VERSION 5.8 ;
BUSBITCHARS "[]" ;
DIVIDERCHAR "/" ;
UNITS
    DATABASE MICRONS 1000 ;
END UNITS

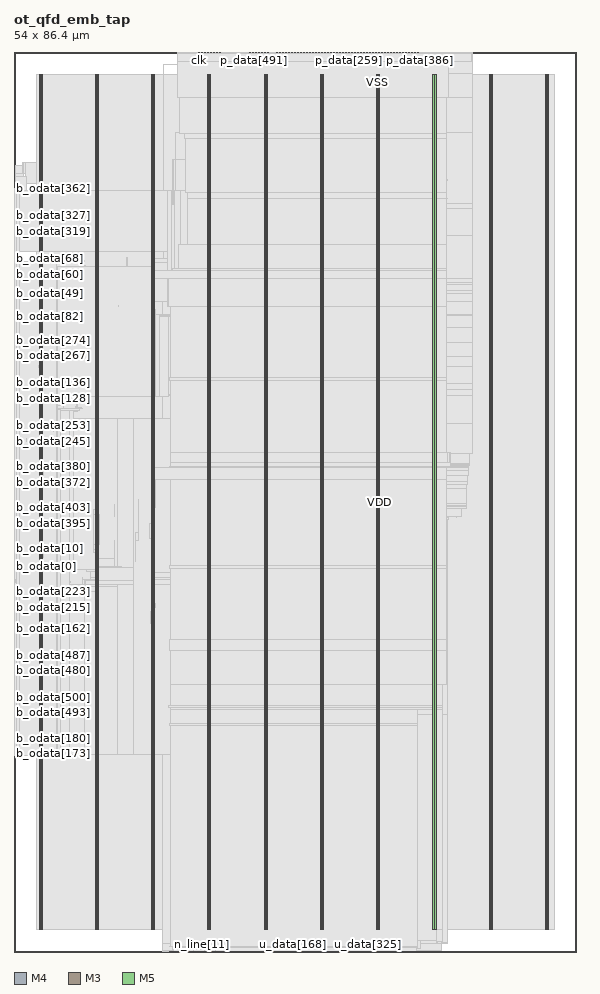
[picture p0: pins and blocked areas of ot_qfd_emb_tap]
MACRO ot_qfd_emb_tap
  FOREIGN ot_qfd_emb_tap 0 0 ;
  CLASS BLOCK ;
  SIZE 54 BY 86.4 ;
  PIN b_iaddr[0]
    DIRECTION OUTPUT ;
    USE SIGNAL ;
    PORT
      LAYER M4 ;
        RECT  0 34.992 0.084 35.016 ;
    END
  END b_iaddr[0]
  PIN b_iaddr[10]
    DIRECTION OUTPUT ;
    USE SIGNAL ;
    PORT
      LAYER M4 ;
        RECT  0 35.952 0.084 35.976 ;
    END
  END b_iaddr[10]
  PIN b_iaddr[11]
    DIRECTION OUTPUT ;
    USE SIGNAL ;
    PORT
      LAYER M4 ;
        RECT  0 36.048 0.084 36.072 ;
    END
  END b_iaddr[11]
  PIN b_iaddr[12]
    DIRECTION OUTPUT ;
    USE SIGNAL ;
    PORT
      LAYER M4 ;
        RECT  0 36.144 0.084 36.168 ;
    END
  END b_iaddr[12]
  PIN b_iaddr[13]
    DIRECTION OUTPUT ;
    USE SIGNAL ;
    PORT
      LAYER M4 ;
        RECT  0 36.24 0.084 36.264 ;
    END
  END b_iaddr[13]
  PIN b_iaddr[14]
    DIRECTION OUTPUT ;
    USE SIGNAL ;
    PORT
      LAYER M4 ;
        RECT  0 36.336 0.084 36.36 ;
    END
  END b_iaddr[14]
  PIN b_iaddr[15]
    DIRECTION OUTPUT ;
    USE SIGNAL ;
    PORT
      LAYER M4 ;
        RECT  0 36.432 0.084 36.456 ;
    END
  END b_iaddr[15]
  PIN b_iaddr[16]
    DIRECTION OUTPUT ;
    USE SIGNAL ;
    PORT
      LAYER M4 ;
        RECT  0 36.528 0.084 36.552 ;
    END
  END b_iaddr[16]
  PIN b_iaddr[17]
    DIRECTION OUTPUT ;
    USE SIGNAL ;
    PORT
      LAYER M4 ;
        RECT  0 36.624 0.084 36.648 ;
    END
  END b_iaddr[17]
  PIN b_iaddr[1]
    DIRECTION OUTPUT ;
    USE SIGNAL ;
    PORT
      LAYER M4 ;
        RECT  0 35.088 0.084 35.112 ;
    END
  END b_iaddr[1]
  PIN b_iaddr[2]
    DIRECTION OUTPUT ;
    USE SIGNAL ;
    PORT
      LAYER M4 ;
        RECT  0 35.184 0.084 35.208 ;
    END
  END b_iaddr[2]
  PIN b_iaddr[3]
    DIRECTION OUTPUT ;
    USE SIGNAL ;
    PORT
      LAYER M4 ;
        RECT  0 35.28 0.084 35.304 ;
    END
  END b_iaddr[3]
  PIN b_iaddr[4]
    DIRECTION OUTPUT ;
    USE SIGNAL ;
    PORT
      LAYER M4 ;
        RECT  0 35.376 0.084 35.4 ;
    END
  END b_iaddr[4]
  PIN b_iaddr[5]
    DIRECTION OUTPUT ;
    USE SIGNAL ;
    PORT
      LAYER M4 ;
        RECT  0 35.472 0.084 35.496 ;
    END
  END b_iaddr[5]
  PIN b_iaddr[6]
    DIRECTION OUTPUT ;
    USE SIGNAL ;
    PORT
      LAYER M4 ;
        RECT  0 35.568 0.084 35.592 ;
    END
  END b_iaddr[6]
  PIN b_iaddr[7]
    DIRECTION OUTPUT ;
    USE SIGNAL ;
    PORT
      LAYER M4 ;
        RECT  0 35.664 0.084 35.688 ;
    END
  END b_iaddr[7]
  PIN b_iaddr[8]
    DIRECTION OUTPUT ;
    USE SIGNAL ;
    PORT
      LAYER M4 ;
        RECT  0 35.76 0.084 35.784 ;
    END
  END b_iaddr[8]
  PIN b_iaddr[9]
    DIRECTION OUTPUT ;
    USE SIGNAL ;
    PORT
      LAYER M4 ;
        RECT  0 35.856 0.084 35.88 ;
    END
  END b_iaddr[9]
  PIN b_icr
    DIRECTION INPUT ;
    USE SIGNAL ;
    PORT
      LAYER M4 ;
        RECT  0 36.72 0.084 36.744 ;
    END
  END b_icr
  PIN b_iv
    DIRECTION OUTPUT ;
    USE SIGNAL ;
    PORT
      LAYER M4 ;
        RECT  0 36.816 0.084 36.84 ;
    END
  END b_iv
  PIN b_ocr
    DIRECTION OUTPUT ;
    USE SIGNAL ;
    PORT
      LAYER M4 ;
        RECT  0 36.912 0.084 36.936 ;
    END
  END b_ocr
  PIN b_odata[0]
    DIRECTION INPUT ;
    USE SIGNAL ;
    PORT
      LAYER M4 ;
        RECT  0 37.008 0.084 37.032 ;
    END
  END b_odata[0]
  PIN b_odata[100]
    DIRECTION INPUT ;
    USE SIGNAL ;
    PORT
      LAYER M4 ;
        RECT  0 62.736 0.084 62.76 ;
    END
  END b_odata[100]
  PIN b_odata[101]
    DIRECTION INPUT ;
    USE SIGNAL ;
    PORT
      LAYER M4 ;
        RECT  0 62.832 0.084 62.856 ;
    END
  END b_odata[101]
  PIN b_odata[102]
    DIRECTION INPUT ;
    USE SIGNAL ;
    PORT
      LAYER M4 ;
        RECT  0 62.928 0.084 62.952 ;
    END
  END b_odata[102]
  PIN b_odata[103]
    DIRECTION INPUT ;
    USE SIGNAL ;
    PORT
      LAYER M4 ;
        RECT  0 63.024 0.084 63.048 ;
    END
  END b_odata[103]
  PIN b_odata[104]
    DIRECTION INPUT ;
    USE SIGNAL ;
    PORT
      LAYER M4 ;
        RECT  0 63.12 0.084 63.144 ;
    END
  END b_odata[104]
  PIN b_odata[105]
    DIRECTION INPUT ;
    USE SIGNAL ;
    PORT
      LAYER M4 ;
        RECT  0 63.216 0.084 63.24 ;
    END
  END b_odata[105]
  PIN b_odata[106]
    DIRECTION INPUT ;
    USE SIGNAL ;
    PORT
      LAYER M4 ;
        RECT  0 63.312 0.084 63.336 ;
    END
  END b_odata[106]
  PIN b_odata[107]
    DIRECTION INPUT ;
    USE SIGNAL ;
    PORT
      LAYER M4 ;
        RECT  0 51.12 0.084 51.144 ;
    END
  END b_odata[107]
  PIN b_odata[108]
    DIRECTION INPUT ;
    USE SIGNAL ;
    PORT
      LAYER M4 ;
        RECT  0 51.216 0.084 51.24 ;
    END
  END b_odata[108]
  PIN b_odata[109]
    DIRECTION INPUT ;
    USE SIGNAL ;
    PORT
      LAYER M4 ;
        RECT  0 51.312 0.084 51.336 ;
    END
  END b_odata[109]
  PIN b_odata[10]
    DIRECTION INPUT ;
    USE SIGNAL ;
    PORT
      LAYER M4 ;
        RECT  0 37.968 0.084 37.992 ;
    END
  END b_odata[10]
  PIN b_odata[110]
    DIRECTION INPUT ;
    USE SIGNAL ;
    PORT
      LAYER M4 ;
        RECT  0 51.408 0.084 51.432 ;
    END
  END b_odata[110]
  PIN b_odata[111]
    DIRECTION INPUT ;
    USE SIGNAL ;
    PORT
      LAYER M4 ;
        RECT  0 51.504 0.084 51.528 ;
    END
  END b_odata[111]
  PIN b_odata[112]
    DIRECTION INPUT ;
    USE SIGNAL ;
    PORT
      LAYER M4 ;
        RECT  0 51.6 0.084 51.624 ;
    END
  END b_odata[112]
  PIN b_odata[113]
    DIRECTION INPUT ;
    USE SIGNAL ;
    PORT
      LAYER M4 ;
        RECT  0 51.696 0.084 51.72 ;
    END
  END b_odata[113]
  PIN b_odata[114]
    DIRECTION INPUT ;
    USE SIGNAL ;
    PORT
      LAYER M4 ;
        RECT  0 51.792 0.084 51.816 ;
    END
  END b_odata[114]
  PIN b_odata[115]
    DIRECTION INPUT ;
    USE SIGNAL ;
    PORT
      LAYER M4 ;
        RECT  0 51.888 0.084 51.912 ;
    END
  END b_odata[115]
  PIN b_odata[116]
    DIRECTION INPUT ;
    USE SIGNAL ;
    PORT
      LAYER M4 ;
        RECT  0 51.984 0.084 52.008 ;
    END
  END b_odata[116]
  PIN b_odata[117]
    DIRECTION INPUT ;
    USE SIGNAL ;
    PORT
      LAYER M4 ;
        RECT  0 52.08 0.084 52.104 ;
    END
  END b_odata[117]
  PIN b_odata[118]
    DIRECTION INPUT ;
    USE SIGNAL ;
    PORT
      LAYER M4 ;
        RECT  0 52.176 0.084 52.2 ;
    END
  END b_odata[118]
  PIN b_odata[119]
    DIRECTION INPUT ;
    USE SIGNAL ;
    PORT
      LAYER M4 ;
        RECT  0 52.272 0.084 52.296 ;
    END
  END b_odata[119]
  PIN b_odata[11]
    DIRECTION INPUT ;
    USE SIGNAL ;
    PORT
      LAYER M4 ;
        RECT  0 54.192 0.084 54.216 ;
    END
  END b_odata[11]
  PIN b_odata[120]
    DIRECTION INPUT ;
    USE SIGNAL ;
    PORT
      LAYER M4 ;
        RECT  0 52.368 0.084 52.392 ;
    END
  END b_odata[120]
  PIN b_odata[121]
    DIRECTION INPUT ;
    USE SIGNAL ;
    PORT
      LAYER M4 ;
        RECT  0 52.464 0.084 52.488 ;
    END
  END b_odata[121]
  PIN b_odata[122]
    DIRECTION INPUT ;
    USE SIGNAL ;
    PORT
      LAYER M4 ;
        RECT  0 52.56 0.084 52.584 ;
    END
  END b_odata[122]
  PIN b_odata[123]
    DIRECTION INPUT ;
    USE SIGNAL ;
    PORT
      LAYER M4 ;
        RECT  0 52.656 0.084 52.68 ;
    END
  END b_odata[123]
  PIN b_odata[124]
    DIRECTION INPUT ;
    USE SIGNAL ;
    PORT
      LAYER M4 ;
        RECT  0 52.752 0.084 52.776 ;
    END
  END b_odata[124]
  PIN b_odata[125]
    DIRECTION INPUT ;
    USE SIGNAL ;
    PORT
      LAYER M4 ;
        RECT  0 52.848 0.084 52.872 ;
    END
  END b_odata[125]
  PIN b_odata[126]
    DIRECTION INPUT ;
    USE SIGNAL ;
    PORT
      LAYER M4 ;
        RECT  0 52.944 0.084 52.968 ;
    END
  END b_odata[126]
  PIN b_odata[127]
    DIRECTION INPUT ;
    USE SIGNAL ;
    PORT
      LAYER M4 ;
        RECT  0 53.04 0.084 53.064 ;
    END
  END b_odata[127]
  PIN b_odata[128]
    DIRECTION INPUT ;
    USE SIGNAL ;
    PORT
      LAYER M4 ;
        RECT  0 53.136 0.084 53.16 ;
    END
  END b_odata[128]
  PIN b_odata[129]
    DIRECTION INPUT ;
    USE SIGNAL ;
    PORT
      LAYER M4 ;
        RECT  0 53.232 0.084 53.256 ;
    END
  END b_odata[129]
  PIN b_odata[12]
    DIRECTION INPUT ;
    USE SIGNAL ;
    PORT
      LAYER M4 ;
        RECT  0 54.288 0.084 54.312 ;
    END
  END b_odata[12]
  PIN b_odata[130]
    DIRECTION INPUT ;
    USE SIGNAL ;
    PORT
      LAYER M4 ;
        RECT  0 53.328 0.084 53.352 ;
    END
  END b_odata[130]
  PIN b_odata[131]
    DIRECTION INPUT ;
    USE SIGNAL ;
    PORT
      LAYER M4 ;
        RECT  0 53.424 0.084 53.448 ;
    END
  END b_odata[131]
  PIN b_odata[132]
    DIRECTION INPUT ;
    USE SIGNAL ;
    PORT
      LAYER M4 ;
        RECT  0 53.52 0.084 53.544 ;
    END
  END b_odata[132]
  PIN b_odata[133]
    DIRECTION INPUT ;
    USE SIGNAL ;
    PORT
      LAYER M4 ;
        RECT  0 53.616 0.084 53.64 ;
    END
  END b_odata[133]
  PIN b_odata[134]
    DIRECTION INPUT ;
    USE SIGNAL ;
    PORT
      LAYER M4 ;
        RECT  0 53.712 0.084 53.736 ;
    END
  END b_odata[134]
  PIN b_odata[135]
    DIRECTION INPUT ;
    USE SIGNAL ;
    PORT
      LAYER M4 ;
        RECT  0 53.808 0.084 53.832 ;
    END
  END b_odata[135]
  PIN b_odata[136]
    DIRECTION INPUT ;
    USE SIGNAL ;
    PORT
      LAYER M4 ;
        RECT  0 53.904 0.084 53.928 ;
    END
  END b_odata[136]
  PIN b_odata[137]
    DIRECTION INPUT ;
    USE SIGNAL ;
    PORT
      LAYER M4 ;
        RECT  0 54 0.084 54.024 ;
    END
  END b_odata[137]
  PIN b_odata[138]
    DIRECTION INPUT ;
    USE SIGNAL ;
    PORT
      LAYER M4 ;
        RECT  0 54.096 0.084 54.12 ;
    END
  END b_odata[138]
  PIN b_odata[139]
    DIRECTION INPUT ;
    USE SIGNAL ;
    PORT
      LAYER M4 ;
        RECT  0 28.848 0.084 28.872 ;
    END
  END b_odata[139]
  PIN b_odata[13]
    DIRECTION INPUT ;
    USE SIGNAL ;
    PORT
      LAYER M4 ;
        RECT  0 54.384 0.084 54.408 ;
    END
  END b_odata[13]
  PIN b_odata[140]
    DIRECTION INPUT ;
    USE SIGNAL ;
    PORT
      LAYER M4 ;
        RECT  0 28.944 0.084 28.968 ;
    END
  END b_odata[140]
  PIN b_odata[141]
    DIRECTION INPUT ;
    USE SIGNAL ;
    PORT
      LAYER M4 ;
        RECT  0 29.04 0.084 29.064 ;
    END
  END b_odata[141]
  PIN b_odata[142]
    DIRECTION INPUT ;
    USE SIGNAL ;
    PORT
      LAYER M4 ;
        RECT  0 29.136 0.084 29.16 ;
    END
  END b_odata[142]
  PIN b_odata[143]
    DIRECTION INPUT ;
    USE SIGNAL ;
    PORT
      LAYER M4 ;
        RECT  0 29.232 0.084 29.256 ;
    END
  END b_odata[143]
  PIN b_odata[144]
    DIRECTION INPUT ;
    USE SIGNAL ;
    PORT
      LAYER M4 ;
        RECT  0 29.328 0.084 29.352 ;
    END
  END b_odata[144]
  PIN b_odata[145]
    DIRECTION INPUT ;
    USE SIGNAL ;
    PORT
      LAYER M4 ;
        RECT  0 29.424 0.084 29.448 ;
    END
  END b_odata[145]
  PIN b_odata[146]
    DIRECTION INPUT ;
    USE SIGNAL ;
    PORT
      LAYER M4 ;
        RECT  0 29.52 0.084 29.544 ;
    END
  END b_odata[146]
  PIN b_odata[147]
    DIRECTION INPUT ;
    USE SIGNAL ;
    PORT
      LAYER M4 ;
        RECT  0 29.616 0.084 29.64 ;
    END
  END b_odata[147]
  PIN b_odata[148]
    DIRECTION INPUT ;
    USE SIGNAL ;
    PORT
      LAYER M4 ;
        RECT  0 29.712 0.084 29.736 ;
    END
  END b_odata[148]
  PIN b_odata[149]
    DIRECTION INPUT ;
    USE SIGNAL ;
    PORT
      LAYER M4 ;
        RECT  0 29.808 0.084 29.832 ;
    END
  END b_odata[149]
  PIN b_odata[14]
    DIRECTION INPUT ;
    USE SIGNAL ;
    PORT
      LAYER M4 ;
        RECT  0 54.48 0.084 54.504 ;
    END
  END b_odata[14]
  PIN b_odata[150]
    DIRECTION INPUT ;
    USE SIGNAL ;
    PORT
      LAYER M4 ;
        RECT  0 29.904 0.084 29.928 ;
    END
  END b_odata[150]
  PIN b_odata[151]
    DIRECTION INPUT ;
    USE SIGNAL ;
    PORT
      LAYER M4 ;
        RECT  0 30 0.084 30.024 ;
    END
  END b_odata[151]
  PIN b_odata[152]
    DIRECTION INPUT ;
    USE SIGNAL ;
    PORT
      LAYER M4 ;
        RECT  0 30.096 0.084 30.12 ;
    END
  END b_odata[152]
  PIN b_odata[153]
    DIRECTION INPUT ;
    USE SIGNAL ;
    PORT
      LAYER M4 ;
        RECT  0 30.192 0.084 30.216 ;
    END
  END b_odata[153]
  PIN b_odata[154]
    DIRECTION INPUT ;
    USE SIGNAL ;
    PORT
      LAYER M4 ;
        RECT  0 30.288 0.084 30.312 ;
    END
  END b_odata[154]
  PIN b_odata[155]
    DIRECTION INPUT ;
    USE SIGNAL ;
    PORT
      LAYER M4 ;
        RECT  0 30.384 0.084 30.408 ;
    END
  END b_odata[155]
  PIN b_odata[156]
    DIRECTION INPUT ;
    USE SIGNAL ;
    PORT
      LAYER M4 ;
        RECT  0 30.48 0.084 30.504 ;
    END
  END b_odata[156]
  PIN b_odata[157]
    DIRECTION INPUT ;
    USE SIGNAL ;
    PORT
      LAYER M4 ;
        RECT  0 30.576 0.084 30.6 ;
    END
  END b_odata[157]
  PIN b_odata[158]
    DIRECTION INPUT ;
    USE SIGNAL ;
    PORT
      LAYER M4 ;
        RECT  0 30.672 0.084 30.696 ;
    END
  END b_odata[158]
  PIN b_odata[159]
    DIRECTION INPUT ;
    USE SIGNAL ;
    PORT
      LAYER M4 ;
        RECT  0 30.768 0.084 30.792 ;
    END
  END b_odata[159]
  PIN b_odata[15]
    DIRECTION INPUT ;
    USE SIGNAL ;
    PORT
      LAYER M4 ;
        RECT  0 54.576 0.084 54.6 ;
    END
  END b_odata[15]
  PIN b_odata[160]
    DIRECTION INPUT ;
    USE SIGNAL ;
    PORT
      LAYER M4 ;
        RECT  0 30.864 0.084 30.888 ;
    END
  END b_odata[160]
  PIN b_odata[161]
    DIRECTION INPUT ;
    USE SIGNAL ;
    PORT
      LAYER M4 ;
        RECT  0 30.96 0.084 30.984 ;
    END
  END b_odata[161]
  PIN b_odata[162]
    DIRECTION INPUT ;
    USE SIGNAL ;
    PORT
      LAYER M4 ;
        RECT  0 31.056 0.084 31.08 ;
    END
  END b_odata[162]
  PIN b_odata[163]
    DIRECTION INPUT ;
    USE SIGNAL ;
    PORT
      LAYER M4 ;
        RECT  0 31.152 0.084 31.176 ;
    END
  END b_odata[163]
  PIN b_odata[164]
    DIRECTION INPUT ;
    USE SIGNAL ;
    PORT
      LAYER M4 ;
        RECT  0 31.248 0.084 31.272 ;
    END
  END b_odata[164]
  PIN b_odata[165]
    DIRECTION INPUT ;
    USE SIGNAL ;
    PORT
      LAYER M4 ;
        RECT  0 31.344 0.084 31.368 ;
    END
  END b_odata[165]
  PIN b_odata[166]
    DIRECTION INPUT ;
    USE SIGNAL ;
    PORT
      LAYER M4 ;
        RECT  0 31.44 0.084 31.464 ;
    END
  END b_odata[166]
  PIN b_odata[167]
    DIRECTION INPUT ;
    USE SIGNAL ;
    PORT
      LAYER M4 ;
        RECT  0 31.536 0.084 31.56 ;
    END
  END b_odata[167]
  PIN b_odata[168]
    DIRECTION INPUT ;
    USE SIGNAL ;
    PORT
      LAYER M4 ;
        RECT  0 31.632 0.084 31.656 ;
    END
  END b_odata[168]
  PIN b_odata[169]
    DIRECTION INPUT ;
    USE SIGNAL ;
    PORT
      LAYER M4 ;
        RECT  0 31.728 0.084 31.752 ;
    END
  END b_odata[169]
  PIN b_odata[16]
    DIRECTION INPUT ;
    USE SIGNAL ;
    PORT
      LAYER M4 ;
        RECT  0 54.672 0.084 54.696 ;
    END
  END b_odata[16]
  PIN b_odata[170]
    DIRECTION INPUT ;
    USE SIGNAL ;
    PORT
      LAYER M4 ;
        RECT  0 31.824 0.084 31.848 ;
    END
  END b_odata[170]
  PIN b_odata[171]
    DIRECTION INPUT ;
    USE SIGNAL ;
    PORT
      LAYER M4 ;
        RECT  0 18.864 0.084 18.888 ;
    END
  END b_odata[171]
  PIN b_odata[172]
    DIRECTION INPUT ;
    USE SIGNAL ;
    PORT
      LAYER M4 ;
        RECT  0 18.96 0.084 18.984 ;
    END
  END b_odata[172]
  PIN b_odata[173]
    DIRECTION INPUT ;
    USE SIGNAL ;
    PORT
      LAYER M4 ;
        RECT  0 19.056 0.084 19.08 ;
    END
  END b_odata[173]
  PIN b_odata[174]
    DIRECTION INPUT ;
    USE SIGNAL ;
    PORT
      LAYER M4 ;
        RECT  0 19.152 0.084 19.176 ;
    END
  END b_odata[174]
  PIN b_odata[175]
    DIRECTION INPUT ;
    USE SIGNAL ;
    PORT
      LAYER M4 ;
        RECT  0 19.248 0.084 19.272 ;
    END
  END b_odata[175]
  PIN b_odata[176]
    DIRECTION INPUT ;
    USE SIGNAL ;
    PORT
      LAYER M4 ;
        RECT  0 19.344 0.084 19.368 ;
    END
  END b_odata[176]
  PIN b_odata[177]
    DIRECTION INPUT ;
    USE SIGNAL ;
    PORT
      LAYER M4 ;
        RECT  0 19.44 0.084 19.464 ;
    END
  END b_odata[177]
  PIN b_odata[178]
    DIRECTION INPUT ;
    USE SIGNAL ;
    PORT
      LAYER M4 ;
        RECT  0 19.536 0.084 19.56 ;
    END
  END b_odata[178]
  PIN b_odata[179]
    DIRECTION INPUT ;
    USE SIGNAL ;
    PORT
      LAYER M4 ;
        RECT  0 19.632 0.084 19.656 ;
    END
  END b_odata[179]
  PIN b_odata[17]
    DIRECTION INPUT ;
    USE SIGNAL ;
    PORT
      LAYER M4 ;
        RECT  0 54.768 0.084 54.792 ;
    END
  END b_odata[17]
  PIN b_odata[180]
    DIRECTION INPUT ;
    USE SIGNAL ;
    PORT
      LAYER M4 ;
        RECT  0 19.728 0.084 19.752 ;
    END
  END b_odata[180]
  PIN b_odata[181]
    DIRECTION INPUT ;
    USE SIGNAL ;
    PORT
      LAYER M4 ;
        RECT  0 19.824 0.084 19.848 ;
    END
  END b_odata[181]
  PIN b_odata[182]
    DIRECTION INPUT ;
    USE SIGNAL ;
    PORT
      LAYER M4 ;
        RECT  0 19.92 0.084 19.944 ;
    END
  END b_odata[182]
  PIN b_odata[183]
    DIRECTION INPUT ;
    USE SIGNAL ;
    PORT
      LAYER M4 ;
        RECT  0 20.016 0.084 20.04 ;
    END
  END b_odata[183]
  PIN b_odata[184]
    DIRECTION INPUT ;
    USE SIGNAL ;
    PORT
      LAYER M4 ;
        RECT  0 20.112 0.084 20.136 ;
    END
  END b_odata[184]
  PIN b_odata[185]
    DIRECTION INPUT ;
    USE SIGNAL ;
    PORT
      LAYER M4 ;
        RECT  0 20.208 0.084 20.232 ;
    END
  END b_odata[185]
  PIN b_odata[186]
    DIRECTION INPUT ;
    USE SIGNAL ;
    PORT
      LAYER M4 ;
        RECT  0 20.304 0.084 20.328 ;
    END
  END b_odata[186]
  PIN b_odata[187]
    DIRECTION INPUT ;
    USE SIGNAL ;
    PORT
      LAYER M4 ;
        RECT  0 20.4 0.084 20.424 ;
    END
  END b_odata[187]
  PIN b_odata[188]
    DIRECTION INPUT ;
    USE SIGNAL ;
    PORT
      LAYER M4 ;
        RECT  0 20.496 0.084 20.52 ;
    END
  END b_odata[188]
  PIN b_odata[189]
    DIRECTION INPUT ;
    USE SIGNAL ;
    PORT
      LAYER M4 ;
        RECT  0 20.592 0.084 20.616 ;
    END
  END b_odata[189]
  PIN b_odata[18]
    DIRECTION INPUT ;
    USE SIGNAL ;
    PORT
      LAYER M4 ;
        RECT  0 54.864 0.084 54.888 ;
    END
  END b_odata[18]
  PIN b_odata[190]
    DIRECTION INPUT ;
    USE SIGNAL ;
    PORT
      LAYER M4 ;
        RECT  0 20.688 0.084 20.712 ;
    END
  END b_odata[190]
  PIN b_odata[191]
    DIRECTION INPUT ;
    USE SIGNAL ;
    PORT
      LAYER M4 ;
        RECT  0 20.784 0.084 20.808 ;
    END
  END b_odata[191]
  PIN b_odata[192]
    DIRECTION INPUT ;
    USE SIGNAL ;
    PORT
      LAYER M4 ;
        RECT  0 20.88 0.084 20.904 ;
    END
  END b_odata[192]
  PIN b_odata[193]
    DIRECTION INPUT ;
    USE SIGNAL ;
    PORT
      LAYER M4 ;
        RECT  0 20.976 0.084 21 ;
    END
  END b_odata[193]
  PIN b_odata[194]
    DIRECTION INPUT ;
    USE SIGNAL ;
    PORT
      LAYER M4 ;
        RECT  0 21.072 0.084 21.096 ;
    END
  END b_odata[194]
  PIN b_odata[195]
    DIRECTION INPUT ;
    USE SIGNAL ;
    PORT
      LAYER M4 ;
        RECT  0 21.168 0.084 21.192 ;
    END
  END b_odata[195]
  PIN b_odata[196]
    DIRECTION INPUT ;
    USE SIGNAL ;
    PORT
      LAYER M4 ;
        RECT  0 21.264 0.084 21.288 ;
    END
  END b_odata[196]
  PIN b_odata[197]
    DIRECTION INPUT ;
    USE SIGNAL ;
    PORT
      LAYER M4 ;
        RECT  0 21.36 0.084 21.384 ;
    END
  END b_odata[197]
  PIN b_odata[198]
    DIRECTION INPUT ;
    USE SIGNAL ;
    PORT
      LAYER M4 ;
        RECT  0 21.456 0.084 21.48 ;
    END
  END b_odata[198]
  PIN b_odata[199]
    DIRECTION INPUT ;
    USE SIGNAL ;
    PORT
      LAYER M4 ;
        RECT  0 21.552 0.084 21.576 ;
    END
  END b_odata[199]
  PIN b_odata[19]
    DIRECTION INPUT ;
    USE SIGNAL ;
    PORT
      LAYER M4 ;
        RECT  0 54.96 0.084 54.984 ;
    END
  END b_odata[19]
  PIN b_odata[1]
    DIRECTION INPUT ;
    USE SIGNAL ;
    PORT
      LAYER M4 ;
        RECT  0 37.104 0.084 37.128 ;
    END
  END b_odata[1]
  PIN b_odata[200]
    DIRECTION INPUT ;
    USE SIGNAL ;
    PORT
      LAYER M4 ;
        RECT  0 21.648 0.084 21.672 ;
    END
  END b_odata[200]
  PIN b_odata[201]
    DIRECTION INPUT ;
    USE SIGNAL ;
    PORT
      LAYER M4 ;
        RECT  0 21.744 0.084 21.768 ;
    END
  END b_odata[201]
  PIN b_odata[202]
    DIRECTION INPUT ;
    USE SIGNAL ;
    PORT
      LAYER M4 ;
        RECT  0 21.84 0.084 21.864 ;
    END
  END b_odata[202]
  PIN b_odata[203]
    DIRECTION INPUT ;
    USE SIGNAL ;
    PORT
      LAYER M4 ;
        RECT  0 31.92 0.084 31.944 ;
    END
  END b_odata[203]
  PIN b_odata[204]
    DIRECTION INPUT ;
    USE SIGNAL ;
    PORT
      LAYER M4 ;
        RECT  0 32.016 0.084 32.04 ;
    END
  END b_odata[204]
  PIN b_odata[205]
    DIRECTION INPUT ;
    USE SIGNAL ;
    PORT
      LAYER M4 ;
        RECT  0 32.112 0.084 32.136 ;
    END
  END b_odata[205]
  PIN b_odata[206]
    DIRECTION INPUT ;
    USE SIGNAL ;
    PORT
      LAYER M4 ;
        RECT  0 32.208 0.084 32.232 ;
    END
  END b_odata[206]
  PIN b_odata[207]
    DIRECTION INPUT ;
    USE SIGNAL ;
    PORT
      LAYER M4 ;
        RECT  0 32.304 0.084 32.328 ;
    END
  END b_odata[207]
  PIN b_odata[208]
    DIRECTION INPUT ;
    USE SIGNAL ;
    PORT
      LAYER M4 ;
        RECT  0 32.4 0.084 32.424 ;
    END
  END b_odata[208]
  PIN b_odata[209]
    DIRECTION INPUT ;
    USE SIGNAL ;
    PORT
      LAYER M4 ;
        RECT  0 32.496 0.084 32.52 ;
    END
  END b_odata[209]
  PIN b_odata[20]
    DIRECTION INPUT ;
    USE SIGNAL ;
    PORT
      LAYER M4 ;
        RECT  0 55.056 0.084 55.08 ;
    END
  END b_odata[20]
  PIN b_odata[210]
    DIRECTION INPUT ;
    USE SIGNAL ;
    PORT
      LAYER M4 ;
        RECT  0 32.592 0.084 32.616 ;
    END
  END b_odata[210]
  PIN b_odata[211]
    DIRECTION INPUT ;
    USE SIGNAL ;
    PORT
      LAYER M4 ;
        RECT  0 32.688 0.084 32.712 ;
    END
  END b_odata[211]
  PIN b_odata[212]
    DIRECTION INPUT ;
    USE SIGNAL ;
    PORT
      LAYER M4 ;
        RECT  0 32.784 0.084 32.808 ;
    END
  END b_odata[212]
  PIN b_odata[213]
    DIRECTION INPUT ;
    USE SIGNAL ;
    PORT
      LAYER M4 ;
        RECT  0 32.88 0.084 32.904 ;
    END
  END b_odata[213]
  PIN b_odata[214]
    DIRECTION INPUT ;
    USE SIGNAL ;
    PORT
      LAYER M4 ;
        RECT  0 32.976 0.084 33 ;
    END
  END b_odata[214]
  PIN b_odata[215]
    DIRECTION INPUT ;
    USE SIGNAL ;
    PORT
      LAYER M4 ;
        RECT  0 33.072 0.084 33.096 ;
    END
  END b_odata[215]
  PIN b_odata[216]
    DIRECTION INPUT ;
    USE SIGNAL ;
    PORT
      LAYER M4 ;
        RECT  0 33.168 0.084 33.192 ;
    END
  END b_odata[216]
  PIN b_odata[217]
    DIRECTION INPUT ;
    USE SIGNAL ;
    PORT
      LAYER M4 ;
        RECT  0 33.264 0.084 33.288 ;
    END
  END b_odata[217]
  PIN b_odata[218]
    DIRECTION INPUT ;
    USE SIGNAL ;
    PORT
      LAYER M4 ;
        RECT  0 33.36 0.084 33.384 ;
    END
  END b_odata[218]
  PIN b_odata[219]
    DIRECTION INPUT ;
    USE SIGNAL ;
    PORT
      LAYER M4 ;
        RECT  0 33.456 0.084 33.48 ;
    END
  END b_odata[219]
  PIN b_odata[21]
    DIRECTION INPUT ;
    USE SIGNAL ;
    PORT
      LAYER M4 ;
        RECT  0 55.152 0.084 55.176 ;
    END
  END b_odata[21]
  PIN b_odata[220]
    DIRECTION INPUT ;
    USE SIGNAL ;
    PORT
      LAYER M4 ;
        RECT  0 33.552 0.084 33.576 ;
    END
  END b_odata[220]
  PIN b_odata[221]
    DIRECTION INPUT ;
    USE SIGNAL ;
    PORT
      LAYER M4 ;
        RECT  0 33.648 0.084 33.672 ;
    END
  END b_odata[221]
  PIN b_odata[222]
    DIRECTION INPUT ;
    USE SIGNAL ;
    PORT
      LAYER M4 ;
        RECT  0 33.744 0.084 33.768 ;
    END
  END b_odata[222]
  PIN b_odata[223]
    DIRECTION INPUT ;
    USE SIGNAL ;
    PORT
      LAYER M4 ;
        RECT  0 33.84 0.084 33.864 ;
    END
  END b_odata[223]
  PIN b_odata[224]
    DIRECTION INPUT ;
    USE SIGNAL ;
    PORT
      LAYER M4 ;
        RECT  0 33.936 0.084 33.96 ;
    END
  END b_odata[224]
  PIN b_odata[225]
    DIRECTION INPUT ;
    USE SIGNAL ;
    PORT
      LAYER M4 ;
        RECT  0 34.032 0.084 34.056 ;
    END
  END b_odata[225]
  PIN b_odata[226]
    DIRECTION INPUT ;
    USE SIGNAL ;
    PORT
      LAYER M4 ;
        RECT  0 34.128 0.084 34.152 ;
    END
  END b_odata[226]
  PIN b_odata[227]
    DIRECTION INPUT ;
    USE SIGNAL ;
    PORT
      LAYER M4 ;
        RECT  0 34.224 0.084 34.248 ;
    END
  END b_odata[227]
  PIN b_odata[228]
    DIRECTION INPUT ;
    USE SIGNAL ;
    PORT
      LAYER M4 ;
        RECT  0 34.32 0.084 34.344 ;
    END
  END b_odata[228]
  PIN b_odata[229]
    DIRECTION INPUT ;
    USE SIGNAL ;
    PORT
      LAYER M4 ;
        RECT  0 34.416 0.084 34.44 ;
    END
  END b_odata[229]
  PIN b_odata[22]
    DIRECTION INPUT ;
    USE SIGNAL ;
    PORT
      LAYER M4 ;
        RECT  0 55.248 0.084 55.272 ;
    END
  END b_odata[22]
  PIN b_odata[230]
    DIRECTION INPUT ;
    USE SIGNAL ;
    PORT
      LAYER M4 ;
        RECT  0 34.512 0.084 34.536 ;
    END
  END b_odata[230]
  PIN b_odata[231]
    DIRECTION INPUT ;
    USE SIGNAL ;
    PORT
      LAYER M4 ;
        RECT  0 34.608 0.084 34.632 ;
    END
  END b_odata[231]
  PIN b_odata[232]
    DIRECTION INPUT ;
    USE SIGNAL ;
    PORT
      LAYER M4 ;
        RECT  0 34.704 0.084 34.728 ;
    END
  END b_odata[232]
  PIN b_odata[233]
    DIRECTION INPUT ;
    USE SIGNAL ;
    PORT
      LAYER M4 ;
        RECT  0 34.8 0.084 34.824 ;
    END
  END b_odata[233]
  PIN b_odata[234]
    DIRECTION INPUT ;
    USE SIGNAL ;
    PORT
      LAYER M4 ;
        RECT  0 34.896 0.084 34.92 ;
    END
  END b_odata[234]
  PIN b_odata[235]
    DIRECTION INPUT ;
    USE SIGNAL ;
    PORT
      LAYER M4 ;
        RECT  0 48.048 0.084 48.072 ;
    END
  END b_odata[235]
  PIN b_odata[236]
    DIRECTION INPUT ;
    USE SIGNAL ;
    PORT
      LAYER M4 ;
        RECT  0 48.144 0.084 48.168 ;
    END
  END b_odata[236]
  PIN b_odata[237]
    DIRECTION INPUT ;
    USE SIGNAL ;
    PORT
      LAYER M4 ;
        RECT  0 48.24 0.084 48.264 ;
    END
  END b_odata[237]
  PIN b_odata[238]
    DIRECTION INPUT ;
    USE SIGNAL ;
    PORT
      LAYER M4 ;
        RECT  0 48.336 0.084 48.36 ;
    END
  END b_odata[238]
  PIN b_odata[239]
    DIRECTION INPUT ;
    USE SIGNAL ;
    PORT
      LAYER M4 ;
        RECT  0 48.432 0.084 48.456 ;
    END
  END b_odata[239]
  PIN b_odata[23]
    DIRECTION INPUT ;
    USE SIGNAL ;
    PORT
      LAYER M4 ;
        RECT  0 55.344 0.084 55.368 ;
    END
  END b_odata[23]
  PIN b_odata[240]
    DIRECTION INPUT ;
    USE SIGNAL ;
    PORT
      LAYER M4 ;
        RECT  0 48.528 0.084 48.552 ;
    END
  END b_odata[240]
  PIN b_odata[241]
    DIRECTION INPUT ;
    USE SIGNAL ;
    PORT
      LAYER M4 ;
        RECT  0 48.624 0.084 48.648 ;
    END
  END b_odata[241]
  PIN b_odata[242]
    DIRECTION INPUT ;
    USE SIGNAL ;
    PORT
      LAYER M4 ;
        RECT  0 48.72 0.084 48.744 ;
    END
  END b_odata[242]
  PIN b_odata[243]
    DIRECTION INPUT ;
    USE SIGNAL ;
    PORT
      LAYER M4 ;
        RECT  0 48.816 0.084 48.84 ;
    END
  END b_odata[243]
  PIN b_odata[244]
    DIRECTION INPUT ;
    USE SIGNAL ;
    PORT
      LAYER M4 ;
        RECT  0 48.912 0.084 48.936 ;
    END
  END b_odata[244]
  PIN b_odata[245]
    DIRECTION INPUT ;
    USE SIGNAL ;
    PORT
      LAYER M4 ;
        RECT  0 49.008 0.084 49.032 ;
    END
  END b_odata[245]
  PIN b_odata[246]
    DIRECTION INPUT ;
    USE SIGNAL ;
    PORT
      LAYER M4 ;
        RECT  0 49.104 0.084 49.128 ;
    END
  END b_odata[246]
  PIN b_odata[247]
    DIRECTION INPUT ;
    USE SIGNAL ;
    PORT
      LAYER M4 ;
        RECT  0 49.2 0.084 49.224 ;
    END
  END b_odata[247]
  PIN b_odata[248]
    DIRECTION INPUT ;
    USE SIGNAL ;
    PORT
      LAYER M4 ;
        RECT  0 49.296 0.084 49.32 ;
    END
  END b_odata[248]
  PIN b_odata[249]
    DIRECTION INPUT ;
    USE SIGNAL ;
    PORT
      LAYER M4 ;
        RECT  0 49.392 0.084 49.416 ;
    END
  END b_odata[249]
  PIN b_odata[24]
    DIRECTION INPUT ;
    USE SIGNAL ;
    PORT
      LAYER M4 ;
        RECT  0 55.44 0.084 55.464 ;
    END
  END b_odata[24]
  PIN b_odata[250]
    DIRECTION INPUT ;
    USE SIGNAL ;
    PORT
      LAYER M4 ;
        RECT  0 49.488 0.084 49.512 ;
    END
  END b_odata[250]
  PIN b_odata[251]
    DIRECTION INPUT ;
    USE SIGNAL ;
    PORT
      LAYER M4 ;
        RECT  0 49.584 0.084 49.608 ;
    END
  END b_odata[251]
  PIN b_odata[252]
    DIRECTION INPUT ;
    USE SIGNAL ;
    PORT
      LAYER M4 ;
        RECT  0 49.68 0.084 49.704 ;
    END
  END b_odata[252]
  PIN b_odata[253]
    DIRECTION INPUT ;
    USE SIGNAL ;
    PORT
      LAYER M4 ;
        RECT  0 49.776 0.084 49.8 ;
    END
  END b_odata[253]
  PIN b_odata[254]
    DIRECTION INPUT ;
    USE SIGNAL ;
    PORT
      LAYER M4 ;
        RECT  0 49.872 0.084 49.896 ;
    END
  END b_odata[254]
  PIN b_odata[255]
    DIRECTION INPUT ;
    USE SIGNAL ;
    PORT
      LAYER M4 ;
        RECT  0 49.968 0.084 49.992 ;
    END
  END b_odata[255]
  PIN b_odata[256]
    DIRECTION INPUT ;
    USE SIGNAL ;
    PORT
      LAYER M4 ;
        RECT  0 50.064 0.084 50.088 ;
    END
  END b_odata[256]
  PIN b_odata[257]
    DIRECTION INPUT ;
    USE SIGNAL ;
    PORT
      LAYER M4 ;
        RECT  0 50.16 0.084 50.184 ;
    END
  END b_odata[257]
  PIN b_odata[258]
    DIRECTION INPUT ;
    USE SIGNAL ;
    PORT
      LAYER M4 ;
        RECT  0 50.256 0.084 50.28 ;
    END
  END b_odata[258]
  PIN b_odata[259]
    DIRECTION INPUT ;
    USE SIGNAL ;
    PORT
      LAYER M4 ;
        RECT  0 50.352 0.084 50.376 ;
    END
  END b_odata[259]
  PIN b_odata[25]
    DIRECTION INPUT ;
    USE SIGNAL ;
    PORT
      LAYER M4 ;
        RECT  0 55.536 0.084 55.56 ;
    END
  END b_odata[25]
  PIN b_odata[260]
    DIRECTION INPUT ;
    USE SIGNAL ;
    PORT
      LAYER M4 ;
        RECT  0 50.448 0.084 50.472 ;
    END
  END b_odata[260]
  PIN b_odata[261]
    DIRECTION INPUT ;
    USE SIGNAL ;
    PORT
      LAYER M4 ;
        RECT  0 50.544 0.084 50.568 ;
    END
  END b_odata[261]
  PIN b_odata[262]
    DIRECTION INPUT ;
    USE SIGNAL ;
    PORT
      LAYER M4 ;
        RECT  0 50.64 0.084 50.664 ;
    END
  END b_odata[262]
  PIN b_odata[263]
    DIRECTION INPUT ;
    USE SIGNAL ;
    PORT
      LAYER M4 ;
        RECT  0 50.736 0.084 50.76 ;
    END
  END b_odata[263]
  PIN b_odata[264]
    DIRECTION INPUT ;
    USE SIGNAL ;
    PORT
      LAYER M4 ;
        RECT  0 50.832 0.084 50.856 ;
    END
  END b_odata[264]
  PIN b_odata[265]
    DIRECTION INPUT ;
    USE SIGNAL ;
    PORT
      LAYER M4 ;
        RECT  0 50.928 0.084 50.952 ;
    END
  END b_odata[265]
  PIN b_odata[266]
    DIRECTION INPUT ;
    USE SIGNAL ;
    PORT
      LAYER M4 ;
        RECT  0 51.024 0.084 51.048 ;
    END
  END b_odata[266]
  PIN b_odata[267]
    DIRECTION INPUT ;
    USE SIGNAL ;
    PORT
      LAYER M4 ;
        RECT  0 57.264 0.084 57.288 ;
    END
  END b_odata[267]
  PIN b_odata[268]
    DIRECTION INPUT ;
    USE SIGNAL ;
    PORT
      LAYER M4 ;
        RECT  0 57.36 0.084 57.384 ;
    END
  END b_odata[268]
  PIN b_odata[269]
    DIRECTION INPUT ;
    USE SIGNAL ;
    PORT
      LAYER M4 ;
        RECT  0 57.456 0.084 57.48 ;
    END
  END b_odata[269]
  PIN b_odata[26]
    DIRECTION INPUT ;
    USE SIGNAL ;
    PORT
      LAYER M4 ;
        RECT  0 55.632 0.084 55.656 ;
    END
  END b_odata[26]
  PIN b_odata[270]
    DIRECTION INPUT ;
    USE SIGNAL ;
    PORT
      LAYER M4 ;
        RECT  0 57.552 0.084 57.576 ;
    END
  END b_odata[270]
  PIN b_odata[271]
    DIRECTION INPUT ;
    USE SIGNAL ;
    PORT
      LAYER M4 ;
        RECT  0 57.648 0.084 57.672 ;
    END
  END b_odata[271]
  PIN b_odata[272]
    DIRECTION INPUT ;
    USE SIGNAL ;
    PORT
      LAYER M4 ;
        RECT  0 57.744 0.084 57.768 ;
    END
  END b_odata[272]
  PIN b_odata[273]
    DIRECTION INPUT ;
    USE SIGNAL ;
    PORT
      LAYER M4 ;
        RECT  0 57.84 0.084 57.864 ;
    END
  END b_odata[273]
  PIN b_odata[274]
    DIRECTION INPUT ;
    USE SIGNAL ;
    PORT
      LAYER M4 ;
        RECT  0 57.936 0.084 57.96 ;
    END
  END b_odata[274]
  PIN b_odata[275]
    DIRECTION INPUT ;
    USE SIGNAL ;
    PORT
      LAYER M4 ;
        RECT  0 58.032 0.084 58.056 ;
    END
  END b_odata[275]
  PIN b_odata[276]
    DIRECTION INPUT ;
    USE SIGNAL ;
    PORT
      LAYER M4 ;
        RECT  0 58.128 0.084 58.152 ;
    END
  END b_odata[276]
  PIN b_odata[277]
    DIRECTION INPUT ;
    USE SIGNAL ;
    PORT
      LAYER M4 ;
        RECT  0 58.224 0.084 58.248 ;
    END
  END b_odata[277]
  PIN b_odata[278]
    DIRECTION INPUT ;
    USE SIGNAL ;
    PORT
      LAYER M4 ;
        RECT  0 58.32 0.084 58.344 ;
    END
  END b_odata[278]
  PIN b_odata[279]
    DIRECTION INPUT ;
    USE SIGNAL ;
    PORT
      LAYER M4 ;
        RECT  0 58.416 0.084 58.44 ;
    END
  END b_odata[279]
  PIN b_odata[27]
    DIRECTION INPUT ;
    USE SIGNAL ;
    PORT
      LAYER M4 ;
        RECT  0 55.728 0.084 55.752 ;
    END
  END b_odata[27]
  PIN b_odata[280]
    DIRECTION INPUT ;
    USE SIGNAL ;
    PORT
      LAYER M4 ;
        RECT  0 58.512 0.084 58.536 ;
    END
  END b_odata[280]
  PIN b_odata[281]
    DIRECTION INPUT ;
    USE SIGNAL ;
    PORT
      LAYER M4 ;
        RECT  0 58.608 0.084 58.632 ;
    END
  END b_odata[281]
  PIN b_odata[282]
    DIRECTION INPUT ;
    USE SIGNAL ;
    PORT
      LAYER M4 ;
        RECT  0 58.704 0.084 58.728 ;
    END
  END b_odata[282]
  PIN b_odata[283]
    DIRECTION INPUT ;
    USE SIGNAL ;
    PORT
      LAYER M4 ;
        RECT  0 58.8 0.084 58.824 ;
    END
  END b_odata[283]
  PIN b_odata[284]
    DIRECTION INPUT ;
    USE SIGNAL ;
    PORT
      LAYER M4 ;
        RECT  0 58.896 0.084 58.92 ;
    END
  END b_odata[284]
  PIN b_odata[285]
    DIRECTION INPUT ;
    USE SIGNAL ;
    PORT
      LAYER M4 ;
        RECT  0 58.992 0.084 59.016 ;
    END
  END b_odata[285]
  PIN b_odata[286]
    DIRECTION INPUT ;
    USE SIGNAL ;
    PORT
      LAYER M4 ;
        RECT  0 59.088 0.084 59.112 ;
    END
  END b_odata[286]
  PIN b_odata[287]
    DIRECTION INPUT ;
    USE SIGNAL ;
    PORT
      LAYER M4 ;
        RECT  0 59.184 0.084 59.208 ;
    END
  END b_odata[287]
  PIN b_odata[288]
    DIRECTION INPUT ;
    USE SIGNAL ;
    PORT
      LAYER M4 ;
        RECT  0 59.28 0.084 59.304 ;
    END
  END b_odata[288]
  PIN b_odata[289]
    DIRECTION INPUT ;
    USE SIGNAL ;
    PORT
      LAYER M4 ;
        RECT  0 59.376 0.084 59.4 ;
    END
  END b_odata[289]
  PIN b_odata[28]
    DIRECTION INPUT ;
    USE SIGNAL ;
    PORT
      LAYER M4 ;
        RECT  0 55.824 0.084 55.848 ;
    END
  END b_odata[28]
  PIN b_odata[290]
    DIRECTION INPUT ;
    USE SIGNAL ;
    PORT
      LAYER M4 ;
        RECT  0 59.472 0.084 59.496 ;
    END
  END b_odata[290]
  PIN b_odata[291]
    DIRECTION INPUT ;
    USE SIGNAL ;
    PORT
      LAYER M4 ;
        RECT  0 59.568 0.084 59.592 ;
    END
  END b_odata[291]
  PIN b_odata[292]
    DIRECTION INPUT ;
    USE SIGNAL ;
    PORT
      LAYER M4 ;
        RECT  0 59.664 0.084 59.688 ;
    END
  END b_odata[292]
  PIN b_odata[293]
    DIRECTION INPUT ;
    USE SIGNAL ;
    PORT
      LAYER M4 ;
        RECT  0 59.76 0.084 59.784 ;
    END
  END b_odata[293]
  PIN b_odata[294]
    DIRECTION INPUT ;
    USE SIGNAL ;
    PORT
      LAYER M4 ;
        RECT  0 59.856 0.084 59.88 ;
    END
  END b_odata[294]
  PIN b_odata[295]
    DIRECTION INPUT ;
    USE SIGNAL ;
    PORT
      LAYER M4 ;
        RECT  0 59.952 0.084 59.976 ;
    END
  END b_odata[295]
  PIN b_odata[296]
    DIRECTION INPUT ;
    USE SIGNAL ;
    PORT
      LAYER M4 ;
        RECT  0 60.048 0.084 60.072 ;
    END
  END b_odata[296]
  PIN b_odata[297]
    DIRECTION INPUT ;
    USE SIGNAL ;
    PORT
      LAYER M4 ;
        RECT  0 60.144 0.084 60.168 ;
    END
  END b_odata[297]
  PIN b_odata[298]
    DIRECTION INPUT ;
    USE SIGNAL ;
    PORT
      LAYER M4 ;
        RECT  0 60.24 0.084 60.264 ;
    END
  END b_odata[298]
  PIN b_odata[299]
    DIRECTION INPUT ;
    USE SIGNAL ;
    PORT
      LAYER M4 ;
        RECT  0 67.248 0.084 67.272 ;
    END
  END b_odata[299]
  PIN b_odata[29]
    DIRECTION INPUT ;
    USE SIGNAL ;
    PORT
      LAYER M4 ;
        RECT  0 55.92 0.084 55.944 ;
    END
  END b_odata[29]
  PIN b_odata[2]
    DIRECTION INPUT ;
    USE SIGNAL ;
    PORT
      LAYER M4 ;
        RECT  0 37.2 0.084 37.224 ;
    END
  END b_odata[2]
  PIN b_odata[300]
    DIRECTION INPUT ;
    USE SIGNAL ;
    PORT
      LAYER M4 ;
        RECT  0 67.344 0.084 67.368 ;
    END
  END b_odata[300]
  PIN b_odata[301]
    DIRECTION INPUT ;
    USE SIGNAL ;
    PORT
      LAYER M4 ;
        RECT  0 67.44 0.084 67.464 ;
    END
  END b_odata[301]
  PIN b_odata[302]
    DIRECTION INPUT ;
    USE SIGNAL ;
    PORT
      LAYER M4 ;
        RECT  0 67.536 0.084 67.56 ;
    END
  END b_odata[302]
  PIN b_odata[303]
    DIRECTION INPUT ;
    USE SIGNAL ;
    PORT
      LAYER M4 ;
        RECT  0 67.632 0.084 67.656 ;
    END
  END b_odata[303]
  PIN b_odata[304]
    DIRECTION INPUT ;
    USE SIGNAL ;
    PORT
      LAYER M4 ;
        RECT  0 67.728 0.084 67.752 ;
    END
  END b_odata[304]
  PIN b_odata[305]
    DIRECTION INPUT ;
    USE SIGNAL ;
    PORT
      LAYER M4 ;
        RECT  0 67.824 0.084 67.848 ;
    END
  END b_odata[305]
  PIN b_odata[306]
    DIRECTION INPUT ;
    USE SIGNAL ;
    PORT
      LAYER M4 ;
        RECT  0 67.92 0.084 67.944 ;
    END
  END b_odata[306]
  PIN b_odata[307]
    DIRECTION INPUT ;
    USE SIGNAL ;
    PORT
      LAYER M4 ;
        RECT  0 68.016 0.084 68.04 ;
    END
  END b_odata[307]
  PIN b_odata[308]
    DIRECTION INPUT ;
    USE SIGNAL ;
    PORT
      LAYER M4 ;
        RECT  0 68.112 0.084 68.136 ;
    END
  END b_odata[308]
  PIN b_odata[309]
    DIRECTION INPUT ;
    USE SIGNAL ;
    PORT
      LAYER M4 ;
        RECT  0 68.208 0.084 68.232 ;
    END
  END b_odata[309]
  PIN b_odata[30]
    DIRECTION INPUT ;
    USE SIGNAL ;
    PORT
      LAYER M4 ;
        RECT  0 56.016 0.084 56.04 ;
    END
  END b_odata[30]
  PIN b_odata[310]
    DIRECTION INPUT ;
    USE SIGNAL ;
    PORT
      LAYER M4 ;
        RECT  0 68.304 0.084 68.328 ;
    END
  END b_odata[310]
  PIN b_odata[311]
    DIRECTION INPUT ;
    USE SIGNAL ;
    PORT
      LAYER M4 ;
        RECT  0 68.4 0.084 68.424 ;
    END
  END b_odata[311]
  PIN b_odata[312]
    DIRECTION INPUT ;
    USE SIGNAL ;
    PORT
      LAYER M4 ;
        RECT  0 68.496 0.084 68.52 ;
    END
  END b_odata[312]
  PIN b_odata[313]
    DIRECTION INPUT ;
    USE SIGNAL ;
    PORT
      LAYER M4 ;
        RECT  0 68.592 0.084 68.616 ;
    END
  END b_odata[313]
  PIN b_odata[314]
    DIRECTION INPUT ;
    USE SIGNAL ;
    PORT
      LAYER M4 ;
        RECT  0 68.688 0.084 68.712 ;
    END
  END b_odata[314]
  PIN b_odata[315]
    DIRECTION INPUT ;
    USE SIGNAL ;
    PORT
      LAYER M4 ;
        RECT  0 68.784 0.084 68.808 ;
    END
  END b_odata[315]
  PIN b_odata[316]
    DIRECTION INPUT ;
    USE SIGNAL ;
    PORT
      LAYER M4 ;
        RECT  0 68.88 0.084 68.904 ;
    END
  END b_odata[316]
  PIN b_odata[317]
    DIRECTION INPUT ;
    USE SIGNAL ;
    PORT
      LAYER M4 ;
        RECT  0 68.976 0.084 69 ;
    END
  END b_odata[317]
  PIN b_odata[318]
    DIRECTION INPUT ;
    USE SIGNAL ;
    PORT
      LAYER M4 ;
        RECT  0 69.072 0.084 69.096 ;
    END
  END b_odata[318]
  PIN b_odata[319]
    DIRECTION INPUT ;
    USE SIGNAL ;
    PORT
      LAYER M4 ;
        RECT  0 69.168 0.084 69.192 ;
    END
  END b_odata[319]
  PIN b_odata[31]
    DIRECTION INPUT ;
    USE SIGNAL ;
    PORT
      LAYER M4 ;
        RECT  0 56.112 0.084 56.136 ;
    END
  END b_odata[31]
  PIN b_odata[320]
    DIRECTION INPUT ;
    USE SIGNAL ;
    PORT
      LAYER M4 ;
        RECT  0 69.264 0.084 69.288 ;
    END
  END b_odata[320]
  PIN b_odata[321]
    DIRECTION INPUT ;
    USE SIGNAL ;
    PORT
      LAYER M4 ;
        RECT  0 69.36 0.084 69.384 ;
    END
  END b_odata[321]
  PIN b_odata[322]
    DIRECTION INPUT ;
    USE SIGNAL ;
    PORT
      LAYER M4 ;
        RECT  0 69.456 0.084 69.48 ;
    END
  END b_odata[322]
  PIN b_odata[323]
    DIRECTION INPUT ;
    USE SIGNAL ;
    PORT
      LAYER M4 ;
        RECT  0 69.552 0.084 69.576 ;
    END
  END b_odata[323]
  PIN b_odata[324]
    DIRECTION INPUT ;
    USE SIGNAL ;
    PORT
      LAYER M4 ;
        RECT  0 69.648 0.084 69.672 ;
    END
  END b_odata[324]
  PIN b_odata[325]
    DIRECTION INPUT ;
    USE SIGNAL ;
    PORT
      LAYER M4 ;
        RECT  0 69.744 0.084 69.768 ;
    END
  END b_odata[325]
  PIN b_odata[326]
    DIRECTION INPUT ;
    USE SIGNAL ;
    PORT
      LAYER M4 ;
        RECT  0 69.84 0.084 69.864 ;
    END
  END b_odata[326]
  PIN b_odata[327]
    DIRECTION INPUT ;
    USE SIGNAL ;
    PORT
      LAYER M4 ;
        RECT  0 69.936 0.084 69.96 ;
    END
  END b_odata[327]
  PIN b_odata[328]
    DIRECTION INPUT ;
    USE SIGNAL ;
    PORT
      LAYER M4 ;
        RECT  0 70.032 0.084 70.056 ;
    END
  END b_odata[328]
  PIN b_odata[329]
    DIRECTION INPUT ;
    USE SIGNAL ;
    PORT
      LAYER M4 ;
        RECT  0 70.128 0.084 70.152 ;
    END
  END b_odata[329]
  PIN b_odata[32]
    DIRECTION INPUT ;
    USE SIGNAL ;
    PORT
      LAYER M4 ;
        RECT  0 56.208 0.084 56.232 ;
    END
  END b_odata[32]
  PIN b_odata[330]
    DIRECTION INPUT ;
    USE SIGNAL ;
    PORT
      LAYER M4 ;
        RECT  0 70.224 0.084 70.248 ;
    END
  END b_odata[330]
  PIN b_odata[331]
    DIRECTION INPUT ;
    USE SIGNAL ;
    PORT
      LAYER M4 ;
        RECT  0 70.32 0.084 70.344 ;
    END
  END b_odata[331]
  PIN b_odata[332]
    DIRECTION INPUT ;
    USE SIGNAL ;
    PORT
      LAYER M4 ;
        RECT  0 70.416 0.084 70.44 ;
    END
  END b_odata[332]
  PIN b_odata[333]
    DIRECTION INPUT ;
    USE SIGNAL ;
    PORT
      LAYER M4 ;
        RECT  0 70.512 0.084 70.536 ;
    END
  END b_odata[333]
  PIN b_odata[334]
    DIRECTION INPUT ;
    USE SIGNAL ;
    PORT
      LAYER M4 ;
        RECT  0 70.608 0.084 70.632 ;
    END
  END b_odata[334]
  PIN b_odata[335]
    DIRECTION INPUT ;
    USE SIGNAL ;
    PORT
      LAYER M4 ;
        RECT  0 70.704 0.084 70.728 ;
    END
  END b_odata[335]
  PIN b_odata[336]
    DIRECTION INPUT ;
    USE SIGNAL ;
    PORT
      LAYER M4 ;
        RECT  0 70.8 0.084 70.824 ;
    END
  END b_odata[336]
  PIN b_odata[337]
    DIRECTION INPUT ;
    USE SIGNAL ;
    PORT
      LAYER M4 ;
        RECT  0 70.896 0.084 70.92 ;
    END
  END b_odata[337]
  PIN b_odata[338]
    DIRECTION INPUT ;
    USE SIGNAL ;
    PORT
      LAYER M4 ;
        RECT  0 70.992 0.084 71.016 ;
    END
  END b_odata[338]
  PIN b_odata[339]
    DIRECTION INPUT ;
    USE SIGNAL ;
    PORT
      LAYER M4 ;
        RECT  0 71.088 0.084 71.112 ;
    END
  END b_odata[339]
  PIN b_odata[33]
    DIRECTION INPUT ;
    USE SIGNAL ;
    PORT
      LAYER M4 ;
        RECT  0 56.304 0.084 56.328 ;
    END
  END b_odata[33]
  PIN b_odata[340]
    DIRECTION INPUT ;
    USE SIGNAL ;
    PORT
      LAYER M4 ;
        RECT  0 71.184 0.084 71.208 ;
    END
  END b_odata[340]
  PIN b_odata[341]
    DIRECTION INPUT ;
    USE SIGNAL ;
    PORT
      LAYER M4 ;
        RECT  0 71.28 0.084 71.304 ;
    END
  END b_odata[341]
  PIN b_odata[342]
    DIRECTION INPUT ;
    USE SIGNAL ;
    PORT
      LAYER M4 ;
        RECT  0 71.376 0.084 71.4 ;
    END
  END b_odata[342]
  PIN b_odata[343]
    DIRECTION INPUT ;
    USE SIGNAL ;
    PORT
      LAYER M4 ;
        RECT  0 71.472 0.084 71.496 ;
    END
  END b_odata[343]
  PIN b_odata[344]
    DIRECTION INPUT ;
    USE SIGNAL ;
    PORT
      LAYER M4 ;
        RECT  0 71.568 0.084 71.592 ;
    END
  END b_odata[344]
  PIN b_odata[345]
    DIRECTION INPUT ;
    USE SIGNAL ;
    PORT
      LAYER M4 ;
        RECT  0 71.664 0.084 71.688 ;
    END
  END b_odata[345]
  PIN b_odata[346]
    DIRECTION INPUT ;
    USE SIGNAL ;
    PORT
      LAYER M4 ;
        RECT  0 71.76 0.084 71.784 ;
    END
  END b_odata[346]
  PIN b_odata[347]
    DIRECTION INPUT ;
    USE SIGNAL ;
    PORT
      LAYER M4 ;
        RECT  0 71.856 0.084 71.88 ;
    END
  END b_odata[347]
  PIN b_odata[348]
    DIRECTION INPUT ;
    USE SIGNAL ;
    PORT
      LAYER M4 ;
        RECT  0 71.952 0.084 71.976 ;
    END
  END b_odata[348]
  PIN b_odata[349]
    DIRECTION INPUT ;
    USE SIGNAL ;
    PORT
      LAYER M4 ;
        RECT  0 72.048 0.084 72.072 ;
    END
  END b_odata[349]
  PIN b_odata[34]
    DIRECTION INPUT ;
    USE SIGNAL ;
    PORT
      LAYER M4 ;
        RECT  0 56.4 0.084 56.424 ;
    END
  END b_odata[34]
  PIN b_odata[350]
    DIRECTION INPUT ;
    USE SIGNAL ;
    PORT
      LAYER M4 ;
        RECT  0 72.144 0.084 72.168 ;
    END
  END b_odata[350]
  PIN b_odata[351]
    DIRECTION INPUT ;
    USE SIGNAL ;
    PORT
      LAYER M4 ;
        RECT  0 72.24 0.084 72.264 ;
    END
  END b_odata[351]
  PIN b_odata[352]
    DIRECTION INPUT ;
    USE SIGNAL ;
    PORT
      LAYER M4 ;
        RECT  0 72.336 0.084 72.36 ;
    END
  END b_odata[352]
  PIN b_odata[353]
    DIRECTION INPUT ;
    USE SIGNAL ;
    PORT
      LAYER M4 ;
        RECT  0 72.432 0.084 72.456 ;
    END
  END b_odata[353]
  PIN b_odata[354]
    DIRECTION INPUT ;
    USE SIGNAL ;
    PORT
      LAYER M4 ;
        RECT  0 72.528 0.084 72.552 ;
    END
  END b_odata[354]
  PIN b_odata[355]
    DIRECTION INPUT ;
    USE SIGNAL ;
    PORT
      LAYER M4 ;
        RECT  0 72.624 0.084 72.648 ;
    END
  END b_odata[355]
  PIN b_odata[356]
    DIRECTION INPUT ;
    USE SIGNAL ;
    PORT
      LAYER M4 ;
        RECT  0 72.72 0.084 72.744 ;
    END
  END b_odata[356]
  PIN b_odata[357]
    DIRECTION INPUT ;
    USE SIGNAL ;
    PORT
      LAYER M4 ;
        RECT  0 72.816 0.084 72.84 ;
    END
  END b_odata[357]
  PIN b_odata[358]
    DIRECTION INPUT ;
    USE SIGNAL ;
    PORT
      LAYER M4 ;
        RECT  0 72.912 0.084 72.936 ;
    END
  END b_odata[358]
  PIN b_odata[359]
    DIRECTION INPUT ;
    USE SIGNAL ;
    PORT
      LAYER M4 ;
        RECT  0 73.008 0.084 73.032 ;
    END
  END b_odata[359]
  PIN b_odata[35]
    DIRECTION INPUT ;
    USE SIGNAL ;
    PORT
      LAYER M4 ;
        RECT  0 56.496 0.084 56.52 ;
    END
  END b_odata[35]
  PIN b_odata[360]
    DIRECTION INPUT ;
    USE SIGNAL ;
    PORT
      LAYER M4 ;
        RECT  0 73.104 0.084 73.128 ;
    END
  END b_odata[360]
  PIN b_odata[361]
    DIRECTION INPUT ;
    USE SIGNAL ;
    PORT
      LAYER M4 ;
        RECT  0 73.2 0.084 73.224 ;
    END
  END b_odata[361]
  PIN b_odata[362]
    DIRECTION INPUT ;
    USE SIGNAL ;
    PORT
      LAYER M4 ;
        RECT  0 73.296 0.084 73.32 ;
    END
  END b_odata[362]
  PIN b_odata[363]
    DIRECTION INPUT ;
    USE SIGNAL ;
    PORT
      LAYER M4 ;
        RECT  0 44.208 0.084 44.232 ;
    END
  END b_odata[363]
  PIN b_odata[364]
    DIRECTION INPUT ;
    USE SIGNAL ;
    PORT
      LAYER M4 ;
        RECT  0 44.304 0.084 44.328 ;
    END
  END b_odata[364]
  PIN b_odata[365]
    DIRECTION INPUT ;
    USE SIGNAL ;
    PORT
      LAYER M4 ;
        RECT  0 44.4 0.084 44.424 ;
    END
  END b_odata[365]
  PIN b_odata[366]
    DIRECTION INPUT ;
    USE SIGNAL ;
    PORT
      LAYER M4 ;
        RECT  0 44.496 0.084 44.52 ;
    END
  END b_odata[366]
  PIN b_odata[367]
    DIRECTION INPUT ;
    USE SIGNAL ;
    PORT
      LAYER M4 ;
        RECT  0 44.592 0.084 44.616 ;
    END
  END b_odata[367]
  PIN b_odata[368]
    DIRECTION INPUT ;
    USE SIGNAL ;
    PORT
      LAYER M4 ;
        RECT  0 44.688 0.084 44.712 ;
    END
  END b_odata[368]
  PIN b_odata[369]
    DIRECTION INPUT ;
    USE SIGNAL ;
    PORT
      LAYER M4 ;
        RECT  0 44.784 0.084 44.808 ;
    END
  END b_odata[369]
  PIN b_odata[36]
    DIRECTION INPUT ;
    USE SIGNAL ;
    PORT
      LAYER M4 ;
        RECT  0 56.592 0.084 56.616 ;
    END
  END b_odata[36]
  PIN b_odata[370]
    DIRECTION INPUT ;
    USE SIGNAL ;
    PORT
      LAYER M4 ;
        RECT  0 44.88 0.084 44.904 ;
    END
  END b_odata[370]
  PIN b_odata[371]
    DIRECTION INPUT ;
    USE SIGNAL ;
    PORT
      LAYER M4 ;
        RECT  0 44.976 0.084 45 ;
    END
  END b_odata[371]
  PIN b_odata[372]
    DIRECTION INPUT ;
    USE SIGNAL ;
    PORT
      LAYER M4 ;
        RECT  0 45.072 0.084 45.096 ;
    END
  END b_odata[372]
  PIN b_odata[373]
    DIRECTION INPUT ;
    USE SIGNAL ;
    PORT
      LAYER M4 ;
        RECT  0 45.168 0.084 45.192 ;
    END
  END b_odata[373]
  PIN b_odata[374]
    DIRECTION INPUT ;
    USE SIGNAL ;
    PORT
      LAYER M4 ;
        RECT  0 45.264 0.084 45.288 ;
    END
  END b_odata[374]
  PIN b_odata[375]
    DIRECTION INPUT ;
    USE SIGNAL ;
    PORT
      LAYER M4 ;
        RECT  0 45.36 0.084 45.384 ;
    END
  END b_odata[375]
  PIN b_odata[376]
    DIRECTION INPUT ;
    USE SIGNAL ;
    PORT
      LAYER M4 ;
        RECT  0 45.456 0.084 45.48 ;
    END
  END b_odata[376]
  PIN b_odata[377]
    DIRECTION INPUT ;
    USE SIGNAL ;
    PORT
      LAYER M4 ;
        RECT  0 45.552 0.084 45.576 ;
    END
  END b_odata[377]
  PIN b_odata[378]
    DIRECTION INPUT ;
    USE SIGNAL ;
    PORT
      LAYER M4 ;
        RECT  0 45.648 0.084 45.672 ;
    END
  END b_odata[378]
  PIN b_odata[379]
    DIRECTION INPUT ;
    USE SIGNAL ;
    PORT
      LAYER M4 ;
        RECT  0 45.744 0.084 45.768 ;
    END
  END b_odata[379]
  PIN b_odata[37]
    DIRECTION INPUT ;
    USE SIGNAL ;
    PORT
      LAYER M4 ;
        RECT  0 56.688 0.084 56.712 ;
    END
  END b_odata[37]
  PIN b_odata[380]
    DIRECTION INPUT ;
    USE SIGNAL ;
    PORT
      LAYER M4 ;
        RECT  0 45.84 0.084 45.864 ;
    END
  END b_odata[380]
  PIN b_odata[381]
    DIRECTION INPUT ;
    USE SIGNAL ;
    PORT
      LAYER M4 ;
        RECT  0 45.936 0.084 45.96 ;
    END
  END b_odata[381]
  PIN b_odata[382]
    DIRECTION INPUT ;
    USE SIGNAL ;
    PORT
      LAYER M4 ;
        RECT  0 46.032 0.084 46.056 ;
    END
  END b_odata[382]
  PIN b_odata[383]
    DIRECTION INPUT ;
    USE SIGNAL ;
    PORT
      LAYER M4 ;
        RECT  0 46.128 0.084 46.152 ;
    END
  END b_odata[383]
  PIN b_odata[384]
    DIRECTION INPUT ;
    USE SIGNAL ;
    PORT
      LAYER M4 ;
        RECT  0 46.224 0.084 46.248 ;
    END
  END b_odata[384]
  PIN b_odata[385]
    DIRECTION INPUT ;
    USE SIGNAL ;
    PORT
      LAYER M4 ;
        RECT  0 46.32 0.084 46.344 ;
    END
  END b_odata[385]
  PIN b_odata[386]
    DIRECTION INPUT ;
    USE SIGNAL ;
    PORT
      LAYER M4 ;
        RECT  0 46.416 0.084 46.44 ;
    END
  END b_odata[386]
  PIN b_odata[387]
    DIRECTION INPUT ;
    USE SIGNAL ;
    PORT
      LAYER M4 ;
        RECT  0 46.512 0.084 46.536 ;
    END
  END b_odata[387]
  PIN b_odata[388]
    DIRECTION INPUT ;
    USE SIGNAL ;
    PORT
      LAYER M4 ;
        RECT  0 46.608 0.084 46.632 ;
    END
  END b_odata[388]
  PIN b_odata[389]
    DIRECTION INPUT ;
    USE SIGNAL ;
    PORT
      LAYER M4 ;
        RECT  0 46.704 0.084 46.728 ;
    END
  END b_odata[389]
  PIN b_odata[38]
    DIRECTION INPUT ;
    USE SIGNAL ;
    PORT
      LAYER M4 ;
        RECT  0 56.784 0.084 56.808 ;
    END
  END b_odata[38]
  PIN b_odata[390]
    DIRECTION INPUT ;
    USE SIGNAL ;
    PORT
      LAYER M4 ;
        RECT  0 46.8 0.084 46.824 ;
    END
  END b_odata[390]
  PIN b_odata[391]
    DIRECTION INPUT ;
    USE SIGNAL ;
    PORT
      LAYER M4 ;
        RECT  0 46.896 0.084 46.92 ;
    END
  END b_odata[391]
  PIN b_odata[392]
    DIRECTION INPUT ;
    USE SIGNAL ;
    PORT
      LAYER M4 ;
        RECT  0 46.992 0.084 47.016 ;
    END
  END b_odata[392]
  PIN b_odata[393]
    DIRECTION INPUT ;
    USE SIGNAL ;
    PORT
      LAYER M4 ;
        RECT  0 47.088 0.084 47.112 ;
    END
  END b_odata[393]
  PIN b_odata[394]
    DIRECTION INPUT ;
    USE SIGNAL ;
    PORT
      LAYER M4 ;
        RECT  0 47.184 0.084 47.208 ;
    END
  END b_odata[394]
  PIN b_odata[395]
    DIRECTION INPUT ;
    USE SIGNAL ;
    PORT
      LAYER M4 ;
        RECT  0 41.136 0.084 41.16 ;
    END
  END b_odata[395]
  PIN b_odata[396]
    DIRECTION INPUT ;
    USE SIGNAL ;
    PORT
      LAYER M4 ;
        RECT  0 41.232 0.084 41.256 ;
    END
  END b_odata[396]
  PIN b_odata[397]
    DIRECTION INPUT ;
    USE SIGNAL ;
    PORT
      LAYER M4 ;
        RECT  0 41.328 0.084 41.352 ;
    END
  END b_odata[397]
  PIN b_odata[398]
    DIRECTION INPUT ;
    USE SIGNAL ;
    PORT
      LAYER M4 ;
        RECT  0 41.424 0.084 41.448 ;
    END
  END b_odata[398]
  PIN b_odata[399]
    DIRECTION INPUT ;
    USE SIGNAL ;
    PORT
      LAYER M4 ;
        RECT  0 41.52 0.084 41.544 ;
    END
  END b_odata[399]
  PIN b_odata[39]
    DIRECTION INPUT ;
    USE SIGNAL ;
    PORT
      LAYER M4 ;
        RECT  0 56.88 0.084 56.904 ;
    END
  END b_odata[39]
  PIN b_odata[3]
    DIRECTION INPUT ;
    USE SIGNAL ;
    PORT
      LAYER M4 ;
        RECT  0 37.296 0.084 37.32 ;
    END
  END b_odata[3]
  PIN b_odata[400]
    DIRECTION INPUT ;
    USE SIGNAL ;
    PORT
      LAYER M4 ;
        RECT  0 41.616 0.084 41.64 ;
    END
  END b_odata[400]
  PIN b_odata[401]
    DIRECTION INPUT ;
    USE SIGNAL ;
    PORT
      LAYER M4 ;
        RECT  0 41.712 0.084 41.736 ;
    END
  END b_odata[401]
  PIN b_odata[402]
    DIRECTION INPUT ;
    USE SIGNAL ;
    PORT
      LAYER M4 ;
        RECT  0 41.808 0.084 41.832 ;
    END
  END b_odata[402]
  PIN b_odata[403]
    DIRECTION INPUT ;
    USE SIGNAL ;
    PORT
      LAYER M4 ;
        RECT  0 41.904 0.084 41.928 ;
    END
  END b_odata[403]
  PIN b_odata[404]
    DIRECTION INPUT ;
    USE SIGNAL ;
    PORT
      LAYER M4 ;
        RECT  0 42 0.084 42.024 ;
    END
  END b_odata[404]
  PIN b_odata[405]
    DIRECTION INPUT ;
    USE SIGNAL ;
    PORT
      LAYER M4 ;
        RECT  0 42.096 0.084 42.12 ;
    END
  END b_odata[405]
  PIN b_odata[406]
    DIRECTION INPUT ;
    USE SIGNAL ;
    PORT
      LAYER M4 ;
        RECT  0 42.192 0.084 42.216 ;
    END
  END b_odata[406]
  PIN b_odata[407]
    DIRECTION INPUT ;
    USE SIGNAL ;
    PORT
      LAYER M4 ;
        RECT  0 42.288 0.084 42.312 ;
    END
  END b_odata[407]
  PIN b_odata[408]
    DIRECTION INPUT ;
    USE SIGNAL ;
    PORT
      LAYER M4 ;
        RECT  0 42.384 0.084 42.408 ;
    END
  END b_odata[408]
  PIN b_odata[409]
    DIRECTION INPUT ;
    USE SIGNAL ;
    PORT
      LAYER M4 ;
        RECT  0 42.48 0.084 42.504 ;
    END
  END b_odata[409]
  PIN b_odata[40]
    DIRECTION INPUT ;
    USE SIGNAL ;
    PORT
      LAYER M4 ;
        RECT  0 56.976 0.084 57 ;
    END
  END b_odata[40]
  PIN b_odata[410]
    DIRECTION INPUT ;
    USE SIGNAL ;
    PORT
      LAYER M4 ;
        RECT  0 42.576 0.084 42.6 ;
    END
  END b_odata[410]
  PIN b_odata[411]
    DIRECTION INPUT ;
    USE SIGNAL ;
    PORT
      LAYER M4 ;
        RECT  0 42.672 0.084 42.696 ;
    END
  END b_odata[411]
  PIN b_odata[412]
    DIRECTION INPUT ;
    USE SIGNAL ;
    PORT
      LAYER M4 ;
        RECT  0 42.768 0.084 42.792 ;
    END
  END b_odata[412]
  PIN b_odata[413]
    DIRECTION INPUT ;
    USE SIGNAL ;
    PORT
      LAYER M4 ;
        RECT  0 42.864 0.084 42.888 ;
    END
  END b_odata[413]
  PIN b_odata[414]
    DIRECTION INPUT ;
    USE SIGNAL ;
    PORT
      LAYER M4 ;
        RECT  0 42.96 0.084 42.984 ;
    END
  END b_odata[414]
  PIN b_odata[415]
    DIRECTION INPUT ;
    USE SIGNAL ;
    PORT
      LAYER M4 ;
        RECT  0 43.056 0.084 43.08 ;
    END
  END b_odata[415]
  PIN b_odata[416]
    DIRECTION INPUT ;
    USE SIGNAL ;
    PORT
      LAYER M4 ;
        RECT  0 43.152 0.084 43.176 ;
    END
  END b_odata[416]
  PIN b_odata[417]
    DIRECTION INPUT ;
    USE SIGNAL ;
    PORT
      LAYER M4 ;
        RECT  0 43.248 0.084 43.272 ;
    END
  END b_odata[417]
  PIN b_odata[418]
    DIRECTION INPUT ;
    USE SIGNAL ;
    PORT
      LAYER M4 ;
        RECT  0 43.344 0.084 43.368 ;
    END
  END b_odata[418]
  PIN b_odata[419]
    DIRECTION INPUT ;
    USE SIGNAL ;
    PORT
      LAYER M4 ;
        RECT  0 43.44 0.084 43.464 ;
    END
  END b_odata[419]
  PIN b_odata[41]
    DIRECTION INPUT ;
    USE SIGNAL ;
    PORT
      LAYER M4 ;
        RECT  0 57.072 0.084 57.096 ;
    END
  END b_odata[41]
  PIN b_odata[420]
    DIRECTION INPUT ;
    USE SIGNAL ;
    PORT
      LAYER M4 ;
        RECT  0 43.536 0.084 43.56 ;
    END
  END b_odata[420]
  PIN b_odata[421]
    DIRECTION INPUT ;
    USE SIGNAL ;
    PORT
      LAYER M4 ;
        RECT  0 43.632 0.084 43.656 ;
    END
  END b_odata[421]
  PIN b_odata[422]
    DIRECTION INPUT ;
    USE SIGNAL ;
    PORT
      LAYER M4 ;
        RECT  0 43.728 0.084 43.752 ;
    END
  END b_odata[422]
  PIN b_odata[423]
    DIRECTION INPUT ;
    USE SIGNAL ;
    PORT
      LAYER M4 ;
        RECT  0 43.824 0.084 43.848 ;
    END
  END b_odata[423]
  PIN b_odata[424]
    DIRECTION INPUT ;
    USE SIGNAL ;
    PORT
      LAYER M4 ;
        RECT  0 43.92 0.084 43.944 ;
    END
  END b_odata[424]
  PIN b_odata[425]
    DIRECTION INPUT ;
    USE SIGNAL ;
    PORT
      LAYER M4 ;
        RECT  0 44.016 0.084 44.04 ;
    END
  END b_odata[425]
  PIN b_odata[426]
    DIRECTION INPUT ;
    USE SIGNAL ;
    PORT
      LAYER M4 ;
        RECT  0 44.112 0.084 44.136 ;
    END
  END b_odata[426]
  PIN b_odata[427]
    DIRECTION INPUT ;
    USE SIGNAL ;
    PORT
      LAYER M4 ;
        RECT  0 38.064 0.084 38.088 ;
    END
  END b_odata[427]
  PIN b_odata[428]
    DIRECTION INPUT ;
    USE SIGNAL ;
    PORT
      LAYER M4 ;
        RECT  0 38.16 0.084 38.184 ;
    END
  END b_odata[428]
  PIN b_odata[429]
    DIRECTION INPUT ;
    USE SIGNAL ;
    PORT
      LAYER M4 ;
        RECT  0 38.256 0.084 38.28 ;
    END
  END b_odata[429]
  PIN b_odata[42]
    DIRECTION INPUT ;
    USE SIGNAL ;
    PORT
      LAYER M4 ;
        RECT  0 57.168 0.084 57.192 ;
    END
  END b_odata[42]
  PIN b_odata[430]
    DIRECTION INPUT ;
    USE SIGNAL ;
    PORT
      LAYER M4 ;
        RECT  0 38.352 0.084 38.376 ;
    END
  END b_odata[430]
  PIN b_odata[431]
    DIRECTION INPUT ;
    USE SIGNAL ;
    PORT
      LAYER M4 ;
        RECT  0 38.448 0.084 38.472 ;
    END
  END b_odata[431]
  PIN b_odata[432]
    DIRECTION INPUT ;
    USE SIGNAL ;
    PORT
      LAYER M4 ;
        RECT  0 38.544 0.084 38.568 ;
    END
  END b_odata[432]
  PIN b_odata[433]
    DIRECTION INPUT ;
    USE SIGNAL ;
    PORT
      LAYER M4 ;
        RECT  0 38.64 0.084 38.664 ;
    END
  END b_odata[433]
  PIN b_odata[434]
    DIRECTION INPUT ;
    USE SIGNAL ;
    PORT
      LAYER M4 ;
        RECT  0 38.736 0.084 38.76 ;
    END
  END b_odata[434]
  PIN b_odata[435]
    DIRECTION INPUT ;
    USE SIGNAL ;
    PORT
      LAYER M4 ;
        RECT  0 38.832 0.084 38.856 ;
    END
  END b_odata[435]
  PIN b_odata[436]
    DIRECTION INPUT ;
    USE SIGNAL ;
    PORT
      LAYER M4 ;
        RECT  0 38.928 0.084 38.952 ;
    END
  END b_odata[436]
  PIN b_odata[437]
    DIRECTION INPUT ;
    USE SIGNAL ;
    PORT
      LAYER M4 ;
        RECT  0 39.024 0.084 39.048 ;
    END
  END b_odata[437]
  PIN b_odata[438]
    DIRECTION INPUT ;
    USE SIGNAL ;
    PORT
      LAYER M4 ;
        RECT  0 39.12 0.084 39.144 ;
    END
  END b_odata[438]
  PIN b_odata[439]
    DIRECTION INPUT ;
    USE SIGNAL ;
    PORT
      LAYER M4 ;
        RECT  0 39.216 0.084 39.24 ;
    END
  END b_odata[439]
  PIN b_odata[43]
    DIRECTION INPUT ;
    USE SIGNAL ;
    PORT
      LAYER M4 ;
        RECT  0 63.408 0.084 63.432 ;
    END
  END b_odata[43]
  PIN b_odata[440]
    DIRECTION INPUT ;
    USE SIGNAL ;
    PORT
      LAYER M4 ;
        RECT  0 39.312 0.084 39.336 ;
    END
  END b_odata[440]
  PIN b_odata[441]
    DIRECTION INPUT ;
    USE SIGNAL ;
    PORT
      LAYER M4 ;
        RECT  0 39.408 0.084 39.432 ;
    END
  END b_odata[441]
  PIN b_odata[442]
    DIRECTION INPUT ;
    USE SIGNAL ;
    PORT
      LAYER M4 ;
        RECT  0 39.504 0.084 39.528 ;
    END
  END b_odata[442]
  PIN b_odata[443]
    DIRECTION INPUT ;
    USE SIGNAL ;
    PORT
      LAYER M4 ;
        RECT  0 39.6 0.084 39.624 ;
    END
  END b_odata[443]
  PIN b_odata[444]
    DIRECTION INPUT ;
    USE SIGNAL ;
    PORT
      LAYER M4 ;
        RECT  0 39.696 0.084 39.72 ;
    END
  END b_odata[444]
  PIN b_odata[445]
    DIRECTION INPUT ;
    USE SIGNAL ;
    PORT
      LAYER M4 ;
        RECT  0 39.792 0.084 39.816 ;
    END
  END b_odata[445]
  PIN b_odata[446]
    DIRECTION INPUT ;
    USE SIGNAL ;
    PORT
      LAYER M4 ;
        RECT  0 39.888 0.084 39.912 ;
    END
  END b_odata[446]
  PIN b_odata[447]
    DIRECTION INPUT ;
    USE SIGNAL ;
    PORT
      LAYER M4 ;
        RECT  0 39.984 0.084 40.008 ;
    END
  END b_odata[447]
  PIN b_odata[448]
    DIRECTION INPUT ;
    USE SIGNAL ;
    PORT
      LAYER M4 ;
        RECT  0 40.08 0.084 40.104 ;
    END
  END b_odata[448]
  PIN b_odata[449]
    DIRECTION INPUT ;
    USE SIGNAL ;
    PORT
      LAYER M4 ;
        RECT  0 40.176 0.084 40.2 ;
    END
  END b_odata[449]
  PIN b_odata[44]
    DIRECTION INPUT ;
    USE SIGNAL ;
    PORT
      LAYER M4 ;
        RECT  0 63.504 0.084 63.528 ;
    END
  END b_odata[44]
  PIN b_odata[450]
    DIRECTION INPUT ;
    USE SIGNAL ;
    PORT
      LAYER M4 ;
        RECT  0 40.272 0.084 40.296 ;
    END
  END b_odata[450]
  PIN b_odata[451]
    DIRECTION INPUT ;
    USE SIGNAL ;
    PORT
      LAYER M4 ;
        RECT  0 40.368 0.084 40.392 ;
    END
  END b_odata[451]
  PIN b_odata[452]
    DIRECTION INPUT ;
    USE SIGNAL ;
    PORT
      LAYER M4 ;
        RECT  0 40.464 0.084 40.488 ;
    END
  END b_odata[452]
  PIN b_odata[453]
    DIRECTION INPUT ;
    USE SIGNAL ;
    PORT
      LAYER M4 ;
        RECT  0 40.56 0.084 40.584 ;
    END
  END b_odata[453]
  PIN b_odata[454]
    DIRECTION INPUT ;
    USE SIGNAL ;
    PORT
      LAYER M4 ;
        RECT  0 40.656 0.084 40.68 ;
    END
  END b_odata[454]
  PIN b_odata[455]
    DIRECTION INPUT ;
    USE SIGNAL ;
    PORT
      LAYER M4 ;
        RECT  0 40.752 0.084 40.776 ;
    END
  END b_odata[455]
  PIN b_odata[456]
    DIRECTION INPUT ;
    USE SIGNAL ;
    PORT
      LAYER M4 ;
        RECT  0 40.848 0.084 40.872 ;
    END
  END b_odata[456]
  PIN b_odata[457]
    DIRECTION INPUT ;
    USE SIGNAL ;
    PORT
      LAYER M4 ;
        RECT  0 40.944 0.084 40.968 ;
    END
  END b_odata[457]
  PIN b_odata[458]
    DIRECTION INPUT ;
    USE SIGNAL ;
    PORT
      LAYER M4 ;
        RECT  0 41.04 0.084 41.064 ;
    END
  END b_odata[458]
  PIN b_odata[459]
    DIRECTION INPUT ;
    USE SIGNAL ;
    PORT
      LAYER M4 ;
        RECT  0 25.008 0.084 25.032 ;
    END
  END b_odata[459]
  PIN b_odata[45]
    DIRECTION INPUT ;
    USE SIGNAL ;
    PORT
      LAYER M4 ;
        RECT  0 63.6 0.084 63.624 ;
    END
  END b_odata[45]
  PIN b_odata[460]
    DIRECTION INPUT ;
    USE SIGNAL ;
    PORT
      LAYER M4 ;
        RECT  0 25.104 0.084 25.128 ;
    END
  END b_odata[460]
  PIN b_odata[461]
    DIRECTION INPUT ;
    USE SIGNAL ;
    PORT
      LAYER M4 ;
        RECT  0 25.2 0.084 25.224 ;
    END
  END b_odata[461]
  PIN b_odata[462]
    DIRECTION INPUT ;
    USE SIGNAL ;
    PORT
      LAYER M4 ;
        RECT  0 25.296 0.084 25.32 ;
    END
  END b_odata[462]
  PIN b_odata[463]
    DIRECTION INPUT ;
    USE SIGNAL ;
    PORT
      LAYER M4 ;
        RECT  0 25.392 0.084 25.416 ;
    END
  END b_odata[463]
  PIN b_odata[464]
    DIRECTION INPUT ;
    USE SIGNAL ;
    PORT
      LAYER M4 ;
        RECT  0 25.488 0.084 25.512 ;
    END
  END b_odata[464]
  PIN b_odata[465]
    DIRECTION INPUT ;
    USE SIGNAL ;
    PORT
      LAYER M4 ;
        RECT  0 25.584 0.084 25.608 ;
    END
  END b_odata[465]
  PIN b_odata[466]
    DIRECTION INPUT ;
    USE SIGNAL ;
    PORT
      LAYER M4 ;
        RECT  0 25.68 0.084 25.704 ;
    END
  END b_odata[466]
  PIN b_odata[467]
    DIRECTION INPUT ;
    USE SIGNAL ;
    PORT
      LAYER M4 ;
        RECT  0 25.776 0.084 25.8 ;
    END
  END b_odata[467]
  PIN b_odata[468]
    DIRECTION INPUT ;
    USE SIGNAL ;
    PORT
      LAYER M4 ;
        RECT  0 25.872 0.084 25.896 ;
    END
  END b_odata[468]
  PIN b_odata[469]
    DIRECTION INPUT ;
    USE SIGNAL ;
    PORT
      LAYER M4 ;
        RECT  0 25.968 0.084 25.992 ;
    END
  END b_odata[469]
  PIN b_odata[46]
    DIRECTION INPUT ;
    USE SIGNAL ;
    PORT
      LAYER M4 ;
        RECT  0 63.696 0.084 63.72 ;
    END
  END b_odata[46]
  PIN b_odata[470]
    DIRECTION INPUT ;
    USE SIGNAL ;
    PORT
      LAYER M4 ;
        RECT  0 26.064 0.084 26.088 ;
    END
  END b_odata[470]
  PIN b_odata[471]
    DIRECTION INPUT ;
    USE SIGNAL ;
    PORT
      LAYER M4 ;
        RECT  0 26.16 0.084 26.184 ;
    END
  END b_odata[471]
  PIN b_odata[472]
    DIRECTION INPUT ;
    USE SIGNAL ;
    PORT
      LAYER M4 ;
        RECT  0 26.256 0.084 26.28 ;
    END
  END b_odata[472]
  PIN b_odata[473]
    DIRECTION INPUT ;
    USE SIGNAL ;
    PORT
      LAYER M4 ;
        RECT  0 26.352 0.084 26.376 ;
    END
  END b_odata[473]
  PIN b_odata[474]
    DIRECTION INPUT ;
    USE SIGNAL ;
    PORT
      LAYER M4 ;
        RECT  0 26.448 0.084 26.472 ;
    END
  END b_odata[474]
  PIN b_odata[475]
    DIRECTION INPUT ;
    USE SIGNAL ;
    PORT
      LAYER M4 ;
        RECT  0 26.544 0.084 26.568 ;
    END
  END b_odata[475]
  PIN b_odata[476]
    DIRECTION INPUT ;
    USE SIGNAL ;
    PORT
      LAYER M4 ;
        RECT  0 26.64 0.084 26.664 ;
    END
  END b_odata[476]
  PIN b_odata[477]
    DIRECTION INPUT ;
    USE SIGNAL ;
    PORT
      LAYER M4 ;
        RECT  0 26.736 0.084 26.76 ;
    END
  END b_odata[477]
  PIN b_odata[478]
    DIRECTION INPUT ;
    USE SIGNAL ;
    PORT
      LAYER M4 ;
        RECT  0 26.832 0.084 26.856 ;
    END
  END b_odata[478]
  PIN b_odata[479]
    DIRECTION INPUT ;
    USE SIGNAL ;
    PORT
      LAYER M4 ;
        RECT  0 26.928 0.084 26.952 ;
    END
  END b_odata[479]
  PIN b_odata[47]
    DIRECTION INPUT ;
    USE SIGNAL ;
    PORT
      LAYER M4 ;
        RECT  0 63.792 0.084 63.816 ;
    END
  END b_odata[47]
  PIN b_odata[480]
    DIRECTION INPUT ;
    USE SIGNAL ;
    PORT
      LAYER M4 ;
        RECT  0 27.024 0.084 27.048 ;
    END
  END b_odata[480]
  PIN b_odata[481]
    DIRECTION INPUT ;
    USE SIGNAL ;
    PORT
      LAYER M4 ;
        RECT  0 27.12 0.084 27.144 ;
    END
  END b_odata[481]
  PIN b_odata[482]
    DIRECTION INPUT ;
    USE SIGNAL ;
    PORT
      LAYER M4 ;
        RECT  0 27.216 0.084 27.24 ;
    END
  END b_odata[482]
  PIN b_odata[483]
    DIRECTION INPUT ;
    USE SIGNAL ;
    PORT
      LAYER M4 ;
        RECT  0 27.312 0.084 27.336 ;
    END
  END b_odata[483]
  PIN b_odata[484]
    DIRECTION INPUT ;
    USE SIGNAL ;
    PORT
      LAYER M4 ;
        RECT  0 27.408 0.084 27.432 ;
    END
  END b_odata[484]
  PIN b_odata[485]
    DIRECTION INPUT ;
    USE SIGNAL ;
    PORT
      LAYER M4 ;
        RECT  0 27.504 0.084 27.528 ;
    END
  END b_odata[485]
  PIN b_odata[486]
    DIRECTION INPUT ;
    USE SIGNAL ;
    PORT
      LAYER M4 ;
        RECT  0 27.6 0.084 27.624 ;
    END
  END b_odata[486]
  PIN b_odata[487]
    DIRECTION INPUT ;
    USE SIGNAL ;
    PORT
      LAYER M4 ;
        RECT  0 27.696 0.084 27.72 ;
    END
  END b_odata[487]
  PIN b_odata[488]
    DIRECTION INPUT ;
    USE SIGNAL ;
    PORT
      LAYER M4 ;
        RECT  0 27.792 0.084 27.816 ;
    END
  END b_odata[488]
  PIN b_odata[489]
    DIRECTION INPUT ;
    USE SIGNAL ;
    PORT
      LAYER M4 ;
        RECT  0 27.888 0.084 27.912 ;
    END
  END b_odata[489]
  PIN b_odata[48]
    DIRECTION INPUT ;
    USE SIGNAL ;
    PORT
      LAYER M4 ;
        RECT  0 63.888 0.084 63.912 ;
    END
  END b_odata[48]
  PIN b_odata[490]
    DIRECTION INPUT ;
    USE SIGNAL ;
    PORT
      LAYER M4 ;
        RECT  0 27.984 0.084 28.008 ;
    END
  END b_odata[490]
  PIN b_odata[491]
    DIRECTION INPUT ;
    USE SIGNAL ;
    PORT
      LAYER M4 ;
        RECT  0 22.8 0.084 22.824 ;
    END
  END b_odata[491]
  PIN b_odata[492]
    DIRECTION INPUT ;
    USE SIGNAL ;
    PORT
      LAYER M4 ;
        RECT  0 22.896 0.084 22.92 ;
    END
  END b_odata[492]
  PIN b_odata[493]
    DIRECTION INPUT ;
    USE SIGNAL ;
    PORT
      LAYER M4 ;
        RECT  0 22.992 0.084 23.016 ;
    END
  END b_odata[493]
  PIN b_odata[494]
    DIRECTION INPUT ;
    USE SIGNAL ;
    PORT
      LAYER M4 ;
        RECT  0 23.088 0.084 23.112 ;
    END
  END b_odata[494]
  PIN b_odata[495]
    DIRECTION INPUT ;
    USE SIGNAL ;
    PORT
      LAYER M4 ;
        RECT  0 23.184 0.084 23.208 ;
    END
  END b_odata[495]
  PIN b_odata[496]
    DIRECTION INPUT ;
    USE SIGNAL ;
    PORT
      LAYER M4 ;
        RECT  0 23.28 0.084 23.304 ;
    END
  END b_odata[496]
  PIN b_odata[497]
    DIRECTION INPUT ;
    USE SIGNAL ;
    PORT
      LAYER M4 ;
        RECT  0 23.376 0.084 23.4 ;
    END
  END b_odata[497]
  PIN b_odata[498]
    DIRECTION INPUT ;
    USE SIGNAL ;
    PORT
      LAYER M4 ;
        RECT  0 23.472 0.084 23.496 ;
    END
  END b_odata[498]
  PIN b_odata[499]
    DIRECTION INPUT ;
    USE SIGNAL ;
    PORT
      LAYER M4 ;
        RECT  0 23.568 0.084 23.592 ;
    END
  END b_odata[499]
  PIN b_odata[49]
    DIRECTION INPUT ;
    USE SIGNAL ;
    PORT
      LAYER M4 ;
        RECT  0 63.984 0.084 64.008 ;
    END
  END b_odata[49]
  PIN b_odata[4]
    DIRECTION INPUT ;
    USE SIGNAL ;
    PORT
      LAYER M4 ;
        RECT  0 37.392 0.084 37.416 ;
    END
  END b_odata[4]
  PIN b_odata[500]
    DIRECTION INPUT ;
    USE SIGNAL ;
    PORT
      LAYER M4 ;
        RECT  0 23.664 0.084 23.688 ;
    END
  END b_odata[500]
  PIN b_odata[501]
    DIRECTION INPUT ;
    USE SIGNAL ;
    PORT
      LAYER M4 ;
        RECT  0 23.76 0.084 23.784 ;
    END
  END b_odata[501]
  PIN b_odata[502]
    DIRECTION INPUT ;
    USE SIGNAL ;
    PORT
      LAYER M4 ;
        RECT  0 23.856 0.084 23.88 ;
    END
  END b_odata[502]
  PIN b_odata[503]
    DIRECTION INPUT ;
    USE SIGNAL ;
    PORT
      LAYER M4 ;
        RECT  0 23.952 0.084 23.976 ;
    END
  END b_odata[503]
  PIN b_odata[504]
    DIRECTION INPUT ;
    USE SIGNAL ;
    PORT
      LAYER M4 ;
        RECT  0 24.048 0.084 24.072 ;
    END
  END b_odata[504]
  PIN b_odata[505]
    DIRECTION INPUT ;
    USE SIGNAL ;
    PORT
      LAYER M4 ;
        RECT  0 24.144 0.084 24.168 ;
    END
  END b_odata[505]
  PIN b_odata[506]
    DIRECTION INPUT ;
    USE SIGNAL ;
    PORT
      LAYER M4 ;
        RECT  0 24.24 0.084 24.264 ;
    END
  END b_odata[506]
  PIN b_odata[507]
    DIRECTION INPUT ;
    USE SIGNAL ;
    PORT
      LAYER M4 ;
        RECT  0 24.336 0.084 24.36 ;
    END
  END b_odata[507]
  PIN b_odata[508]
    DIRECTION INPUT ;
    USE SIGNAL ;
    PORT
      LAYER M4 ;
        RECT  0 24.432 0.084 24.456 ;
    END
  END b_odata[508]
  PIN b_odata[509]
    DIRECTION INPUT ;
    USE SIGNAL ;
    PORT
      LAYER M4 ;
        RECT  0 24.528 0.084 24.552 ;
    END
  END b_odata[509]
  PIN b_odata[50]
    DIRECTION INPUT ;
    USE SIGNAL ;
    PORT
      LAYER M4 ;
        RECT  0 64.08 0.084 64.104 ;
    END
  END b_odata[50]
  PIN b_odata[510]
    DIRECTION INPUT ;
    USE SIGNAL ;
    PORT
      LAYER M4 ;
        RECT  0 24.624 0.084 24.648 ;
    END
  END b_odata[510]
  PIN b_odata[511]
    DIRECTION INPUT ;
    USE SIGNAL ;
    PORT
      LAYER M4 ;
        RECT  0 24.72 0.084 24.744 ;
    END
  END b_odata[511]
  PIN b_odata[51]
    DIRECTION INPUT ;
    USE SIGNAL ;
    PORT
      LAYER M4 ;
        RECT  0 64.176 0.084 64.2 ;
    END
  END b_odata[51]
  PIN b_odata[52]
    DIRECTION INPUT ;
    USE SIGNAL ;
    PORT
      LAYER M4 ;
        RECT  0 64.272 0.084 64.296 ;
    END
  END b_odata[52]
  PIN b_odata[53]
    DIRECTION INPUT ;
    USE SIGNAL ;
    PORT
      LAYER M4 ;
        RECT  0 64.368 0.084 64.392 ;
    END
  END b_odata[53]
  PIN b_odata[54]
    DIRECTION INPUT ;
    USE SIGNAL ;
    PORT
      LAYER M4 ;
        RECT  0 64.464 0.084 64.488 ;
    END
  END b_odata[54]
  PIN b_odata[55]
    DIRECTION INPUT ;
    USE SIGNAL ;
    PORT
      LAYER M4 ;
        RECT  0 64.56 0.084 64.584 ;
    END
  END b_odata[55]
  PIN b_odata[56]
    DIRECTION INPUT ;
    USE SIGNAL ;
    PORT
      LAYER M4 ;
        RECT  0 64.656 0.084 64.68 ;
    END
  END b_odata[56]
  PIN b_odata[57]
    DIRECTION INPUT ;
    USE SIGNAL ;
    PORT
      LAYER M4 ;
        RECT  0 64.752 0.084 64.776 ;
    END
  END b_odata[57]
  PIN b_odata[58]
    DIRECTION INPUT ;
    USE SIGNAL ;
    PORT
      LAYER M4 ;
        RECT  0 64.848 0.084 64.872 ;
    END
  END b_odata[58]
  PIN b_odata[59]
    DIRECTION INPUT ;
    USE SIGNAL ;
    PORT
      LAYER M4 ;
        RECT  0 64.944 0.084 64.968 ;
    END
  END b_odata[59]
  PIN b_odata[5]
    DIRECTION INPUT ;
    USE SIGNAL ;
    PORT
      LAYER M4 ;
        RECT  0 37.488 0.084 37.512 ;
    END
  END b_odata[5]
  PIN b_odata[60]
    DIRECTION INPUT ;
    USE SIGNAL ;
    PORT
      LAYER M4 ;
        RECT  0 65.04 0.084 65.064 ;
    END
  END b_odata[60]
  PIN b_odata[61]
    DIRECTION INPUT ;
    USE SIGNAL ;
    PORT
      LAYER M4 ;
        RECT  0 65.136 0.084 65.16 ;
    END
  END b_odata[61]
  PIN b_odata[62]
    DIRECTION INPUT ;
    USE SIGNAL ;
    PORT
      LAYER M4 ;
        RECT  0 65.232 0.084 65.256 ;
    END
  END b_odata[62]
  PIN b_odata[63]
    DIRECTION INPUT ;
    USE SIGNAL ;
    PORT
      LAYER M4 ;
        RECT  0 65.328 0.084 65.352 ;
    END
  END b_odata[63]
  PIN b_odata[64]
    DIRECTION INPUT ;
    USE SIGNAL ;
    PORT
      LAYER M4 ;
        RECT  0 65.424 0.084 65.448 ;
    END
  END b_odata[64]
  PIN b_odata[65]
    DIRECTION INPUT ;
    USE SIGNAL ;
    PORT
      LAYER M4 ;
        RECT  0 65.52 0.084 65.544 ;
    END
  END b_odata[65]
  PIN b_odata[66]
    DIRECTION INPUT ;
    USE SIGNAL ;
    PORT
      LAYER M4 ;
        RECT  0 65.616 0.084 65.64 ;
    END
  END b_odata[66]
  PIN b_odata[67]
    DIRECTION INPUT ;
    USE SIGNAL ;
    PORT
      LAYER M4 ;
        RECT  0 65.712 0.084 65.736 ;
    END
  END b_odata[67]
  PIN b_odata[68]
    DIRECTION INPUT ;
    USE SIGNAL ;
    PORT
      LAYER M4 ;
        RECT  0 65.808 0.084 65.832 ;
    END
  END b_odata[68]
  PIN b_odata[69]
    DIRECTION INPUT ;
    USE SIGNAL ;
    PORT
      LAYER M4 ;
        RECT  0 65.904 0.084 65.928 ;
    END
  END b_odata[69]
  PIN b_odata[6]
    DIRECTION INPUT ;
    USE SIGNAL ;
    PORT
      LAYER M4 ;
        RECT  0 37.584 0.084 37.608 ;
    END
  END b_odata[6]
  PIN b_odata[70]
    DIRECTION INPUT ;
    USE SIGNAL ;
    PORT
      LAYER M4 ;
        RECT  0 66 0.084 66.024 ;
    END
  END b_odata[70]
  PIN b_odata[71]
    DIRECTION INPUT ;
    USE SIGNAL ;
    PORT
      LAYER M4 ;
        RECT  0 66.096 0.084 66.12 ;
    END
  END b_odata[71]
  PIN b_odata[72]
    DIRECTION INPUT ;
    USE SIGNAL ;
    PORT
      LAYER M4 ;
        RECT  0 66.192 0.084 66.216 ;
    END
  END b_odata[72]
  PIN b_odata[73]
    DIRECTION INPUT ;
    USE SIGNAL ;
    PORT
      LAYER M4 ;
        RECT  0 66.288 0.084 66.312 ;
    END
  END b_odata[73]
  PIN b_odata[74]
    DIRECTION INPUT ;
    USE SIGNAL ;
    PORT
      LAYER M4 ;
        RECT  0 66.384 0.084 66.408 ;
    END
  END b_odata[74]
  PIN b_odata[75]
    DIRECTION INPUT ;
    USE SIGNAL ;
    PORT
      LAYER M4 ;
        RECT  0 60.336 0.084 60.36 ;
    END
  END b_odata[75]
  PIN b_odata[76]
    DIRECTION INPUT ;
    USE SIGNAL ;
    PORT
      LAYER M4 ;
        RECT  0 60.432 0.084 60.456 ;
    END
  END b_odata[76]
  PIN b_odata[77]
    DIRECTION INPUT ;
    USE SIGNAL ;
    PORT
      LAYER M4 ;
        RECT  0 60.528 0.084 60.552 ;
    END
  END b_odata[77]
  PIN b_odata[78]
    DIRECTION INPUT ;
    USE SIGNAL ;
    PORT
      LAYER M4 ;
        RECT  0 60.624 0.084 60.648 ;
    END
  END b_odata[78]
  PIN b_odata[79]
    DIRECTION INPUT ;
    USE SIGNAL ;
    PORT
      LAYER M4 ;
        RECT  0 60.72 0.084 60.744 ;
    END
  END b_odata[79]
  PIN b_odata[7]
    DIRECTION INPUT ;
    USE SIGNAL ;
    PORT
      LAYER M4 ;
        RECT  0 37.68 0.084 37.704 ;
    END
  END b_odata[7]
  PIN b_odata[80]
    DIRECTION INPUT ;
    USE SIGNAL ;
    PORT
      LAYER M4 ;
        RECT  0 60.816 0.084 60.84 ;
    END
  END b_odata[80]
  PIN b_odata[81]
    DIRECTION INPUT ;
    USE SIGNAL ;
    PORT
      LAYER M4 ;
        RECT  0 60.912 0.084 60.936 ;
    END
  END b_odata[81]
  PIN b_odata[82]
    DIRECTION INPUT ;
    USE SIGNAL ;
    PORT
      LAYER M4 ;
        RECT  0 61.008 0.084 61.032 ;
    END
  END b_odata[82]
  PIN b_odata[83]
    DIRECTION INPUT ;
    USE SIGNAL ;
    PORT
      LAYER M4 ;
        RECT  0 61.104 0.084 61.128 ;
    END
  END b_odata[83]
  PIN b_odata[84]
    DIRECTION INPUT ;
    USE SIGNAL ;
    PORT
      LAYER M4 ;
        RECT  0 61.2 0.084 61.224 ;
    END
  END b_odata[84]
  PIN b_odata[85]
    DIRECTION INPUT ;
    USE SIGNAL ;
    PORT
      LAYER M4 ;
        RECT  0 61.296 0.084 61.32 ;
    END
  END b_odata[85]
  PIN b_odata[86]
    DIRECTION INPUT ;
    USE SIGNAL ;
    PORT
      LAYER M4 ;
        RECT  0 61.392 0.084 61.416 ;
    END
  END b_odata[86]
  PIN b_odata[87]
    DIRECTION INPUT ;
    USE SIGNAL ;
    PORT
      LAYER M4 ;
        RECT  0 61.488 0.084 61.512 ;
    END
  END b_odata[87]
  PIN b_odata[88]
    DIRECTION INPUT ;
    USE SIGNAL ;
    PORT
      LAYER M4 ;
        RECT  0 61.584 0.084 61.608 ;
    END
  END b_odata[88]
  PIN b_odata[89]
    DIRECTION INPUT ;
    USE SIGNAL ;
    PORT
      LAYER M4 ;
        RECT  0 61.68 0.084 61.704 ;
    END
  END b_odata[89]
  PIN b_odata[8]
    DIRECTION INPUT ;
    USE SIGNAL ;
    PORT
      LAYER M4 ;
        RECT  0 37.776 0.084 37.8 ;
    END
  END b_odata[8]
  PIN b_odata[90]
    DIRECTION INPUT ;
    USE SIGNAL ;
    PORT
      LAYER M4 ;
        RECT  0 61.776 0.084 61.8 ;
    END
  END b_odata[90]
  PIN b_odata[91]
    DIRECTION INPUT ;
    USE SIGNAL ;
    PORT
      LAYER M4 ;
        RECT  0 61.872 0.084 61.896 ;
    END
  END b_odata[91]
  PIN b_odata[92]
    DIRECTION INPUT ;
    USE SIGNAL ;
    PORT
      LAYER M4 ;
        RECT  0 61.968 0.084 61.992 ;
    END
  END b_odata[92]
  PIN b_odata[93]
    DIRECTION INPUT ;
    USE SIGNAL ;
    PORT
      LAYER M4 ;
        RECT  0 62.064 0.084 62.088 ;
    END
  END b_odata[93]
  PIN b_odata[94]
    DIRECTION INPUT ;
    USE SIGNAL ;
    PORT
      LAYER M4 ;
        RECT  0 62.16 0.084 62.184 ;
    END
  END b_odata[94]
  PIN b_odata[95]
    DIRECTION INPUT ;
    USE SIGNAL ;
    PORT
      LAYER M4 ;
        RECT  0 62.256 0.084 62.28 ;
    END
  END b_odata[95]
  PIN b_odata[96]
    DIRECTION INPUT ;
    USE SIGNAL ;
    PORT
      LAYER M4 ;
        RECT  0 62.352 0.084 62.376 ;
    END
  END b_odata[96]
  PIN b_odata[97]
    DIRECTION INPUT ;
    USE SIGNAL ;
    PORT
      LAYER M4 ;
        RECT  0 62.448 0.084 62.472 ;
    END
  END b_odata[97]
  PIN b_odata[98]
    DIRECTION INPUT ;
    USE SIGNAL ;
    PORT
      LAYER M4 ;
        RECT  0 62.544 0.084 62.568 ;
    END
  END b_odata[98]
  PIN b_odata[99]
    DIRECTION INPUT ;
    USE SIGNAL ;
    PORT
      LAYER M4 ;
        RECT  0 62.64 0.084 62.664 ;
    END
  END b_odata[99]
  PIN b_odata[9]
    DIRECTION INPUT ;
    USE SIGNAL ;
    PORT
      LAYER M4 ;
        RECT  0 37.872 0.084 37.896 ;
    END
  END b_odata[9]
  PIN b_ov
    DIRECTION INPUT ;
    USE SIGNAL ;
    PORT
      LAYER M4 ;
        RECT  0 24.816 0.084 24.84 ;
    END
  END b_ov
  PIN clk
    DIRECTION INPUT ;
    USE SIGNAL ;
    PORT
      LAYER M3 ;
        RECT  17.748 86.363 17.766 86.4 ;
    END
  END clk
  PIN d_line[0]
    DIRECTION INPUT ;
    USE SIGNAL ;
    PORT
      LAYER M3 ;
        RECT  17.82 86.363 17.838 86.4 ;
    END
  END d_line[0]
  PIN d_line[10]
    DIRECTION INPUT ;
    USE SIGNAL ;
    PORT
      LAYER M3 ;
        RECT  18.54 86.363 18.558 86.4 ;
    END
  END d_line[10]
  PIN d_line[11]
    DIRECTION INPUT ;
    USE SIGNAL ;
    PORT
      LAYER M3 ;
        RECT  18.612 86.363 18.63 86.4 ;
    END
  END d_line[11]
  PIN d_line[12]
    DIRECTION INPUT ;
    USE SIGNAL ;
    PORT
      LAYER M3 ;
        RECT  18.684 86.363 18.702 86.4 ;
    END
  END d_line[12]
  PIN d_line[13]
    DIRECTION INPUT ;
    USE SIGNAL ;
    PORT
      LAYER M3 ;
        RECT  18.756 86.363 18.774 86.4 ;
    END
  END d_line[13]
  PIN d_line[14]
    DIRECTION INPUT ;
    USE SIGNAL ;
    PORT
      LAYER M3 ;
        RECT  18.828 86.363 18.846 86.4 ;
    END
  END d_line[14]
  PIN d_line[15]
    DIRECTION INPUT ;
    USE SIGNAL ;
    PORT
      LAYER M3 ;
        RECT  18.9 86.363 18.918 86.4 ;
    END
  END d_line[15]
  PIN d_line[16]
    DIRECTION INPUT ;
    USE SIGNAL ;
    PORT
      LAYER M3 ;
        RECT  18.972 86.363 18.99 86.4 ;
    END
  END d_line[16]
  PIN d_line[17]
    DIRECTION INPUT ;
    USE SIGNAL ;
    PORT
      LAYER M3 ;
        RECT  19.044 86.363 19.062 86.4 ;
    END
  END d_line[17]
  PIN d_line[1]
    DIRECTION INPUT ;
    USE SIGNAL ;
    PORT
      LAYER M3 ;
        RECT  17.892 86.363 17.91 86.4 ;
    END
  END d_line[1]
  PIN d_line[2]
    DIRECTION INPUT ;
    USE SIGNAL ;
    PORT
      LAYER M3 ;
        RECT  17.964 86.363 17.982 86.4 ;
    END
  END d_line[2]
  PIN d_line[3]
    DIRECTION INPUT ;
    USE SIGNAL ;
    PORT
      LAYER M3 ;
        RECT  18.036 86.363 18.054 86.4 ;
    END
  END d_line[3]
  PIN d_line[4]
    DIRECTION INPUT ;
    USE SIGNAL ;
    PORT
      LAYER M3 ;
        RECT  18.108 86.363 18.126 86.4 ;
    END
  END d_line[4]
  PIN d_line[5]
    DIRECTION INPUT ;
    USE SIGNAL ;
    PORT
      LAYER M3 ;
        RECT  18.18 86.363 18.198 86.4 ;
    END
  END d_line[5]
  PIN d_line[6]
    DIRECTION INPUT ;
    USE SIGNAL ;
    PORT
      LAYER M3 ;
        RECT  18.252 86.363 18.27 86.4 ;
    END
  END d_line[6]
  PIN d_line[7]
    DIRECTION INPUT ;
    USE SIGNAL ;
    PORT
      LAYER M3 ;
        RECT  18.324 86.363 18.342 86.4 ;
    END
  END d_line[7]
  PIN d_line[8]
    DIRECTION INPUT ;
    USE SIGNAL ;
    PORT
      LAYER M3 ;
        RECT  18.396 86.363 18.414 86.4 ;
    END
  END d_line[8]
  PIN d_line[9]
    DIRECTION INPUT ;
    USE SIGNAL ;
    PORT
      LAYER M3 ;
        RECT  18.468 86.363 18.486 86.4 ;
    END
  END d_line[9]
  PIN d_tap[0]
    DIRECTION INPUT ;
    USE SIGNAL ;
    PORT
      LAYER M3 ;
        RECT  19.116 86.363 19.134 86.4 ;
    END
  END d_tap[0]
  PIN d_tap[1]
    DIRECTION INPUT ;
    USE SIGNAL ;
    PORT
      LAYER M3 ;
        RECT  19.188 86.363 19.206 86.4 ;
    END
  END d_tap[1]
  PIN d_tap[2]
    DIRECTION INPUT ;
    USE SIGNAL ;
    PORT
      LAYER M3 ;
        RECT  19.26 86.363 19.278 86.4 ;
    END
  END d_tap[2]
  PIN d_tap[3]
    DIRECTION INPUT ;
    USE SIGNAL ;
    PORT
      LAYER M3 ;
        RECT  19.332 86.363 19.35 86.4 ;
    END
  END d_tap[3]
  PIN d_tap[4]
    DIRECTION INPUT ;
    USE SIGNAL ;
    PORT
      LAYER M3 ;
        RECT  19.404 86.363 19.422 86.4 ;
    END
  END d_tap[4]
  PIN d_tap[5]
    DIRECTION INPUT ;
    USE SIGNAL ;
    PORT
      LAYER M3 ;
        RECT  19.476 86.363 19.494 86.4 ;
    END
  END d_tap[5]
  PIN d_tap[6]
    DIRECTION INPUT ;
    USE SIGNAL ;
    PORT
      LAYER M3 ;
        RECT  19.548 86.363 19.566 86.4 ;
    END
  END d_tap[6]
  PIN d_tap[7]
    DIRECTION INPUT ;
    USE SIGNAL ;
    PORT
      LAYER M3 ;
        RECT  19.62 86.363 19.638 86.4 ;
    END
  END d_tap[7]
  PIN d_tap[8]
    DIRECTION INPUT ;
    USE SIGNAL ;
    PORT
      LAYER M3 ;
        RECT  19.692 86.363 19.71 86.4 ;
    END
  END d_tap[8]
  PIN d_v
    DIRECTION INPUT ;
    USE SIGNAL ;
    PORT
      LAYER M3 ;
        RECT  19.764 86.363 19.782 86.4 ;
    END
  END d_v
  PIN fault
    DIRECTION OUTPUT ;
    USE SIGNAL ;
    PORT
      LAYER M4 ;
        RECT  0 24.912 0.084 24.936 ;
    END
  END fault
  PIN n_line[0]
    DIRECTION OUTPUT ;
    USE SIGNAL ;
    PORT
      LAYER M3 ;
        RECT  17.244 0 17.262 0.037 ;
    END
  END n_line[0]
  PIN n_line[10]
    DIRECTION OUTPUT ;
    USE SIGNAL ;
    PORT
      LAYER M3 ;
        RECT  17.964 0 17.982 0.037 ;
    END
  END n_line[10]
  PIN n_line[11]
    DIRECTION OUTPUT ;
    USE SIGNAL ;
    PORT
      LAYER M3 ;
        RECT  18.036 0 18.054 0.037 ;
    END
  END n_line[11]
  PIN n_line[12]
    DIRECTION OUTPUT ;
    USE SIGNAL ;
    PORT
      LAYER M3 ;
        RECT  18.108 0 18.126 0.037 ;
    END
  END n_line[12]
  PIN n_line[13]
    DIRECTION OUTPUT ;
    USE SIGNAL ;
    PORT
      LAYER M3 ;
        RECT  18.18 0 18.198 0.037 ;
    END
  END n_line[13]
  PIN n_line[14]
    DIRECTION OUTPUT ;
    USE SIGNAL ;
    PORT
      LAYER M3 ;
        RECT  18.252 0 18.27 0.037 ;
    END
  END n_line[14]
  PIN n_line[15]
    DIRECTION OUTPUT ;
    USE SIGNAL ;
    PORT
      LAYER M3 ;
        RECT  18.324 0 18.342 0.037 ;
    END
  END n_line[15]
  PIN n_line[16]
    DIRECTION OUTPUT ;
    USE SIGNAL ;
    PORT
      LAYER M3 ;
        RECT  18.396 0 18.414 0.037 ;
    END
  END n_line[16]
  PIN n_line[17]
    DIRECTION OUTPUT ;
    USE SIGNAL ;
    PORT
      LAYER M3 ;
        RECT  18.468 0 18.486 0.037 ;
    END
  END n_line[17]
  PIN n_line[1]
    DIRECTION OUTPUT ;
    USE SIGNAL ;
    PORT
      LAYER M3 ;
        RECT  17.316 0 17.334 0.037 ;
    END
  END n_line[1]
  PIN n_line[2]
    DIRECTION OUTPUT ;
    USE SIGNAL ;
    PORT
      LAYER M3 ;
        RECT  17.388 0 17.406 0.037 ;
    END
  END n_line[2]
  PIN n_line[3]
    DIRECTION OUTPUT ;
    USE SIGNAL ;
    PORT
      LAYER M3 ;
        RECT  17.46 0 17.478 0.037 ;
    END
  END n_line[3]
  PIN n_line[4]
    DIRECTION OUTPUT ;
    USE SIGNAL ;
    PORT
      LAYER M3 ;
        RECT  17.532 0 17.55 0.037 ;
    END
  END n_line[4]
  PIN n_line[5]
    DIRECTION OUTPUT ;
    USE SIGNAL ;
    PORT
      LAYER M3 ;
        RECT  17.604 0 17.622 0.037 ;
    END
  END n_line[5]
  PIN n_line[6]
    DIRECTION OUTPUT ;
    USE SIGNAL ;
    PORT
      LAYER M3 ;
        RECT  17.676 0 17.694 0.037 ;
    END
  END n_line[6]
  PIN n_line[7]
    DIRECTION OUTPUT ;
    USE SIGNAL ;
    PORT
      LAYER M3 ;
        RECT  17.748 0 17.766 0.037 ;
    END
  END n_line[7]
  PIN n_line[8]
    DIRECTION OUTPUT ;
    USE SIGNAL ;
    PORT
      LAYER M3 ;
        RECT  17.82 0 17.838 0.037 ;
    END
  END n_line[8]
  PIN n_line[9]
    DIRECTION OUTPUT ;
    USE SIGNAL ;
    PORT
      LAYER M3 ;
        RECT  17.892 0 17.91 0.037 ;
    END
  END n_line[9]
  PIN n_tap[0]
    DIRECTION OUTPUT ;
    USE SIGNAL ;
    PORT
      LAYER M3 ;
        RECT  18.54 0 18.558 0.037 ;
    END
  END n_tap[0]
  PIN n_tap[1]
    DIRECTION OUTPUT ;
    USE SIGNAL ;
    PORT
      LAYER M3 ;
        RECT  18.612 0 18.63 0.037 ;
    END
  END n_tap[1]
  PIN n_tap[2]
    DIRECTION OUTPUT ;
    USE SIGNAL ;
    PORT
      LAYER M3 ;
        RECT  18.684 0 18.702 0.037 ;
    END
  END n_tap[2]
  PIN n_tap[3]
    DIRECTION OUTPUT ;
    USE SIGNAL ;
    PORT
      LAYER M3 ;
        RECT  18.756 0 18.774 0.037 ;
    END
  END n_tap[3]
  PIN n_tap[4]
    DIRECTION OUTPUT ;
    USE SIGNAL ;
    PORT
      LAYER M3 ;
        RECT  18.828 0 18.846 0.037 ;
    END
  END n_tap[4]
  PIN n_tap[5]
    DIRECTION OUTPUT ;
    USE SIGNAL ;
    PORT
      LAYER M3 ;
        RECT  18.9 0 18.918 0.037 ;
    END
  END n_tap[5]
  PIN n_tap[6]
    DIRECTION OUTPUT ;
    USE SIGNAL ;
    PORT
      LAYER M3 ;
        RECT  18.972 0 18.99 0.037 ;
    END
  END n_tap[6]
  PIN n_tap[7]
    DIRECTION OUTPUT ;
    USE SIGNAL ;
    PORT
      LAYER M3 ;
        RECT  19.044 0 19.062 0.037 ;
    END
  END n_tap[7]
  PIN n_tap[8]
    DIRECTION OUTPUT ;
    USE SIGNAL ;
    PORT
      LAYER M3 ;
        RECT  19.116 0 19.134 0.037 ;
    END
  END n_tap[8]
  PIN n_v
    DIRECTION OUTPUT ;
    USE SIGNAL ;
    PORT
      LAYER M3 ;
        RECT  19.188 0 19.206 0.037 ;
    END
  END n_v
  PIN p_data[0]
    DIRECTION OUTPUT ;
    USE SIGNAL ;
    PORT
      LAYER M3 ;
        RECT  19.836 86.363 19.854 86.4 ;
    END
  END p_data[0]
  PIN p_data[100]
    DIRECTION OUTPUT ;
    USE SIGNAL ;
    PORT
      LAYER M5 ;
        RECT  18.864 86.316 18.888 86.4 ;
    END
  END p_data[100]
  PIN p_data[101]
    DIRECTION OUTPUT ;
    USE SIGNAL ;
    PORT
      LAYER M5 ;
        RECT  18.96 86.316 18.984 86.4 ;
    END
  END p_data[101]
  PIN p_data[102]
    DIRECTION OUTPUT ;
    USE SIGNAL ;
    PORT
      LAYER M5 ;
        RECT  19.056 86.316 19.08 86.4 ;
    END
  END p_data[102]
  PIN p_data[103]
    DIRECTION OUTPUT ;
    USE SIGNAL ;
    PORT
      LAYER M5 ;
        RECT  19.152 86.316 19.176 86.4 ;
    END
  END p_data[103]
  PIN p_data[104]
    DIRECTION OUTPUT ;
    USE SIGNAL ;
    PORT
      LAYER M5 ;
        RECT  19.248 86.316 19.272 86.4 ;
    END
  END p_data[104]
  PIN p_data[105]
    DIRECTION OUTPUT ;
    USE SIGNAL ;
    PORT
      LAYER M5 ;
        RECT  19.344 86.316 19.368 86.4 ;
    END
  END p_data[105]
  PIN p_data[106]
    DIRECTION OUTPUT ;
    USE SIGNAL ;
    PORT
      LAYER M5 ;
        RECT  19.44 86.316 19.464 86.4 ;
    END
  END p_data[106]
  PIN p_data[107]
    DIRECTION OUTPUT ;
    USE SIGNAL ;
    PORT
      LAYER M5 ;
        RECT  19.536 86.316 19.56 86.4 ;
    END
  END p_data[107]
  PIN p_data[108]
    DIRECTION OUTPUT ;
    USE SIGNAL ;
    PORT
      LAYER M5 ;
        RECT  19.632 86.316 19.656 86.4 ;
    END
  END p_data[108]
  PIN p_data[109]
    DIRECTION OUTPUT ;
    USE SIGNAL ;
    PORT
      LAYER M5 ;
        RECT  19.728 86.316 19.752 86.4 ;
    END
  END p_data[109]
  PIN p_data[10]
    DIRECTION OUTPUT ;
    USE SIGNAL ;
    PORT
      LAYER M3 ;
        RECT  25.74 86.363 25.758 86.4 ;
    END
  END p_data[10]
  PIN p_data[110]
    DIRECTION OUTPUT ;
    USE SIGNAL ;
    PORT
      LAYER M5 ;
        RECT  19.824 86.316 19.848 86.4 ;
    END
  END p_data[110]
  PIN p_data[111]
    DIRECTION OUTPUT ;
    USE SIGNAL ;
    PORT
      LAYER M5 ;
        RECT  19.92 86.316 19.944 86.4 ;
    END
  END p_data[111]
  PIN p_data[112]
    DIRECTION OUTPUT ;
    USE SIGNAL ;
    PORT
      LAYER M5 ;
        RECT  20.016 86.316 20.04 86.4 ;
    END
  END p_data[112]
  PIN p_data[113]
    DIRECTION OUTPUT ;
    USE SIGNAL ;
    PORT
      LAYER M5 ;
        RECT  20.112 86.316 20.136 86.4 ;
    END
  END p_data[113]
  PIN p_data[114]
    DIRECTION OUTPUT ;
    USE SIGNAL ;
    PORT
      LAYER M5 ;
        RECT  20.208 86.316 20.232 86.4 ;
    END
  END p_data[114]
  PIN p_data[115]
    DIRECTION OUTPUT ;
    USE SIGNAL ;
    PORT
      LAYER M5 ;
        RECT  20.304 86.316 20.328 86.4 ;
    END
  END p_data[115]
  PIN p_data[116]
    DIRECTION OUTPUT ;
    USE SIGNAL ;
    PORT
      LAYER M5 ;
        RECT  20.4 86.316 20.424 86.4 ;
    END
  END p_data[116]
  PIN p_data[117]
    DIRECTION OUTPUT ;
    USE SIGNAL ;
    PORT
      LAYER M5 ;
        RECT  20.496 86.316 20.52 86.4 ;
    END
  END p_data[117]
  PIN p_data[118]
    DIRECTION OUTPUT ;
    USE SIGNAL ;
    PORT
      LAYER M5 ;
        RECT  20.592 86.316 20.616 86.4 ;
    END
  END p_data[118]
  PIN p_data[119]
    DIRECTION OUTPUT ;
    USE SIGNAL ;
    PORT
      LAYER M5 ;
        RECT  20.688 86.316 20.712 86.4 ;
    END
  END p_data[119]
  PIN p_data[11]
    DIRECTION OUTPUT ;
    USE SIGNAL ;
    PORT
      LAYER M3 ;
        RECT  25.812 86.363 25.83 86.4 ;
    END
  END p_data[11]
  PIN p_data[120]
    DIRECTION OUTPUT ;
    USE SIGNAL ;
    PORT
      LAYER M5 ;
        RECT  20.784 86.316 20.808 86.4 ;
    END
  END p_data[120]
  PIN p_data[121]
    DIRECTION OUTPUT ;
    USE SIGNAL ;
    PORT
      LAYER M5 ;
        RECT  20.88 86.316 20.904 86.4 ;
    END
  END p_data[121]
  PIN p_data[122]
    DIRECTION OUTPUT ;
    USE SIGNAL ;
    PORT
      LAYER M5 ;
        RECT  20.976 86.316 21 86.4 ;
    END
  END p_data[122]
  PIN p_data[123]
    DIRECTION OUTPUT ;
    USE SIGNAL ;
    PORT
      LAYER M5 ;
        RECT  21.072 86.316 21.096 86.4 ;
    END
  END p_data[123]
  PIN p_data[124]
    DIRECTION OUTPUT ;
    USE SIGNAL ;
    PORT
      LAYER M5 ;
        RECT  21.168 86.316 21.192 86.4 ;
    END
  END p_data[124]
  PIN p_data[125]
    DIRECTION OUTPUT ;
    USE SIGNAL ;
    PORT
      LAYER M5 ;
        RECT  21.264 86.316 21.288 86.4 ;
    END
  END p_data[125]
  PIN p_data[126]
    DIRECTION OUTPUT ;
    USE SIGNAL ;
    PORT
      LAYER M5 ;
        RECT  21.36 86.316 21.384 86.4 ;
    END
  END p_data[126]
  PIN p_data[127]
    DIRECTION OUTPUT ;
    USE SIGNAL ;
    PORT
      LAYER M5 ;
        RECT  21.456 86.316 21.48 86.4 ;
    END
  END p_data[127]
  PIN p_data[128]
    DIRECTION OUTPUT ;
    USE SIGNAL ;
    PORT
      LAYER M5 ;
        RECT  21.552 86.316 21.576 86.4 ;
    END
  END p_data[128]
  PIN p_data[129]
    DIRECTION OUTPUT ;
    USE SIGNAL ;
    PORT
      LAYER M5 ;
        RECT  21.648 86.316 21.672 86.4 ;
    END
  END p_data[129]
  PIN p_data[12]
    DIRECTION OUTPUT ;
    USE SIGNAL ;
    PORT
      LAYER M3 ;
        RECT  25.884 86.363 25.902 86.4 ;
    END
  END p_data[12]
  PIN p_data[130]
    DIRECTION OUTPUT ;
    USE SIGNAL ;
    PORT
      LAYER M5 ;
        RECT  21.744 86.316 21.768 86.4 ;
    END
  END p_data[130]
  PIN p_data[131]
    DIRECTION OUTPUT ;
    USE SIGNAL ;
    PORT
      LAYER M5 ;
        RECT  21.84 86.316 21.864 86.4 ;
    END
  END p_data[131]
  PIN p_data[132]
    DIRECTION OUTPUT ;
    USE SIGNAL ;
    PORT
      LAYER M5 ;
        RECT  21.936 86.316 21.96 86.4 ;
    END
  END p_data[132]
  PIN p_data[133]
    DIRECTION OUTPUT ;
    USE SIGNAL ;
    PORT
      LAYER M5 ;
        RECT  22.032 86.316 22.056 86.4 ;
    END
  END p_data[133]
  PIN p_data[134]
    DIRECTION OUTPUT ;
    USE SIGNAL ;
    PORT
      LAYER M5 ;
        RECT  22.128 86.316 22.152 86.4 ;
    END
  END p_data[134]
  PIN p_data[135]
    DIRECTION OUTPUT ;
    USE SIGNAL ;
    PORT
      LAYER M5 ;
        RECT  22.224 86.316 22.248 86.4 ;
    END
  END p_data[135]
  PIN p_data[136]
    DIRECTION OUTPUT ;
    USE SIGNAL ;
    PORT
      LAYER M5 ;
        RECT  22.32 86.316 22.344 86.4 ;
    END
  END p_data[136]
  PIN p_data[137]
    DIRECTION OUTPUT ;
    USE SIGNAL ;
    PORT
      LAYER M5 ;
        RECT  22.416 86.316 22.44 86.4 ;
    END
  END p_data[137]
  PIN p_data[138]
    DIRECTION OUTPUT ;
    USE SIGNAL ;
    PORT
      LAYER M5 ;
        RECT  22.512 86.316 22.536 86.4 ;
    END
  END p_data[138]
  PIN p_data[139]
    DIRECTION OUTPUT ;
    USE SIGNAL ;
    PORT
      LAYER M5 ;
        RECT  22.608 86.316 22.632 86.4 ;
    END
  END p_data[139]
  PIN p_data[13]
    DIRECTION OUTPUT ;
    USE SIGNAL ;
    PORT
      LAYER M3 ;
        RECT  25.956 86.363 25.974 86.4 ;
    END
  END p_data[13]
  PIN p_data[140]
    DIRECTION OUTPUT ;
    USE SIGNAL ;
    PORT
      LAYER M5 ;
        RECT  22.704 86.316 22.728 86.4 ;
    END
  END p_data[140]
  PIN p_data[141]
    DIRECTION OUTPUT ;
    USE SIGNAL ;
    PORT
      LAYER M5 ;
        RECT  22.8 86.316 22.824 86.4 ;
    END
  END p_data[141]
  PIN p_data[142]
    DIRECTION OUTPUT ;
    USE SIGNAL ;
    PORT
      LAYER M5 ;
        RECT  22.896 86.316 22.92 86.4 ;
    END
  END p_data[142]
  PIN p_data[143]
    DIRECTION OUTPUT ;
    USE SIGNAL ;
    PORT
      LAYER M5 ;
        RECT  22.992 86.316 23.016 86.4 ;
    END
  END p_data[143]
  PIN p_data[144]
    DIRECTION OUTPUT ;
    USE SIGNAL ;
    PORT
      LAYER M5 ;
        RECT  23.088 86.316 23.112 86.4 ;
    END
  END p_data[144]
  PIN p_data[145]
    DIRECTION OUTPUT ;
    USE SIGNAL ;
    PORT
      LAYER M5 ;
        RECT  23.184 86.316 23.208 86.4 ;
    END
  END p_data[145]
  PIN p_data[146]
    DIRECTION OUTPUT ;
    USE SIGNAL ;
    PORT
      LAYER M5 ;
        RECT  23.28 86.316 23.304 86.4 ;
    END
  END p_data[146]
  PIN p_data[147]
    DIRECTION OUTPUT ;
    USE SIGNAL ;
    PORT
      LAYER M5 ;
        RECT  23.376 86.316 23.4 86.4 ;
    END
  END p_data[147]
  PIN p_data[148]
    DIRECTION OUTPUT ;
    USE SIGNAL ;
    PORT
      LAYER M5 ;
        RECT  23.472 86.316 23.496 86.4 ;
    END
  END p_data[148]
  PIN p_data[149]
    DIRECTION OUTPUT ;
    USE SIGNAL ;
    PORT
      LAYER M5 ;
        RECT  23.568 86.316 23.592 86.4 ;
    END
  END p_data[149]
  PIN p_data[14]
    DIRECTION OUTPUT ;
    USE SIGNAL ;
    PORT
      LAYER M3 ;
        RECT  26.028 86.363 26.046 86.4 ;
    END
  END p_data[14]
  PIN p_data[150]
    DIRECTION OUTPUT ;
    USE SIGNAL ;
    PORT
      LAYER M5 ;
        RECT  23.664 86.316 23.688 86.4 ;
    END
  END p_data[150]
  PIN p_data[151]
    DIRECTION OUTPUT ;
    USE SIGNAL ;
    PORT
      LAYER M5 ;
        RECT  23.76 86.316 23.784 86.4 ;
    END
  END p_data[151]
  PIN p_data[152]
    DIRECTION OUTPUT ;
    USE SIGNAL ;
    PORT
      LAYER M5 ;
        RECT  23.856 86.316 23.88 86.4 ;
    END
  END p_data[152]
  PIN p_data[153]
    DIRECTION OUTPUT ;
    USE SIGNAL ;
    PORT
      LAYER M5 ;
        RECT  23.952 86.316 23.976 86.4 ;
    END
  END p_data[153]
  PIN p_data[154]
    DIRECTION OUTPUT ;
    USE SIGNAL ;
    PORT
      LAYER M5 ;
        RECT  24.048 86.316 24.072 86.4 ;
    END
  END p_data[154]
  PIN p_data[155]
    DIRECTION OUTPUT ;
    USE SIGNAL ;
    PORT
      LAYER M5 ;
        RECT  24.144 86.316 24.168 86.4 ;
    END
  END p_data[155]
  PIN p_data[156]
    DIRECTION OUTPUT ;
    USE SIGNAL ;
    PORT
      LAYER M5 ;
        RECT  24.24 86.316 24.264 86.4 ;
    END
  END p_data[156]
  PIN p_data[157]
    DIRECTION OUTPUT ;
    USE SIGNAL ;
    PORT
      LAYER M5 ;
        RECT  24.336 86.316 24.36 86.4 ;
    END
  END p_data[157]
  PIN p_data[158]
    DIRECTION OUTPUT ;
    USE SIGNAL ;
    PORT
      LAYER M5 ;
        RECT  24.432 86.316 24.456 86.4 ;
    END
  END p_data[158]
  PIN p_data[159]
    DIRECTION OUTPUT ;
    USE SIGNAL ;
    PORT
      LAYER M5 ;
        RECT  24.528 86.316 24.552 86.4 ;
    END
  END p_data[159]
  PIN p_data[15]
    DIRECTION OUTPUT ;
    USE SIGNAL ;
    PORT
      LAYER M3 ;
        RECT  26.1 86.363 26.118 86.4 ;
    END
  END p_data[15]
  PIN p_data[160]
    DIRECTION OUTPUT ;
    USE SIGNAL ;
    PORT
      LAYER M5 ;
        RECT  24.624 86.316 24.648 86.4 ;
    END
  END p_data[160]
  PIN p_data[161]
    DIRECTION OUTPUT ;
    USE SIGNAL ;
    PORT
      LAYER M5 ;
        RECT  24.72 86.316 24.744 86.4 ;
    END
  END p_data[161]
  PIN p_data[162]
    DIRECTION OUTPUT ;
    USE SIGNAL ;
    PORT
      LAYER M5 ;
        RECT  24.816 86.316 24.84 86.4 ;
    END
  END p_data[162]
  PIN p_data[163]
    DIRECTION OUTPUT ;
    USE SIGNAL ;
    PORT
      LAYER M5 ;
        RECT  31.056 86.316 31.08 86.4 ;
    END
  END p_data[163]
  PIN p_data[164]
    DIRECTION OUTPUT ;
    USE SIGNAL ;
    PORT
      LAYER M5 ;
        RECT  31.152 86.316 31.176 86.4 ;
    END
  END p_data[164]
  PIN p_data[165]
    DIRECTION OUTPUT ;
    USE SIGNAL ;
    PORT
      LAYER M5 ;
        RECT  31.248 86.316 31.272 86.4 ;
    END
  END p_data[165]
  PIN p_data[166]
    DIRECTION OUTPUT ;
    USE SIGNAL ;
    PORT
      LAYER M5 ;
        RECT  31.344 86.316 31.368 86.4 ;
    END
  END p_data[166]
  PIN p_data[167]
    DIRECTION OUTPUT ;
    USE SIGNAL ;
    PORT
      LAYER M5 ;
        RECT  31.44 86.316 31.464 86.4 ;
    END
  END p_data[167]
  PIN p_data[168]
    DIRECTION OUTPUT ;
    USE SIGNAL ;
    PORT
      LAYER M5 ;
        RECT  31.536 86.316 31.56 86.4 ;
    END
  END p_data[168]
  PIN p_data[169]
    DIRECTION OUTPUT ;
    USE SIGNAL ;
    PORT
      LAYER M5 ;
        RECT  31.632 86.316 31.656 86.4 ;
    END
  END p_data[169]
  PIN p_data[16]
    DIRECTION OUTPUT ;
    USE SIGNAL ;
    PORT
      LAYER M3 ;
        RECT  26.172 86.363 26.19 86.4 ;
    END
  END p_data[16]
  PIN p_data[170]
    DIRECTION OUTPUT ;
    USE SIGNAL ;
    PORT
      LAYER M5 ;
        RECT  31.728 86.316 31.752 86.4 ;
    END
  END p_data[170]
  PIN p_data[171]
    DIRECTION OUTPUT ;
    USE SIGNAL ;
    PORT
      LAYER M5 ;
        RECT  31.824 86.316 31.848 86.4 ;
    END
  END p_data[171]
  PIN p_data[172]
    DIRECTION OUTPUT ;
    USE SIGNAL ;
    PORT
      LAYER M5 ;
        RECT  31.92 86.316 31.944 86.4 ;
    END
  END p_data[172]
  PIN p_data[173]
    DIRECTION OUTPUT ;
    USE SIGNAL ;
    PORT
      LAYER M5 ;
        RECT  32.016 86.316 32.04 86.4 ;
    END
  END p_data[173]
  PIN p_data[174]
    DIRECTION OUTPUT ;
    USE SIGNAL ;
    PORT
      LAYER M5 ;
        RECT  32.112 86.316 32.136 86.4 ;
    END
  END p_data[174]
  PIN p_data[175]
    DIRECTION OUTPUT ;
    USE SIGNAL ;
    PORT
      LAYER M5 ;
        RECT  32.208 86.316 32.232 86.4 ;
    END
  END p_data[175]
  PIN p_data[176]
    DIRECTION OUTPUT ;
    USE SIGNAL ;
    PORT
      LAYER M5 ;
        RECT  32.304 86.316 32.328 86.4 ;
    END
  END p_data[176]
  PIN p_data[177]
    DIRECTION OUTPUT ;
    USE SIGNAL ;
    PORT
      LAYER M5 ;
        RECT  32.4 86.316 32.424 86.4 ;
    END
  END p_data[177]
  PIN p_data[178]
    DIRECTION OUTPUT ;
    USE SIGNAL ;
    PORT
      LAYER M5 ;
        RECT  32.496 86.316 32.52 86.4 ;
    END
  END p_data[178]
  PIN p_data[179]
    DIRECTION OUTPUT ;
    USE SIGNAL ;
    PORT
      LAYER M5 ;
        RECT  32.592 86.316 32.616 86.4 ;
    END
  END p_data[179]
  PIN p_data[17]
    DIRECTION OUTPUT ;
    USE SIGNAL ;
    PORT
      LAYER M3 ;
        RECT  26.244 86.363 26.262 86.4 ;
    END
  END p_data[17]
  PIN p_data[180]
    DIRECTION OUTPUT ;
    USE SIGNAL ;
    PORT
      LAYER M5 ;
        RECT  32.688 86.316 32.712 86.4 ;
    END
  END p_data[180]
  PIN p_data[181]
    DIRECTION OUTPUT ;
    USE SIGNAL ;
    PORT
      LAYER M5 ;
        RECT  32.784 86.316 32.808 86.4 ;
    END
  END p_data[181]
  PIN p_data[182]
    DIRECTION OUTPUT ;
    USE SIGNAL ;
    PORT
      LAYER M5 ;
        RECT  32.88 86.316 32.904 86.4 ;
    END
  END p_data[182]
  PIN p_data[183]
    DIRECTION OUTPUT ;
    USE SIGNAL ;
    PORT
      LAYER M5 ;
        RECT  32.976 86.316 33 86.4 ;
    END
  END p_data[183]
  PIN p_data[184]
    DIRECTION OUTPUT ;
    USE SIGNAL ;
    PORT
      LAYER M5 ;
        RECT  33.072 86.316 33.096 86.4 ;
    END
  END p_data[184]
  PIN p_data[185]
    DIRECTION OUTPUT ;
    USE SIGNAL ;
    PORT
      LAYER M5 ;
        RECT  33.168 86.316 33.192 86.4 ;
    END
  END p_data[185]
  PIN p_data[186]
    DIRECTION OUTPUT ;
    USE SIGNAL ;
    PORT
      LAYER M5 ;
        RECT  33.264 86.316 33.288 86.4 ;
    END
  END p_data[186]
  PIN p_data[187]
    DIRECTION OUTPUT ;
    USE SIGNAL ;
    PORT
      LAYER M5 ;
        RECT  33.36 86.316 33.384 86.4 ;
    END
  END p_data[187]
  PIN p_data[188]
    DIRECTION OUTPUT ;
    USE SIGNAL ;
    PORT
      LAYER M5 ;
        RECT  33.456 86.316 33.48 86.4 ;
    END
  END p_data[188]
  PIN p_data[189]
    DIRECTION OUTPUT ;
    USE SIGNAL ;
    PORT
      LAYER M5 ;
        RECT  33.552 86.316 33.576 86.4 ;
    END
  END p_data[189]
  PIN p_data[18]
    DIRECTION OUTPUT ;
    USE SIGNAL ;
    PORT
      LAYER M3 ;
        RECT  26.316 86.363 26.334 86.4 ;
    END
  END p_data[18]
  PIN p_data[190]
    DIRECTION OUTPUT ;
    USE SIGNAL ;
    PORT
      LAYER M5 ;
        RECT  33.648 86.316 33.672 86.4 ;
    END
  END p_data[190]
  PIN p_data[191]
    DIRECTION OUTPUT ;
    USE SIGNAL ;
    PORT
      LAYER M5 ;
        RECT  33.744 86.316 33.768 86.4 ;
    END
  END p_data[191]
  PIN p_data[192]
    DIRECTION OUTPUT ;
    USE SIGNAL ;
    PORT
      LAYER M5 ;
        RECT  33.84 86.316 33.864 86.4 ;
    END
  END p_data[192]
  PIN p_data[193]
    DIRECTION OUTPUT ;
    USE SIGNAL ;
    PORT
      LAYER M5 ;
        RECT  33.936 86.316 33.96 86.4 ;
    END
  END p_data[193]
  PIN p_data[194]
    DIRECTION OUTPUT ;
    USE SIGNAL ;
    PORT
      LAYER M5 ;
        RECT  34.032 86.316 34.056 86.4 ;
    END
  END p_data[194]
  PIN p_data[195]
    DIRECTION OUTPUT ;
    USE SIGNAL ;
    PORT
      LAYER M5 ;
        RECT  27.984 86.316 28.008 86.4 ;
    END
  END p_data[195]
  PIN p_data[196]
    DIRECTION OUTPUT ;
    USE SIGNAL ;
    PORT
      LAYER M5 ;
        RECT  28.08 86.316 28.104 86.4 ;
    END
  END p_data[196]
  PIN p_data[197]
    DIRECTION OUTPUT ;
    USE SIGNAL ;
    PORT
      LAYER M5 ;
        RECT  28.176 86.316 28.2 86.4 ;
    END
  END p_data[197]
  PIN p_data[198]
    DIRECTION OUTPUT ;
    USE SIGNAL ;
    PORT
      LAYER M5 ;
        RECT  28.272 86.316 28.296 86.4 ;
    END
  END p_data[198]
  PIN p_data[199]
    DIRECTION OUTPUT ;
    USE SIGNAL ;
    PORT
      LAYER M5 ;
        RECT  28.368 86.316 28.392 86.4 ;
    END
  END p_data[199]
  PIN p_data[19]
    DIRECTION OUTPUT ;
    USE SIGNAL ;
    PORT
      LAYER M3 ;
        RECT  26.388 86.363 26.406 86.4 ;
    END
  END p_data[19]
  PIN p_data[1]
    DIRECTION OUTPUT ;
    USE SIGNAL ;
    PORT
      LAYER M3 ;
        RECT  19.908 86.363 19.926 86.4 ;
    END
  END p_data[1]
  PIN p_data[200]
    DIRECTION OUTPUT ;
    USE SIGNAL ;
    PORT
      LAYER M5 ;
        RECT  28.464 86.316 28.488 86.4 ;
    END
  END p_data[200]
  PIN p_data[201]
    DIRECTION OUTPUT ;
    USE SIGNAL ;
    PORT
      LAYER M5 ;
        RECT  28.56 86.316 28.584 86.4 ;
    END
  END p_data[201]
  PIN p_data[202]
    DIRECTION OUTPUT ;
    USE SIGNAL ;
    PORT
      LAYER M5 ;
        RECT  28.656 86.316 28.68 86.4 ;
    END
  END p_data[202]
  PIN p_data[203]
    DIRECTION OUTPUT ;
    USE SIGNAL ;
    PORT
      LAYER M5 ;
        RECT  28.752 86.316 28.776 86.4 ;
    END
  END p_data[203]
  PIN p_data[204]
    DIRECTION OUTPUT ;
    USE SIGNAL ;
    PORT
      LAYER M5 ;
        RECT  28.848 86.316 28.872 86.4 ;
    END
  END p_data[204]
  PIN p_data[205]
    DIRECTION OUTPUT ;
    USE SIGNAL ;
    PORT
      LAYER M5 ;
        RECT  28.944 86.316 28.968 86.4 ;
    END
  END p_data[205]
  PIN p_data[206]
    DIRECTION OUTPUT ;
    USE SIGNAL ;
    PORT
      LAYER M5 ;
        RECT  29.04 86.316 29.064 86.4 ;
    END
  END p_data[206]
  PIN p_data[207]
    DIRECTION OUTPUT ;
    USE SIGNAL ;
    PORT
      LAYER M5 ;
        RECT  29.136 86.316 29.16 86.4 ;
    END
  END p_data[207]
  PIN p_data[208]
    DIRECTION OUTPUT ;
    USE SIGNAL ;
    PORT
      LAYER M5 ;
        RECT  29.232 86.316 29.256 86.4 ;
    END
  END p_data[208]
  PIN p_data[209]
    DIRECTION OUTPUT ;
    USE SIGNAL ;
    PORT
      LAYER M5 ;
        RECT  29.328 86.316 29.352 86.4 ;
    END
  END p_data[209]
  PIN p_data[20]
    DIRECTION OUTPUT ;
    USE SIGNAL ;
    PORT
      LAYER M3 ;
        RECT  26.46 86.363 26.478 86.4 ;
    END
  END p_data[20]
  PIN p_data[210]
    DIRECTION OUTPUT ;
    USE SIGNAL ;
    PORT
      LAYER M5 ;
        RECT  29.424 86.316 29.448 86.4 ;
    END
  END p_data[210]
  PIN p_data[211]
    DIRECTION OUTPUT ;
    USE SIGNAL ;
    PORT
      LAYER M5 ;
        RECT  29.52 86.316 29.544 86.4 ;
    END
  END p_data[211]
  PIN p_data[212]
    DIRECTION OUTPUT ;
    USE SIGNAL ;
    PORT
      LAYER M5 ;
        RECT  29.616 86.316 29.64 86.4 ;
    END
  END p_data[212]
  PIN p_data[213]
    DIRECTION OUTPUT ;
    USE SIGNAL ;
    PORT
      LAYER M5 ;
        RECT  29.712 86.316 29.736 86.4 ;
    END
  END p_data[213]
  PIN p_data[214]
    DIRECTION OUTPUT ;
    USE SIGNAL ;
    PORT
      LAYER M5 ;
        RECT  29.808 86.316 29.832 86.4 ;
    END
  END p_data[214]
  PIN p_data[215]
    DIRECTION OUTPUT ;
    USE SIGNAL ;
    PORT
      LAYER M5 ;
        RECT  29.904 86.316 29.928 86.4 ;
    END
  END p_data[215]
  PIN p_data[216]
    DIRECTION OUTPUT ;
    USE SIGNAL ;
    PORT
      LAYER M5 ;
        RECT  30 86.316 30.024 86.4 ;
    END
  END p_data[216]
  PIN p_data[217]
    DIRECTION OUTPUT ;
    USE SIGNAL ;
    PORT
      LAYER M5 ;
        RECT  30.096 86.316 30.12 86.4 ;
    END
  END p_data[217]
  PIN p_data[218]
    DIRECTION OUTPUT ;
    USE SIGNAL ;
    PORT
      LAYER M5 ;
        RECT  30.192 86.316 30.216 86.4 ;
    END
  END p_data[218]
  PIN p_data[219]
    DIRECTION OUTPUT ;
    USE SIGNAL ;
    PORT
      LAYER M5 ;
        RECT  30.288 86.316 30.312 86.4 ;
    END
  END p_data[219]
  PIN p_data[21]
    DIRECTION OUTPUT ;
    USE SIGNAL ;
    PORT
      LAYER M3 ;
        RECT  26.532 86.363 26.55 86.4 ;
    END
  END p_data[21]
  PIN p_data[220]
    DIRECTION OUTPUT ;
    USE SIGNAL ;
    PORT
      LAYER M5 ;
        RECT  30.384 86.316 30.408 86.4 ;
    END
  END p_data[220]
  PIN p_data[221]
    DIRECTION OUTPUT ;
    USE SIGNAL ;
    PORT
      LAYER M5 ;
        RECT  30.48 86.316 30.504 86.4 ;
    END
  END p_data[221]
  PIN p_data[222]
    DIRECTION OUTPUT ;
    USE SIGNAL ;
    PORT
      LAYER M5 ;
        RECT  30.576 86.316 30.6 86.4 ;
    END
  END p_data[222]
  PIN p_data[223]
    DIRECTION OUTPUT ;
    USE SIGNAL ;
    PORT
      LAYER M5 ;
        RECT  30.672 86.316 30.696 86.4 ;
    END
  END p_data[223]
  PIN p_data[224]
    DIRECTION OUTPUT ;
    USE SIGNAL ;
    PORT
      LAYER M5 ;
        RECT  30.768 86.316 30.792 86.4 ;
    END
  END p_data[224]
  PIN p_data[225]
    DIRECTION OUTPUT ;
    USE SIGNAL ;
    PORT
      LAYER M5 ;
        RECT  30.864 86.316 30.888 86.4 ;
    END
  END p_data[225]
  PIN p_data[226]
    DIRECTION OUTPUT ;
    USE SIGNAL ;
    PORT
      LAYER M5 ;
        RECT  30.96 86.316 30.984 86.4 ;
    END
  END p_data[226]
  PIN p_data[227]
    DIRECTION OUTPUT ;
    USE SIGNAL ;
    PORT
      LAYER M3 ;
        RECT  27.54 86.363 27.558 86.4 ;
    END
  END p_data[227]
  PIN p_data[228]
    DIRECTION OUTPUT ;
    USE SIGNAL ;
    PORT
      LAYER M3 ;
        RECT  27.612 86.363 27.63 86.4 ;
    END
  END p_data[228]
  PIN p_data[229]
    DIRECTION OUTPUT ;
    USE SIGNAL ;
    PORT
      LAYER M3 ;
        RECT  27.684 86.363 27.702 86.4 ;
    END
  END p_data[229]
  PIN p_data[22]
    DIRECTION OUTPUT ;
    USE SIGNAL ;
    PORT
      LAYER M3 ;
        RECT  26.604 86.363 26.622 86.4 ;
    END
  END p_data[22]
  PIN p_data[230]
    DIRECTION OUTPUT ;
    USE SIGNAL ;
    PORT
      LAYER M3 ;
        RECT  27.756 86.363 27.774 86.4 ;
    END
  END p_data[230]
  PIN p_data[231]
    DIRECTION OUTPUT ;
    USE SIGNAL ;
    PORT
      LAYER M3 ;
        RECT  27.828 86.363 27.846 86.4 ;
    END
  END p_data[231]
  PIN p_data[232]
    DIRECTION OUTPUT ;
    USE SIGNAL ;
    PORT
      LAYER M3 ;
        RECT  27.9 86.363 27.918 86.4 ;
    END
  END p_data[232]
  PIN p_data[233]
    DIRECTION OUTPUT ;
    USE SIGNAL ;
    PORT
      LAYER M3 ;
        RECT  27.972 86.363 27.99 86.4 ;
    END
  END p_data[233]
  PIN p_data[234]
    DIRECTION OUTPUT ;
    USE SIGNAL ;
    PORT
      LAYER M3 ;
        RECT  28.044 86.363 28.062 86.4 ;
    END
  END p_data[234]
  PIN p_data[235]
    DIRECTION OUTPUT ;
    USE SIGNAL ;
    PORT
      LAYER M3 ;
        RECT  28.116 86.363 28.134 86.4 ;
    END
  END p_data[235]
  PIN p_data[236]
    DIRECTION OUTPUT ;
    USE SIGNAL ;
    PORT
      LAYER M3 ;
        RECT  28.188 86.363 28.206 86.4 ;
    END
  END p_data[236]
  PIN p_data[237]
    DIRECTION OUTPUT ;
    USE SIGNAL ;
    PORT
      LAYER M3 ;
        RECT  28.26 86.363 28.278 86.4 ;
    END
  END p_data[237]
  PIN p_data[238]
    DIRECTION OUTPUT ;
    USE SIGNAL ;
    PORT
      LAYER M3 ;
        RECT  28.332 86.363 28.35 86.4 ;
    END
  END p_data[238]
  PIN p_data[239]
    DIRECTION OUTPUT ;
    USE SIGNAL ;
    PORT
      LAYER M3 ;
        RECT  28.404 86.363 28.422 86.4 ;
    END
  END p_data[239]
  PIN p_data[23]
    DIRECTION OUTPUT ;
    USE SIGNAL ;
    PORT
      LAYER M3 ;
        RECT  26.676 86.363 26.694 86.4 ;
    END
  END p_data[23]
  PIN p_data[240]
    DIRECTION OUTPUT ;
    USE SIGNAL ;
    PORT
      LAYER M3 ;
        RECT  28.476 86.363 28.494 86.4 ;
    END
  END p_data[240]
  PIN p_data[241]
    DIRECTION OUTPUT ;
    USE SIGNAL ;
    PORT
      LAYER M3 ;
        RECT  28.548 86.363 28.566 86.4 ;
    END
  END p_data[241]
  PIN p_data[242]
    DIRECTION OUTPUT ;
    USE SIGNAL ;
    PORT
      LAYER M3 ;
        RECT  28.62 86.363 28.638 86.4 ;
    END
  END p_data[242]
  PIN p_data[243]
    DIRECTION OUTPUT ;
    USE SIGNAL ;
    PORT
      LAYER M3 ;
        RECT  28.692 86.363 28.71 86.4 ;
    END
  END p_data[243]
  PIN p_data[244]
    DIRECTION OUTPUT ;
    USE SIGNAL ;
    PORT
      LAYER M3 ;
        RECT  28.764 86.363 28.782 86.4 ;
    END
  END p_data[244]
  PIN p_data[245]
    DIRECTION OUTPUT ;
    USE SIGNAL ;
    PORT
      LAYER M3 ;
        RECT  28.836 86.363 28.854 86.4 ;
    END
  END p_data[245]
  PIN p_data[246]
    DIRECTION OUTPUT ;
    USE SIGNAL ;
    PORT
      LAYER M3 ;
        RECT  28.908 86.363 28.926 86.4 ;
    END
  END p_data[246]
  PIN p_data[247]
    DIRECTION OUTPUT ;
    USE SIGNAL ;
    PORT
      LAYER M3 ;
        RECT  28.98 86.363 28.998 86.4 ;
    END
  END p_data[247]
  PIN p_data[248]
    DIRECTION OUTPUT ;
    USE SIGNAL ;
    PORT
      LAYER M3 ;
        RECT  29.052 86.363 29.07 86.4 ;
    END
  END p_data[248]
  PIN p_data[249]
    DIRECTION OUTPUT ;
    USE SIGNAL ;
    PORT
      LAYER M3 ;
        RECT  29.124 86.363 29.142 86.4 ;
    END
  END p_data[249]
  PIN p_data[24]
    DIRECTION OUTPUT ;
    USE SIGNAL ;
    PORT
      LAYER M3 ;
        RECT  26.748 86.363 26.766 86.4 ;
    END
  END p_data[24]
  PIN p_data[250]
    DIRECTION OUTPUT ;
    USE SIGNAL ;
    PORT
      LAYER M3 ;
        RECT  29.196 86.363 29.214 86.4 ;
    END
  END p_data[250]
  PIN p_data[251]
    DIRECTION OUTPUT ;
    USE SIGNAL ;
    PORT
      LAYER M3 ;
        RECT  29.268 86.363 29.286 86.4 ;
    END
  END p_data[251]
  PIN p_data[252]
    DIRECTION OUTPUT ;
    USE SIGNAL ;
    PORT
      LAYER M3 ;
        RECT  29.34 86.363 29.358 86.4 ;
    END
  END p_data[252]
  PIN p_data[253]
    DIRECTION OUTPUT ;
    USE SIGNAL ;
    PORT
      LAYER M3 ;
        RECT  29.412 86.363 29.43 86.4 ;
    END
  END p_data[253]
  PIN p_data[254]
    DIRECTION OUTPUT ;
    USE SIGNAL ;
    PORT
      LAYER M3 ;
        RECT  29.484 86.363 29.502 86.4 ;
    END
  END p_data[254]
  PIN p_data[255]
    DIRECTION OUTPUT ;
    USE SIGNAL ;
    PORT
      LAYER M3 ;
        RECT  29.556 86.363 29.574 86.4 ;
    END
  END p_data[255]
  PIN p_data[256]
    DIRECTION OUTPUT ;
    USE SIGNAL ;
    PORT
      LAYER M3 ;
        RECT  29.628 86.363 29.646 86.4 ;
    END
  END p_data[256]
  PIN p_data[257]
    DIRECTION OUTPUT ;
    USE SIGNAL ;
    PORT
      LAYER M3 ;
        RECT  29.7 86.363 29.718 86.4 ;
    END
  END p_data[257]
  PIN p_data[258]
    DIRECTION OUTPUT ;
    USE SIGNAL ;
    PORT
      LAYER M3 ;
        RECT  29.772 86.363 29.79 86.4 ;
    END
  END p_data[258]
  PIN p_data[259]
    DIRECTION OUTPUT ;
    USE SIGNAL ;
    PORT
      LAYER M3 ;
        RECT  32.148 86.363 32.166 86.4 ;
    END
  END p_data[259]
  PIN p_data[25]
    DIRECTION OUTPUT ;
    USE SIGNAL ;
    PORT
      LAYER M3 ;
        RECT  26.82 86.363 26.838 86.4 ;
    END
  END p_data[25]
  PIN p_data[260]
    DIRECTION OUTPUT ;
    USE SIGNAL ;
    PORT
      LAYER M3 ;
        RECT  32.22 86.363 32.238 86.4 ;
    END
  END p_data[260]
  PIN p_data[261]
    DIRECTION OUTPUT ;
    USE SIGNAL ;
    PORT
      LAYER M3 ;
        RECT  32.292 86.363 32.31 86.4 ;
    END
  END p_data[261]
  PIN p_data[262]
    DIRECTION OUTPUT ;
    USE SIGNAL ;
    PORT
      LAYER M3 ;
        RECT  32.364 86.363 32.382 86.4 ;
    END
  END p_data[262]
  PIN p_data[263]
    DIRECTION OUTPUT ;
    USE SIGNAL ;
    PORT
      LAYER M3 ;
        RECT  32.436 86.363 32.454 86.4 ;
    END
  END p_data[263]
  PIN p_data[264]
    DIRECTION OUTPUT ;
    USE SIGNAL ;
    PORT
      LAYER M3 ;
        RECT  32.508 86.363 32.526 86.4 ;
    END
  END p_data[264]
  PIN p_data[265]
    DIRECTION OUTPUT ;
    USE SIGNAL ;
    PORT
      LAYER M3 ;
        RECT  32.58 86.363 32.598 86.4 ;
    END
  END p_data[265]
  PIN p_data[266]
    DIRECTION OUTPUT ;
    USE SIGNAL ;
    PORT
      LAYER M3 ;
        RECT  32.652 86.363 32.67 86.4 ;
    END
  END p_data[266]
  PIN p_data[267]
    DIRECTION OUTPUT ;
    USE SIGNAL ;
    PORT
      LAYER M3 ;
        RECT  32.724 86.363 32.742 86.4 ;
    END
  END p_data[267]
  PIN p_data[268]
    DIRECTION OUTPUT ;
    USE SIGNAL ;
    PORT
      LAYER M3 ;
        RECT  32.796 86.363 32.814 86.4 ;
    END
  END p_data[268]
  PIN p_data[269]
    DIRECTION OUTPUT ;
    USE SIGNAL ;
    PORT
      LAYER M3 ;
        RECT  32.868 86.363 32.886 86.4 ;
    END
  END p_data[269]
  PIN p_data[26]
    DIRECTION OUTPUT ;
    USE SIGNAL ;
    PORT
      LAYER M3 ;
        RECT  26.892 86.363 26.91 86.4 ;
    END
  END p_data[26]
  PIN p_data[270]
    DIRECTION OUTPUT ;
    USE SIGNAL ;
    PORT
      LAYER M3 ;
        RECT  32.94 86.363 32.958 86.4 ;
    END
  END p_data[270]
  PIN p_data[271]
    DIRECTION OUTPUT ;
    USE SIGNAL ;
    PORT
      LAYER M3 ;
        RECT  33.012 86.363 33.03 86.4 ;
    END
  END p_data[271]
  PIN p_data[272]
    DIRECTION OUTPUT ;
    USE SIGNAL ;
    PORT
      LAYER M3 ;
        RECT  33.084 86.363 33.102 86.4 ;
    END
  END p_data[272]
  PIN p_data[273]
    DIRECTION OUTPUT ;
    USE SIGNAL ;
    PORT
      LAYER M3 ;
        RECT  33.156 86.363 33.174 86.4 ;
    END
  END p_data[273]
  PIN p_data[274]
    DIRECTION OUTPUT ;
    USE SIGNAL ;
    PORT
      LAYER M3 ;
        RECT  33.228 86.363 33.246 86.4 ;
    END
  END p_data[274]
  PIN p_data[275]
    DIRECTION OUTPUT ;
    USE SIGNAL ;
    PORT
      LAYER M3 ;
        RECT  33.3 86.363 33.318 86.4 ;
    END
  END p_data[275]
  PIN p_data[276]
    DIRECTION OUTPUT ;
    USE SIGNAL ;
    PORT
      LAYER M3 ;
        RECT  33.372 86.363 33.39 86.4 ;
    END
  END p_data[276]
  PIN p_data[277]
    DIRECTION OUTPUT ;
    USE SIGNAL ;
    PORT
      LAYER M3 ;
        RECT  33.444 86.363 33.462 86.4 ;
    END
  END p_data[277]
  PIN p_data[278]
    DIRECTION OUTPUT ;
    USE SIGNAL ;
    PORT
      LAYER M3 ;
        RECT  33.516 86.363 33.534 86.4 ;
    END
  END p_data[278]
  PIN p_data[279]
    DIRECTION OUTPUT ;
    USE SIGNAL ;
    PORT
      LAYER M3 ;
        RECT  33.588 86.363 33.606 86.4 ;
    END
  END p_data[279]
  PIN p_data[27]
    DIRECTION OUTPUT ;
    USE SIGNAL ;
    PORT
      LAYER M3 ;
        RECT  26.964 86.363 26.982 86.4 ;
    END
  END p_data[27]
  PIN p_data[280]
    DIRECTION OUTPUT ;
    USE SIGNAL ;
    PORT
      LAYER M3 ;
        RECT  33.66 86.363 33.678 86.4 ;
    END
  END p_data[280]
  PIN p_data[281]
    DIRECTION OUTPUT ;
    USE SIGNAL ;
    PORT
      LAYER M3 ;
        RECT  33.732 86.363 33.75 86.4 ;
    END
  END p_data[281]
  PIN p_data[282]
    DIRECTION OUTPUT ;
    USE SIGNAL ;
    PORT
      LAYER M3 ;
        RECT  33.804 86.363 33.822 86.4 ;
    END
  END p_data[282]
  PIN p_data[283]
    DIRECTION OUTPUT ;
    USE SIGNAL ;
    PORT
      LAYER M3 ;
        RECT  33.876 86.363 33.894 86.4 ;
    END
  END p_data[283]
  PIN p_data[284]
    DIRECTION OUTPUT ;
    USE SIGNAL ;
    PORT
      LAYER M3 ;
        RECT  33.948 86.363 33.966 86.4 ;
    END
  END p_data[284]
  PIN p_data[285]
    DIRECTION OUTPUT ;
    USE SIGNAL ;
    PORT
      LAYER M3 ;
        RECT  34.02 86.363 34.038 86.4 ;
    END
  END p_data[285]
  PIN p_data[286]
    DIRECTION OUTPUT ;
    USE SIGNAL ;
    PORT
      LAYER M3 ;
        RECT  34.092 86.363 34.11 86.4 ;
    END
  END p_data[286]
  PIN p_data[287]
    DIRECTION OUTPUT ;
    USE SIGNAL ;
    PORT
      LAYER M3 ;
        RECT  34.164 86.363 34.182 86.4 ;
    END
  END p_data[287]
  PIN p_data[288]
    DIRECTION OUTPUT ;
    USE SIGNAL ;
    PORT
      LAYER M3 ;
        RECT  34.236 86.363 34.254 86.4 ;
    END
  END p_data[288]
  PIN p_data[289]
    DIRECTION OUTPUT ;
    USE SIGNAL ;
    PORT
      LAYER M3 ;
        RECT  34.308 86.363 34.326 86.4 ;
    END
  END p_data[289]
  PIN p_data[28]
    DIRECTION OUTPUT ;
    USE SIGNAL ;
    PORT
      LAYER M3 ;
        RECT  27.036 86.363 27.054 86.4 ;
    END
  END p_data[28]
  PIN p_data[290]
    DIRECTION OUTPUT ;
    USE SIGNAL ;
    PORT
      LAYER M3 ;
        RECT  34.38 86.363 34.398 86.4 ;
    END
  END p_data[290]
  PIN p_data[291]
    DIRECTION OUTPUT ;
    USE SIGNAL ;
    PORT
      LAYER M3 ;
        RECT  29.844 86.363 29.862 86.4 ;
    END
  END p_data[291]
  PIN p_data[292]
    DIRECTION OUTPUT ;
    USE SIGNAL ;
    PORT
      LAYER M3 ;
        RECT  29.916 86.363 29.934 86.4 ;
    END
  END p_data[292]
  PIN p_data[293]
    DIRECTION OUTPUT ;
    USE SIGNAL ;
    PORT
      LAYER M3 ;
        RECT  29.988 86.363 30.006 86.4 ;
    END
  END p_data[293]
  PIN p_data[294]
    DIRECTION OUTPUT ;
    USE SIGNAL ;
    PORT
      LAYER M3 ;
        RECT  30.06 86.363 30.078 86.4 ;
    END
  END p_data[294]
  PIN p_data[295]
    DIRECTION OUTPUT ;
    USE SIGNAL ;
    PORT
      LAYER M3 ;
        RECT  30.132 86.363 30.15 86.4 ;
    END
  END p_data[295]
  PIN p_data[296]
    DIRECTION OUTPUT ;
    USE SIGNAL ;
    PORT
      LAYER M3 ;
        RECT  30.204 86.363 30.222 86.4 ;
    END
  END p_data[296]
  PIN p_data[297]
    DIRECTION OUTPUT ;
    USE SIGNAL ;
    PORT
      LAYER M3 ;
        RECT  30.276 86.363 30.294 86.4 ;
    END
  END p_data[297]
  PIN p_data[298]
    DIRECTION OUTPUT ;
    USE SIGNAL ;
    PORT
      LAYER M3 ;
        RECT  30.348 86.363 30.366 86.4 ;
    END
  END p_data[298]
  PIN p_data[299]
    DIRECTION OUTPUT ;
    USE SIGNAL ;
    PORT
      LAYER M3 ;
        RECT  30.42 86.363 30.438 86.4 ;
    END
  END p_data[299]
  PIN p_data[29]
    DIRECTION OUTPUT ;
    USE SIGNAL ;
    PORT
      LAYER M3 ;
        RECT  27.108 86.363 27.126 86.4 ;
    END
  END p_data[29]
  PIN p_data[2]
    DIRECTION OUTPUT ;
    USE SIGNAL ;
    PORT
      LAYER M3 ;
        RECT  19.98 86.363 19.998 86.4 ;
    END
  END p_data[2]
  PIN p_data[300]
    DIRECTION OUTPUT ;
    USE SIGNAL ;
    PORT
      LAYER M3 ;
        RECT  30.492 86.363 30.51 86.4 ;
    END
  END p_data[300]
  PIN p_data[301]
    DIRECTION OUTPUT ;
    USE SIGNAL ;
    PORT
      LAYER M3 ;
        RECT  30.564 86.363 30.582 86.4 ;
    END
  END p_data[301]
  PIN p_data[302]
    DIRECTION OUTPUT ;
    USE SIGNAL ;
    PORT
      LAYER M3 ;
        RECT  30.636 86.363 30.654 86.4 ;
    END
  END p_data[302]
  PIN p_data[303]
    DIRECTION OUTPUT ;
    USE SIGNAL ;
    PORT
      LAYER M3 ;
        RECT  30.708 86.363 30.726 86.4 ;
    END
  END p_data[303]
  PIN p_data[304]
    DIRECTION OUTPUT ;
    USE SIGNAL ;
    PORT
      LAYER M3 ;
        RECT  30.78 86.363 30.798 86.4 ;
    END
  END p_data[304]
  PIN p_data[305]
    DIRECTION OUTPUT ;
    USE SIGNAL ;
    PORT
      LAYER M3 ;
        RECT  30.852 86.363 30.87 86.4 ;
    END
  END p_data[305]
  PIN p_data[306]
    DIRECTION OUTPUT ;
    USE SIGNAL ;
    PORT
      LAYER M3 ;
        RECT  30.924 86.363 30.942 86.4 ;
    END
  END p_data[306]
  PIN p_data[307]
    DIRECTION OUTPUT ;
    USE SIGNAL ;
    PORT
      LAYER M3 ;
        RECT  30.996 86.363 31.014 86.4 ;
    END
  END p_data[307]
  PIN p_data[308]
    DIRECTION OUTPUT ;
    USE SIGNAL ;
    PORT
      LAYER M3 ;
        RECT  31.068 86.363 31.086 86.4 ;
    END
  END p_data[308]
  PIN p_data[309]
    DIRECTION OUTPUT ;
    USE SIGNAL ;
    PORT
      LAYER M3 ;
        RECT  31.14 86.363 31.158 86.4 ;
    END
  END p_data[309]
  PIN p_data[30]
    DIRECTION OUTPUT ;
    USE SIGNAL ;
    PORT
      LAYER M3 ;
        RECT  27.18 86.363 27.198 86.4 ;
    END
  END p_data[30]
  PIN p_data[310]
    DIRECTION OUTPUT ;
    USE SIGNAL ;
    PORT
      LAYER M3 ;
        RECT  31.212 86.363 31.23 86.4 ;
    END
  END p_data[310]
  PIN p_data[311]
    DIRECTION OUTPUT ;
    USE SIGNAL ;
    PORT
      LAYER M3 ;
        RECT  31.284 86.363 31.302 86.4 ;
    END
  END p_data[311]
  PIN p_data[312]
    DIRECTION OUTPUT ;
    USE SIGNAL ;
    PORT
      LAYER M3 ;
        RECT  31.356 86.363 31.374 86.4 ;
    END
  END p_data[312]
  PIN p_data[313]
    DIRECTION OUTPUT ;
    USE SIGNAL ;
    PORT
      LAYER M3 ;
        RECT  31.428 86.363 31.446 86.4 ;
    END
  END p_data[313]
  PIN p_data[314]
    DIRECTION OUTPUT ;
    USE SIGNAL ;
    PORT
      LAYER M3 ;
        RECT  31.5 86.363 31.518 86.4 ;
    END
  END p_data[314]
  PIN p_data[315]
    DIRECTION OUTPUT ;
    USE SIGNAL ;
    PORT
      LAYER M3 ;
        RECT  31.572 86.363 31.59 86.4 ;
    END
  END p_data[315]
  PIN p_data[316]
    DIRECTION OUTPUT ;
    USE SIGNAL ;
    PORT
      LAYER M3 ;
        RECT  31.644 86.363 31.662 86.4 ;
    END
  END p_data[316]
  PIN p_data[317]
    DIRECTION OUTPUT ;
    USE SIGNAL ;
    PORT
      LAYER M3 ;
        RECT  31.716 86.363 31.734 86.4 ;
    END
  END p_data[317]
  PIN p_data[318]
    DIRECTION OUTPUT ;
    USE SIGNAL ;
    PORT
      LAYER M3 ;
        RECT  31.788 86.363 31.806 86.4 ;
    END
  END p_data[318]
  PIN p_data[319]
    DIRECTION OUTPUT ;
    USE SIGNAL ;
    PORT
      LAYER M3 ;
        RECT  31.86 86.363 31.878 86.4 ;
    END
  END p_data[319]
  PIN p_data[31]
    DIRECTION OUTPUT ;
    USE SIGNAL ;
    PORT
      LAYER M3 ;
        RECT  27.252 86.363 27.27 86.4 ;
    END
  END p_data[31]
  PIN p_data[320]
    DIRECTION OUTPUT ;
    USE SIGNAL ;
    PORT
      LAYER M3 ;
        RECT  31.932 86.363 31.95 86.4 ;
    END
  END p_data[320]
  PIN p_data[321]
    DIRECTION OUTPUT ;
    USE SIGNAL ;
    PORT
      LAYER M3 ;
        RECT  32.004 86.363 32.022 86.4 ;
    END
  END p_data[321]
  PIN p_data[322]
    DIRECTION OUTPUT ;
    USE SIGNAL ;
    PORT
      LAYER M3 ;
        RECT  32.076 86.363 32.094 86.4 ;
    END
  END p_data[322]
  PIN p_data[323]
    DIRECTION OUTPUT ;
    USE SIGNAL ;
    PORT
      LAYER M3 ;
        RECT  34.452 86.363 34.47 86.4 ;
    END
  END p_data[323]
  PIN p_data[324]
    DIRECTION OUTPUT ;
    USE SIGNAL ;
    PORT
      LAYER M3 ;
        RECT  34.524 86.363 34.542 86.4 ;
    END
  END p_data[324]
  PIN p_data[325]
    DIRECTION OUTPUT ;
    USE SIGNAL ;
    PORT
      LAYER M3 ;
        RECT  34.596 86.363 34.614 86.4 ;
    END
  END p_data[325]
  PIN p_data[326]
    DIRECTION OUTPUT ;
    USE SIGNAL ;
    PORT
      LAYER M3 ;
        RECT  34.668 86.363 34.686 86.4 ;
    END
  END p_data[326]
  PIN p_data[327]
    DIRECTION OUTPUT ;
    USE SIGNAL ;
    PORT
      LAYER M3 ;
        RECT  34.74 86.363 34.758 86.4 ;
    END
  END p_data[327]
  PIN p_data[328]
    DIRECTION OUTPUT ;
    USE SIGNAL ;
    PORT
      LAYER M3 ;
        RECT  34.812 86.363 34.83 86.4 ;
    END
  END p_data[328]
  PIN p_data[329]
    DIRECTION OUTPUT ;
    USE SIGNAL ;
    PORT
      LAYER M3 ;
        RECT  34.884 86.363 34.902 86.4 ;
    END
  END p_data[329]
  PIN p_data[32]
    DIRECTION OUTPUT ;
    USE SIGNAL ;
    PORT
      LAYER M3 ;
        RECT  27.324 86.363 27.342 86.4 ;
    END
  END p_data[32]
  PIN p_data[330]
    DIRECTION OUTPUT ;
    USE SIGNAL ;
    PORT
      LAYER M3 ;
        RECT  34.956 86.363 34.974 86.4 ;
    END
  END p_data[330]
  PIN p_data[331]
    DIRECTION OUTPUT ;
    USE SIGNAL ;
    PORT
      LAYER M3 ;
        RECT  35.028 86.363 35.046 86.4 ;
    END
  END p_data[331]
  PIN p_data[332]
    DIRECTION OUTPUT ;
    USE SIGNAL ;
    PORT
      LAYER M3 ;
        RECT  35.1 86.363 35.118 86.4 ;
    END
  END p_data[332]
  PIN p_data[333]
    DIRECTION OUTPUT ;
    USE SIGNAL ;
    PORT
      LAYER M3 ;
        RECT  35.172 86.363 35.19 86.4 ;
    END
  END p_data[333]
  PIN p_data[334]
    DIRECTION OUTPUT ;
    USE SIGNAL ;
    PORT
      LAYER M3 ;
        RECT  35.244 86.363 35.262 86.4 ;
    END
  END p_data[334]
  PIN p_data[335]
    DIRECTION OUTPUT ;
    USE SIGNAL ;
    PORT
      LAYER M3 ;
        RECT  35.316 86.363 35.334 86.4 ;
    END
  END p_data[335]
  PIN p_data[336]
    DIRECTION OUTPUT ;
    USE SIGNAL ;
    PORT
      LAYER M3 ;
        RECT  35.388 86.363 35.406 86.4 ;
    END
  END p_data[336]
  PIN p_data[337]
    DIRECTION OUTPUT ;
    USE SIGNAL ;
    PORT
      LAYER M3 ;
        RECT  35.46 86.363 35.478 86.4 ;
    END
  END p_data[337]
  PIN p_data[338]
    DIRECTION OUTPUT ;
    USE SIGNAL ;
    PORT
      LAYER M3 ;
        RECT  35.532 86.363 35.55 86.4 ;
    END
  END p_data[338]
  PIN p_data[339]
    DIRECTION OUTPUT ;
    USE SIGNAL ;
    PORT
      LAYER M3 ;
        RECT  35.604 86.363 35.622 86.4 ;
    END
  END p_data[339]
  PIN p_data[33]
    DIRECTION OUTPUT ;
    USE SIGNAL ;
    PORT
      LAYER M3 ;
        RECT  27.396 86.363 27.414 86.4 ;
    END
  END p_data[33]
  PIN p_data[340]
    DIRECTION OUTPUT ;
    USE SIGNAL ;
    PORT
      LAYER M3 ;
        RECT  35.676 86.363 35.694 86.4 ;
    END
  END p_data[340]
  PIN p_data[341]
    DIRECTION OUTPUT ;
    USE SIGNAL ;
    PORT
      LAYER M3 ;
        RECT  35.748 86.363 35.766 86.4 ;
    END
  END p_data[341]
  PIN p_data[342]
    DIRECTION OUTPUT ;
    USE SIGNAL ;
    PORT
      LAYER M3 ;
        RECT  35.82 86.363 35.838 86.4 ;
    END
  END p_data[342]
  PIN p_data[343]
    DIRECTION OUTPUT ;
    USE SIGNAL ;
    PORT
      LAYER M3 ;
        RECT  35.892 86.363 35.91 86.4 ;
    END
  END p_data[343]
  PIN p_data[344]
    DIRECTION OUTPUT ;
    USE SIGNAL ;
    PORT
      LAYER M3 ;
        RECT  35.964 86.363 35.982 86.4 ;
    END
  END p_data[344]
  PIN p_data[345]
    DIRECTION OUTPUT ;
    USE SIGNAL ;
    PORT
      LAYER M3 ;
        RECT  36.036 86.363 36.054 86.4 ;
    END
  END p_data[345]
  PIN p_data[346]
    DIRECTION OUTPUT ;
    USE SIGNAL ;
    PORT
      LAYER M3 ;
        RECT  36.108 86.363 36.126 86.4 ;
    END
  END p_data[346]
  PIN p_data[347]
    DIRECTION OUTPUT ;
    USE SIGNAL ;
    PORT
      LAYER M3 ;
        RECT  36.18 86.363 36.198 86.4 ;
    END
  END p_data[347]
  PIN p_data[348]
    DIRECTION OUTPUT ;
    USE SIGNAL ;
    PORT
      LAYER M3 ;
        RECT  36.252 86.363 36.27 86.4 ;
    END
  END p_data[348]
  PIN p_data[349]
    DIRECTION OUTPUT ;
    USE SIGNAL ;
    PORT
      LAYER M3 ;
        RECT  36.324 86.363 36.342 86.4 ;
    END
  END p_data[349]
  PIN p_data[34]
    DIRECTION OUTPUT ;
    USE SIGNAL ;
    PORT
      LAYER M3 ;
        RECT  27.468 86.363 27.486 86.4 ;
    END
  END p_data[34]
  PIN p_data[350]
    DIRECTION OUTPUT ;
    USE SIGNAL ;
    PORT
      LAYER M3 ;
        RECT  36.396 86.363 36.414 86.4 ;
    END
  END p_data[350]
  PIN p_data[351]
    DIRECTION OUTPUT ;
    USE SIGNAL ;
    PORT
      LAYER M3 ;
        RECT  36.468 86.363 36.486 86.4 ;
    END
  END p_data[351]
  PIN p_data[352]
    DIRECTION OUTPUT ;
    USE SIGNAL ;
    PORT
      LAYER M3 ;
        RECT  36.54 86.363 36.558 86.4 ;
    END
  END p_data[352]
  PIN p_data[353]
    DIRECTION OUTPUT ;
    USE SIGNAL ;
    PORT
      LAYER M3 ;
        RECT  36.612 86.363 36.63 86.4 ;
    END
  END p_data[353]
  PIN p_data[354]
    DIRECTION OUTPUT ;
    USE SIGNAL ;
    PORT
      LAYER M3 ;
        RECT  36.684 86.363 36.702 86.4 ;
    END
  END p_data[354]
  PIN p_data[355]
    DIRECTION OUTPUT ;
    USE SIGNAL ;
    PORT
      LAYER M3 ;
        RECT  36.756 86.363 36.774 86.4 ;
    END
  END p_data[355]
  PIN p_data[356]
    DIRECTION OUTPUT ;
    USE SIGNAL ;
    PORT
      LAYER M3 ;
        RECT  36.828 86.363 36.846 86.4 ;
    END
  END p_data[356]
  PIN p_data[357]
    DIRECTION OUTPUT ;
    USE SIGNAL ;
    PORT
      LAYER M3 ;
        RECT  36.9 86.363 36.918 86.4 ;
    END
  END p_data[357]
  PIN p_data[358]
    DIRECTION OUTPUT ;
    USE SIGNAL ;
    PORT
      LAYER M3 ;
        RECT  36.972 86.363 36.99 86.4 ;
    END
  END p_data[358]
  PIN p_data[359]
    DIRECTION OUTPUT ;
    USE SIGNAL ;
    PORT
      LAYER M3 ;
        RECT  37.044 86.363 37.062 86.4 ;
    END
  END p_data[359]
  PIN p_data[35]
    DIRECTION OUTPUT ;
    USE SIGNAL ;
    PORT
      LAYER M5 ;
        RECT  24.912 86.316 24.936 86.4 ;
    END
  END p_data[35]
  PIN p_data[360]
    DIRECTION OUTPUT ;
    USE SIGNAL ;
    PORT
      LAYER M3 ;
        RECT  37.116 86.363 37.134 86.4 ;
    END
  END p_data[360]
  PIN p_data[361]
    DIRECTION OUTPUT ;
    USE SIGNAL ;
    PORT
      LAYER M3 ;
        RECT  37.188 86.363 37.206 86.4 ;
    END
  END p_data[361]
  PIN p_data[362]
    DIRECTION OUTPUT ;
    USE SIGNAL ;
    PORT
      LAYER M3 ;
        RECT  37.26 86.363 37.278 86.4 ;
    END
  END p_data[362]
  PIN p_data[363]
    DIRECTION OUTPUT ;
    USE SIGNAL ;
    PORT
      LAYER M3 ;
        RECT  37.332 86.363 37.35 86.4 ;
    END
  END p_data[363]
  PIN p_data[364]
    DIRECTION OUTPUT ;
    USE SIGNAL ;
    PORT
      LAYER M3 ;
        RECT  37.404 86.363 37.422 86.4 ;
    END
  END p_data[364]
  PIN p_data[365]
    DIRECTION OUTPUT ;
    USE SIGNAL ;
    PORT
      LAYER M3 ;
        RECT  37.476 86.363 37.494 86.4 ;
    END
  END p_data[365]
  PIN p_data[366]
    DIRECTION OUTPUT ;
    USE SIGNAL ;
    PORT
      LAYER M3 ;
        RECT  37.548 86.363 37.566 86.4 ;
    END
  END p_data[366]
  PIN p_data[367]
    DIRECTION OUTPUT ;
    USE SIGNAL ;
    PORT
      LAYER M3 ;
        RECT  37.62 86.363 37.638 86.4 ;
    END
  END p_data[367]
  PIN p_data[368]
    DIRECTION OUTPUT ;
    USE SIGNAL ;
    PORT
      LAYER M3 ;
        RECT  37.692 86.363 37.71 86.4 ;
    END
  END p_data[368]
  PIN p_data[369]
    DIRECTION OUTPUT ;
    USE SIGNAL ;
    PORT
      LAYER M3 ;
        RECT  37.764 86.363 37.782 86.4 ;
    END
  END p_data[369]
  PIN p_data[36]
    DIRECTION OUTPUT ;
    USE SIGNAL ;
    PORT
      LAYER M5 ;
        RECT  25.008 86.316 25.032 86.4 ;
    END
  END p_data[36]
  PIN p_data[370]
    DIRECTION OUTPUT ;
    USE SIGNAL ;
    PORT
      LAYER M3 ;
        RECT  37.836 86.363 37.854 86.4 ;
    END
  END p_data[370]
  PIN p_data[371]
    DIRECTION OUTPUT ;
    USE SIGNAL ;
    PORT
      LAYER M3 ;
        RECT  37.908 86.363 37.926 86.4 ;
    END
  END p_data[371]
  PIN p_data[372]
    DIRECTION OUTPUT ;
    USE SIGNAL ;
    PORT
      LAYER M3 ;
        RECT  37.98 86.363 37.998 86.4 ;
    END
  END p_data[372]
  PIN p_data[373]
    DIRECTION OUTPUT ;
    USE SIGNAL ;
    PORT
      LAYER M3 ;
        RECT  38.052 86.363 38.07 86.4 ;
    END
  END p_data[373]
  PIN p_data[374]
    DIRECTION OUTPUT ;
    USE SIGNAL ;
    PORT
      LAYER M3 ;
        RECT  38.124 86.363 38.142 86.4 ;
    END
  END p_data[374]
  PIN p_data[375]
    DIRECTION OUTPUT ;
    USE SIGNAL ;
    PORT
      LAYER M3 ;
        RECT  38.196 86.363 38.214 86.4 ;
    END
  END p_data[375]
  PIN p_data[376]
    DIRECTION OUTPUT ;
    USE SIGNAL ;
    PORT
      LAYER M3 ;
        RECT  38.268 86.363 38.286 86.4 ;
    END
  END p_data[376]
  PIN p_data[377]
    DIRECTION OUTPUT ;
    USE SIGNAL ;
    PORT
      LAYER M3 ;
        RECT  38.34 86.363 38.358 86.4 ;
    END
  END p_data[377]
  PIN p_data[378]
    DIRECTION OUTPUT ;
    USE SIGNAL ;
    PORT
      LAYER M3 ;
        RECT  38.412 86.363 38.43 86.4 ;
    END
  END p_data[378]
  PIN p_data[379]
    DIRECTION OUTPUT ;
    USE SIGNAL ;
    PORT
      LAYER M3 ;
        RECT  38.484 86.363 38.502 86.4 ;
    END
  END p_data[379]
  PIN p_data[37]
    DIRECTION OUTPUT ;
    USE SIGNAL ;
    PORT
      LAYER M5 ;
        RECT  25.104 86.316 25.128 86.4 ;
    END
  END p_data[37]
  PIN p_data[380]
    DIRECTION OUTPUT ;
    USE SIGNAL ;
    PORT
      LAYER M3 ;
        RECT  38.556 86.363 38.574 86.4 ;
    END
  END p_data[380]
  PIN p_data[381]
    DIRECTION OUTPUT ;
    USE SIGNAL ;
    PORT
      LAYER M3 ;
        RECT  38.628 86.363 38.646 86.4 ;
    END
  END p_data[381]
  PIN p_data[382]
    DIRECTION OUTPUT ;
    USE SIGNAL ;
    PORT
      LAYER M3 ;
        RECT  38.7 86.363 38.718 86.4 ;
    END
  END p_data[382]
  PIN p_data[383]
    DIRECTION OUTPUT ;
    USE SIGNAL ;
    PORT
      LAYER M3 ;
        RECT  38.772 86.363 38.79 86.4 ;
    END
  END p_data[383]
  PIN p_data[384]
    DIRECTION OUTPUT ;
    USE SIGNAL ;
    PORT
      LAYER M3 ;
        RECT  38.844 86.363 38.862 86.4 ;
    END
  END p_data[384]
  PIN p_data[385]
    DIRECTION OUTPUT ;
    USE SIGNAL ;
    PORT
      LAYER M3 ;
        RECT  38.916 86.363 38.934 86.4 ;
    END
  END p_data[385]
  PIN p_data[386]
    DIRECTION OUTPUT ;
    USE SIGNAL ;
    PORT
      LAYER M3 ;
        RECT  38.988 86.363 39.006 86.4 ;
    END
  END p_data[386]
  PIN p_data[387]
    DIRECTION OUTPUT ;
    USE SIGNAL ;
    PORT
      LAYER M5 ;
        RECT  41.04 86.316 41.064 86.4 ;
    END
  END p_data[387]
  PIN p_data[388]
    DIRECTION OUTPUT ;
    USE SIGNAL ;
    PORT
      LAYER M5 ;
        RECT  41.136 86.316 41.16 86.4 ;
    END
  END p_data[388]
  PIN p_data[389]
    DIRECTION OUTPUT ;
    USE SIGNAL ;
    PORT
      LAYER M5 ;
        RECT  41.232 86.316 41.256 86.4 ;
    END
  END p_data[389]
  PIN p_data[38]
    DIRECTION OUTPUT ;
    USE SIGNAL ;
    PORT
      LAYER M5 ;
        RECT  25.2 86.316 25.224 86.4 ;
    END
  END p_data[38]
  PIN p_data[390]
    DIRECTION OUTPUT ;
    USE SIGNAL ;
    PORT
      LAYER M5 ;
        RECT  41.328 86.316 41.352 86.4 ;
    END
  END p_data[390]
  PIN p_data[391]
    DIRECTION OUTPUT ;
    USE SIGNAL ;
    PORT
      LAYER M5 ;
        RECT  41.424 86.316 41.448 86.4 ;
    END
  END p_data[391]
  PIN p_data[392]
    DIRECTION OUTPUT ;
    USE SIGNAL ;
    PORT
      LAYER M5 ;
        RECT  41.52 86.316 41.544 86.4 ;
    END
  END p_data[392]
  PIN p_data[393]
    DIRECTION OUTPUT ;
    USE SIGNAL ;
    PORT
      LAYER M5 ;
        RECT  41.616 86.316 41.64 86.4 ;
    END
  END p_data[393]
  PIN p_data[394]
    DIRECTION OUTPUT ;
    USE SIGNAL ;
    PORT
      LAYER M5 ;
        RECT  41.712 86.316 41.736 86.4 ;
    END
  END p_data[394]
  PIN p_data[395]
    DIRECTION OUTPUT ;
    USE SIGNAL ;
    PORT
      LAYER M5 ;
        RECT  41.808 86.316 41.832 86.4 ;
    END
  END p_data[395]
  PIN p_data[396]
    DIRECTION OUTPUT ;
    USE SIGNAL ;
    PORT
      LAYER M5 ;
        RECT  41.904 86.316 41.928 86.4 ;
    END
  END p_data[396]
  PIN p_data[397]
    DIRECTION OUTPUT ;
    USE SIGNAL ;
    PORT
      LAYER M5 ;
        RECT  42 86.316 42.024 86.4 ;
    END
  END p_data[397]
  PIN p_data[398]
    DIRECTION OUTPUT ;
    USE SIGNAL ;
    PORT
      LAYER M5 ;
        RECT  42.096 86.316 42.12 86.4 ;
    END
  END p_data[398]
  PIN p_data[399]
    DIRECTION OUTPUT ;
    USE SIGNAL ;
    PORT
      LAYER M5 ;
        RECT  42.192 86.316 42.216 86.4 ;
    END
  END p_data[399]
  PIN p_data[39]
    DIRECTION OUTPUT ;
    USE SIGNAL ;
    PORT
      LAYER M5 ;
        RECT  25.296 86.316 25.32 86.4 ;
    END
  END p_data[39]
  PIN p_data[3]
    DIRECTION OUTPUT ;
    USE SIGNAL ;
    PORT
      LAYER M3 ;
        RECT  25.236 86.363 25.254 86.4 ;
    END
  END p_data[3]
  PIN p_data[400]
    DIRECTION OUTPUT ;
    USE SIGNAL ;
    PORT
      LAYER M5 ;
        RECT  42.288 86.316 42.312 86.4 ;
    END
  END p_data[400]
  PIN p_data[401]
    DIRECTION OUTPUT ;
    USE SIGNAL ;
    PORT
      LAYER M5 ;
        RECT  42.384 86.316 42.408 86.4 ;
    END
  END p_data[401]
  PIN p_data[402]
    DIRECTION OUTPUT ;
    USE SIGNAL ;
    PORT
      LAYER M5 ;
        RECT  42.48 86.316 42.504 86.4 ;
    END
  END p_data[402]
  PIN p_data[403]
    DIRECTION OUTPUT ;
    USE SIGNAL ;
    PORT
      LAYER M5 ;
        RECT  42.576 86.316 42.6 86.4 ;
    END
  END p_data[403]
  PIN p_data[404]
    DIRECTION OUTPUT ;
    USE SIGNAL ;
    PORT
      LAYER M5 ;
        RECT  42.672 86.316 42.696 86.4 ;
    END
  END p_data[404]
  PIN p_data[405]
    DIRECTION OUTPUT ;
    USE SIGNAL ;
    PORT
      LAYER M5 ;
        RECT  42.768 86.316 42.792 86.4 ;
    END
  END p_data[405]
  PIN p_data[406]
    DIRECTION OUTPUT ;
    USE SIGNAL ;
    PORT
      LAYER M5 ;
        RECT  42.864 86.316 42.888 86.4 ;
    END
  END p_data[406]
  PIN p_data[407]
    DIRECTION OUTPUT ;
    USE SIGNAL ;
    PORT
      LAYER M5 ;
        RECT  42.96 86.316 42.984 86.4 ;
    END
  END p_data[407]
  PIN p_data[408]
    DIRECTION OUTPUT ;
    USE SIGNAL ;
    PORT
      LAYER M5 ;
        RECT  43.056 86.316 43.08 86.4 ;
    END
  END p_data[408]
  PIN p_data[409]
    DIRECTION OUTPUT ;
    USE SIGNAL ;
    PORT
      LAYER M5 ;
        RECT  43.152 86.316 43.176 86.4 ;
    END
  END p_data[409]
  PIN p_data[40]
    DIRECTION OUTPUT ;
    USE SIGNAL ;
    PORT
      LAYER M5 ;
        RECT  25.392 86.316 25.416 86.4 ;
    END
  END p_data[40]
  PIN p_data[410]
    DIRECTION OUTPUT ;
    USE SIGNAL ;
    PORT
      LAYER M5 ;
        RECT  43.248 86.316 43.272 86.4 ;
    END
  END p_data[410]
  PIN p_data[411]
    DIRECTION OUTPUT ;
    USE SIGNAL ;
    PORT
      LAYER M5 ;
        RECT  43.344 86.316 43.368 86.4 ;
    END
  END p_data[411]
  PIN p_data[412]
    DIRECTION OUTPUT ;
    USE SIGNAL ;
    PORT
      LAYER M5 ;
        RECT  43.44 86.316 43.464 86.4 ;
    END
  END p_data[412]
  PIN p_data[413]
    DIRECTION OUTPUT ;
    USE SIGNAL ;
    PORT
      LAYER M5 ;
        RECT  43.536 86.316 43.56 86.4 ;
    END
  END p_data[413]
  PIN p_data[414]
    DIRECTION OUTPUT ;
    USE SIGNAL ;
    PORT
      LAYER M5 ;
        RECT  43.632 86.316 43.656 86.4 ;
    END
  END p_data[414]
  PIN p_data[415]
    DIRECTION OUTPUT ;
    USE SIGNAL ;
    PORT
      LAYER M5 ;
        RECT  43.728 86.316 43.752 86.4 ;
    END
  END p_data[415]
  PIN p_data[416]
    DIRECTION OUTPUT ;
    USE SIGNAL ;
    PORT
      LAYER M5 ;
        RECT  43.824 86.316 43.848 86.4 ;
    END
  END p_data[416]
  PIN p_data[417]
    DIRECTION OUTPUT ;
    USE SIGNAL ;
    PORT
      LAYER M5 ;
        RECT  43.92 86.316 43.944 86.4 ;
    END
  END p_data[417]
  PIN p_data[418]
    DIRECTION OUTPUT ;
    USE SIGNAL ;
    PORT
      LAYER M5 ;
        RECT  44.016 86.316 44.04 86.4 ;
    END
  END p_data[418]
  PIN p_data[419]
    DIRECTION OUTPUT ;
    USE SIGNAL ;
    PORT
      LAYER M5 ;
        RECT  34.896 86.316 34.92 86.4 ;
    END
  END p_data[419]
  PIN p_data[41]
    DIRECTION OUTPUT ;
    USE SIGNAL ;
    PORT
      LAYER M5 ;
        RECT  25.488 86.316 25.512 86.4 ;
    END
  END p_data[41]
  PIN p_data[420]
    DIRECTION OUTPUT ;
    USE SIGNAL ;
    PORT
      LAYER M5 ;
        RECT  34.992 86.316 35.016 86.4 ;
    END
  END p_data[420]
  PIN p_data[421]
    DIRECTION OUTPUT ;
    USE SIGNAL ;
    PORT
      LAYER M5 ;
        RECT  35.088 86.316 35.112 86.4 ;
    END
  END p_data[421]
  PIN p_data[422]
    DIRECTION OUTPUT ;
    USE SIGNAL ;
    PORT
      LAYER M5 ;
        RECT  35.184 86.316 35.208 86.4 ;
    END
  END p_data[422]
  PIN p_data[423]
    DIRECTION OUTPUT ;
    USE SIGNAL ;
    PORT
      LAYER M5 ;
        RECT  35.28 86.316 35.304 86.4 ;
    END
  END p_data[423]
  PIN p_data[424]
    DIRECTION OUTPUT ;
    USE SIGNAL ;
    PORT
      LAYER M5 ;
        RECT  35.376 86.316 35.4 86.4 ;
    END
  END p_data[424]
  PIN p_data[425]
    DIRECTION OUTPUT ;
    USE SIGNAL ;
    PORT
      LAYER M5 ;
        RECT  35.472 86.316 35.496 86.4 ;
    END
  END p_data[425]
  PIN p_data[426]
    DIRECTION OUTPUT ;
    USE SIGNAL ;
    PORT
      LAYER M5 ;
        RECT  35.568 86.316 35.592 86.4 ;
    END
  END p_data[426]
  PIN p_data[427]
    DIRECTION OUTPUT ;
    USE SIGNAL ;
    PORT
      LAYER M5 ;
        RECT  35.664 86.316 35.688 86.4 ;
    END
  END p_data[427]
  PIN p_data[428]
    DIRECTION OUTPUT ;
    USE SIGNAL ;
    PORT
      LAYER M5 ;
        RECT  35.76 86.316 35.784 86.4 ;
    END
  END p_data[428]
  PIN p_data[429]
    DIRECTION OUTPUT ;
    USE SIGNAL ;
    PORT
      LAYER M5 ;
        RECT  35.856 86.316 35.88 86.4 ;
    END
  END p_data[429]
  PIN p_data[42]
    DIRECTION OUTPUT ;
    USE SIGNAL ;
    PORT
      LAYER M5 ;
        RECT  25.584 86.316 25.608 86.4 ;
    END
  END p_data[42]
  PIN p_data[430]
    DIRECTION OUTPUT ;
    USE SIGNAL ;
    PORT
      LAYER M5 ;
        RECT  35.952 86.316 35.976 86.4 ;
    END
  END p_data[430]
  PIN p_data[431]
    DIRECTION OUTPUT ;
    USE SIGNAL ;
    PORT
      LAYER M5 ;
        RECT  36.048 86.316 36.072 86.4 ;
    END
  END p_data[431]
  PIN p_data[432]
    DIRECTION OUTPUT ;
    USE SIGNAL ;
    PORT
      LAYER M5 ;
        RECT  36.144 86.316 36.168 86.4 ;
    END
  END p_data[432]
  PIN p_data[433]
    DIRECTION OUTPUT ;
    USE SIGNAL ;
    PORT
      LAYER M5 ;
        RECT  36.24 86.316 36.264 86.4 ;
    END
  END p_data[433]
  PIN p_data[434]
    DIRECTION OUTPUT ;
    USE SIGNAL ;
    PORT
      LAYER M5 ;
        RECT  36.336 86.316 36.36 86.4 ;
    END
  END p_data[434]
  PIN p_data[435]
    DIRECTION OUTPUT ;
    USE SIGNAL ;
    PORT
      LAYER M5 ;
        RECT  36.432 86.316 36.456 86.4 ;
    END
  END p_data[435]
  PIN p_data[436]
    DIRECTION OUTPUT ;
    USE SIGNAL ;
    PORT
      LAYER M5 ;
        RECT  36.528 86.316 36.552 86.4 ;
    END
  END p_data[436]
  PIN p_data[437]
    DIRECTION OUTPUT ;
    USE SIGNAL ;
    PORT
      LAYER M5 ;
        RECT  36.624 86.316 36.648 86.4 ;
    END
  END p_data[437]
  PIN p_data[438]
    DIRECTION OUTPUT ;
    USE SIGNAL ;
    PORT
      LAYER M5 ;
        RECT  36.72 86.316 36.744 86.4 ;
    END
  END p_data[438]
  PIN p_data[439]
    DIRECTION OUTPUT ;
    USE SIGNAL ;
    PORT
      LAYER M5 ;
        RECT  36.816 86.316 36.84 86.4 ;
    END
  END p_data[439]
  PIN p_data[43]
    DIRECTION OUTPUT ;
    USE SIGNAL ;
    PORT
      LAYER M5 ;
        RECT  25.68 86.316 25.704 86.4 ;
    END
  END p_data[43]
  PIN p_data[440]
    DIRECTION OUTPUT ;
    USE SIGNAL ;
    PORT
      LAYER M5 ;
        RECT  36.912 86.316 36.936 86.4 ;
    END
  END p_data[440]
  PIN p_data[441]
    DIRECTION OUTPUT ;
    USE SIGNAL ;
    PORT
      LAYER M5 ;
        RECT  37.008 86.316 37.032 86.4 ;
    END
  END p_data[441]
  PIN p_data[442]
    DIRECTION OUTPUT ;
    USE SIGNAL ;
    PORT
      LAYER M5 ;
        RECT  37.104 86.316 37.128 86.4 ;
    END
  END p_data[442]
  PIN p_data[443]
    DIRECTION OUTPUT ;
    USE SIGNAL ;
    PORT
      LAYER M5 ;
        RECT  37.2 86.316 37.224 86.4 ;
    END
  END p_data[443]
  PIN p_data[444]
    DIRECTION OUTPUT ;
    USE SIGNAL ;
    PORT
      LAYER M5 ;
        RECT  37.296 86.316 37.32 86.4 ;
    END
  END p_data[444]
  PIN p_data[445]
    DIRECTION OUTPUT ;
    USE SIGNAL ;
    PORT
      LAYER M5 ;
        RECT  37.392 86.316 37.416 86.4 ;
    END
  END p_data[445]
  PIN p_data[446]
    DIRECTION OUTPUT ;
    USE SIGNAL ;
    PORT
      LAYER M5 ;
        RECT  37.488 86.316 37.512 86.4 ;
    END
  END p_data[446]
  PIN p_data[447]
    DIRECTION OUTPUT ;
    USE SIGNAL ;
    PORT
      LAYER M5 ;
        RECT  37.584 86.316 37.608 86.4 ;
    END
  END p_data[447]
  PIN p_data[448]
    DIRECTION OUTPUT ;
    USE SIGNAL ;
    PORT
      LAYER M5 ;
        RECT  37.68 86.316 37.704 86.4 ;
    END
  END p_data[448]
  PIN p_data[449]
    DIRECTION OUTPUT ;
    USE SIGNAL ;
    PORT
      LAYER M5 ;
        RECT  37.776 86.316 37.8 86.4 ;
    END
  END p_data[449]
  PIN p_data[44]
    DIRECTION OUTPUT ;
    USE SIGNAL ;
    PORT
      LAYER M5 ;
        RECT  25.776 86.316 25.8 86.4 ;
    END
  END p_data[44]
  PIN p_data[450]
    DIRECTION OUTPUT ;
    USE SIGNAL ;
    PORT
      LAYER M5 ;
        RECT  37.872 86.316 37.896 86.4 ;
    END
  END p_data[450]
  PIN p_data[451]
    DIRECTION OUTPUT ;
    USE SIGNAL ;
    PORT
      LAYER M5 ;
        RECT  37.968 86.316 37.992 86.4 ;
    END
  END p_data[451]
  PIN p_data[452]
    DIRECTION OUTPUT ;
    USE SIGNAL ;
    PORT
      LAYER M5 ;
        RECT  38.064 86.316 38.088 86.4 ;
    END
  END p_data[452]
  PIN p_data[453]
    DIRECTION OUTPUT ;
    USE SIGNAL ;
    PORT
      LAYER M5 ;
        RECT  38.16 86.316 38.184 86.4 ;
    END
  END p_data[453]
  PIN p_data[454]
    DIRECTION OUTPUT ;
    USE SIGNAL ;
    PORT
      LAYER M5 ;
        RECT  38.256 86.316 38.28 86.4 ;
    END
  END p_data[454]
  PIN p_data[455]
    DIRECTION OUTPUT ;
    USE SIGNAL ;
    PORT
      LAYER M5 ;
        RECT  38.352 86.316 38.376 86.4 ;
    END
  END p_data[455]
  PIN p_data[456]
    DIRECTION OUTPUT ;
    USE SIGNAL ;
    PORT
      LAYER M5 ;
        RECT  38.448 86.316 38.472 86.4 ;
    END
  END p_data[456]
  PIN p_data[457]
    DIRECTION OUTPUT ;
    USE SIGNAL ;
    PORT
      LAYER M5 ;
        RECT  38.544 86.316 38.568 86.4 ;
    END
  END p_data[457]
  PIN p_data[458]
    DIRECTION OUTPUT ;
    USE SIGNAL ;
    PORT
      LAYER M5 ;
        RECT  38.64 86.316 38.664 86.4 ;
    END
  END p_data[458]
  PIN p_data[459]
    DIRECTION OUTPUT ;
    USE SIGNAL ;
    PORT
      LAYER M5 ;
        RECT  38.736 86.316 38.76 86.4 ;
    END
  END p_data[459]
  PIN p_data[45]
    DIRECTION OUTPUT ;
    USE SIGNAL ;
    PORT
      LAYER M5 ;
        RECT  25.872 86.316 25.896 86.4 ;
    END
  END p_data[45]
  PIN p_data[460]
    DIRECTION OUTPUT ;
    USE SIGNAL ;
    PORT
      LAYER M5 ;
        RECT  38.832 86.316 38.856 86.4 ;
    END
  END p_data[460]
  PIN p_data[461]
    DIRECTION OUTPUT ;
    USE SIGNAL ;
    PORT
      LAYER M5 ;
        RECT  38.928 86.316 38.952 86.4 ;
    END
  END p_data[461]
  PIN p_data[462]
    DIRECTION OUTPUT ;
    USE SIGNAL ;
    PORT
      LAYER M5 ;
        RECT  39.024 86.316 39.048 86.4 ;
    END
  END p_data[462]
  PIN p_data[463]
    DIRECTION OUTPUT ;
    USE SIGNAL ;
    PORT
      LAYER M5 ;
        RECT  39.12 86.316 39.144 86.4 ;
    END
  END p_data[463]
  PIN p_data[464]
    DIRECTION OUTPUT ;
    USE SIGNAL ;
    PORT
      LAYER M5 ;
        RECT  39.216 86.316 39.24 86.4 ;
    END
  END p_data[464]
  PIN p_data[465]
    DIRECTION OUTPUT ;
    USE SIGNAL ;
    PORT
      LAYER M5 ;
        RECT  39.312 86.316 39.336 86.4 ;
    END
  END p_data[465]
  PIN p_data[466]
    DIRECTION OUTPUT ;
    USE SIGNAL ;
    PORT
      LAYER M5 ;
        RECT  39.408 86.316 39.432 86.4 ;
    END
  END p_data[466]
  PIN p_data[467]
    DIRECTION OUTPUT ;
    USE SIGNAL ;
    PORT
      LAYER M5 ;
        RECT  39.504 86.316 39.528 86.4 ;
    END
  END p_data[467]
  PIN p_data[468]
    DIRECTION OUTPUT ;
    USE SIGNAL ;
    PORT
      LAYER M5 ;
        RECT  39.6 86.316 39.624 86.4 ;
    END
  END p_data[468]
  PIN p_data[469]
    DIRECTION OUTPUT ;
    USE SIGNAL ;
    PORT
      LAYER M5 ;
        RECT  39.696 86.316 39.72 86.4 ;
    END
  END p_data[469]
  PIN p_data[46]
    DIRECTION OUTPUT ;
    USE SIGNAL ;
    PORT
      LAYER M5 ;
        RECT  25.968 86.316 25.992 86.4 ;
    END
  END p_data[46]
  PIN p_data[470]
    DIRECTION OUTPUT ;
    USE SIGNAL ;
    PORT
      LAYER M5 ;
        RECT  39.792 86.316 39.816 86.4 ;
    END
  END p_data[470]
  PIN p_data[471]
    DIRECTION OUTPUT ;
    USE SIGNAL ;
    PORT
      LAYER M5 ;
        RECT  39.888 86.316 39.912 86.4 ;
    END
  END p_data[471]
  PIN p_data[472]
    DIRECTION OUTPUT ;
    USE SIGNAL ;
    PORT
      LAYER M5 ;
        RECT  39.984 86.316 40.008 86.4 ;
    END
  END p_data[472]
  PIN p_data[473]
    DIRECTION OUTPUT ;
    USE SIGNAL ;
    PORT
      LAYER M5 ;
        RECT  40.08 86.316 40.104 86.4 ;
    END
  END p_data[473]
  PIN p_data[474]
    DIRECTION OUTPUT ;
    USE SIGNAL ;
    PORT
      LAYER M5 ;
        RECT  40.176 86.316 40.2 86.4 ;
    END
  END p_data[474]
  PIN p_data[475]
    DIRECTION OUTPUT ;
    USE SIGNAL ;
    PORT
      LAYER M5 ;
        RECT  40.272 86.316 40.296 86.4 ;
    END
  END p_data[475]
  PIN p_data[476]
    DIRECTION OUTPUT ;
    USE SIGNAL ;
    PORT
      LAYER M5 ;
        RECT  40.368 86.316 40.392 86.4 ;
    END
  END p_data[476]
  PIN p_data[477]
    DIRECTION OUTPUT ;
    USE SIGNAL ;
    PORT
      LAYER M5 ;
        RECT  40.464 86.316 40.488 86.4 ;
    END
  END p_data[477]
  PIN p_data[478]
    DIRECTION OUTPUT ;
    USE SIGNAL ;
    PORT
      LAYER M5 ;
        RECT  40.56 86.316 40.584 86.4 ;
    END
  END p_data[478]
  PIN p_data[479]
    DIRECTION OUTPUT ;
    USE SIGNAL ;
    PORT
      LAYER M5 ;
        RECT  40.656 86.316 40.68 86.4 ;
    END
  END p_data[479]
  PIN p_data[47]
    DIRECTION OUTPUT ;
    USE SIGNAL ;
    PORT
      LAYER M5 ;
        RECT  26.064 86.316 26.088 86.4 ;
    END
  END p_data[47]
  PIN p_data[480]
    DIRECTION OUTPUT ;
    USE SIGNAL ;
    PORT
      LAYER M5 ;
        RECT  40.752 86.316 40.776 86.4 ;
    END
  END p_data[480]
  PIN p_data[481]
    DIRECTION OUTPUT ;
    USE SIGNAL ;
    PORT
      LAYER M5 ;
        RECT  40.848 86.316 40.872 86.4 ;
    END
  END p_data[481]
  PIN p_data[482]
    DIRECTION OUTPUT ;
    USE SIGNAL ;
    PORT
      LAYER M5 ;
        RECT  40.944 86.316 40.968 86.4 ;
    END
  END p_data[482]
  PIN p_data[483]
    DIRECTION OUTPUT ;
    USE SIGNAL ;
    PORT
      LAYER M3 ;
        RECT  22.428 86.363 22.446 86.4 ;
    END
  END p_data[483]
  PIN p_data[484]
    DIRECTION OUTPUT ;
    USE SIGNAL ;
    PORT
      LAYER M3 ;
        RECT  22.5 86.363 22.518 86.4 ;
    END
  END p_data[484]
  PIN p_data[485]
    DIRECTION OUTPUT ;
    USE SIGNAL ;
    PORT
      LAYER M3 ;
        RECT  22.572 86.363 22.59 86.4 ;
    END
  END p_data[485]
  PIN p_data[486]
    DIRECTION OUTPUT ;
    USE SIGNAL ;
    PORT
      LAYER M3 ;
        RECT  22.644 86.363 22.662 86.4 ;
    END
  END p_data[486]
  PIN p_data[487]
    DIRECTION OUTPUT ;
    USE SIGNAL ;
    PORT
      LAYER M3 ;
        RECT  22.716 86.363 22.734 86.4 ;
    END
  END p_data[487]
  PIN p_data[488]
    DIRECTION OUTPUT ;
    USE SIGNAL ;
    PORT
      LAYER M3 ;
        RECT  22.788 86.363 22.806 86.4 ;
    END
  END p_data[488]
  PIN p_data[489]
    DIRECTION OUTPUT ;
    USE SIGNAL ;
    PORT
      LAYER M3 ;
        RECT  22.86 86.363 22.878 86.4 ;
    END
  END p_data[489]
  PIN p_data[48]
    DIRECTION OUTPUT ;
    USE SIGNAL ;
    PORT
      LAYER M5 ;
        RECT  26.16 86.316 26.184 86.4 ;
    END
  END p_data[48]
  PIN p_data[490]
    DIRECTION OUTPUT ;
    USE SIGNAL ;
    PORT
      LAYER M3 ;
        RECT  22.932 86.363 22.95 86.4 ;
    END
  END p_data[490]
  PIN p_data[491]
    DIRECTION OUTPUT ;
    USE SIGNAL ;
    PORT
      LAYER M3 ;
        RECT  23.004 86.363 23.022 86.4 ;
    END
  END p_data[491]
  PIN p_data[492]
    DIRECTION OUTPUT ;
    USE SIGNAL ;
    PORT
      LAYER M3 ;
        RECT  23.076 86.363 23.094 86.4 ;
    END
  END p_data[492]
  PIN p_data[493]
    DIRECTION OUTPUT ;
    USE SIGNAL ;
    PORT
      LAYER M3 ;
        RECT  23.148 86.363 23.166 86.4 ;
    END
  END p_data[493]
  PIN p_data[494]
    DIRECTION OUTPUT ;
    USE SIGNAL ;
    PORT
      LAYER M3 ;
        RECT  23.22 86.363 23.238 86.4 ;
    END
  END p_data[494]
  PIN p_data[495]
    DIRECTION OUTPUT ;
    USE SIGNAL ;
    PORT
      LAYER M3 ;
        RECT  23.292 86.363 23.31 86.4 ;
    END
  END p_data[495]
  PIN p_data[496]
    DIRECTION OUTPUT ;
    USE SIGNAL ;
    PORT
      LAYER M3 ;
        RECT  23.364 86.363 23.382 86.4 ;
    END
  END p_data[496]
  PIN p_data[497]
    DIRECTION OUTPUT ;
    USE SIGNAL ;
    PORT
      LAYER M3 ;
        RECT  23.436 86.363 23.454 86.4 ;
    END
  END p_data[497]
  PIN p_data[498]
    DIRECTION OUTPUT ;
    USE SIGNAL ;
    PORT
      LAYER M3 ;
        RECT  23.508 86.363 23.526 86.4 ;
    END
  END p_data[498]
  PIN p_data[499]
    DIRECTION OUTPUT ;
    USE SIGNAL ;
    PORT
      LAYER M3 ;
        RECT  23.58 86.363 23.598 86.4 ;
    END
  END p_data[499]
  PIN p_data[49]
    DIRECTION OUTPUT ;
    USE SIGNAL ;
    PORT
      LAYER M5 ;
        RECT  26.256 86.316 26.28 86.4 ;
    END
  END p_data[49]
  PIN p_data[4]
    DIRECTION OUTPUT ;
    USE SIGNAL ;
    PORT
      LAYER M3 ;
        RECT  25.308 86.363 25.326 86.4 ;
    END
  END p_data[4]
  PIN p_data[500]
    DIRECTION OUTPUT ;
    USE SIGNAL ;
    PORT
      LAYER M3 ;
        RECT  23.652 86.363 23.67 86.4 ;
    END
  END p_data[500]
  PIN p_data[501]
    DIRECTION OUTPUT ;
    USE SIGNAL ;
    PORT
      LAYER M3 ;
        RECT  23.724 86.363 23.742 86.4 ;
    END
  END p_data[501]
  PIN p_data[502]
    DIRECTION OUTPUT ;
    USE SIGNAL ;
    PORT
      LAYER M3 ;
        RECT  23.796 86.363 23.814 86.4 ;
    END
  END p_data[502]
  PIN p_data[503]
    DIRECTION OUTPUT ;
    USE SIGNAL ;
    PORT
      LAYER M3 ;
        RECT  23.868 86.363 23.886 86.4 ;
    END
  END p_data[503]
  PIN p_data[504]
    DIRECTION OUTPUT ;
    USE SIGNAL ;
    PORT
      LAYER M3 ;
        RECT  23.94 86.363 23.958 86.4 ;
    END
  END p_data[504]
  PIN p_data[505]
    DIRECTION OUTPUT ;
    USE SIGNAL ;
    PORT
      LAYER M3 ;
        RECT  24.012 86.363 24.03 86.4 ;
    END
  END p_data[505]
  PIN p_data[506]
    DIRECTION OUTPUT ;
    USE SIGNAL ;
    PORT
      LAYER M3 ;
        RECT  24.084 86.363 24.102 86.4 ;
    END
  END p_data[506]
  PIN p_data[507]
    DIRECTION OUTPUT ;
    USE SIGNAL ;
    PORT
      LAYER M3 ;
        RECT  24.156 86.363 24.174 86.4 ;
    END
  END p_data[507]
  PIN p_data[508]
    DIRECTION OUTPUT ;
    USE SIGNAL ;
    PORT
      LAYER M3 ;
        RECT  24.228 86.363 24.246 86.4 ;
    END
  END p_data[508]
  PIN p_data[509]
    DIRECTION OUTPUT ;
    USE SIGNAL ;
    PORT
      LAYER M3 ;
        RECT  24.3 86.363 24.318 86.4 ;
    END
  END p_data[509]
  PIN p_data[50]
    DIRECTION OUTPUT ;
    USE SIGNAL ;
    PORT
      LAYER M5 ;
        RECT  26.352 86.316 26.376 86.4 ;
    END
  END p_data[50]
  PIN p_data[510]
    DIRECTION OUTPUT ;
    USE SIGNAL ;
    PORT
      LAYER M3 ;
        RECT  24.372 86.363 24.39 86.4 ;
    END
  END p_data[510]
  PIN p_data[511]
    DIRECTION OUTPUT ;
    USE SIGNAL ;
    PORT
      LAYER M3 ;
        RECT  24.444 86.363 24.462 86.4 ;
    END
  END p_data[511]
  PIN p_data[51]
    DIRECTION OUTPUT ;
    USE SIGNAL ;
    PORT
      LAYER M5 ;
        RECT  26.448 86.316 26.472 86.4 ;
    END
  END p_data[51]
  PIN p_data[52]
    DIRECTION OUTPUT ;
    USE SIGNAL ;
    PORT
      LAYER M5 ;
        RECT  26.544 86.316 26.568 86.4 ;
    END
  END p_data[52]
  PIN p_data[53]
    DIRECTION OUTPUT ;
    USE SIGNAL ;
    PORT
      LAYER M5 ;
        RECT  26.64 86.316 26.664 86.4 ;
    END
  END p_data[53]
  PIN p_data[54]
    DIRECTION OUTPUT ;
    USE SIGNAL ;
    PORT
      LAYER M5 ;
        RECT  26.736 86.316 26.76 86.4 ;
    END
  END p_data[54]
  PIN p_data[55]
    DIRECTION OUTPUT ;
    USE SIGNAL ;
    PORT
      LAYER M5 ;
        RECT  26.832 86.316 26.856 86.4 ;
    END
  END p_data[55]
  PIN p_data[56]
    DIRECTION OUTPUT ;
    USE SIGNAL ;
    PORT
      LAYER M5 ;
        RECT  26.928 86.316 26.952 86.4 ;
    END
  END p_data[56]
  PIN p_data[57]
    DIRECTION OUTPUT ;
    USE SIGNAL ;
    PORT
      LAYER M5 ;
        RECT  27.024 86.316 27.048 86.4 ;
    END
  END p_data[57]
  PIN p_data[58]
    DIRECTION OUTPUT ;
    USE SIGNAL ;
    PORT
      LAYER M5 ;
        RECT  27.12 86.316 27.144 86.4 ;
    END
  END p_data[58]
  PIN p_data[59]
    DIRECTION OUTPUT ;
    USE SIGNAL ;
    PORT
      LAYER M5 ;
        RECT  27.216 86.316 27.24 86.4 ;
    END
  END p_data[59]
  PIN p_data[5]
    DIRECTION OUTPUT ;
    USE SIGNAL ;
    PORT
      LAYER M3 ;
        RECT  25.38 86.363 25.398 86.4 ;
    END
  END p_data[5]
  PIN p_data[60]
    DIRECTION OUTPUT ;
    USE SIGNAL ;
    PORT
      LAYER M5 ;
        RECT  27.312 86.316 27.336 86.4 ;
    END
  END p_data[60]
  PIN p_data[61]
    DIRECTION OUTPUT ;
    USE SIGNAL ;
    PORT
      LAYER M5 ;
        RECT  27.408 86.316 27.432 86.4 ;
    END
  END p_data[61]
  PIN p_data[62]
    DIRECTION OUTPUT ;
    USE SIGNAL ;
    PORT
      LAYER M5 ;
        RECT  27.504 86.316 27.528 86.4 ;
    END
  END p_data[62]
  PIN p_data[63]
    DIRECTION OUTPUT ;
    USE SIGNAL ;
    PORT
      LAYER M5 ;
        RECT  27.6 86.316 27.624 86.4 ;
    END
  END p_data[63]
  PIN p_data[64]
    DIRECTION OUTPUT ;
    USE SIGNAL ;
    PORT
      LAYER M5 ;
        RECT  27.696 86.316 27.72 86.4 ;
    END
  END p_data[64]
  PIN p_data[65]
    DIRECTION OUTPUT ;
    USE SIGNAL ;
    PORT
      LAYER M5 ;
        RECT  27.792 86.316 27.816 86.4 ;
    END
  END p_data[65]
  PIN p_data[66]
    DIRECTION OUTPUT ;
    USE SIGNAL ;
    PORT
      LAYER M5 ;
        RECT  27.888 86.316 27.912 86.4 ;
    END
  END p_data[66]
  PIN p_data[67]
    DIRECTION OUTPUT ;
    USE SIGNAL ;
    PORT
      LAYER M5 ;
        RECT  15.696 86.316 15.72 86.4 ;
    END
  END p_data[67]
  PIN p_data[68]
    DIRECTION OUTPUT ;
    USE SIGNAL ;
    PORT
      LAYER M5 ;
        RECT  15.792 86.316 15.816 86.4 ;
    END
  END p_data[68]
  PIN p_data[69]
    DIRECTION OUTPUT ;
    USE SIGNAL ;
    PORT
      LAYER M5 ;
        RECT  15.888 86.316 15.912 86.4 ;
    END
  END p_data[69]
  PIN p_data[6]
    DIRECTION OUTPUT ;
    USE SIGNAL ;
    PORT
      LAYER M3 ;
        RECT  25.452 86.363 25.47 86.4 ;
    END
  END p_data[6]
  PIN p_data[70]
    DIRECTION OUTPUT ;
    USE SIGNAL ;
    PORT
      LAYER M5 ;
        RECT  15.984 86.316 16.008 86.4 ;
    END
  END p_data[70]
  PIN p_data[71]
    DIRECTION OUTPUT ;
    USE SIGNAL ;
    PORT
      LAYER M5 ;
        RECT  16.08 86.316 16.104 86.4 ;
    END
  END p_data[71]
  PIN p_data[72]
    DIRECTION OUTPUT ;
    USE SIGNAL ;
    PORT
      LAYER M5 ;
        RECT  16.176 86.316 16.2 86.4 ;
    END
  END p_data[72]
  PIN p_data[73]
    DIRECTION OUTPUT ;
    USE SIGNAL ;
    PORT
      LAYER M5 ;
        RECT  16.272 86.316 16.296 86.4 ;
    END
  END p_data[73]
  PIN p_data[74]
    DIRECTION OUTPUT ;
    USE SIGNAL ;
    PORT
      LAYER M5 ;
        RECT  16.368 86.316 16.392 86.4 ;
    END
  END p_data[74]
  PIN p_data[75]
    DIRECTION OUTPUT ;
    USE SIGNAL ;
    PORT
      LAYER M5 ;
        RECT  16.464 86.316 16.488 86.4 ;
    END
  END p_data[75]
  PIN p_data[76]
    DIRECTION OUTPUT ;
    USE SIGNAL ;
    PORT
      LAYER M5 ;
        RECT  16.56 86.316 16.584 86.4 ;
    END
  END p_data[76]
  PIN p_data[77]
    DIRECTION OUTPUT ;
    USE SIGNAL ;
    PORT
      LAYER M5 ;
        RECT  16.656 86.316 16.68 86.4 ;
    END
  END p_data[77]
  PIN p_data[78]
    DIRECTION OUTPUT ;
    USE SIGNAL ;
    PORT
      LAYER M5 ;
        RECT  16.752 86.316 16.776 86.4 ;
    END
  END p_data[78]
  PIN p_data[79]
    DIRECTION OUTPUT ;
    USE SIGNAL ;
    PORT
      LAYER M5 ;
        RECT  16.848 86.316 16.872 86.4 ;
    END
  END p_data[79]
  PIN p_data[7]
    DIRECTION OUTPUT ;
    USE SIGNAL ;
    PORT
      LAYER M3 ;
        RECT  25.524 86.363 25.542 86.4 ;
    END
  END p_data[7]
  PIN p_data[80]
    DIRECTION OUTPUT ;
    USE SIGNAL ;
    PORT
      LAYER M5 ;
        RECT  16.944 86.316 16.968 86.4 ;
    END
  END p_data[80]
  PIN p_data[81]
    DIRECTION OUTPUT ;
    USE SIGNAL ;
    PORT
      LAYER M5 ;
        RECT  17.04 86.316 17.064 86.4 ;
    END
  END p_data[81]
  PIN p_data[82]
    DIRECTION OUTPUT ;
    USE SIGNAL ;
    PORT
      LAYER M5 ;
        RECT  17.136 86.316 17.16 86.4 ;
    END
  END p_data[82]
  PIN p_data[83]
    DIRECTION OUTPUT ;
    USE SIGNAL ;
    PORT
      LAYER M5 ;
        RECT  17.232 86.316 17.256 86.4 ;
    END
  END p_data[83]
  PIN p_data[84]
    DIRECTION OUTPUT ;
    USE SIGNAL ;
    PORT
      LAYER M5 ;
        RECT  17.328 86.316 17.352 86.4 ;
    END
  END p_data[84]
  PIN p_data[85]
    DIRECTION OUTPUT ;
    USE SIGNAL ;
    PORT
      LAYER M5 ;
        RECT  17.424 86.316 17.448 86.4 ;
    END
  END p_data[85]
  PIN p_data[86]
    DIRECTION OUTPUT ;
    USE SIGNAL ;
    PORT
      LAYER M5 ;
        RECT  17.52 86.316 17.544 86.4 ;
    END
  END p_data[86]
  PIN p_data[87]
    DIRECTION OUTPUT ;
    USE SIGNAL ;
    PORT
      LAYER M5 ;
        RECT  17.616 86.316 17.64 86.4 ;
    END
  END p_data[87]
  PIN p_data[88]
    DIRECTION OUTPUT ;
    USE SIGNAL ;
    PORT
      LAYER M5 ;
        RECT  17.712 86.316 17.736 86.4 ;
    END
  END p_data[88]
  PIN p_data[89]
    DIRECTION OUTPUT ;
    USE SIGNAL ;
    PORT
      LAYER M5 ;
        RECT  17.808 86.316 17.832 86.4 ;
    END
  END p_data[89]
  PIN p_data[8]
    DIRECTION OUTPUT ;
    USE SIGNAL ;
    PORT
      LAYER M3 ;
        RECT  25.596 86.363 25.614 86.4 ;
    END
  END p_data[8]
  PIN p_data[90]
    DIRECTION OUTPUT ;
    USE SIGNAL ;
    PORT
      LAYER M5 ;
        RECT  17.904 86.316 17.928 86.4 ;
    END
  END p_data[90]
  PIN p_data[91]
    DIRECTION OUTPUT ;
    USE SIGNAL ;
    PORT
      LAYER M5 ;
        RECT  18 86.316 18.024 86.4 ;
    END
  END p_data[91]
  PIN p_data[92]
    DIRECTION OUTPUT ;
    USE SIGNAL ;
    PORT
      LAYER M5 ;
        RECT  18.096 86.316 18.12 86.4 ;
    END
  END p_data[92]
  PIN p_data[93]
    DIRECTION OUTPUT ;
    USE SIGNAL ;
    PORT
      LAYER M5 ;
        RECT  18.192 86.316 18.216 86.4 ;
    END
  END p_data[93]
  PIN p_data[94]
    DIRECTION OUTPUT ;
    USE SIGNAL ;
    PORT
      LAYER M5 ;
        RECT  18.288 86.316 18.312 86.4 ;
    END
  END p_data[94]
  PIN p_data[95]
    DIRECTION OUTPUT ;
    USE SIGNAL ;
    PORT
      LAYER M5 ;
        RECT  18.384 86.316 18.408 86.4 ;
    END
  END p_data[95]
  PIN p_data[96]
    DIRECTION OUTPUT ;
    USE SIGNAL ;
    PORT
      LAYER M5 ;
        RECT  18.48 86.316 18.504 86.4 ;
    END
  END p_data[96]
  PIN p_data[97]
    DIRECTION OUTPUT ;
    USE SIGNAL ;
    PORT
      LAYER M5 ;
        RECT  18.576 86.316 18.6 86.4 ;
    END
  END p_data[97]
  PIN p_data[98]
    DIRECTION OUTPUT ;
    USE SIGNAL ;
    PORT
      LAYER M5 ;
        RECT  18.672 86.316 18.696 86.4 ;
    END
  END p_data[98]
  PIN p_data[99]
    DIRECTION OUTPUT ;
    USE SIGNAL ;
    PORT
      LAYER M5 ;
        RECT  18.768 86.316 18.792 86.4 ;
    END
  END p_data[99]
  PIN p_data[9]
    DIRECTION OUTPUT ;
    USE SIGNAL ;
    PORT
      LAYER M3 ;
        RECT  25.668 86.363 25.686 86.4 ;
    END
  END p_data[9]
  PIN p_v
    DIRECTION OUTPUT ;
    USE SIGNAL ;
    PORT
      LAYER M3 ;
        RECT  24.516 86.363 24.534 86.4 ;
    END
  END p_v
  PIN rst_n
    DIRECTION INPUT ;
    USE SIGNAL ;
    PORT
      LAYER M3 ;
        RECT  24.588 86.363 24.606 86.4 ;
    END
  END rst_n
  PIN u_data[0]
    DIRECTION INPUT ;
    USE SIGNAL ;
    PORT
      LAYER M3 ;
        RECT  19.26 0 19.278 0.037 ;
    END
  END u_data[0]
  PIN u_data[100]
    DIRECTION INPUT ;
    USE SIGNAL ;
    PORT
      LAYER M3 ;
        RECT  19.548 0 19.566 0.037 ;
    END
  END u_data[100]
  PIN u_data[101]
    DIRECTION INPUT ;
    USE SIGNAL ;
    PORT
      LAYER M3 ;
        RECT  19.62 0 19.638 0.037 ;
    END
  END u_data[101]
  PIN u_data[102]
    DIRECTION INPUT ;
    USE SIGNAL ;
    PORT
      LAYER M3 ;
        RECT  19.692 0 19.71 0.037 ;
    END
  END u_data[102]
  PIN u_data[103]
    DIRECTION INPUT ;
    USE SIGNAL ;
    PORT
      LAYER M3 ;
        RECT  19.764 0 19.782 0.037 ;
    END
  END u_data[103]
  PIN u_data[104]
    DIRECTION INPUT ;
    USE SIGNAL ;
    PORT
      LAYER M3 ;
        RECT  19.836 0 19.854 0.037 ;
    END
  END u_data[104]
  PIN u_data[105]
    DIRECTION INPUT ;
    USE SIGNAL ;
    PORT
      LAYER M3 ;
        RECT  19.908 0 19.926 0.037 ;
    END
  END u_data[105]
  PIN u_data[106]
    DIRECTION INPUT ;
    USE SIGNAL ;
    PORT
      LAYER M3 ;
        RECT  19.98 0 19.998 0.037 ;
    END
  END u_data[106]
  PIN u_data[107]
    DIRECTION INPUT ;
    USE SIGNAL ;
    PORT
      LAYER M3 ;
        RECT  20.052 0 20.07 0.037 ;
    END
  END u_data[107]
  PIN u_data[108]
    DIRECTION INPUT ;
    USE SIGNAL ;
    PORT
      LAYER M3 ;
        RECT  20.124 0 20.142 0.037 ;
    END
  END u_data[108]
  PIN u_data[109]
    DIRECTION INPUT ;
    USE SIGNAL ;
    PORT
      LAYER M3 ;
        RECT  20.196 0 20.214 0.037 ;
    END
  END u_data[109]
  PIN u_data[10]
    DIRECTION INPUT ;
    USE SIGNAL ;
    PORT
      LAYER M5 ;
        RECT  20.496 0 20.52 0.084 ;
    END
  END u_data[10]
  PIN u_data[110]
    DIRECTION INPUT ;
    USE SIGNAL ;
    PORT
      LAYER M3 ;
        RECT  20.268 0 20.286 0.037 ;
    END
  END u_data[110]
  PIN u_data[111]
    DIRECTION INPUT ;
    USE SIGNAL ;
    PORT
      LAYER M3 ;
        RECT  20.34 0 20.358 0.037 ;
    END
  END u_data[111]
  PIN u_data[112]
    DIRECTION INPUT ;
    USE SIGNAL ;
    PORT
      LAYER M3 ;
        RECT  20.412 0 20.43 0.037 ;
    END
  END u_data[112]
  PIN u_data[113]
    DIRECTION INPUT ;
    USE SIGNAL ;
    PORT
      LAYER M3 ;
        RECT  20.484 0 20.502 0.037 ;
    END
  END u_data[113]
  PIN u_data[114]
    DIRECTION INPUT ;
    USE SIGNAL ;
    PORT
      LAYER M3 ;
        RECT  20.556 0 20.574 0.037 ;
    END
  END u_data[114]
  PIN u_data[115]
    DIRECTION INPUT ;
    USE SIGNAL ;
    PORT
      LAYER M3 ;
        RECT  20.628 0 20.646 0.037 ;
    END
  END u_data[115]
  PIN u_data[116]
    DIRECTION INPUT ;
    USE SIGNAL ;
    PORT
      LAYER M3 ;
        RECT  20.7 0 20.718 0.037 ;
    END
  END u_data[116]
  PIN u_data[117]
    DIRECTION INPUT ;
    USE SIGNAL ;
    PORT
      LAYER M3 ;
        RECT  20.772 0 20.79 0.037 ;
    END
  END u_data[117]
  PIN u_data[118]
    DIRECTION INPUT ;
    USE SIGNAL ;
    PORT
      LAYER M3 ;
        RECT  20.844 0 20.862 0.037 ;
    END
  END u_data[118]
  PIN u_data[119]
    DIRECTION INPUT ;
    USE SIGNAL ;
    PORT
      LAYER M3 ;
        RECT  20.916 0 20.934 0.037 ;
    END
  END u_data[119]
  PIN u_data[11]
    DIRECTION INPUT ;
    USE SIGNAL ;
    PORT
      LAYER M5 ;
        RECT  20.592 0 20.616 0.084 ;
    END
  END u_data[11]
  PIN u_data[120]
    DIRECTION INPUT ;
    USE SIGNAL ;
    PORT
      LAYER M3 ;
        RECT  20.988 0 21.006 0.037 ;
    END
  END u_data[120]
  PIN u_data[121]
    DIRECTION INPUT ;
    USE SIGNAL ;
    PORT
      LAYER M3 ;
        RECT  21.06 0 21.078 0.037 ;
    END
  END u_data[121]
  PIN u_data[122]
    DIRECTION INPUT ;
    USE SIGNAL ;
    PORT
      LAYER M3 ;
        RECT  21.132 0 21.15 0.037 ;
    END
  END u_data[122]
  PIN u_data[123]
    DIRECTION INPUT ;
    USE SIGNAL ;
    PORT
      LAYER M3 ;
        RECT  21.204 0 21.222 0.037 ;
    END
  END u_data[123]
  PIN u_data[124]
    DIRECTION INPUT ;
    USE SIGNAL ;
    PORT
      LAYER M3 ;
        RECT  21.276 0 21.294 0.037 ;
    END
  END u_data[124]
  PIN u_data[125]
    DIRECTION INPUT ;
    USE SIGNAL ;
    PORT
      LAYER M3 ;
        RECT  21.348 0 21.366 0.037 ;
    END
  END u_data[125]
  PIN u_data[126]
    DIRECTION INPUT ;
    USE SIGNAL ;
    PORT
      LAYER M3 ;
        RECT  21.42 0 21.438 0.037 ;
    END
  END u_data[126]
  PIN u_data[127]
    DIRECTION INPUT ;
    USE SIGNAL ;
    PORT
      LAYER M3 ;
        RECT  21.492 0 21.51 0.037 ;
    END
  END u_data[127]
  PIN u_data[128]
    DIRECTION INPUT ;
    USE SIGNAL ;
    PORT
      LAYER M3 ;
        RECT  21.564 0 21.582 0.037 ;
    END
  END u_data[128]
  PIN u_data[129]
    DIRECTION INPUT ;
    USE SIGNAL ;
    PORT
      LAYER M3 ;
        RECT  21.636 0 21.654 0.037 ;
    END
  END u_data[129]
  PIN u_data[12]
    DIRECTION INPUT ;
    USE SIGNAL ;
    PORT
      LAYER M5 ;
        RECT  20.688 0 20.712 0.084 ;
    END
  END u_data[12]
  PIN u_data[130]
    DIRECTION INPUT ;
    USE SIGNAL ;
    PORT
      LAYER M3 ;
        RECT  21.708 0 21.726 0.037 ;
    END
  END u_data[130]
  PIN u_data[131]
    DIRECTION INPUT ;
    USE SIGNAL ;
    PORT
      LAYER M3 ;
        RECT  21.78 0 21.798 0.037 ;
    END
  END u_data[131]
  PIN u_data[132]
    DIRECTION INPUT ;
    USE SIGNAL ;
    PORT
      LAYER M3 ;
        RECT  21.852 0 21.87 0.037 ;
    END
  END u_data[132]
  PIN u_data[133]
    DIRECTION INPUT ;
    USE SIGNAL ;
    PORT
      LAYER M3 ;
        RECT  21.924 0 21.942 0.037 ;
    END
  END u_data[133]
  PIN u_data[134]
    DIRECTION INPUT ;
    USE SIGNAL ;
    PORT
      LAYER M3 ;
        RECT  21.996 0 22.014 0.037 ;
    END
  END u_data[134]
  PIN u_data[135]
    DIRECTION INPUT ;
    USE SIGNAL ;
    PORT
      LAYER M3 ;
        RECT  22.068 0 22.086 0.037 ;
    END
  END u_data[135]
  PIN u_data[136]
    DIRECTION INPUT ;
    USE SIGNAL ;
    PORT
      LAYER M3 ;
        RECT  22.14 0 22.158 0.037 ;
    END
  END u_data[136]
  PIN u_data[137]
    DIRECTION INPUT ;
    USE SIGNAL ;
    PORT
      LAYER M3 ;
        RECT  22.212 0 22.23 0.037 ;
    END
  END u_data[137]
  PIN u_data[138]
    DIRECTION INPUT ;
    USE SIGNAL ;
    PORT
      LAYER M3 ;
        RECT  22.284 0 22.302 0.037 ;
    END
  END u_data[138]
  PIN u_data[139]
    DIRECTION INPUT ;
    USE SIGNAL ;
    PORT
      LAYER M3 ;
        RECT  22.356 0 22.374 0.037 ;
    END
  END u_data[139]
  PIN u_data[13]
    DIRECTION INPUT ;
    USE SIGNAL ;
    PORT
      LAYER M5 ;
        RECT  20.784 0 20.808 0.084 ;
    END
  END u_data[13]
  PIN u_data[140]
    DIRECTION INPUT ;
    USE SIGNAL ;
    PORT
      LAYER M3 ;
        RECT  22.428 0 22.446 0.037 ;
    END
  END u_data[140]
  PIN u_data[141]
    DIRECTION INPUT ;
    USE SIGNAL ;
    PORT
      LAYER M3 ;
        RECT  22.5 0 22.518 0.037 ;
    END
  END u_data[141]
  PIN u_data[142]
    DIRECTION INPUT ;
    USE SIGNAL ;
    PORT
      LAYER M3 ;
        RECT  22.572 0 22.59 0.037 ;
    END
  END u_data[142]
  PIN u_data[143]
    DIRECTION INPUT ;
    USE SIGNAL ;
    PORT
      LAYER M3 ;
        RECT  22.644 0 22.662 0.037 ;
    END
  END u_data[143]
  PIN u_data[144]
    DIRECTION INPUT ;
    USE SIGNAL ;
    PORT
      LAYER M3 ;
        RECT  22.716 0 22.734 0.037 ;
    END
  END u_data[144]
  PIN u_data[145]
    DIRECTION INPUT ;
    USE SIGNAL ;
    PORT
      LAYER M3 ;
        RECT  22.788 0 22.806 0.037 ;
    END
  END u_data[145]
  PIN u_data[146]
    DIRECTION INPUT ;
    USE SIGNAL ;
    PORT
      LAYER M3 ;
        RECT  22.86 0 22.878 0.037 ;
    END
  END u_data[146]
  PIN u_data[147]
    DIRECTION INPUT ;
    USE SIGNAL ;
    PORT
      LAYER M3 ;
        RECT  22.932 0 22.95 0.037 ;
    END
  END u_data[147]
  PIN u_data[148]
    DIRECTION INPUT ;
    USE SIGNAL ;
    PORT
      LAYER M3 ;
        RECT  23.004 0 23.022 0.037 ;
    END
  END u_data[148]
  PIN u_data[149]
    DIRECTION INPUT ;
    USE SIGNAL ;
    PORT
      LAYER M3 ;
        RECT  23.076 0 23.094 0.037 ;
    END
  END u_data[149]
  PIN u_data[14]
    DIRECTION INPUT ;
    USE SIGNAL ;
    PORT
      LAYER M5 ;
        RECT  20.88 0 20.904 0.084 ;
    END
  END u_data[14]
  PIN u_data[150]
    DIRECTION INPUT ;
    USE SIGNAL ;
    PORT
      LAYER M3 ;
        RECT  23.148 0 23.166 0.037 ;
    END
  END u_data[150]
  PIN u_data[151]
    DIRECTION INPUT ;
    USE SIGNAL ;
    PORT
      LAYER M3 ;
        RECT  23.22 0 23.238 0.037 ;
    END
  END u_data[151]
  PIN u_data[152]
    DIRECTION INPUT ;
    USE SIGNAL ;
    PORT
      LAYER M3 ;
        RECT  23.292 0 23.31 0.037 ;
    END
  END u_data[152]
  PIN u_data[153]
    DIRECTION INPUT ;
    USE SIGNAL ;
    PORT
      LAYER M3 ;
        RECT  23.364 0 23.382 0.037 ;
    END
  END u_data[153]
  PIN u_data[154]
    DIRECTION INPUT ;
    USE SIGNAL ;
    PORT
      LAYER M3 ;
        RECT  23.436 0 23.454 0.037 ;
    END
  END u_data[154]
  PIN u_data[155]
    DIRECTION INPUT ;
    USE SIGNAL ;
    PORT
      LAYER M3 ;
        RECT  23.508 0 23.526 0.037 ;
    END
  END u_data[155]
  PIN u_data[156]
    DIRECTION INPUT ;
    USE SIGNAL ;
    PORT
      LAYER M3 ;
        RECT  23.58 0 23.598 0.037 ;
    END
  END u_data[156]
  PIN u_data[157]
    DIRECTION INPUT ;
    USE SIGNAL ;
    PORT
      LAYER M3 ;
        RECT  23.652 0 23.67 0.037 ;
    END
  END u_data[157]
  PIN u_data[158]
    DIRECTION INPUT ;
    USE SIGNAL ;
    PORT
      LAYER M3 ;
        RECT  23.724 0 23.742 0.037 ;
    END
  END u_data[158]
  PIN u_data[159]
    DIRECTION INPUT ;
    USE SIGNAL ;
    PORT
      LAYER M3 ;
        RECT  23.796 0 23.814 0.037 ;
    END
  END u_data[159]
  PIN u_data[15]
    DIRECTION INPUT ;
    USE SIGNAL ;
    PORT
      LAYER M5 ;
        RECT  20.976 0 21 0.084 ;
    END
  END u_data[15]
  PIN u_data[160]
    DIRECTION INPUT ;
    USE SIGNAL ;
    PORT
      LAYER M3 ;
        RECT  23.868 0 23.886 0.037 ;
    END
  END u_data[160]
  PIN u_data[161]
    DIRECTION INPUT ;
    USE SIGNAL ;
    PORT
      LAYER M3 ;
        RECT  23.94 0 23.958 0.037 ;
    END
  END u_data[161]
  PIN u_data[162]
    DIRECTION INPUT ;
    USE SIGNAL ;
    PORT
      LAYER M3 ;
        RECT  24.012 0 24.03 0.037 ;
    END
  END u_data[162]
  PIN u_data[163]
    DIRECTION INPUT ;
    USE SIGNAL ;
    PORT
      LAYER M3 ;
        RECT  24.084 0 24.102 0.037 ;
    END
  END u_data[163]
  PIN u_data[164]
    DIRECTION INPUT ;
    USE SIGNAL ;
    PORT
      LAYER M3 ;
        RECT  26.46 0 26.478 0.037 ;
    END
  END u_data[164]
  PIN u_data[165]
    DIRECTION INPUT ;
    USE SIGNAL ;
    PORT
      LAYER M3 ;
        RECT  26.532 0 26.55 0.037 ;
    END
  END u_data[165]
  PIN u_data[166]
    DIRECTION INPUT ;
    USE SIGNAL ;
    PORT
      LAYER M3 ;
        RECT  26.604 0 26.622 0.037 ;
    END
  END u_data[166]
  PIN u_data[167]
    DIRECTION INPUT ;
    USE SIGNAL ;
    PORT
      LAYER M3 ;
        RECT  26.676 0 26.694 0.037 ;
    END
  END u_data[167]
  PIN u_data[168]
    DIRECTION INPUT ;
    USE SIGNAL ;
    PORT
      LAYER M3 ;
        RECT  26.748 0 26.766 0.037 ;
    END
  END u_data[168]
  PIN u_data[169]
    DIRECTION INPUT ;
    USE SIGNAL ;
    PORT
      LAYER M3 ;
        RECT  26.82 0 26.838 0.037 ;
    END
  END u_data[169]
  PIN u_data[16]
    DIRECTION INPUT ;
    USE SIGNAL ;
    PORT
      LAYER M5 ;
        RECT  21.072 0 21.096 0.084 ;
    END
  END u_data[16]
  PIN u_data[170]
    DIRECTION INPUT ;
    USE SIGNAL ;
    PORT
      LAYER M3 ;
        RECT  26.892 0 26.91 0.037 ;
    END
  END u_data[170]
  PIN u_data[171]
    DIRECTION INPUT ;
    USE SIGNAL ;
    PORT
      LAYER M3 ;
        RECT  26.964 0 26.982 0.037 ;
    END
  END u_data[171]
  PIN u_data[172]
    DIRECTION INPUT ;
    USE SIGNAL ;
    PORT
      LAYER M3 ;
        RECT  27.036 0 27.054 0.037 ;
    END
  END u_data[172]
  PIN u_data[173]
    DIRECTION INPUT ;
    USE SIGNAL ;
    PORT
      LAYER M3 ;
        RECT  27.108 0 27.126 0.037 ;
    END
  END u_data[173]
  PIN u_data[174]
    DIRECTION INPUT ;
    USE SIGNAL ;
    PORT
      LAYER M3 ;
        RECT  27.18 0 27.198 0.037 ;
    END
  END u_data[174]
  PIN u_data[175]
    DIRECTION INPUT ;
    USE SIGNAL ;
    PORT
      LAYER M3 ;
        RECT  27.252 0 27.27 0.037 ;
    END
  END u_data[175]
  PIN u_data[176]
    DIRECTION INPUT ;
    USE SIGNAL ;
    PORT
      LAYER M3 ;
        RECT  27.324 0 27.342 0.037 ;
    END
  END u_data[176]
  PIN u_data[177]
    DIRECTION INPUT ;
    USE SIGNAL ;
    PORT
      LAYER M3 ;
        RECT  27.396 0 27.414 0.037 ;
    END
  END u_data[177]
  PIN u_data[178]
    DIRECTION INPUT ;
    USE SIGNAL ;
    PORT
      LAYER M3 ;
        RECT  27.468 0 27.486 0.037 ;
    END
  END u_data[178]
  PIN u_data[179]
    DIRECTION INPUT ;
    USE SIGNAL ;
    PORT
      LAYER M3 ;
        RECT  27.54 0 27.558 0.037 ;
    END
  END u_data[179]
  PIN u_data[17]
    DIRECTION INPUT ;
    USE SIGNAL ;
    PORT
      LAYER M5 ;
        RECT  21.168 0 21.192 0.084 ;
    END
  END u_data[17]
  PIN u_data[180]
    DIRECTION INPUT ;
    USE SIGNAL ;
    PORT
      LAYER M3 ;
        RECT  27.612 0 27.63 0.037 ;
    END
  END u_data[180]
  PIN u_data[181]
    DIRECTION INPUT ;
    USE SIGNAL ;
    PORT
      LAYER M3 ;
        RECT  27.684 0 27.702 0.037 ;
    END
  END u_data[181]
  PIN u_data[182]
    DIRECTION INPUT ;
    USE SIGNAL ;
    PORT
      LAYER M3 ;
        RECT  27.756 0 27.774 0.037 ;
    END
  END u_data[182]
  PIN u_data[183]
    DIRECTION INPUT ;
    USE SIGNAL ;
    PORT
      LAYER M3 ;
        RECT  27.828 0 27.846 0.037 ;
    END
  END u_data[183]
  PIN u_data[184]
    DIRECTION INPUT ;
    USE SIGNAL ;
    PORT
      LAYER M3 ;
        RECT  27.9 0 27.918 0.037 ;
    END
  END u_data[184]
  PIN u_data[185]
    DIRECTION INPUT ;
    USE SIGNAL ;
    PORT
      LAYER M3 ;
        RECT  27.972 0 27.99 0.037 ;
    END
  END u_data[185]
  PIN u_data[186]
    DIRECTION INPUT ;
    USE SIGNAL ;
    PORT
      LAYER M3 ;
        RECT  28.044 0 28.062 0.037 ;
    END
  END u_data[186]
  PIN u_data[187]
    DIRECTION INPUT ;
    USE SIGNAL ;
    PORT
      LAYER M3 ;
        RECT  28.116 0 28.134 0.037 ;
    END
  END u_data[187]
  PIN u_data[188]
    DIRECTION INPUT ;
    USE SIGNAL ;
    PORT
      LAYER M3 ;
        RECT  28.188 0 28.206 0.037 ;
    END
  END u_data[188]
  PIN u_data[189]
    DIRECTION INPUT ;
    USE SIGNAL ;
    PORT
      LAYER M3 ;
        RECT  28.26 0 28.278 0.037 ;
    END
  END u_data[189]
  PIN u_data[18]
    DIRECTION INPUT ;
    USE SIGNAL ;
    PORT
      LAYER M5 ;
        RECT  21.264 0 21.288 0.084 ;
    END
  END u_data[18]
  PIN u_data[190]
    DIRECTION INPUT ;
    USE SIGNAL ;
    PORT
      LAYER M3 ;
        RECT  28.332 0 28.35 0.037 ;
    END
  END u_data[190]
  PIN u_data[191]
    DIRECTION INPUT ;
    USE SIGNAL ;
    PORT
      LAYER M3 ;
        RECT  28.404 0 28.422 0.037 ;
    END
  END u_data[191]
  PIN u_data[192]
    DIRECTION INPUT ;
    USE SIGNAL ;
    PORT
      LAYER M3 ;
        RECT  28.476 0 28.494 0.037 ;
    END
  END u_data[192]
  PIN u_data[193]
    DIRECTION INPUT ;
    USE SIGNAL ;
    PORT
      LAYER M3 ;
        RECT  28.548 0 28.566 0.037 ;
    END
  END u_data[193]
  PIN u_data[194]
    DIRECTION INPUT ;
    USE SIGNAL ;
    PORT
      LAYER M3 ;
        RECT  28.62 0 28.638 0.037 ;
    END
  END u_data[194]
  PIN u_data[195]
    DIRECTION INPUT ;
    USE SIGNAL ;
    PORT
      LAYER M3 ;
        RECT  28.692 0 28.71 0.037 ;
    END
  END u_data[195]
  PIN u_data[196]
    DIRECTION INPUT ;
    USE SIGNAL ;
    PORT
      LAYER M5 ;
        RECT  22.992 0 23.016 0.084 ;
    END
  END u_data[196]
  PIN u_data[197]
    DIRECTION INPUT ;
    USE SIGNAL ;
    PORT
      LAYER M5 ;
        RECT  23.088 0 23.112 0.084 ;
    END
  END u_data[197]
  PIN u_data[198]
    DIRECTION INPUT ;
    USE SIGNAL ;
    PORT
      LAYER M5 ;
        RECT  23.184 0 23.208 0.084 ;
    END
  END u_data[198]
  PIN u_data[199]
    DIRECTION INPUT ;
    USE SIGNAL ;
    PORT
      LAYER M5 ;
        RECT  23.28 0 23.304 0.084 ;
    END
  END u_data[199]
  PIN u_data[19]
    DIRECTION INPUT ;
    USE SIGNAL ;
    PORT
      LAYER M5 ;
        RECT  21.36 0 21.384 0.084 ;
    END
  END u_data[19]
  PIN u_data[1]
    DIRECTION INPUT ;
    USE SIGNAL ;
    PORT
      LAYER M3 ;
        RECT  19.332 0 19.35 0.037 ;
    END
  END u_data[1]
  PIN u_data[200]
    DIRECTION INPUT ;
    USE SIGNAL ;
    PORT
      LAYER M5 ;
        RECT  23.376 0 23.4 0.084 ;
    END
  END u_data[200]
  PIN u_data[201]
    DIRECTION INPUT ;
    USE SIGNAL ;
    PORT
      LAYER M5 ;
        RECT  23.472 0 23.496 0.084 ;
    END
  END u_data[201]
  PIN u_data[202]
    DIRECTION INPUT ;
    USE SIGNAL ;
    PORT
      LAYER M5 ;
        RECT  23.568 0 23.592 0.084 ;
    END
  END u_data[202]
  PIN u_data[203]
    DIRECTION INPUT ;
    USE SIGNAL ;
    PORT
      LAYER M5 ;
        RECT  23.664 0 23.688 0.084 ;
    END
  END u_data[203]
  PIN u_data[204]
    DIRECTION INPUT ;
    USE SIGNAL ;
    PORT
      LAYER M5 ;
        RECT  23.76 0 23.784 0.084 ;
    END
  END u_data[204]
  PIN u_data[205]
    DIRECTION INPUT ;
    USE SIGNAL ;
    PORT
      LAYER M5 ;
        RECT  23.856 0 23.88 0.084 ;
    END
  END u_data[205]
  PIN u_data[206]
    DIRECTION INPUT ;
    USE SIGNAL ;
    PORT
      LAYER M5 ;
        RECT  23.952 0 23.976 0.084 ;
    END
  END u_data[206]
  PIN u_data[207]
    DIRECTION INPUT ;
    USE SIGNAL ;
    PORT
      LAYER M5 ;
        RECT  24.048 0 24.072 0.084 ;
    END
  END u_data[207]
  PIN u_data[208]
    DIRECTION INPUT ;
    USE SIGNAL ;
    PORT
      LAYER M5 ;
        RECT  24.144 0 24.168 0.084 ;
    END
  END u_data[208]
  PIN u_data[209]
    DIRECTION INPUT ;
    USE SIGNAL ;
    PORT
      LAYER M5 ;
        RECT  24.24 0 24.264 0.084 ;
    END
  END u_data[209]
  PIN u_data[20]
    DIRECTION INPUT ;
    USE SIGNAL ;
    PORT
      LAYER M5 ;
        RECT  21.456 0 21.48 0.084 ;
    END
  END u_data[20]
  PIN u_data[210]
    DIRECTION INPUT ;
    USE SIGNAL ;
    PORT
      LAYER M5 ;
        RECT  24.336 0 24.36 0.084 ;
    END
  END u_data[210]
  PIN u_data[211]
    DIRECTION INPUT ;
    USE SIGNAL ;
    PORT
      LAYER M5 ;
        RECT  24.432 0 24.456 0.084 ;
    END
  END u_data[211]
  PIN u_data[212]
    DIRECTION INPUT ;
    USE SIGNAL ;
    PORT
      LAYER M5 ;
        RECT  24.528 0 24.552 0.084 ;
    END
  END u_data[212]
  PIN u_data[213]
    DIRECTION INPUT ;
    USE SIGNAL ;
    PORT
      LAYER M5 ;
        RECT  24.624 0 24.648 0.084 ;
    END
  END u_data[213]
  PIN u_data[214]
    DIRECTION INPUT ;
    USE SIGNAL ;
    PORT
      LAYER M5 ;
        RECT  24.72 0 24.744 0.084 ;
    END
  END u_data[214]
  PIN u_data[215]
    DIRECTION INPUT ;
    USE SIGNAL ;
    PORT
      LAYER M5 ;
        RECT  24.816 0 24.84 0.084 ;
    END
  END u_data[215]
  PIN u_data[216]
    DIRECTION INPUT ;
    USE SIGNAL ;
    PORT
      LAYER M5 ;
        RECT  24.912 0 24.936 0.084 ;
    END
  END u_data[216]
  PIN u_data[217]
    DIRECTION INPUT ;
    USE SIGNAL ;
    PORT
      LAYER M5 ;
        RECT  25.008 0 25.032 0.084 ;
    END
  END u_data[217]
  PIN u_data[218]
    DIRECTION INPUT ;
    USE SIGNAL ;
    PORT
      LAYER M5 ;
        RECT  25.104 0 25.128 0.084 ;
    END
  END u_data[218]
  PIN u_data[219]
    DIRECTION INPUT ;
    USE SIGNAL ;
    PORT
      LAYER M5 ;
        RECT  25.2 0 25.224 0.084 ;
    END
  END u_data[219]
  PIN u_data[21]
    DIRECTION INPUT ;
    USE SIGNAL ;
    PORT
      LAYER M5 ;
        RECT  21.552 0 21.576 0.084 ;
    END
  END u_data[21]
  PIN u_data[220]
    DIRECTION INPUT ;
    USE SIGNAL ;
    PORT
      LAYER M5 ;
        RECT  25.296 0 25.32 0.084 ;
    END
  END u_data[220]
  PIN u_data[221]
    DIRECTION INPUT ;
    USE SIGNAL ;
    PORT
      LAYER M5 ;
        RECT  25.392 0 25.416 0.084 ;
    END
  END u_data[221]
  PIN u_data[222]
    DIRECTION INPUT ;
    USE SIGNAL ;
    PORT
      LAYER M5 ;
        RECT  25.488 0 25.512 0.084 ;
    END
  END u_data[222]
  PIN u_data[223]
    DIRECTION INPUT ;
    USE SIGNAL ;
    PORT
      LAYER M5 ;
        RECT  25.584 0 25.608 0.084 ;
    END
  END u_data[223]
  PIN u_data[224]
    DIRECTION INPUT ;
    USE SIGNAL ;
    PORT
      LAYER M5 ;
        RECT  25.68 0 25.704 0.084 ;
    END
  END u_data[224]
  PIN u_data[225]
    DIRECTION INPUT ;
    USE SIGNAL ;
    PORT
      LAYER M5 ;
        RECT  25.776 0 25.8 0.084 ;
    END
  END u_data[225]
  PIN u_data[226]
    DIRECTION INPUT ;
    USE SIGNAL ;
    PORT
      LAYER M5 ;
        RECT  25.872 0 25.896 0.084 ;
    END
  END u_data[226]
  PIN u_data[227]
    DIRECTION INPUT ;
    USE SIGNAL ;
    PORT
      LAYER M5 ;
        RECT  25.968 0 25.992 0.084 ;
    END
  END u_data[227]
  PIN u_data[228]
    DIRECTION INPUT ;
    USE SIGNAL ;
    PORT
      LAYER M5 ;
        RECT  26.064 0 26.088 0.084 ;
    END
  END u_data[228]
  PIN u_data[229]
    DIRECTION INPUT ;
    USE SIGNAL ;
    PORT
      LAYER M5 ;
        RECT  26.16 0 26.184 0.084 ;
    END
  END u_data[229]
  PIN u_data[22]
    DIRECTION INPUT ;
    USE SIGNAL ;
    PORT
      LAYER M5 ;
        RECT  21.648 0 21.672 0.084 ;
    END
  END u_data[22]
  PIN u_data[230]
    DIRECTION INPUT ;
    USE SIGNAL ;
    PORT
      LAYER M5 ;
        RECT  26.256 0 26.28 0.084 ;
    END
  END u_data[230]
  PIN u_data[231]
    DIRECTION INPUT ;
    USE SIGNAL ;
    PORT
      LAYER M5 ;
        RECT  26.352 0 26.376 0.084 ;
    END
  END u_data[231]
  PIN u_data[232]
    DIRECTION INPUT ;
    USE SIGNAL ;
    PORT
      LAYER M5 ;
        RECT  26.448 0 26.472 0.084 ;
    END
  END u_data[232]
  PIN u_data[233]
    DIRECTION INPUT ;
    USE SIGNAL ;
    PORT
      LAYER M5 ;
        RECT  26.544 0 26.568 0.084 ;
    END
  END u_data[233]
  PIN u_data[234]
    DIRECTION INPUT ;
    USE SIGNAL ;
    PORT
      LAYER M5 ;
        RECT  26.64 0 26.664 0.084 ;
    END
  END u_data[234]
  PIN u_data[235]
    DIRECTION INPUT ;
    USE SIGNAL ;
    PORT
      LAYER M5 ;
        RECT  26.736 0 26.76 0.084 ;
    END
  END u_data[235]
  PIN u_data[236]
    DIRECTION INPUT ;
    USE SIGNAL ;
    PORT
      LAYER M5 ;
        RECT  26.832 0 26.856 0.084 ;
    END
  END u_data[236]
  PIN u_data[237]
    DIRECTION INPUT ;
    USE SIGNAL ;
    PORT
      LAYER M5 ;
        RECT  26.928 0 26.952 0.084 ;
    END
  END u_data[237]
  PIN u_data[238]
    DIRECTION INPUT ;
    USE SIGNAL ;
    PORT
      LAYER M5 ;
        RECT  27.024 0 27.048 0.084 ;
    END
  END u_data[238]
  PIN u_data[239]
    DIRECTION INPUT ;
    USE SIGNAL ;
    PORT
      LAYER M5 ;
        RECT  27.12 0 27.144 0.084 ;
    END
  END u_data[239]
  PIN u_data[23]
    DIRECTION INPUT ;
    USE SIGNAL ;
    PORT
      LAYER M5 ;
        RECT  21.744 0 21.768 0.084 ;
    END
  END u_data[23]
  PIN u_data[240]
    DIRECTION INPUT ;
    USE SIGNAL ;
    PORT
      LAYER M5 ;
        RECT  27.216 0 27.24 0.084 ;
    END
  END u_data[240]
  PIN u_data[241]
    DIRECTION INPUT ;
    USE SIGNAL ;
    PORT
      LAYER M5 ;
        RECT  27.312 0 27.336 0.084 ;
    END
  END u_data[241]
  PIN u_data[242]
    DIRECTION INPUT ;
    USE SIGNAL ;
    PORT
      LAYER M5 ;
        RECT  27.408 0 27.432 0.084 ;
    END
  END u_data[242]
  PIN u_data[243]
    DIRECTION INPUT ;
    USE SIGNAL ;
    PORT
      LAYER M5 ;
        RECT  27.504 0 27.528 0.084 ;
    END
  END u_data[243]
  PIN u_data[244]
    DIRECTION INPUT ;
    USE SIGNAL ;
    PORT
      LAYER M5 ;
        RECT  27.6 0 27.624 0.084 ;
    END
  END u_data[244]
  PIN u_data[245]
    DIRECTION INPUT ;
    USE SIGNAL ;
    PORT
      LAYER M5 ;
        RECT  27.696 0 27.72 0.084 ;
    END
  END u_data[245]
  PIN u_data[246]
    DIRECTION INPUT ;
    USE SIGNAL ;
    PORT
      LAYER M5 ;
        RECT  27.792 0 27.816 0.084 ;
    END
  END u_data[246]
  PIN u_data[247]
    DIRECTION INPUT ;
    USE SIGNAL ;
    PORT
      LAYER M5 ;
        RECT  27.888 0 27.912 0.084 ;
    END
  END u_data[247]
  PIN u_data[248]
    DIRECTION INPUT ;
    USE SIGNAL ;
    PORT
      LAYER M5 ;
        RECT  27.984 0 28.008 0.084 ;
    END
  END u_data[248]
  PIN u_data[249]
    DIRECTION INPUT ;
    USE SIGNAL ;
    PORT
      LAYER M5 ;
        RECT  28.08 0 28.104 0.084 ;
    END
  END u_data[249]
  PIN u_data[24]
    DIRECTION INPUT ;
    USE SIGNAL ;
    PORT
      LAYER M5 ;
        RECT  21.84 0 21.864 0.084 ;
    END
  END u_data[24]
  PIN u_data[250]
    DIRECTION INPUT ;
    USE SIGNAL ;
    PORT
      LAYER M5 ;
        RECT  28.176 0 28.2 0.084 ;
    END
  END u_data[250]
  PIN u_data[251]
    DIRECTION INPUT ;
    USE SIGNAL ;
    PORT
      LAYER M5 ;
        RECT  28.272 0 28.296 0.084 ;
    END
  END u_data[251]
  PIN u_data[252]
    DIRECTION INPUT ;
    USE SIGNAL ;
    PORT
      LAYER M5 ;
        RECT  28.368 0 28.392 0.084 ;
    END
  END u_data[252]
  PIN u_data[253]
    DIRECTION INPUT ;
    USE SIGNAL ;
    PORT
      LAYER M5 ;
        RECT  28.464 0 28.488 0.084 ;
    END
  END u_data[253]
  PIN u_data[254]
    DIRECTION INPUT ;
    USE SIGNAL ;
    PORT
      LAYER M5 ;
        RECT  28.56 0 28.584 0.084 ;
    END
  END u_data[254]
  PIN u_data[255]
    DIRECTION INPUT ;
    USE SIGNAL ;
    PORT
      LAYER M5 ;
        RECT  28.656 0 28.68 0.084 ;
    END
  END u_data[255]
  PIN u_data[256]
    DIRECTION INPUT ;
    USE SIGNAL ;
    PORT
      LAYER M5 ;
        RECT  28.752 0 28.776 0.084 ;
    END
  END u_data[256]
  PIN u_data[257]
    DIRECTION INPUT ;
    USE SIGNAL ;
    PORT
      LAYER M5 ;
        RECT  28.848 0 28.872 0.084 ;
    END
  END u_data[257]
  PIN u_data[258]
    DIRECTION INPUT ;
    USE SIGNAL ;
    PORT
      LAYER M5 ;
        RECT  28.944 0 28.968 0.084 ;
    END
  END u_data[258]
  PIN u_data[259]
    DIRECTION INPUT ;
    USE SIGNAL ;
    PORT
      LAYER M5 ;
        RECT  29.04 0 29.064 0.084 ;
    END
  END u_data[259]
  PIN u_data[25]
    DIRECTION INPUT ;
    USE SIGNAL ;
    PORT
      LAYER M5 ;
        RECT  21.936 0 21.96 0.084 ;
    END
  END u_data[25]
  PIN u_data[260]
    DIRECTION INPUT ;
    USE SIGNAL ;
    PORT
      LAYER M5 ;
        RECT  32.208 0 32.232 0.084 ;
    END
  END u_data[260]
  PIN u_data[261]
    DIRECTION INPUT ;
    USE SIGNAL ;
    PORT
      LAYER M5 ;
        RECT  32.304 0 32.328 0.084 ;
    END
  END u_data[261]
  PIN u_data[262]
    DIRECTION INPUT ;
    USE SIGNAL ;
    PORT
      LAYER M5 ;
        RECT  32.4 0 32.424 0.084 ;
    END
  END u_data[262]
  PIN u_data[263]
    DIRECTION INPUT ;
    USE SIGNAL ;
    PORT
      LAYER M5 ;
        RECT  32.496 0 32.52 0.084 ;
    END
  END u_data[263]
  PIN u_data[264]
    DIRECTION INPUT ;
    USE SIGNAL ;
    PORT
      LAYER M5 ;
        RECT  32.592 0 32.616 0.084 ;
    END
  END u_data[264]
  PIN u_data[265]
    DIRECTION INPUT ;
    USE SIGNAL ;
    PORT
      LAYER M5 ;
        RECT  32.688 0 32.712 0.084 ;
    END
  END u_data[265]
  PIN u_data[266]
    DIRECTION INPUT ;
    USE SIGNAL ;
    PORT
      LAYER M5 ;
        RECT  32.784 0 32.808 0.084 ;
    END
  END u_data[266]
  PIN u_data[267]
    DIRECTION INPUT ;
    USE SIGNAL ;
    PORT
      LAYER M5 ;
        RECT  32.88 0 32.904 0.084 ;
    END
  END u_data[267]
  PIN u_data[268]
    DIRECTION INPUT ;
    USE SIGNAL ;
    PORT
      LAYER M5 ;
        RECT  32.976 0 33 0.084 ;
    END
  END u_data[268]
  PIN u_data[269]
    DIRECTION INPUT ;
    USE SIGNAL ;
    PORT
      LAYER M5 ;
        RECT  33.072 0 33.096 0.084 ;
    END
  END u_data[269]
  PIN u_data[26]
    DIRECTION INPUT ;
    USE SIGNAL ;
    PORT
      LAYER M5 ;
        RECT  22.032 0 22.056 0.084 ;
    END
  END u_data[26]
  PIN u_data[270]
    DIRECTION INPUT ;
    USE SIGNAL ;
    PORT
      LAYER M5 ;
        RECT  33.168 0 33.192 0.084 ;
    END
  END u_data[270]
  PIN u_data[271]
    DIRECTION INPUT ;
    USE SIGNAL ;
    PORT
      LAYER M5 ;
        RECT  33.264 0 33.288 0.084 ;
    END
  END u_data[271]
  PIN u_data[272]
    DIRECTION INPUT ;
    USE SIGNAL ;
    PORT
      LAYER M5 ;
        RECT  33.36 0 33.384 0.084 ;
    END
  END u_data[272]
  PIN u_data[273]
    DIRECTION INPUT ;
    USE SIGNAL ;
    PORT
      LAYER M5 ;
        RECT  33.456 0 33.48 0.084 ;
    END
  END u_data[273]
  PIN u_data[274]
    DIRECTION INPUT ;
    USE SIGNAL ;
    PORT
      LAYER M5 ;
        RECT  33.552 0 33.576 0.084 ;
    END
  END u_data[274]
  PIN u_data[275]
    DIRECTION INPUT ;
    USE SIGNAL ;
    PORT
      LAYER M5 ;
        RECT  33.648 0 33.672 0.084 ;
    END
  END u_data[275]
  PIN u_data[276]
    DIRECTION INPUT ;
    USE SIGNAL ;
    PORT
      LAYER M5 ;
        RECT  33.744 0 33.768 0.084 ;
    END
  END u_data[276]
  PIN u_data[277]
    DIRECTION INPUT ;
    USE SIGNAL ;
    PORT
      LAYER M5 ;
        RECT  33.84 0 33.864 0.084 ;
    END
  END u_data[277]
  PIN u_data[278]
    DIRECTION INPUT ;
    USE SIGNAL ;
    PORT
      LAYER M5 ;
        RECT  33.936 0 33.96 0.084 ;
    END
  END u_data[278]
  PIN u_data[279]
    DIRECTION INPUT ;
    USE SIGNAL ;
    PORT
      LAYER M5 ;
        RECT  34.032 0 34.056 0.084 ;
    END
  END u_data[279]
  PIN u_data[27]
    DIRECTION INPUT ;
    USE SIGNAL ;
    PORT
      LAYER M5 ;
        RECT  22.128 0 22.152 0.084 ;
    END
  END u_data[27]
  PIN u_data[280]
    DIRECTION INPUT ;
    USE SIGNAL ;
    PORT
      LAYER M5 ;
        RECT  34.128 0 34.152 0.084 ;
    END
  END u_data[280]
  PIN u_data[281]
    DIRECTION INPUT ;
    USE SIGNAL ;
    PORT
      LAYER M5 ;
        RECT  34.224 0 34.248 0.084 ;
    END
  END u_data[281]
  PIN u_data[282]
    DIRECTION INPUT ;
    USE SIGNAL ;
    PORT
      LAYER M5 ;
        RECT  34.32 0 34.344 0.084 ;
    END
  END u_data[282]
  PIN u_data[283]
    DIRECTION INPUT ;
    USE SIGNAL ;
    PORT
      LAYER M5 ;
        RECT  34.416 0 34.44 0.084 ;
    END
  END u_data[283]
  PIN u_data[284]
    DIRECTION INPUT ;
    USE SIGNAL ;
    PORT
      LAYER M5 ;
        RECT  34.512 0 34.536 0.084 ;
    END
  END u_data[284]
  PIN u_data[285]
    DIRECTION INPUT ;
    USE SIGNAL ;
    PORT
      LAYER M5 ;
        RECT  34.608 0 34.632 0.084 ;
    END
  END u_data[285]
  PIN u_data[286]
    DIRECTION INPUT ;
    USE SIGNAL ;
    PORT
      LAYER M5 ;
        RECT  34.704 0 34.728 0.084 ;
    END
  END u_data[286]
  PIN u_data[287]
    DIRECTION INPUT ;
    USE SIGNAL ;
    PORT
      LAYER M5 ;
        RECT  34.8 0 34.824 0.084 ;
    END
  END u_data[287]
  PIN u_data[288]
    DIRECTION INPUT ;
    USE SIGNAL ;
    PORT
      LAYER M5 ;
        RECT  34.896 0 34.92 0.084 ;
    END
  END u_data[288]
  PIN u_data[289]
    DIRECTION INPUT ;
    USE SIGNAL ;
    PORT
      LAYER M5 ;
        RECT  34.992 0 35.016 0.084 ;
    END
  END u_data[289]
  PIN u_data[28]
    DIRECTION INPUT ;
    USE SIGNAL ;
    PORT
      LAYER M5 ;
        RECT  22.224 0 22.248 0.084 ;
    END
  END u_data[28]
  PIN u_data[290]
    DIRECTION INPUT ;
    USE SIGNAL ;
    PORT
      LAYER M5 ;
        RECT  35.088 0 35.112 0.084 ;
    END
  END u_data[290]
  PIN u_data[291]
    DIRECTION INPUT ;
    USE SIGNAL ;
    PORT
      LAYER M5 ;
        RECT  35.184 0 35.208 0.084 ;
    END
  END u_data[291]
  PIN u_data[292]
    DIRECTION INPUT ;
    USE SIGNAL ;
    PORT
      LAYER M5 ;
        RECT  29.136 0 29.16 0.084 ;
    END
  END u_data[292]
  PIN u_data[293]
    DIRECTION INPUT ;
    USE SIGNAL ;
    PORT
      LAYER M5 ;
        RECT  29.232 0 29.256 0.084 ;
    END
  END u_data[293]
  PIN u_data[294]
    DIRECTION INPUT ;
    USE SIGNAL ;
    PORT
      LAYER M5 ;
        RECT  29.328 0 29.352 0.084 ;
    END
  END u_data[294]
  PIN u_data[295]
    DIRECTION INPUT ;
    USE SIGNAL ;
    PORT
      LAYER M5 ;
        RECT  29.424 0 29.448 0.084 ;
    END
  END u_data[295]
  PIN u_data[296]
    DIRECTION INPUT ;
    USE SIGNAL ;
    PORT
      LAYER M5 ;
        RECT  29.52 0 29.544 0.084 ;
    END
  END u_data[296]
  PIN u_data[297]
    DIRECTION INPUT ;
    USE SIGNAL ;
    PORT
      LAYER M5 ;
        RECT  29.616 0 29.64 0.084 ;
    END
  END u_data[297]
  PIN u_data[298]
    DIRECTION INPUT ;
    USE SIGNAL ;
    PORT
      LAYER M5 ;
        RECT  29.712 0 29.736 0.084 ;
    END
  END u_data[298]
  PIN u_data[299]
    DIRECTION INPUT ;
    USE SIGNAL ;
    PORT
      LAYER M5 ;
        RECT  29.808 0 29.832 0.084 ;
    END
  END u_data[299]
  PIN u_data[29]
    DIRECTION INPUT ;
    USE SIGNAL ;
    PORT
      LAYER M5 ;
        RECT  22.32 0 22.344 0.084 ;
    END
  END u_data[29]
  PIN u_data[2]
    DIRECTION INPUT ;
    USE SIGNAL ;
    PORT
      LAYER M3 ;
        RECT  19.404 0 19.422 0.037 ;
    END
  END u_data[2]
  PIN u_data[300]
    DIRECTION INPUT ;
    USE SIGNAL ;
    PORT
      LAYER M5 ;
        RECT  29.904 0 29.928 0.084 ;
    END
  END u_data[300]
  PIN u_data[301]
    DIRECTION INPUT ;
    USE SIGNAL ;
    PORT
      LAYER M5 ;
        RECT  30 0 30.024 0.084 ;
    END
  END u_data[301]
  PIN u_data[302]
    DIRECTION INPUT ;
    USE SIGNAL ;
    PORT
      LAYER M5 ;
        RECT  30.096 0 30.12 0.084 ;
    END
  END u_data[302]
  PIN u_data[303]
    DIRECTION INPUT ;
    USE SIGNAL ;
    PORT
      LAYER M5 ;
        RECT  30.192 0 30.216 0.084 ;
    END
  END u_data[303]
  PIN u_data[304]
    DIRECTION INPUT ;
    USE SIGNAL ;
    PORT
      LAYER M5 ;
        RECT  30.288 0 30.312 0.084 ;
    END
  END u_data[304]
  PIN u_data[305]
    DIRECTION INPUT ;
    USE SIGNAL ;
    PORT
      LAYER M5 ;
        RECT  30.384 0 30.408 0.084 ;
    END
  END u_data[305]
  PIN u_data[306]
    DIRECTION INPUT ;
    USE SIGNAL ;
    PORT
      LAYER M5 ;
        RECT  30.48 0 30.504 0.084 ;
    END
  END u_data[306]
  PIN u_data[307]
    DIRECTION INPUT ;
    USE SIGNAL ;
    PORT
      LAYER M5 ;
        RECT  30.576 0 30.6 0.084 ;
    END
  END u_data[307]
  PIN u_data[308]
    DIRECTION INPUT ;
    USE SIGNAL ;
    PORT
      LAYER M5 ;
        RECT  30.672 0 30.696 0.084 ;
    END
  END u_data[308]
  PIN u_data[309]
    DIRECTION INPUT ;
    USE SIGNAL ;
    PORT
      LAYER M5 ;
        RECT  30.768 0 30.792 0.084 ;
    END
  END u_data[309]
  PIN u_data[30]
    DIRECTION INPUT ;
    USE SIGNAL ;
    PORT
      LAYER M5 ;
        RECT  22.416 0 22.44 0.084 ;
    END
  END u_data[30]
  PIN u_data[310]
    DIRECTION INPUT ;
    USE SIGNAL ;
    PORT
      LAYER M5 ;
        RECT  30.864 0 30.888 0.084 ;
    END
  END u_data[310]
  PIN u_data[311]
    DIRECTION INPUT ;
    USE SIGNAL ;
    PORT
      LAYER M5 ;
        RECT  30.96 0 30.984 0.084 ;
    END
  END u_data[311]
  PIN u_data[312]
    DIRECTION INPUT ;
    USE SIGNAL ;
    PORT
      LAYER M5 ;
        RECT  31.056 0 31.08 0.084 ;
    END
  END u_data[312]
  PIN u_data[313]
    DIRECTION INPUT ;
    USE SIGNAL ;
    PORT
      LAYER M5 ;
        RECT  31.152 0 31.176 0.084 ;
    END
  END u_data[313]
  PIN u_data[314]
    DIRECTION INPUT ;
    USE SIGNAL ;
    PORT
      LAYER M5 ;
        RECT  31.248 0 31.272 0.084 ;
    END
  END u_data[314]
  PIN u_data[315]
    DIRECTION INPUT ;
    USE SIGNAL ;
    PORT
      LAYER M5 ;
        RECT  31.344 0 31.368 0.084 ;
    END
  END u_data[315]
  PIN u_data[316]
    DIRECTION INPUT ;
    USE SIGNAL ;
    PORT
      LAYER M5 ;
        RECT  31.44 0 31.464 0.084 ;
    END
  END u_data[316]
  PIN u_data[317]
    DIRECTION INPUT ;
    USE SIGNAL ;
    PORT
      LAYER M5 ;
        RECT  31.536 0 31.56 0.084 ;
    END
  END u_data[317]
  PIN u_data[318]
    DIRECTION INPUT ;
    USE SIGNAL ;
    PORT
      LAYER M5 ;
        RECT  31.632 0 31.656 0.084 ;
    END
  END u_data[318]
  PIN u_data[319]
    DIRECTION INPUT ;
    USE SIGNAL ;
    PORT
      LAYER M5 ;
        RECT  31.728 0 31.752 0.084 ;
    END
  END u_data[319]
  PIN u_data[31]
    DIRECTION INPUT ;
    USE SIGNAL ;
    PORT
      LAYER M5 ;
        RECT  22.512 0 22.536 0.084 ;
    END
  END u_data[31]
  PIN u_data[320]
    DIRECTION INPUT ;
    USE SIGNAL ;
    PORT
      LAYER M5 ;
        RECT  31.824 0 31.848 0.084 ;
    END
  END u_data[320]
  PIN u_data[321]
    DIRECTION INPUT ;
    USE SIGNAL ;
    PORT
      LAYER M5 ;
        RECT  31.92 0 31.944 0.084 ;
    END
  END u_data[321]
  PIN u_data[322]
    DIRECTION INPUT ;
    USE SIGNAL ;
    PORT
      LAYER M5 ;
        RECT  32.016 0 32.04 0.084 ;
    END
  END u_data[322]
  PIN u_data[323]
    DIRECTION INPUT ;
    USE SIGNAL ;
    PORT
      LAYER M5 ;
        RECT  32.112 0 32.136 0.084 ;
    END
  END u_data[323]
  PIN u_data[324]
    DIRECTION INPUT ;
    USE SIGNAL ;
    PORT
      LAYER M3 ;
        RECT  33.948 0 33.966 0.037 ;
    END
  END u_data[324]
  PIN u_data[325]
    DIRECTION INPUT ;
    USE SIGNAL ;
    PORT
      LAYER M3 ;
        RECT  34.02 0 34.038 0.037 ;
    END
  END u_data[325]
  PIN u_data[326]
    DIRECTION INPUT ;
    USE SIGNAL ;
    PORT
      LAYER M3 ;
        RECT  34.092 0 34.11 0.037 ;
    END
  END u_data[326]
  PIN u_data[327]
    DIRECTION INPUT ;
    USE SIGNAL ;
    PORT
      LAYER M3 ;
        RECT  34.164 0 34.182 0.037 ;
    END
  END u_data[327]
  PIN u_data[328]
    DIRECTION INPUT ;
    USE SIGNAL ;
    PORT
      LAYER M3 ;
        RECT  34.236 0 34.254 0.037 ;
    END
  END u_data[328]
  PIN u_data[329]
    DIRECTION INPUT ;
    USE SIGNAL ;
    PORT
      LAYER M3 ;
        RECT  34.308 0 34.326 0.037 ;
    END
  END u_data[329]
  PIN u_data[32]
    DIRECTION INPUT ;
    USE SIGNAL ;
    PORT
      LAYER M5 ;
        RECT  22.608 0 22.632 0.084 ;
    END
  END u_data[32]
  PIN u_data[330]
    DIRECTION INPUT ;
    USE SIGNAL ;
    PORT
      LAYER M3 ;
        RECT  34.38 0 34.398 0.037 ;
    END
  END u_data[330]
  PIN u_data[331]
    DIRECTION INPUT ;
    USE SIGNAL ;
    PORT
      LAYER M3 ;
        RECT  34.452 0 34.47 0.037 ;
    END
  END u_data[331]
  PIN u_data[332]
    DIRECTION INPUT ;
    USE SIGNAL ;
    PORT
      LAYER M3 ;
        RECT  34.524 0 34.542 0.037 ;
    END
  END u_data[332]
  PIN u_data[333]
    DIRECTION INPUT ;
    USE SIGNAL ;
    PORT
      LAYER M3 ;
        RECT  34.596 0 34.614 0.037 ;
    END
  END u_data[333]
  PIN u_data[334]
    DIRECTION INPUT ;
    USE SIGNAL ;
    PORT
      LAYER M3 ;
        RECT  34.668 0 34.686 0.037 ;
    END
  END u_data[334]
  PIN u_data[335]
    DIRECTION INPUT ;
    USE SIGNAL ;
    PORT
      LAYER M3 ;
        RECT  34.74 0 34.758 0.037 ;
    END
  END u_data[335]
  PIN u_data[336]
    DIRECTION INPUT ;
    USE SIGNAL ;
    PORT
      LAYER M3 ;
        RECT  34.812 0 34.83 0.037 ;
    END
  END u_data[336]
  PIN u_data[337]
    DIRECTION INPUT ;
    USE SIGNAL ;
    PORT
      LAYER M3 ;
        RECT  34.884 0 34.902 0.037 ;
    END
  END u_data[337]
  PIN u_data[338]
    DIRECTION INPUT ;
    USE SIGNAL ;
    PORT
      LAYER M3 ;
        RECT  34.956 0 34.974 0.037 ;
    END
  END u_data[338]
  PIN u_data[339]
    DIRECTION INPUT ;
    USE SIGNAL ;
    PORT
      LAYER M3 ;
        RECT  35.028 0 35.046 0.037 ;
    END
  END u_data[339]
  PIN u_data[33]
    DIRECTION INPUT ;
    USE SIGNAL ;
    PORT
      LAYER M5 ;
        RECT  22.704 0 22.728 0.084 ;
    END
  END u_data[33]
  PIN u_data[340]
    DIRECTION INPUT ;
    USE SIGNAL ;
    PORT
      LAYER M3 ;
        RECT  35.1 0 35.118 0.037 ;
    END
  END u_data[340]
  PIN u_data[341]
    DIRECTION INPUT ;
    USE SIGNAL ;
    PORT
      LAYER M3 ;
        RECT  35.172 0 35.19 0.037 ;
    END
  END u_data[341]
  PIN u_data[342]
    DIRECTION INPUT ;
    USE SIGNAL ;
    PORT
      LAYER M3 ;
        RECT  35.244 0 35.262 0.037 ;
    END
  END u_data[342]
  PIN u_data[343]
    DIRECTION INPUT ;
    USE SIGNAL ;
    PORT
      LAYER M3 ;
        RECT  35.316 0 35.334 0.037 ;
    END
  END u_data[343]
  PIN u_data[344]
    DIRECTION INPUT ;
    USE SIGNAL ;
    PORT
      LAYER M3 ;
        RECT  35.388 0 35.406 0.037 ;
    END
  END u_data[344]
  PIN u_data[345]
    DIRECTION INPUT ;
    USE SIGNAL ;
    PORT
      LAYER M3 ;
        RECT  35.46 0 35.478 0.037 ;
    END
  END u_data[345]
  PIN u_data[346]
    DIRECTION INPUT ;
    USE SIGNAL ;
    PORT
      LAYER M3 ;
        RECT  35.532 0 35.55 0.037 ;
    END
  END u_data[346]
  PIN u_data[347]
    DIRECTION INPUT ;
    USE SIGNAL ;
    PORT
      LAYER M3 ;
        RECT  35.604 0 35.622 0.037 ;
    END
  END u_data[347]
  PIN u_data[348]
    DIRECTION INPUT ;
    USE SIGNAL ;
    PORT
      LAYER M3 ;
        RECT  35.676 0 35.694 0.037 ;
    END
  END u_data[348]
  PIN u_data[349]
    DIRECTION INPUT ;
    USE SIGNAL ;
    PORT
      LAYER M3 ;
        RECT  35.748 0 35.766 0.037 ;
    END
  END u_data[349]
  PIN u_data[34]
    DIRECTION INPUT ;
    USE SIGNAL ;
    PORT
      LAYER M5 ;
        RECT  22.8 0 22.824 0.084 ;
    END
  END u_data[34]
  PIN u_data[350]
    DIRECTION INPUT ;
    USE SIGNAL ;
    PORT
      LAYER M3 ;
        RECT  35.82 0 35.838 0.037 ;
    END
  END u_data[350]
  PIN u_data[351]
    DIRECTION INPUT ;
    USE SIGNAL ;
    PORT
      LAYER M3 ;
        RECT  35.892 0 35.91 0.037 ;
    END
  END u_data[351]
  PIN u_data[352]
    DIRECTION INPUT ;
    USE SIGNAL ;
    PORT
      LAYER M3 ;
        RECT  35.964 0 35.982 0.037 ;
    END
  END u_data[352]
  PIN u_data[353]
    DIRECTION INPUT ;
    USE SIGNAL ;
    PORT
      LAYER M3 ;
        RECT  36.036 0 36.054 0.037 ;
    END
  END u_data[353]
  PIN u_data[354]
    DIRECTION INPUT ;
    USE SIGNAL ;
    PORT
      LAYER M3 ;
        RECT  36.108 0 36.126 0.037 ;
    END
  END u_data[354]
  PIN u_data[355]
    DIRECTION INPUT ;
    USE SIGNAL ;
    PORT
      LAYER M3 ;
        RECT  36.18 0 36.198 0.037 ;
    END
  END u_data[355]
  PIN u_data[356]
    DIRECTION INPUT ;
    USE SIGNAL ;
    PORT
      LAYER M3 ;
        RECT  38.556 0 38.574 0.037 ;
    END
  END u_data[356]
  PIN u_data[357]
    DIRECTION INPUT ;
    USE SIGNAL ;
    PORT
      LAYER M3 ;
        RECT  38.628 0 38.646 0.037 ;
    END
  END u_data[357]
  PIN u_data[358]
    DIRECTION INPUT ;
    USE SIGNAL ;
    PORT
      LAYER M3 ;
        RECT  38.7 0 38.718 0.037 ;
    END
  END u_data[358]
  PIN u_data[359]
    DIRECTION INPUT ;
    USE SIGNAL ;
    PORT
      LAYER M3 ;
        RECT  38.772 0 38.79 0.037 ;
    END
  END u_data[359]
  PIN u_data[35]
    DIRECTION INPUT ;
    USE SIGNAL ;
    PORT
      LAYER M5 ;
        RECT  22.896 0 22.92 0.084 ;
    END
  END u_data[35]
  PIN u_data[360]
    DIRECTION INPUT ;
    USE SIGNAL ;
    PORT
      LAYER M3 ;
        RECT  38.844 0 38.862 0.037 ;
    END
  END u_data[360]
  PIN u_data[361]
    DIRECTION INPUT ;
    USE SIGNAL ;
    PORT
      LAYER M3 ;
        RECT  38.916 0 38.934 0.037 ;
    END
  END u_data[361]
  PIN u_data[362]
    DIRECTION INPUT ;
    USE SIGNAL ;
    PORT
      LAYER M3 ;
        RECT  38.988 0 39.006 0.037 ;
    END
  END u_data[362]
  PIN u_data[363]
    DIRECTION INPUT ;
    USE SIGNAL ;
    PORT
      LAYER M3 ;
        RECT  39.06 0 39.078 0.037 ;
    END
  END u_data[363]
  PIN u_data[364]
    DIRECTION INPUT ;
    USE SIGNAL ;
    PORT
      LAYER M3 ;
        RECT  39.132 0 39.15 0.037 ;
    END
  END u_data[364]
  PIN u_data[365]
    DIRECTION INPUT ;
    USE SIGNAL ;
    PORT
      LAYER M3 ;
        RECT  39.204 0 39.222 0.037 ;
    END
  END u_data[365]
  PIN u_data[366]
    DIRECTION INPUT ;
    USE SIGNAL ;
    PORT
      LAYER M3 ;
        RECT  39.276 0 39.294 0.037 ;
    END
  END u_data[366]
  PIN u_data[367]
    DIRECTION INPUT ;
    USE SIGNAL ;
    PORT
      LAYER M3 ;
        RECT  39.348 0 39.366 0.037 ;
    END
  END u_data[367]
  PIN u_data[368]
    DIRECTION INPUT ;
    USE SIGNAL ;
    PORT
      LAYER M3 ;
        RECT  39.42 0 39.438 0.037 ;
    END
  END u_data[368]
  PIN u_data[369]
    DIRECTION INPUT ;
    USE SIGNAL ;
    PORT
      LAYER M3 ;
        RECT  39.492 0 39.51 0.037 ;
    END
  END u_data[369]
  PIN u_data[36]
    DIRECTION INPUT ;
    USE SIGNAL ;
    PORT
      LAYER M3 ;
        RECT  24.156 0 24.174 0.037 ;
    END
  END u_data[36]
  PIN u_data[370]
    DIRECTION INPUT ;
    USE SIGNAL ;
    PORT
      LAYER M3 ;
        RECT  39.564 0 39.582 0.037 ;
    END
  END u_data[370]
  PIN u_data[371]
    DIRECTION INPUT ;
    USE SIGNAL ;
    PORT
      LAYER M3 ;
        RECT  39.636 0 39.654 0.037 ;
    END
  END u_data[371]
  PIN u_data[372]
    DIRECTION INPUT ;
    USE SIGNAL ;
    PORT
      LAYER M3 ;
        RECT  39.708 0 39.726 0.037 ;
    END
  END u_data[372]
  PIN u_data[373]
    DIRECTION INPUT ;
    USE SIGNAL ;
    PORT
      LAYER M3 ;
        RECT  39.78 0 39.798 0.037 ;
    END
  END u_data[373]
  PIN u_data[374]
    DIRECTION INPUT ;
    USE SIGNAL ;
    PORT
      LAYER M3 ;
        RECT  39.852 0 39.87 0.037 ;
    END
  END u_data[374]
  PIN u_data[375]
    DIRECTION INPUT ;
    USE SIGNAL ;
    PORT
      LAYER M3 ;
        RECT  39.924 0 39.942 0.037 ;
    END
  END u_data[375]
  PIN u_data[376]
    DIRECTION INPUT ;
    USE SIGNAL ;
    PORT
      LAYER M3 ;
        RECT  39.996 0 40.014 0.037 ;
    END
  END u_data[376]
  PIN u_data[377]
    DIRECTION INPUT ;
    USE SIGNAL ;
    PORT
      LAYER M3 ;
        RECT  40.068 0 40.086 0.037 ;
    END
  END u_data[377]
  PIN u_data[378]
    DIRECTION INPUT ;
    USE SIGNAL ;
    PORT
      LAYER M3 ;
        RECT  40.14 0 40.158 0.037 ;
    END
  END u_data[378]
  PIN u_data[379]
    DIRECTION INPUT ;
    USE SIGNAL ;
    PORT
      LAYER M3 ;
        RECT  40.212 0 40.23 0.037 ;
    END
  END u_data[379]
  PIN u_data[37]
    DIRECTION INPUT ;
    USE SIGNAL ;
    PORT
      LAYER M3 ;
        RECT  24.228 0 24.246 0.037 ;
    END
  END u_data[37]
  PIN u_data[380]
    DIRECTION INPUT ;
    USE SIGNAL ;
    PORT
      LAYER M3 ;
        RECT  40.284 0 40.302 0.037 ;
    END
  END u_data[380]
  PIN u_data[381]
    DIRECTION INPUT ;
    USE SIGNAL ;
    PORT
      LAYER M3 ;
        RECT  40.356 0 40.374 0.037 ;
    END
  END u_data[381]
  PIN u_data[382]
    DIRECTION INPUT ;
    USE SIGNAL ;
    PORT
      LAYER M3 ;
        RECT  40.428 0 40.446 0.037 ;
    END
  END u_data[382]
  PIN u_data[383]
    DIRECTION INPUT ;
    USE SIGNAL ;
    PORT
      LAYER M3 ;
        RECT  40.5 0 40.518 0.037 ;
    END
  END u_data[383]
  PIN u_data[384]
    DIRECTION INPUT ;
    USE SIGNAL ;
    PORT
      LAYER M3 ;
        RECT  40.572 0 40.59 0.037 ;
    END
  END u_data[384]
  PIN u_data[385]
    DIRECTION INPUT ;
    USE SIGNAL ;
    PORT
      LAYER M3 ;
        RECT  40.644 0 40.662 0.037 ;
    END
  END u_data[385]
  PIN u_data[386]
    DIRECTION INPUT ;
    USE SIGNAL ;
    PORT
      LAYER M3 ;
        RECT  40.716 0 40.734 0.037 ;
    END
  END u_data[386]
  PIN u_data[387]
    DIRECTION INPUT ;
    USE SIGNAL ;
    PORT
      LAYER M3 ;
        RECT  40.788 0 40.806 0.037 ;
    END
  END u_data[387]
  PIN u_data[388]
    DIRECTION INPUT ;
    USE SIGNAL ;
    PORT
      LAYER M3 ;
        RECT  36.252 0 36.27 0.037 ;
    END
  END u_data[388]
  PIN u_data[389]
    DIRECTION INPUT ;
    USE SIGNAL ;
    PORT
      LAYER M3 ;
        RECT  36.324 0 36.342 0.037 ;
    END
  END u_data[389]
  PIN u_data[38]
    DIRECTION INPUT ;
    USE SIGNAL ;
    PORT
      LAYER M3 ;
        RECT  24.3 0 24.318 0.037 ;
    END
  END u_data[38]
  PIN u_data[390]
    DIRECTION INPUT ;
    USE SIGNAL ;
    PORT
      LAYER M3 ;
        RECT  36.396 0 36.414 0.037 ;
    END
  END u_data[390]
  PIN u_data[391]
    DIRECTION INPUT ;
    USE SIGNAL ;
    PORT
      LAYER M3 ;
        RECT  36.468 0 36.486 0.037 ;
    END
  END u_data[391]
  PIN u_data[392]
    DIRECTION INPUT ;
    USE SIGNAL ;
    PORT
      LAYER M3 ;
        RECT  36.54 0 36.558 0.037 ;
    END
  END u_data[392]
  PIN u_data[393]
    DIRECTION INPUT ;
    USE SIGNAL ;
    PORT
      LAYER M3 ;
        RECT  36.612 0 36.63 0.037 ;
    END
  END u_data[393]
  PIN u_data[394]
    DIRECTION INPUT ;
    USE SIGNAL ;
    PORT
      LAYER M3 ;
        RECT  36.684 0 36.702 0.037 ;
    END
  END u_data[394]
  PIN u_data[395]
    DIRECTION INPUT ;
    USE SIGNAL ;
    PORT
      LAYER M3 ;
        RECT  36.756 0 36.774 0.037 ;
    END
  END u_data[395]
  PIN u_data[396]
    DIRECTION INPUT ;
    USE SIGNAL ;
    PORT
      LAYER M3 ;
        RECT  36.828 0 36.846 0.037 ;
    END
  END u_data[396]
  PIN u_data[397]
    DIRECTION INPUT ;
    USE SIGNAL ;
    PORT
      LAYER M3 ;
        RECT  36.9 0 36.918 0.037 ;
    END
  END u_data[397]
  PIN u_data[398]
    DIRECTION INPUT ;
    USE SIGNAL ;
    PORT
      LAYER M3 ;
        RECT  36.972 0 36.99 0.037 ;
    END
  END u_data[398]
  PIN u_data[399]
    DIRECTION INPUT ;
    USE SIGNAL ;
    PORT
      LAYER M3 ;
        RECT  37.044 0 37.062 0.037 ;
    END
  END u_data[399]
  PIN u_data[39]
    DIRECTION INPUT ;
    USE SIGNAL ;
    PORT
      LAYER M3 ;
        RECT  24.372 0 24.39 0.037 ;
    END
  END u_data[39]
  PIN u_data[3]
    DIRECTION INPUT ;
    USE SIGNAL ;
    PORT
      LAYER M3 ;
        RECT  19.476 0 19.494 0.037 ;
    END
  END u_data[3]
  PIN u_data[400]
    DIRECTION INPUT ;
    USE SIGNAL ;
    PORT
      LAYER M3 ;
        RECT  37.116 0 37.134 0.037 ;
    END
  END u_data[400]
  PIN u_data[401]
    DIRECTION INPUT ;
    USE SIGNAL ;
    PORT
      LAYER M3 ;
        RECT  37.188 0 37.206 0.037 ;
    END
  END u_data[401]
  PIN u_data[402]
    DIRECTION INPUT ;
    USE SIGNAL ;
    PORT
      LAYER M3 ;
        RECT  37.26 0 37.278 0.037 ;
    END
  END u_data[402]
  PIN u_data[403]
    DIRECTION INPUT ;
    USE SIGNAL ;
    PORT
      LAYER M3 ;
        RECT  37.332 0 37.35 0.037 ;
    END
  END u_data[403]
  PIN u_data[404]
    DIRECTION INPUT ;
    USE SIGNAL ;
    PORT
      LAYER M3 ;
        RECT  37.404 0 37.422 0.037 ;
    END
  END u_data[404]
  PIN u_data[405]
    DIRECTION INPUT ;
    USE SIGNAL ;
    PORT
      LAYER M3 ;
        RECT  37.476 0 37.494 0.037 ;
    END
  END u_data[405]
  PIN u_data[406]
    DIRECTION INPUT ;
    USE SIGNAL ;
    PORT
      LAYER M3 ;
        RECT  37.548 0 37.566 0.037 ;
    END
  END u_data[406]
  PIN u_data[407]
    DIRECTION INPUT ;
    USE SIGNAL ;
    PORT
      LAYER M3 ;
        RECT  37.62 0 37.638 0.037 ;
    END
  END u_data[407]
  PIN u_data[408]
    DIRECTION INPUT ;
    USE SIGNAL ;
    PORT
      LAYER M3 ;
        RECT  37.692 0 37.71 0.037 ;
    END
  END u_data[408]
  PIN u_data[409]
    DIRECTION INPUT ;
    USE SIGNAL ;
    PORT
      LAYER M3 ;
        RECT  37.764 0 37.782 0.037 ;
    END
  END u_data[409]
  PIN u_data[40]
    DIRECTION INPUT ;
    USE SIGNAL ;
    PORT
      LAYER M3 ;
        RECT  24.444 0 24.462 0.037 ;
    END
  END u_data[40]
  PIN u_data[410]
    DIRECTION INPUT ;
    USE SIGNAL ;
    PORT
      LAYER M3 ;
        RECT  37.836 0 37.854 0.037 ;
    END
  END u_data[410]
  PIN u_data[411]
    DIRECTION INPUT ;
    USE SIGNAL ;
    PORT
      LAYER M3 ;
        RECT  37.908 0 37.926 0.037 ;
    END
  END u_data[411]
  PIN u_data[412]
    DIRECTION INPUT ;
    USE SIGNAL ;
    PORT
      LAYER M3 ;
        RECT  37.98 0 37.998 0.037 ;
    END
  END u_data[412]
  PIN u_data[413]
    DIRECTION INPUT ;
    USE SIGNAL ;
    PORT
      LAYER M3 ;
        RECT  38.052 0 38.07 0.037 ;
    END
  END u_data[413]
  PIN u_data[414]
    DIRECTION INPUT ;
    USE SIGNAL ;
    PORT
      LAYER M3 ;
        RECT  38.124 0 38.142 0.037 ;
    END
  END u_data[414]
  PIN u_data[415]
    DIRECTION INPUT ;
    USE SIGNAL ;
    PORT
      LAYER M3 ;
        RECT  38.196 0 38.214 0.037 ;
    END
  END u_data[415]
  PIN u_data[416]
    DIRECTION INPUT ;
    USE SIGNAL ;
    PORT
      LAYER M3 ;
        RECT  38.268 0 38.286 0.037 ;
    END
  END u_data[416]
  PIN u_data[417]
    DIRECTION INPUT ;
    USE SIGNAL ;
    PORT
      LAYER M3 ;
        RECT  38.34 0 38.358 0.037 ;
    END
  END u_data[417]
  PIN u_data[418]
    DIRECTION INPUT ;
    USE SIGNAL ;
    PORT
      LAYER M3 ;
        RECT  38.412 0 38.43 0.037 ;
    END
  END u_data[418]
  PIN u_data[419]
    DIRECTION INPUT ;
    USE SIGNAL ;
    PORT
      LAYER M3 ;
        RECT  38.484 0 38.502 0.037 ;
    END
  END u_data[419]
  PIN u_data[41]
    DIRECTION INPUT ;
    USE SIGNAL ;
    PORT
      LAYER M3 ;
        RECT  24.516 0 24.534 0.037 ;
    END
  END u_data[41]
  PIN u_data[420]
    DIRECTION INPUT ;
    USE SIGNAL ;
    PORT
      LAYER M5 ;
        RECT  35.28 0 35.304 0.084 ;
    END
  END u_data[420]
  PIN u_data[421]
    DIRECTION INPUT ;
    USE SIGNAL ;
    PORT
      LAYER M5 ;
        RECT  35.376 0 35.4 0.084 ;
    END
  END u_data[421]
  PIN u_data[422]
    DIRECTION INPUT ;
    USE SIGNAL ;
    PORT
      LAYER M5 ;
        RECT  35.472 0 35.496 0.084 ;
    END
  END u_data[422]
  PIN u_data[423]
    DIRECTION INPUT ;
    USE SIGNAL ;
    PORT
      LAYER M5 ;
        RECT  35.568 0 35.592 0.084 ;
    END
  END u_data[423]
  PIN u_data[424]
    DIRECTION INPUT ;
    USE SIGNAL ;
    PORT
      LAYER M5 ;
        RECT  35.664 0 35.688 0.084 ;
    END
  END u_data[424]
  PIN u_data[425]
    DIRECTION INPUT ;
    USE SIGNAL ;
    PORT
      LAYER M5 ;
        RECT  35.76 0 35.784 0.084 ;
    END
  END u_data[425]
  PIN u_data[426]
    DIRECTION INPUT ;
    USE SIGNAL ;
    PORT
      LAYER M5 ;
        RECT  35.856 0 35.88 0.084 ;
    END
  END u_data[426]
  PIN u_data[427]
    DIRECTION INPUT ;
    USE SIGNAL ;
    PORT
      LAYER M5 ;
        RECT  35.952 0 35.976 0.084 ;
    END
  END u_data[427]
  PIN u_data[428]
    DIRECTION INPUT ;
    USE SIGNAL ;
    PORT
      LAYER M5 ;
        RECT  36.048 0 36.072 0.084 ;
    END
  END u_data[428]
  PIN u_data[429]
    DIRECTION INPUT ;
    USE SIGNAL ;
    PORT
      LAYER M5 ;
        RECT  36.144 0 36.168 0.084 ;
    END
  END u_data[429]
  PIN u_data[42]
    DIRECTION INPUT ;
    USE SIGNAL ;
    PORT
      LAYER M3 ;
        RECT  24.588 0 24.606 0.037 ;
    END
  END u_data[42]
  PIN u_data[430]
    DIRECTION INPUT ;
    USE SIGNAL ;
    PORT
      LAYER M5 ;
        RECT  36.24 0 36.264 0.084 ;
    END
  END u_data[430]
  PIN u_data[431]
    DIRECTION INPUT ;
    USE SIGNAL ;
    PORT
      LAYER M5 ;
        RECT  36.336 0 36.36 0.084 ;
    END
  END u_data[431]
  PIN u_data[432]
    DIRECTION INPUT ;
    USE SIGNAL ;
    PORT
      LAYER M5 ;
        RECT  36.432 0 36.456 0.084 ;
    END
  END u_data[432]
  PIN u_data[433]
    DIRECTION INPUT ;
    USE SIGNAL ;
    PORT
      LAYER M5 ;
        RECT  36.528 0 36.552 0.084 ;
    END
  END u_data[433]
  PIN u_data[434]
    DIRECTION INPUT ;
    USE SIGNAL ;
    PORT
      LAYER M5 ;
        RECT  36.624 0 36.648 0.084 ;
    END
  END u_data[434]
  PIN u_data[435]
    DIRECTION INPUT ;
    USE SIGNAL ;
    PORT
      LAYER M5 ;
        RECT  36.72 0 36.744 0.084 ;
    END
  END u_data[435]
  PIN u_data[436]
    DIRECTION INPUT ;
    USE SIGNAL ;
    PORT
      LAYER M5 ;
        RECT  36.816 0 36.84 0.084 ;
    END
  END u_data[436]
  PIN u_data[437]
    DIRECTION INPUT ;
    USE SIGNAL ;
    PORT
      LAYER M5 ;
        RECT  36.912 0 36.936 0.084 ;
    END
  END u_data[437]
  PIN u_data[438]
    DIRECTION INPUT ;
    USE SIGNAL ;
    PORT
      LAYER M5 ;
        RECT  37.008 0 37.032 0.084 ;
    END
  END u_data[438]
  PIN u_data[439]
    DIRECTION INPUT ;
    USE SIGNAL ;
    PORT
      LAYER M5 ;
        RECT  37.104 0 37.128 0.084 ;
    END
  END u_data[439]
  PIN u_data[43]
    DIRECTION INPUT ;
    USE SIGNAL ;
    PORT
      LAYER M3 ;
        RECT  24.66 0 24.678 0.037 ;
    END
  END u_data[43]
  PIN u_data[440]
    DIRECTION INPUT ;
    USE SIGNAL ;
    PORT
      LAYER M5 ;
        RECT  37.2 0 37.224 0.084 ;
    END
  END u_data[440]
  PIN u_data[441]
    DIRECTION INPUT ;
    USE SIGNAL ;
    PORT
      LAYER M5 ;
        RECT  37.296 0 37.32 0.084 ;
    END
  END u_data[441]
  PIN u_data[442]
    DIRECTION INPUT ;
    USE SIGNAL ;
    PORT
      LAYER M5 ;
        RECT  37.392 0 37.416 0.084 ;
    END
  END u_data[442]
  PIN u_data[443]
    DIRECTION INPUT ;
    USE SIGNAL ;
    PORT
      LAYER M5 ;
        RECT  37.488 0 37.512 0.084 ;
    END
  END u_data[443]
  PIN u_data[444]
    DIRECTION INPUT ;
    USE SIGNAL ;
    PORT
      LAYER M5 ;
        RECT  37.584 0 37.608 0.084 ;
    END
  END u_data[444]
  PIN u_data[445]
    DIRECTION INPUT ;
    USE SIGNAL ;
    PORT
      LAYER M5 ;
        RECT  37.68 0 37.704 0.084 ;
    END
  END u_data[445]
  PIN u_data[446]
    DIRECTION INPUT ;
    USE SIGNAL ;
    PORT
      LAYER M5 ;
        RECT  37.776 0 37.8 0.084 ;
    END
  END u_data[446]
  PIN u_data[447]
    DIRECTION INPUT ;
    USE SIGNAL ;
    PORT
      LAYER M5 ;
        RECT  37.872 0 37.896 0.084 ;
    END
  END u_data[447]
  PIN u_data[448]
    DIRECTION INPUT ;
    USE SIGNAL ;
    PORT
      LAYER M5 ;
        RECT  37.968 0 37.992 0.084 ;
    END
  END u_data[448]
  PIN u_data[449]
    DIRECTION INPUT ;
    USE SIGNAL ;
    PORT
      LAYER M5 ;
        RECT  38.064 0 38.088 0.084 ;
    END
  END u_data[449]
  PIN u_data[44]
    DIRECTION INPUT ;
    USE SIGNAL ;
    PORT
      LAYER M3 ;
        RECT  24.732 0 24.75 0.037 ;
    END
  END u_data[44]
  PIN u_data[450]
    DIRECTION INPUT ;
    USE SIGNAL ;
    PORT
      LAYER M5 ;
        RECT  38.16 0 38.184 0.084 ;
    END
  END u_data[450]
  PIN u_data[451]
    DIRECTION INPUT ;
    USE SIGNAL ;
    PORT
      LAYER M5 ;
        RECT  38.256 0 38.28 0.084 ;
    END
  END u_data[451]
  PIN u_data[452]
    DIRECTION INPUT ;
    USE SIGNAL ;
    PORT
      LAYER M3 ;
        RECT  31.644 0 31.662 0.037 ;
    END
  END u_data[452]
  PIN u_data[453]
    DIRECTION INPUT ;
    USE SIGNAL ;
    PORT
      LAYER M3 ;
        RECT  31.716 0 31.734 0.037 ;
    END
  END u_data[453]
  PIN u_data[454]
    DIRECTION INPUT ;
    USE SIGNAL ;
    PORT
      LAYER M3 ;
        RECT  31.788 0 31.806 0.037 ;
    END
  END u_data[454]
  PIN u_data[455]
    DIRECTION INPUT ;
    USE SIGNAL ;
    PORT
      LAYER M3 ;
        RECT  31.86 0 31.878 0.037 ;
    END
  END u_data[455]
  PIN u_data[456]
    DIRECTION INPUT ;
    USE SIGNAL ;
    PORT
      LAYER M3 ;
        RECT  31.932 0 31.95 0.037 ;
    END
  END u_data[456]
  PIN u_data[457]
    DIRECTION INPUT ;
    USE SIGNAL ;
    PORT
      LAYER M3 ;
        RECT  32.004 0 32.022 0.037 ;
    END
  END u_data[457]
  PIN u_data[458]
    DIRECTION INPUT ;
    USE SIGNAL ;
    PORT
      LAYER M3 ;
        RECT  32.076 0 32.094 0.037 ;
    END
  END u_data[458]
  PIN u_data[459]
    DIRECTION INPUT ;
    USE SIGNAL ;
    PORT
      LAYER M3 ;
        RECT  32.148 0 32.166 0.037 ;
    END
  END u_data[459]
  PIN u_data[45]
    DIRECTION INPUT ;
    USE SIGNAL ;
    PORT
      LAYER M3 ;
        RECT  24.804 0 24.822 0.037 ;
    END
  END u_data[45]
  PIN u_data[460]
    DIRECTION INPUT ;
    USE SIGNAL ;
    PORT
      LAYER M3 ;
        RECT  32.22 0 32.238 0.037 ;
    END
  END u_data[460]
  PIN u_data[461]
    DIRECTION INPUT ;
    USE SIGNAL ;
    PORT
      LAYER M3 ;
        RECT  32.292 0 32.31 0.037 ;
    END
  END u_data[461]
  PIN u_data[462]
    DIRECTION INPUT ;
    USE SIGNAL ;
    PORT
      LAYER M3 ;
        RECT  32.364 0 32.382 0.037 ;
    END
  END u_data[462]
  PIN u_data[463]
    DIRECTION INPUT ;
    USE SIGNAL ;
    PORT
      LAYER M3 ;
        RECT  32.436 0 32.454 0.037 ;
    END
  END u_data[463]
  PIN u_data[464]
    DIRECTION INPUT ;
    USE SIGNAL ;
    PORT
      LAYER M3 ;
        RECT  32.508 0 32.526 0.037 ;
    END
  END u_data[464]
  PIN u_data[465]
    DIRECTION INPUT ;
    USE SIGNAL ;
    PORT
      LAYER M3 ;
        RECT  32.58 0 32.598 0.037 ;
    END
  END u_data[465]
  PIN u_data[466]
    DIRECTION INPUT ;
    USE SIGNAL ;
    PORT
      LAYER M3 ;
        RECT  32.652 0 32.67 0.037 ;
    END
  END u_data[466]
  PIN u_data[467]
    DIRECTION INPUT ;
    USE SIGNAL ;
    PORT
      LAYER M3 ;
        RECT  32.724 0 32.742 0.037 ;
    END
  END u_data[467]
  PIN u_data[468]
    DIRECTION INPUT ;
    USE SIGNAL ;
    PORT
      LAYER M3 ;
        RECT  32.796 0 32.814 0.037 ;
    END
  END u_data[468]
  PIN u_data[469]
    DIRECTION INPUT ;
    USE SIGNAL ;
    PORT
      LAYER M3 ;
        RECT  32.868 0 32.886 0.037 ;
    END
  END u_data[469]
  PIN u_data[46]
    DIRECTION INPUT ;
    USE SIGNAL ;
    PORT
      LAYER M3 ;
        RECT  24.876 0 24.894 0.037 ;
    END
  END u_data[46]
  PIN u_data[470]
    DIRECTION INPUT ;
    USE SIGNAL ;
    PORT
      LAYER M3 ;
        RECT  32.94 0 32.958 0.037 ;
    END
  END u_data[470]
  PIN u_data[471]
    DIRECTION INPUT ;
    USE SIGNAL ;
    PORT
      LAYER M3 ;
        RECT  33.012 0 33.03 0.037 ;
    END
  END u_data[471]
  PIN u_data[472]
    DIRECTION INPUT ;
    USE SIGNAL ;
    PORT
      LAYER M3 ;
        RECT  33.084 0 33.102 0.037 ;
    END
  END u_data[472]
  PIN u_data[473]
    DIRECTION INPUT ;
    USE SIGNAL ;
    PORT
      LAYER M3 ;
        RECT  33.156 0 33.174 0.037 ;
    END
  END u_data[473]
  PIN u_data[474]
    DIRECTION INPUT ;
    USE SIGNAL ;
    PORT
      LAYER M3 ;
        RECT  33.228 0 33.246 0.037 ;
    END
  END u_data[474]
  PIN u_data[475]
    DIRECTION INPUT ;
    USE SIGNAL ;
    PORT
      LAYER M3 ;
        RECT  33.3 0 33.318 0.037 ;
    END
  END u_data[475]
  PIN u_data[476]
    DIRECTION INPUT ;
    USE SIGNAL ;
    PORT
      LAYER M3 ;
        RECT  33.372 0 33.39 0.037 ;
    END
  END u_data[476]
  PIN u_data[477]
    DIRECTION INPUT ;
    USE SIGNAL ;
    PORT
      LAYER M3 ;
        RECT  33.444 0 33.462 0.037 ;
    END
  END u_data[477]
  PIN u_data[478]
    DIRECTION INPUT ;
    USE SIGNAL ;
    PORT
      LAYER M3 ;
        RECT  33.516 0 33.534 0.037 ;
    END
  END u_data[478]
  PIN u_data[479]
    DIRECTION INPUT ;
    USE SIGNAL ;
    PORT
      LAYER M3 ;
        RECT  33.588 0 33.606 0.037 ;
    END
  END u_data[479]
  PIN u_data[47]
    DIRECTION INPUT ;
    USE SIGNAL ;
    PORT
      LAYER M3 ;
        RECT  24.948 0 24.966 0.037 ;
    END
  END u_data[47]
  PIN u_data[480]
    DIRECTION INPUT ;
    USE SIGNAL ;
    PORT
      LAYER M3 ;
        RECT  33.66 0 33.678 0.037 ;
    END
  END u_data[480]
  PIN u_data[481]
    DIRECTION INPUT ;
    USE SIGNAL ;
    PORT
      LAYER M3 ;
        RECT  33.732 0 33.75 0.037 ;
    END
  END u_data[481]
  PIN u_data[482]
    DIRECTION INPUT ;
    USE SIGNAL ;
    PORT
      LAYER M3 ;
        RECT  33.804 0 33.822 0.037 ;
    END
  END u_data[482]
  PIN u_data[483]
    DIRECTION INPUT ;
    USE SIGNAL ;
    PORT
      LAYER M3 ;
        RECT  33.876 0 33.894 0.037 ;
    END
  END u_data[483]
  PIN u_data[484]
    DIRECTION INPUT ;
    USE SIGNAL ;
    PORT
      LAYER M3 ;
        RECT  29.34 0 29.358 0.037 ;
    END
  END u_data[484]
  PIN u_data[485]
    DIRECTION INPUT ;
    USE SIGNAL ;
    PORT
      LAYER M3 ;
        RECT  29.412 0 29.43 0.037 ;
    END
  END u_data[485]
  PIN u_data[486]
    DIRECTION INPUT ;
    USE SIGNAL ;
    PORT
      LAYER M3 ;
        RECT  29.484 0 29.502 0.037 ;
    END
  END u_data[486]
  PIN u_data[487]
    DIRECTION INPUT ;
    USE SIGNAL ;
    PORT
      LAYER M3 ;
        RECT  29.556 0 29.574 0.037 ;
    END
  END u_data[487]
  PIN u_data[488]
    DIRECTION INPUT ;
    USE SIGNAL ;
    PORT
      LAYER M3 ;
        RECT  29.628 0 29.646 0.037 ;
    END
  END u_data[488]
  PIN u_data[489]
    DIRECTION INPUT ;
    USE SIGNAL ;
    PORT
      LAYER M3 ;
        RECT  29.7 0 29.718 0.037 ;
    END
  END u_data[489]
  PIN u_data[48]
    DIRECTION INPUT ;
    USE SIGNAL ;
    PORT
      LAYER M3 ;
        RECT  25.02 0 25.038 0.037 ;
    END
  END u_data[48]
  PIN u_data[490]
    DIRECTION INPUT ;
    USE SIGNAL ;
    PORT
      LAYER M3 ;
        RECT  29.772 0 29.79 0.037 ;
    END
  END u_data[490]
  PIN u_data[491]
    DIRECTION INPUT ;
    USE SIGNAL ;
    PORT
      LAYER M3 ;
        RECT  29.844 0 29.862 0.037 ;
    END
  END u_data[491]
  PIN u_data[492]
    DIRECTION INPUT ;
    USE SIGNAL ;
    PORT
      LAYER M3 ;
        RECT  29.916 0 29.934 0.037 ;
    END
  END u_data[492]
  PIN u_data[493]
    DIRECTION INPUT ;
    USE SIGNAL ;
    PORT
      LAYER M3 ;
        RECT  29.988 0 30.006 0.037 ;
    END
  END u_data[493]
  PIN u_data[494]
    DIRECTION INPUT ;
    USE SIGNAL ;
    PORT
      LAYER M3 ;
        RECT  30.06 0 30.078 0.037 ;
    END
  END u_data[494]
  PIN u_data[495]
    DIRECTION INPUT ;
    USE SIGNAL ;
    PORT
      LAYER M3 ;
        RECT  30.132 0 30.15 0.037 ;
    END
  END u_data[495]
  PIN u_data[496]
    DIRECTION INPUT ;
    USE SIGNAL ;
    PORT
      LAYER M3 ;
        RECT  30.204 0 30.222 0.037 ;
    END
  END u_data[496]
  PIN u_data[497]
    DIRECTION INPUT ;
    USE SIGNAL ;
    PORT
      LAYER M3 ;
        RECT  30.276 0 30.294 0.037 ;
    END
  END u_data[497]
  PIN u_data[498]
    DIRECTION INPUT ;
    USE SIGNAL ;
    PORT
      LAYER M3 ;
        RECT  30.348 0 30.366 0.037 ;
    END
  END u_data[498]
  PIN u_data[499]
    DIRECTION INPUT ;
    USE SIGNAL ;
    PORT
      LAYER M3 ;
        RECT  30.42 0 30.438 0.037 ;
    END
  END u_data[499]
  PIN u_data[49]
    DIRECTION INPUT ;
    USE SIGNAL ;
    PORT
      LAYER M3 ;
        RECT  25.092 0 25.11 0.037 ;
    END
  END u_data[49]
  PIN u_data[4]
    DIRECTION INPUT ;
    USE SIGNAL ;
    PORT
      LAYER M5 ;
        RECT  19.92 0 19.944 0.084 ;
    END
  END u_data[4]
  PIN u_data[500]
    DIRECTION INPUT ;
    USE SIGNAL ;
    PORT
      LAYER M3 ;
        RECT  30.492 0 30.51 0.037 ;
    END
  END u_data[500]
  PIN u_data[501]
    DIRECTION INPUT ;
    USE SIGNAL ;
    PORT
      LAYER M3 ;
        RECT  30.564 0 30.582 0.037 ;
    END
  END u_data[501]
  PIN u_data[502]
    DIRECTION INPUT ;
    USE SIGNAL ;
    PORT
      LAYER M3 ;
        RECT  30.636 0 30.654 0.037 ;
    END
  END u_data[502]
  PIN u_data[503]
    DIRECTION INPUT ;
    USE SIGNAL ;
    PORT
      LAYER M3 ;
        RECT  30.708 0 30.726 0.037 ;
    END
  END u_data[503]
  PIN u_data[504]
    DIRECTION INPUT ;
    USE SIGNAL ;
    PORT
      LAYER M3 ;
        RECT  30.78 0 30.798 0.037 ;
    END
  END u_data[504]
  PIN u_data[505]
    DIRECTION INPUT ;
    USE SIGNAL ;
    PORT
      LAYER M3 ;
        RECT  30.852 0 30.87 0.037 ;
    END
  END u_data[505]
  PIN u_data[506]
    DIRECTION INPUT ;
    USE SIGNAL ;
    PORT
      LAYER M3 ;
        RECT  30.924 0 30.942 0.037 ;
    END
  END u_data[506]
  PIN u_data[507]
    DIRECTION INPUT ;
    USE SIGNAL ;
    PORT
      LAYER M3 ;
        RECT  30.996 0 31.014 0.037 ;
    END
  END u_data[507]
  PIN u_data[508]
    DIRECTION INPUT ;
    USE SIGNAL ;
    PORT
      LAYER M3 ;
        RECT  31.068 0 31.086 0.037 ;
    END
  END u_data[508]
  PIN u_data[509]
    DIRECTION INPUT ;
    USE SIGNAL ;
    PORT
      LAYER M3 ;
        RECT  31.14 0 31.158 0.037 ;
    END
  END u_data[509]
  PIN u_data[50]
    DIRECTION INPUT ;
    USE SIGNAL ;
    PORT
      LAYER M3 ;
        RECT  25.164 0 25.182 0.037 ;
    END
  END u_data[50]
  PIN u_data[510]
    DIRECTION INPUT ;
    USE SIGNAL ;
    PORT
      LAYER M3 ;
        RECT  31.212 0 31.23 0.037 ;
    END
  END u_data[510]
  PIN u_data[511]
    DIRECTION INPUT ;
    USE SIGNAL ;
    PORT
      LAYER M3 ;
        RECT  31.284 0 31.302 0.037 ;
    END
  END u_data[511]
  PIN u_data[51]
    DIRECTION INPUT ;
    USE SIGNAL ;
    PORT
      LAYER M3 ;
        RECT  25.236 0 25.254 0.037 ;
    END
  END u_data[51]
  PIN u_data[52]
    DIRECTION INPUT ;
    USE SIGNAL ;
    PORT
      LAYER M3 ;
        RECT  25.308 0 25.326 0.037 ;
    END
  END u_data[52]
  PIN u_data[53]
    DIRECTION INPUT ;
    USE SIGNAL ;
    PORT
      LAYER M3 ;
        RECT  25.38 0 25.398 0.037 ;
    END
  END u_data[53]
  PIN u_data[54]
    DIRECTION INPUT ;
    USE SIGNAL ;
    PORT
      LAYER M3 ;
        RECT  25.452 0 25.47 0.037 ;
    END
  END u_data[54]
  PIN u_data[55]
    DIRECTION INPUT ;
    USE SIGNAL ;
    PORT
      LAYER M3 ;
        RECT  25.524 0 25.542 0.037 ;
    END
  END u_data[55]
  PIN u_data[56]
    DIRECTION INPUT ;
    USE SIGNAL ;
    PORT
      LAYER M3 ;
        RECT  25.596 0 25.614 0.037 ;
    END
  END u_data[56]
  PIN u_data[57]
    DIRECTION INPUT ;
    USE SIGNAL ;
    PORT
      LAYER M3 ;
        RECT  25.668 0 25.686 0.037 ;
    END
  END u_data[57]
  PIN u_data[58]
    DIRECTION INPUT ;
    USE SIGNAL ;
    PORT
      LAYER M3 ;
        RECT  25.74 0 25.758 0.037 ;
    END
  END u_data[58]
  PIN u_data[59]
    DIRECTION INPUT ;
    USE SIGNAL ;
    PORT
      LAYER M3 ;
        RECT  25.812 0 25.83 0.037 ;
    END
  END u_data[59]
  PIN u_data[5]
    DIRECTION INPUT ;
    USE SIGNAL ;
    PORT
      LAYER M5 ;
        RECT  20.016 0 20.04 0.084 ;
    END
  END u_data[5]
  PIN u_data[60]
    DIRECTION INPUT ;
    USE SIGNAL ;
    PORT
      LAYER M3 ;
        RECT  25.884 0 25.902 0.037 ;
    END
  END u_data[60]
  PIN u_data[61]
    DIRECTION INPUT ;
    USE SIGNAL ;
    PORT
      LAYER M3 ;
        RECT  25.956 0 25.974 0.037 ;
    END
  END u_data[61]
  PIN u_data[62]
    DIRECTION INPUT ;
    USE SIGNAL ;
    PORT
      LAYER M3 ;
        RECT  26.028 0 26.046 0.037 ;
    END
  END u_data[62]
  PIN u_data[63]
    DIRECTION INPUT ;
    USE SIGNAL ;
    PORT
      LAYER M3 ;
        RECT  26.1 0 26.118 0.037 ;
    END
  END u_data[63]
  PIN u_data[64]
    DIRECTION INPUT ;
    USE SIGNAL ;
    PORT
      LAYER M3 ;
        RECT  26.172 0 26.19 0.037 ;
    END
  END u_data[64]
  PIN u_data[65]
    DIRECTION INPUT ;
    USE SIGNAL ;
    PORT
      LAYER M3 ;
        RECT  26.244 0 26.262 0.037 ;
    END
  END u_data[65]
  PIN u_data[66]
    DIRECTION INPUT ;
    USE SIGNAL ;
    PORT
      LAYER M3 ;
        RECT  26.316 0 26.334 0.037 ;
    END
  END u_data[66]
  PIN u_data[67]
    DIRECTION INPUT ;
    USE SIGNAL ;
    PORT
      LAYER M3 ;
        RECT  26.388 0 26.406 0.037 ;
    END
  END u_data[67]
  PIN u_data[68]
    DIRECTION INPUT ;
    USE SIGNAL ;
    PORT
      LAYER M3 ;
        RECT  14.94 0 14.958 0.037 ;
    END
  END u_data[68]
  PIN u_data[69]
    DIRECTION INPUT ;
    USE SIGNAL ;
    PORT
      LAYER M3 ;
        RECT  15.012 0 15.03 0.037 ;
    END
  END u_data[69]
  PIN u_data[6]
    DIRECTION INPUT ;
    USE SIGNAL ;
    PORT
      LAYER M5 ;
        RECT  20.112 0 20.136 0.084 ;
    END
  END u_data[6]
  PIN u_data[70]
    DIRECTION INPUT ;
    USE SIGNAL ;
    PORT
      LAYER M3 ;
        RECT  15.084 0 15.102 0.037 ;
    END
  END u_data[70]
  PIN u_data[71]
    DIRECTION INPUT ;
    USE SIGNAL ;
    PORT
      LAYER M3 ;
        RECT  15.156 0 15.174 0.037 ;
    END
  END u_data[71]
  PIN u_data[72]
    DIRECTION INPUT ;
    USE SIGNAL ;
    PORT
      LAYER M3 ;
        RECT  15.228 0 15.246 0.037 ;
    END
  END u_data[72]
  PIN u_data[73]
    DIRECTION INPUT ;
    USE SIGNAL ;
    PORT
      LAYER M3 ;
        RECT  15.3 0 15.318 0.037 ;
    END
  END u_data[73]
  PIN u_data[74]
    DIRECTION INPUT ;
    USE SIGNAL ;
    PORT
      LAYER M3 ;
        RECT  15.372 0 15.39 0.037 ;
    END
  END u_data[74]
  PIN u_data[75]
    DIRECTION INPUT ;
    USE SIGNAL ;
    PORT
      LAYER M3 ;
        RECT  15.444 0 15.462 0.037 ;
    END
  END u_data[75]
  PIN u_data[76]
    DIRECTION INPUT ;
    USE SIGNAL ;
    PORT
      LAYER M3 ;
        RECT  15.516 0 15.534 0.037 ;
    END
  END u_data[76]
  PIN u_data[77]
    DIRECTION INPUT ;
    USE SIGNAL ;
    PORT
      LAYER M3 ;
        RECT  15.588 0 15.606 0.037 ;
    END
  END u_data[77]
  PIN u_data[78]
    DIRECTION INPUT ;
    USE SIGNAL ;
    PORT
      LAYER M3 ;
        RECT  15.66 0 15.678 0.037 ;
    END
  END u_data[78]
  PIN u_data[79]
    DIRECTION INPUT ;
    USE SIGNAL ;
    PORT
      LAYER M3 ;
        RECT  15.732 0 15.75 0.037 ;
    END
  END u_data[79]
  PIN u_data[7]
    DIRECTION INPUT ;
    USE SIGNAL ;
    PORT
      LAYER M5 ;
        RECT  20.208 0 20.232 0.084 ;
    END
  END u_data[7]
  PIN u_data[80]
    DIRECTION INPUT ;
    USE SIGNAL ;
    PORT
      LAYER M3 ;
        RECT  15.804 0 15.822 0.037 ;
    END
  END u_data[80]
  PIN u_data[81]
    DIRECTION INPUT ;
    USE SIGNAL ;
    PORT
      LAYER M3 ;
        RECT  15.876 0 15.894 0.037 ;
    END
  END u_data[81]
  PIN u_data[82]
    DIRECTION INPUT ;
    USE SIGNAL ;
    PORT
      LAYER M3 ;
        RECT  15.948 0 15.966 0.037 ;
    END
  END u_data[82]
  PIN u_data[83]
    DIRECTION INPUT ;
    USE SIGNAL ;
    PORT
      LAYER M3 ;
        RECT  16.02 0 16.038 0.037 ;
    END
  END u_data[83]
  PIN u_data[84]
    DIRECTION INPUT ;
    USE SIGNAL ;
    PORT
      LAYER M3 ;
        RECT  16.092 0 16.11 0.037 ;
    END
  END u_data[84]
  PIN u_data[85]
    DIRECTION INPUT ;
    USE SIGNAL ;
    PORT
      LAYER M3 ;
        RECT  16.164 0 16.182 0.037 ;
    END
  END u_data[85]
  PIN u_data[86]
    DIRECTION INPUT ;
    USE SIGNAL ;
    PORT
      LAYER M3 ;
        RECT  16.236 0 16.254 0.037 ;
    END
  END u_data[86]
  PIN u_data[87]
    DIRECTION INPUT ;
    USE SIGNAL ;
    PORT
      LAYER M3 ;
        RECT  16.308 0 16.326 0.037 ;
    END
  END u_data[87]
  PIN u_data[88]
    DIRECTION INPUT ;
    USE SIGNAL ;
    PORT
      LAYER M3 ;
        RECT  16.38 0 16.398 0.037 ;
    END
  END u_data[88]
  PIN u_data[89]
    DIRECTION INPUT ;
    USE SIGNAL ;
    PORT
      LAYER M3 ;
        RECT  16.452 0 16.47 0.037 ;
    END
  END u_data[89]
  PIN u_data[8]
    DIRECTION INPUT ;
    USE SIGNAL ;
    PORT
      LAYER M5 ;
        RECT  20.304 0 20.328 0.084 ;
    END
  END u_data[8]
  PIN u_data[90]
    DIRECTION INPUT ;
    USE SIGNAL ;
    PORT
      LAYER M3 ;
        RECT  16.524 0 16.542 0.037 ;
    END
  END u_data[90]
  PIN u_data[91]
    DIRECTION INPUT ;
    USE SIGNAL ;
    PORT
      LAYER M3 ;
        RECT  16.596 0 16.614 0.037 ;
    END
  END u_data[91]
  PIN u_data[92]
    DIRECTION INPUT ;
    USE SIGNAL ;
    PORT
      LAYER M3 ;
        RECT  16.668 0 16.686 0.037 ;
    END
  END u_data[92]
  PIN u_data[93]
    DIRECTION INPUT ;
    USE SIGNAL ;
    PORT
      LAYER M3 ;
        RECT  16.74 0 16.758 0.037 ;
    END
  END u_data[93]
  PIN u_data[94]
    DIRECTION INPUT ;
    USE SIGNAL ;
    PORT
      LAYER M3 ;
        RECT  16.812 0 16.83 0.037 ;
    END
  END u_data[94]
  PIN u_data[95]
    DIRECTION INPUT ;
    USE SIGNAL ;
    PORT
      LAYER M3 ;
        RECT  16.884 0 16.902 0.037 ;
    END
  END u_data[95]
  PIN u_data[96]
    DIRECTION INPUT ;
    USE SIGNAL ;
    PORT
      LAYER M3 ;
        RECT  16.956 0 16.974 0.037 ;
    END
  END u_data[96]
  PIN u_data[97]
    DIRECTION INPUT ;
    USE SIGNAL ;
    PORT
      LAYER M3 ;
        RECT  17.028 0 17.046 0.037 ;
    END
  END u_data[97]
  PIN u_data[98]
    DIRECTION INPUT ;
    USE SIGNAL ;
    PORT
      LAYER M3 ;
        RECT  17.1 0 17.118 0.037 ;
    END
  END u_data[98]
  PIN u_data[99]
    DIRECTION INPUT ;
    USE SIGNAL ;
    PORT
      LAYER M3 ;
        RECT  17.172 0 17.19 0.037 ;
    END
  END u_data[99]
  PIN u_data[9]
    DIRECTION INPUT ;
    USE SIGNAL ;
    PORT
      LAYER M5 ;
        RECT  20.4 0 20.424 0.084 ;
    END
  END u_data[9]
  PIN u_v
    DIRECTION INPUT ;
    USE SIGNAL ;
    PORT
      LAYER M3 ;
        RECT  31.356 0 31.374 0.037 ;
    END
  END u_v
  PIN VDD
    DIRECTION INOUT ;
    USE POWER ;
    PORT
      LAYER M5 ;
        RECT  51.192 2.151 51.312 84.249 ;
        RECT  45.792 2.151 45.912 84.249 ;
        RECT  40.392 2.151 40.512 84.249 ;
        RECT  34.992 2.151 35.112 84.249 ;
        RECT  29.592 2.151 29.712 84.249 ;
        RECT  24.192 2.151 24.312 84.249 ;
        RECT  18.792 2.151 18.912 84.249 ;
        RECT  13.392 2.151 13.512 84.249 ;
        RECT  7.992 2.151 8.112 84.249 ;
        RECT  2.592 2.151 2.712 84.249 ;
    END
  END VDD
  PIN VSS
    DIRECTION INOUT ;
    USE GROUND ;
    PORT
      LAYER M5 ;
        RECT  51 2.137 51.12 84.263 ;
        RECT  45.6 2.137 45.72 84.263 ;
        RECT  40.2 2.137 40.32 84.263 ;
        RECT  34.8 2.137 34.92 84.263 ;
        RECT  29.4 2.137 29.52 84.263 ;
        RECT  24 2.137 24.12 84.263 ;
        RECT  18.6 2.137 18.72 84.263 ;
        RECT  13.2 2.137 13.32 84.263 ;
        RECT  7.8 2.137 7.92 84.263 ;
        RECT  2.4 2.137 2.52 84.263 ;
    END
  END VSS
  OBS
    LAYER RVTN ;
     RECT  2.16 2.16 51.84 2.295 ;
     RECT  2.16 2.565 51.84 2.835 ;
     RECT  2.16 3.105 51.84 3.375 ;
     RECT  2.16 3.645 51.84 3.915 ;
     RECT  2.16 4.185 51.84 4.455 ;
     RECT  2.16 4.725 51.84 4.995 ;
     RECT  2.16 5.265 51.84 5.535 ;
     RECT  2.16 5.805 51.84 6.075 ;
     RECT  2.16 6.345 51.84 6.615 ;
     RECT  2.16 6.885 51.84 7.155 ;
     RECT  2.16 7.425 51.84 7.695 ;
     RECT  2.16 7.965 51.84 8.235 ;
     RECT  2.16 8.505 51.84 8.775 ;
     RECT  2.16 9.045 51.84 9.315 ;
     RECT  2.16 9.585 51.84 9.855 ;
     RECT  2.16 10.125 51.84 10.395 ;
     RECT  2.16 10.665 51.84 10.935 ;
     RECT  2.16 11.205 51.84 11.475 ;
     RECT  2.16 11.745 51.84 12.015 ;
     RECT  2.16 12.285 51.84 12.555 ;
     RECT  2.16 12.825 51.84 13.095 ;
     RECT  2.16 13.365 51.84 13.635 ;
     RECT  2.16 13.905 51.84 14.175 ;
     RECT  2.16 14.445 51.84 14.715 ;
     RECT  2.16 14.985 51.84 15.255 ;
     RECT  2.16 15.525 51.84 15.795 ;
     RECT  2.16 16.065 51.84 16.335 ;
     RECT  2.16 16.605 51.84 16.875 ;
     RECT  2.16 17.145 51.84 17.415 ;
     RECT  2.16 17.685 51.84 17.955 ;
     RECT  2.16 18.225 51.84 18.495 ;
     RECT  2.16 18.765 51.84 19.035 ;
     RECT  2.16 19.305 51.84 19.575 ;
     RECT  2.16 19.845 51.84 20.115 ;
     RECT  2.16 20.385 51.84 20.655 ;
     RECT  2.16 20.925 51.84 21.195 ;
     RECT  2.16 21.465 51.84 21.735 ;
     RECT  2.16 22.005 51.84 22.275 ;
     RECT  2.16 22.545 51.84 22.815 ;
     RECT  2.16 23.085 51.84 23.355 ;
     RECT  2.16 23.625 51.84 23.895 ;
     RECT  2.16 24.165 51.84 24.435 ;
     RECT  2.16 24.705 51.84 24.975 ;
     RECT  2.16 25.245 51.84 25.515 ;
     RECT  2.16 25.785 51.84 26.055 ;
     RECT  2.16 26.325 51.84 26.595 ;
     RECT  2.16 26.865 51.84 27.135 ;
     RECT  2.16 27.405 51.84 27.675 ;
     RECT  2.16 27.945 51.84 28.215 ;
     RECT  2.16 28.485 51.84 28.755 ;
     RECT  2.16 29.025 51.84 29.295 ;
     RECT  2.16 29.565 51.84 29.835 ;
     RECT  2.16 30.105 51.84 30.375 ;
     RECT  2.16 30.645 51.84 30.915 ;
     RECT  2.16 31.185 51.84 31.455 ;
     RECT  2.16 31.725 51.84 31.995 ;
     RECT  2.16 32.265 51.84 32.535 ;
     RECT  2.16 32.805 51.84 33.075 ;
     RECT  2.16 33.345 51.84 33.615 ;
     RECT  2.16 33.885 51.84 34.155 ;
     RECT  2.16 34.425 51.84 34.695 ;
     RECT  2.16 34.965 51.84 35.235 ;
     RECT  2.16 35.505 51.84 35.775 ;
     RECT  2.16 36.045 51.84 36.315 ;
     RECT  2.16 36.585 51.84 36.855 ;
     RECT  2.16 37.125 51.84 37.395 ;
     RECT  2.16 37.665 51.84 37.935 ;
     RECT  2.16 38.205 51.84 38.475 ;
     RECT  2.16 38.745 51.84 39.015 ;
     RECT  2.16 39.285 51.84 39.555 ;
     RECT  2.16 39.825 51.84 40.095 ;
     RECT  2.16 40.365 51.84 40.635 ;
     RECT  2.16 40.905 51.84 41.175 ;
     RECT  2.16 41.445 51.84 41.715 ;
     RECT  2.16 41.985 51.84 42.255 ;
     RECT  2.16 42.525 51.84 42.795 ;
     RECT  2.16 43.065 51.84 43.335 ;
     RECT  2.16 43.605 51.84 43.875 ;
     RECT  2.16 44.145 51.84 44.415 ;
     RECT  2.16 44.685 51.84 44.955 ;
     RECT  2.16 45.225 51.84 45.495 ;
     RECT  2.16 45.765 51.84 46.035 ;
     RECT  2.16 46.305 51.84 46.575 ;
     RECT  2.16 46.845 51.84 47.115 ;
     RECT  2.16 47.385 51.84 47.655 ;
     RECT  2.16 47.925 51.84 48.195 ;
     RECT  2.16 48.465 51.84 48.735 ;
     RECT  2.16 49.005 51.84 49.275 ;
     RECT  2.16 49.545 51.84 49.815 ;
     RECT  2.16 50.085 51.84 50.355 ;
     RECT  2.16 50.625 51.84 50.895 ;
     RECT  2.16 51.165 51.84 51.435 ;
     RECT  2.16 51.705 51.84 51.975 ;
     RECT  2.16 52.245 51.84 52.515 ;
     RECT  2.16 52.785 51.84 53.055 ;
     RECT  2.16 53.325 51.84 53.595 ;
     RECT  2.16 53.865 51.84 54.135 ;
     RECT  2.16 54.405 51.84 54.675 ;
     RECT  2.16 54.945 51.84 55.215 ;
     RECT  2.16 55.485 51.84 55.755 ;
     RECT  2.16 56.025 51.84 56.295 ;
     RECT  2.16 56.565 51.84 56.835 ;
     RECT  2.16 57.105 51.84 57.375 ;
     RECT  2.16 57.645 51.84 57.915 ;
     RECT  2.16 58.185 51.84 58.455 ;
     RECT  2.16 58.725 51.84 58.995 ;
     RECT  2.16 59.265 51.84 59.535 ;
     RECT  2.16 59.805 51.84 60.075 ;
     RECT  2.16 60.345 51.84 60.615 ;
     RECT  2.16 60.885 51.84 61.155 ;
     RECT  2.16 61.425 51.84 61.695 ;
     RECT  2.16 61.965 51.84 62.235 ;
     RECT  2.16 62.505 51.84 62.775 ;
     RECT  2.16 63.045 51.84 63.315 ;
     RECT  2.16 63.585 51.84 63.855 ;
     RECT  2.16 64.125 51.84 64.395 ;
     RECT  2.16 64.665 51.84 64.935 ;
     RECT  2.16 65.205 51.84 65.475 ;
     RECT  2.16 65.745 51.84 66.015 ;
     RECT  2.16 66.285 51.84 66.555 ;
     RECT  2.16 66.825 51.84 67.095 ;
     RECT  2.16 67.365 51.84 67.635 ;
     RECT  2.16 67.905 51.84 68.175 ;
     RECT  2.16 68.445 51.84 68.715 ;
     RECT  2.16 68.985 51.84 69.255 ;
     RECT  2.16 69.525 51.84 69.795 ;
     RECT  2.16 70.065 51.84 70.335 ;
     RECT  2.16 70.605 51.84 70.875 ;
     RECT  2.16 71.145 51.84 71.415 ;
     RECT  2.16 71.685 51.84 71.955 ;
     RECT  2.16 72.225 51.84 72.495 ;
     RECT  2.16 72.765 51.84 73.035 ;
     RECT  2.16 73.305 51.84 73.575 ;
     RECT  2.16 73.845 51.84 74.115 ;
     RECT  2.16 74.385 51.84 74.655 ;
     RECT  2.16 74.925 51.84 75.195 ;
     RECT  2.16 75.465 51.84 75.735 ;
     RECT  2.16 76.005 51.84 76.275 ;
     RECT  2.16 76.545 51.84 76.815 ;
     RECT  2.16 77.085 51.84 77.355 ;
     RECT  2.16 77.625 51.84 77.895 ;
     RECT  2.16 78.165 51.84 78.435 ;
     RECT  2.16 78.705 51.84 78.975 ;
     RECT  2.16 79.245 51.84 79.515 ;
     RECT  2.16 79.785 51.84 80.055 ;
     RECT  2.16 80.325 51.84 80.595 ;
     RECT  2.16 80.865 51.84 81.135 ;
     RECT  2.16 81.405 51.84 81.675 ;
     RECT  2.16 81.945 51.84 82.215 ;
     RECT  2.16 82.485 51.84 82.755 ;
     RECT  2.16 83.025 51.84 83.295 ;
     RECT  2.16 83.565 51.84 83.835 ;
     RECT  2.16 84.105 51.84 84.24 ;
    LAYER RVTP ;
     RECT  2.16 2.295 51.84 2.565 ;
     RECT  2.16 2.835 51.84 3.105 ;
     RECT  2.16 3.375 51.84 3.645 ;
     RECT  2.16 3.915 51.84 4.185 ;
     RECT  2.16 4.455 51.84 4.725 ;
     RECT  2.16 4.995 51.84 5.265 ;
     RECT  2.16 5.535 51.84 5.805 ;
     RECT  2.16 6.075 51.84 6.345 ;
     RECT  2.16 6.615 51.84 6.885 ;
     RECT  2.16 7.155 51.84 7.425 ;
     RECT  2.16 7.695 51.84 7.965 ;
     RECT  2.16 8.235 51.84 8.505 ;
     RECT  2.16 8.775 51.84 9.045 ;
     RECT  2.16 9.315 51.84 9.585 ;
     RECT  2.16 9.855 51.84 10.125 ;
     RECT  2.16 10.395 51.84 10.665 ;
     RECT  2.16 10.935 51.84 11.205 ;
     RECT  2.16 11.475 51.84 11.745 ;
     RECT  2.16 12.015 51.84 12.285 ;
     RECT  2.16 12.555 51.84 12.825 ;
     RECT  2.16 13.095 51.84 13.365 ;
     RECT  2.16 13.635 51.84 13.905 ;
     RECT  2.16 14.175 51.84 14.445 ;
     RECT  2.16 14.715 51.84 14.985 ;
     RECT  2.16 15.255 51.84 15.525 ;
     RECT  2.16 15.795 51.84 16.065 ;
     RECT  2.16 16.335 51.84 16.605 ;
     RECT  2.16 16.875 51.84 17.145 ;
     RECT  2.16 17.415 51.84 17.685 ;
     RECT  2.16 17.955 51.84 18.225 ;
     RECT  2.16 18.495 51.84 18.765 ;
     RECT  2.16 19.035 51.84 19.305 ;
     RECT  2.16 19.575 51.84 19.845 ;
     RECT  2.16 20.115 51.84 20.385 ;
     RECT  2.16 20.655 51.84 20.925 ;
     RECT  2.16 21.195 51.84 21.465 ;
     RECT  2.16 21.735 51.84 22.005 ;
     RECT  2.16 22.275 51.84 22.545 ;
     RECT  2.16 22.815 51.84 23.085 ;
     RECT  2.16 23.355 51.84 23.625 ;
     RECT  2.16 23.895 51.84 24.165 ;
     RECT  2.16 24.435 51.84 24.705 ;
     RECT  2.16 24.975 51.84 25.245 ;
     RECT  2.16 25.515 51.84 25.785 ;
     RECT  2.16 26.055 51.84 26.325 ;
     RECT  2.16 26.595 51.84 26.865 ;
     RECT  2.16 27.135 51.84 27.405 ;
     RECT  2.16 27.675 51.84 27.945 ;
     RECT  2.16 28.215 51.84 28.485 ;
     RECT  2.16 28.755 51.84 29.025 ;
     RECT  2.16 29.295 51.84 29.565 ;
     RECT  2.16 29.835 51.84 30.105 ;
     RECT  2.16 30.375 51.84 30.645 ;
     RECT  2.16 30.915 51.84 31.185 ;
     RECT  2.16 31.455 51.84 31.725 ;
     RECT  2.16 31.995 51.84 32.265 ;
     RECT  2.16 32.535 51.84 32.805 ;
     RECT  2.16 33.075 51.84 33.345 ;
     RECT  2.16 33.615 51.84 33.885 ;
     RECT  2.16 34.155 51.84 34.425 ;
     RECT  2.16 34.695 51.84 34.965 ;
     RECT  2.16 35.235 51.84 35.505 ;
     RECT  2.16 35.775 51.84 36.045 ;
     RECT  2.16 36.315 51.84 36.585 ;
     RECT  2.16 36.855 51.84 37.125 ;
     RECT  2.16 37.395 51.84 37.665 ;
     RECT  2.16 37.935 51.84 38.205 ;
     RECT  2.16 38.475 51.84 38.745 ;
     RECT  2.16 39.015 51.84 39.285 ;
     RECT  2.16 39.555 51.84 39.825 ;
     RECT  2.16 40.095 51.84 40.365 ;
     RECT  2.16 40.635 51.84 40.905 ;
     RECT  2.16 41.175 51.84 41.445 ;
     RECT  2.16 41.715 51.84 41.985 ;
     RECT  2.16 42.255 51.84 42.525 ;
     RECT  2.16 42.795 51.84 43.065 ;
     RECT  2.16 43.335 51.84 43.605 ;
     RECT  2.16 43.875 51.84 44.145 ;
     RECT  2.16 44.415 51.84 44.685 ;
     RECT  2.16 44.955 51.84 45.225 ;
     RECT  2.16 45.495 51.84 45.765 ;
     RECT  2.16 46.035 51.84 46.305 ;
     RECT  2.16 46.575 51.84 46.845 ;
     RECT  2.16 47.115 51.84 47.385 ;
     RECT  2.16 47.655 51.84 47.925 ;
     RECT  2.16 48.195 51.84 48.465 ;
     RECT  2.16 48.735 51.84 49.005 ;
     RECT  2.16 49.275 51.84 49.545 ;
     RECT  2.16 49.815 51.84 50.085 ;
     RECT  2.16 50.355 51.84 50.625 ;
     RECT  2.16 50.895 51.84 51.165 ;
     RECT  2.16 51.435 51.84 51.705 ;
     RECT  2.16 51.975 51.84 52.245 ;
     RECT  2.16 52.515 51.84 52.785 ;
     RECT  2.16 53.055 51.84 53.325 ;
     RECT  2.16 53.595 51.84 53.865 ;
     RECT  2.16 54.135 51.84 54.405 ;
     RECT  2.16 54.675 51.84 54.945 ;
     RECT  2.16 55.215 51.84 55.485 ;
     RECT  2.16 55.755 51.84 56.025 ;
     RECT  2.16 56.295 51.84 56.565 ;
     RECT  2.16 56.835 51.84 57.105 ;
     RECT  2.16 57.375 51.84 57.645 ;
     RECT  2.16 57.915 51.84 58.185 ;
     RECT  2.16 58.455 51.84 58.725 ;
     RECT  2.16 58.995 51.84 59.265 ;
     RECT  2.16 59.535 51.84 59.805 ;
     RECT  2.16 60.075 51.84 60.345 ;
     RECT  2.16 60.615 51.84 60.885 ;
     RECT  2.16 61.155 51.84 61.425 ;
     RECT  2.16 61.695 51.84 61.965 ;
     RECT  2.16 62.235 51.84 62.505 ;
     RECT  2.16 62.775 51.84 63.045 ;
     RECT  2.16 63.315 51.84 63.585 ;
     RECT  2.16 63.855 51.84 64.125 ;
     RECT  2.16 64.395 51.84 64.665 ;
     RECT  2.16 64.935 51.84 65.205 ;
     RECT  2.16 65.475 51.84 65.745 ;
     RECT  2.16 66.015 51.84 66.285 ;
     RECT  2.16 66.555 51.84 66.825 ;
     RECT  2.16 67.095 51.84 67.365 ;
     RECT  2.16 67.635 51.84 67.905 ;
     RECT  2.16 68.175 51.84 68.445 ;
     RECT  2.16 68.715 51.84 68.985 ;
     RECT  2.16 69.255 51.84 69.525 ;
     RECT  2.16 69.795 51.84 70.065 ;
     RECT  2.16 70.335 51.84 70.605 ;
     RECT  2.16 70.875 51.84 71.145 ;
     RECT  2.16 71.415 51.84 71.685 ;
     RECT  2.16 71.955 51.84 72.225 ;
     RECT  2.16 72.495 51.84 72.765 ;
     RECT  2.16 73.035 51.84 73.305 ;
     RECT  2.16 73.575 51.84 73.845 ;
     RECT  2.16 74.115 51.84 74.385 ;
     RECT  2.16 74.655 51.84 74.925 ;
     RECT  2.16 75.195 51.84 75.465 ;
     RECT  2.16 75.735 51.84 76.005 ;
     RECT  2.16 76.275 51.84 76.545 ;
     RECT  2.16 76.815 51.84 77.085 ;
     RECT  2.16 77.355 51.84 77.625 ;
     RECT  2.16 77.895 51.84 78.165 ;
     RECT  2.16 78.435 51.84 78.705 ;
     RECT  2.16 78.975 51.84 79.245 ;
     RECT  2.16 79.515 51.84 79.785 ;
     RECT  2.16 80.055 51.84 80.325 ;
     RECT  2.16 80.595 51.84 80.865 ;
     RECT  2.16 81.135 51.84 81.405 ;
     RECT  2.16 81.675 51.84 81.945 ;
     RECT  2.16 82.215 51.84 82.485 ;
     RECT  2.16 82.755 51.84 83.025 ;
     RECT  2.16 83.295 51.84 83.565 ;
     RECT  2.16 83.835 51.84 84.105 ;
    LAYER M1 ;
     RECT  2.16 2.151 51.84 84.249 ;
    LAYER M2 ;
     RECT  0.103 22.941 0.139 23.58 ;
     RECT  0.103 27.261 0.139 27.279 ;
     RECT  0.103 44.766 0.139 44.784 ;
     RECT  0.103 45.621 0.139 46.602 ;
     RECT  0.103 50.481 0.139 50.499 ;
     RECT  0.103 63.018 0.139 63.036 ;
     RECT  0.103 70.074 0.139 70.092 ;
     RECT  0.103 75.474 0.139 75.492 ;
     RECT  0.103 48.438 0.175 48.996 ;
     RECT  0.103 67.446 0.175 67.464 ;
     RECT  0.103 19.926 0.203 19.944 ;
     RECT  0.103 21.132 0.203 21.564 ;
     RECT  0.139 22.896 0.203 23.58 ;
     RECT  0.103 25.866 0.203 25.884 ;
     RECT  0.139 26.802 0.203 27.279 ;
     RECT  0.103 28.881 0.203 34.569 ;
     RECT  0.103 39.096 0.203 39.114 ;
     RECT  0.103 40.878 0.203 41.544 ;
     RECT  0.103 43.191 0.203 43.209 ;
     RECT  0.139 44.658 0.203 46.602 ;
     RECT  0.175 48.438 0.203 49.068 ;
     RECT  0.139 50.058 0.203 50.499 ;
     RECT  0.103 54.846 0.203 56.169 ;
     RECT  0.103 57.771 0.203 57.789 ;
     RECT  0.103 59.472 0.203 60.444 ;
     RECT  0.103 61.398 0.203 61.839 ;
     RECT  0.139 62.946 0.203 63.036 ;
     RECT  0.175 67.338 0.203 67.464 ;
     RECT  0.103 68.346 0.203 68.976 ;
     RECT  0.139 70.002 0.203 70.092 ;
     RECT  0.103 71.19 0.203 71.208 ;
     RECT  0.203 26.802 0.239 26.82 ;
     RECT  0.203 28.881 0.239 28.899 ;
     RECT  0.203 32.778 0.239 33.264 ;
     RECT  0.203 40.878 0.239 41.436 ;
     RECT  0.203 44.658 0.239 45.639 ;
     RECT  0.203 54.846 0.239 55.278 ;
     RECT  0.203 59.472 0.239 59.994 ;
     RECT  0.203 62.946 0.239 62.964 ;
     RECT  0.203 70.002 0.239 70.02 ;
     RECT  0.203 49.05 0.275 49.068 ;
     RECT  0.203 67.338 0.275 67.356 ;
     RECT  0.239 44.766 0.347 45.639 ;
     RECT  0.203 46.584 0.383 46.602 ;
     RECT  0.239 59.472 0.419 59.562 ;
     RECT  0.103 53.406 0.463 53.424 ;
     RECT  0.463 52.992 0.499 53.424 ;
     RECT  0.419 59.472 0.527 59.49 ;
     RECT  0.427 52.02 0.535 52.038 ;
     RECT  0.499 52.866 0.535 53.424 ;
     RECT  0.319 47.394 0.571 47.412 ;
     RECT  0.139 75.276 0.823 75.492 ;
     RECT  0.823 75.276 0.895 75.834 ;
     RECT  0.175 73.818 1.147 73.836 ;
     RECT  0.895 74.736 1.147 75.834 ;
     RECT  1.147 38.556 1.723 38.574 ;
     RECT  0.203 21.546 2.16 21.564 ;
     RECT  0.203 22.896 2.16 22.914 ;
     RECT  0.203 31.464 2.16 31.482 ;
     RECT  0.239 33.246 2.16 33.264 ;
     RECT  1.723 38.484 2.16 38.574 ;
     RECT  0.823 40.176 2.16 40.194 ;
     RECT  0.239 41.256 2.16 41.436 ;
     RECT  0.347 44.766 2.16 44.784 ;
     RECT  0.347 45.621 2.16 45.639 ;
     RECT  0.571 47.394 2.16 47.754 ;
     RECT  0.203 50.058 2.16 50.076 ;
     RECT  0.535 51.138 2.16 51.156 ;
     RECT  0.535 52.02 2.16 53.424 ;
     RECT  0.239 54.846 2.16 54.864 ;
     RECT  0.535 65.52 2.16 66.078 ;
     RECT  1.399 69.876 2.16 69.894 ;
     RECT  0.535 72.234 2.16 72.252 ;
     RECT  1.147 73.818 2.16 75.834 ;
     RECT  14.287 0.036 14.575 0.054 ;
     RECT  14.575 0.036 14.863 0.126 ;
     RECT  14.863 0.036 15.223 0.198 ;
     RECT  15.223 0.036 15.323 0.594 ;
     RECT  15.323 0.036 15.467 0.468 ;
     RECT  15.467 0.108 15.539 0.468 ;
     RECT  15.539 0.18 16.087 0.468 ;
     RECT  16.087 0.18 16.187 0.63 ;
     RECT  16.187 0.18 16.411 0.549 ;
     RECT  16.411 0.036 16.547 0.549 ;
     RECT  16.547 0.036 16.619 0.198 ;
     RECT  16.619 0.036 16.691 0.126 ;
     RECT  14.359 85.194 16.951 85.212 ;
     RECT  16.691 0.108 17.123 0.126 ;
     RECT  2.16 2.151 17.707 84.249 ;
     RECT  16.951 85.194 17.959 85.716 ;
     RECT  17.491 0.036 18.139 0.054 ;
     RECT  17.563 0.846 18.139 0.864 ;
     RECT  17.959 85.194 18.239 86.364 ;
     RECT  17.707 1.728 18.347 84.249 ;
     RECT  18.347 2.151 18.355 84.249 ;
     RECT  18.239 85.194 18.563 86.292 ;
     RECT  18.563 86.274 18.967 86.292 ;
     RECT  18.967 86.274 18.995 86.364 ;
     RECT  18.355 2.151 19.463 84.402 ;
     RECT  18.995 86.346 19.643 86.364 ;
     RECT  18.139 0.036 20.515 0.864 ;
     RECT  20.515 0.036 20.587 0.972 ;
     RECT  20.587 0.036 20.975 1.134 ;
     RECT  19.463 2.151 21.127 84.249 ;
     RECT  20.975 0.036 21.875 0.864 ;
     RECT  21.875 0.108 21.991 0.864 ;
     RECT  21.127 1.728 21.991 84.249 ;
     RECT  21.991 0.108 22.019 84.249 ;
     RECT  22.019 0.18 22.091 84.249 ;
     RECT  22.091 0.414 22.379 84.249 ;
     RECT  22.379 0.414 22.739 1.17 ;
     RECT  22.739 0.414 22.883 0.504 ;
     RECT  23.107 0.036 23.171 0.198 ;
     RECT  22.819 86.346 23.171 86.364 ;
     RECT  23.179 86.274 23.315 86.292 ;
     RECT  18.563 85.194 23.359 85.212 ;
     RECT  23.359 85.194 23.531 85.869 ;
     RECT  23.171 0.108 23.971 0.198 ;
     RECT  22.379 2.151 24.079 84.249 ;
     RECT  23.531 85.194 24.179 85.212 ;
     RECT  23.971 0.036 24.295 0.198 ;
     RECT  24.079 2.151 24.359 84.33 ;
     RECT  24.511 86.274 24.583 86.292 ;
     RECT  24.583 86.274 24.611 86.364 ;
     RECT  24.611 86.346 24.683 86.364 ;
     RECT  24.295 0.036 24.943 0.396 ;
     RECT  24.943 0.036 25.159 0.468 ;
     RECT  25.159 0.036 25.951 0.549 ;
     RECT  25.951 0.036 26.023 0.666 ;
     RECT  26.023 0.036 26.159 0.738 ;
     RECT  26.159 0.036 27.203 0.054 ;
     RECT  28.075 0.036 28.499 0.054 ;
     RECT  24.359 2.151 28.651 84.249 ;
     RECT  28.579 85.581 28.931 85.599 ;
     RECT  28.651 1.728 29.227 84.249 ;
     RECT  29.119 0.108 29.263 0.324 ;
     RECT  29.227 1.728 29.291 84.33 ;
     RECT  29.291 1.8 29.299 84.33 ;
     RECT  29.263 86.346 29.399 86.364 ;
     RECT  29.299 1.8 29.507 84.402 ;
     RECT  29.263 0.036 29.615 0.324 ;
     RECT  29.615 0.036 29.651 0.279 ;
     RECT  29.651 0.036 30.883 0.126 ;
     RECT  30.199 86.346 30.983 86.364 ;
     RECT  29.507 2.151 31.027 84.249 ;
     RECT  30.883 0.036 31.603 0.234 ;
     RECT  31.027 2.151 31.783 84.942 ;
     RECT  31.603 0.036 31.855 0.324 ;
     RECT  31.747 86.346 31.883 86.364 ;
     RECT  31.783 2.151 31.919 85.014 ;
     RECT  31.855 0.036 32.359 0.396 ;
     RECT  32.359 0.036 32.683 0.432 ;
     RECT  32.683 0.036 32.819 0.504 ;
     RECT  32.819 0.036 32.891 0.432 ;
     RECT  32.503 85.581 32.927 85.599 ;
     RECT  31.919 2.151 32.963 84.366 ;
     RECT  32.963 2.151 33.763 84.249 ;
     RECT  32.891 0.036 33.871 0.198 ;
     RECT  33.871 0.036 33.943 0.234 ;
     RECT  33.943 0.036 34.015 0.324 ;
     RECT  33.763 2.151 34.123 84.942 ;
     RECT  34.123 2.151 34.763 85.518 ;
     RECT  34.015 0.036 35.167 0.549 ;
     RECT  34.763 2.151 35.167 85.14 ;
     RECT  35.167 0.036 35.339 85.14 ;
     RECT  35.339 0.036 35.483 85.014 ;
     RECT  35.483 0.036 35.519 0.549 ;
     RECT  35.519 0.036 35.771 0.504 ;
     RECT  35.771 0.036 36.059 0.279 ;
     RECT  35.483 1.728 36.139 85.014 ;
     RECT  36.059 0.036 36.887 0.198 ;
     RECT  36.139 1.728 36.923 85.059 ;
     RECT  36.923 1.728 37.031 84.942 ;
     RECT  37.031 1.728 37.103 84.294 ;
     RECT  37.103 2.151 37.499 84.294 ;
     RECT  36.887 0.036 37.615 0.126 ;
     RECT  37.615 0.036 38.191 0.279 ;
     RECT  37.499 2.151 38.263 84.249 ;
     RECT  38.263 2.151 38.767 84.942 ;
     RECT  38.767 2.151 38.795 85.014 ;
     RECT  38.795 84.996 39.083 85.014 ;
     RECT  38.191 0.036 39.307 0.63 ;
     RECT  39.307 0.036 39.415 0.774 ;
     RECT  39.415 0.036 39.515 0.864 ;
     RECT  39.515 0.036 40.307 0.63 ;
     RECT  40.307 0.036 40.451 0.432 ;
     RECT  40.451 0.036 40.523 0.324 ;
     RECT  40.523 0.036 40.847 0.198 ;
     RECT  40.847 0.18 41.027 0.198 ;
     RECT  38.795 2.151 51.84 84.249 ;
    LAYER M3 ;
     RECT  14.94 0.012 40.806 0.031 ;
     RECT  14.292 0.031 40.842 0.175 ;
     RECT  14.292 0.175 41.022 0.811 ;
     RECT  14.292 0.811 41.49 0.859 ;
     RECT  2.415 2.143 2.505 2.413 ;
     RECT  7.815 2.143 7.905 2.413 ;
     RECT  13.215 2.143 13.305 2.413 ;
     RECT  45.615 2.143 45.705 2.413 ;
     RECT  51.015 2.143 51.105 2.413 ;
     RECT  2.415 2.413 2.697 18.859 ;
     RECT  2.304 18.859 2.697 19.099 ;
     RECT  2.304 19.099 2.79 19.139 ;
     RECT  13.215 2.413 13.497 19.471 ;
     RECT  0.144 19.531 0.162 19.579 ;
     RECT  0.144 19.579 0.234 19.757 ;
     RECT  0.144 19.757 0.198 19.921 ;
     RECT  0.108 19.921 0.198 20.189 ;
     RECT  0.108 20.189 0.126 20.237 ;
     RECT  13.104 19.471 13.497 20.489 ;
     RECT  2.304 19.139 2.697 20.525 ;
     RECT  2.415 20.525 2.697 20.821 ;
     RECT  2.415 20.821 2.79 20.861 ;
     RECT  0.144 20.923 0.162 21.127 ;
     RECT  0.108 21.127 0.198 21.163 ;
     RECT  0.108 21.163 0.342 21.389 ;
     RECT  2.415 20.861 2.697 21.631 ;
     RECT  13.215 20.489 13.497 21.631 ;
     RECT  2.304 21.631 2.697 21.677 ;
     RECT  13.104 21.631 13.497 21.677 ;
     RECT  0.108 21.389 0.126 21.965 ;
     RECT  14.292 0.859 41.598 22.847 ;
     RECT  0.144 22.891 0.162 22.924 ;
     RECT  2.415 21.677 2.697 23.419 ;
     RECT  2.415 23.419 2.79 23.459 ;
     RECT  0.108 22.924 0.198 23.585 ;
     RECT  2.415 23.459 2.697 24.232 ;
     RECT  13.215 21.677 13.497 24.232 ;
     RECT  2.304 24.232 2.697 24.368 ;
     RECT  0.144 23.585 0.162 24.907 ;
     RECT  4.284 24.943 4.302 25.051 ;
     RECT  2.415 24.368 2.697 25.147 ;
     RECT  13.104 24.232 13.497 25.313 ;
     RECT  2.415 25.147 2.79 25.517 ;
     RECT  0.144 24.907 0.846 25.861 ;
     RECT  0.108 25.861 0.846 25.901 ;
     RECT  2.415 25.517 2.697 25.951 ;
     RECT  2.304 25.951 2.697 25.997 ;
     RECT  13.215 25.313 13.497 26.131 ;
     RECT  13.215 26.131 13.59 26.221 ;
     RECT  12.924 26.221 13.59 26.671 ;
     RECT  2.415 25.997 2.697 26.923 ;
     RECT  2.304 26.923 2.697 26.969 ;
     RECT  0.144 25.901 0.846 27.244 ;
     RECT  0.108 27.244 0.846 27.533 ;
     RECT  14.4 22.847 41.598 27.571 ;
     RECT  14.364 27.571 41.598 27.671 ;
     RECT  12.852 26.671 13.59 27.715 ;
     RECT  14.364 27.671 16.83 27.715 ;
     RECT  2.415 26.969 2.697 27.739 ;
     RECT  2.415 27.739 2.79 27.779 ;
     RECT  12.852 27.715 16.83 28.687 ;
     RECT  17.568 27.671 41.598 28.687 ;
     RECT  0.828 27.533 0.846 28.699 ;
     RECT  0.18 28.699 0.846 28.876 ;
     RECT  11.736 25.141 11.754 29.065 ;
     RECT  2.415 27.779 2.697 29.101 ;
     RECT  2.304 29.101 2.697 29.165 ;
     RECT  11.736 29.065 12.114 29.641 ;
     RECT  12.852 28.687 41.598 29.641 ;
     RECT  11.628 29.641 41.598 29.939 ;
     RECT  2.415 29.165 2.697 30.271 ;
     RECT  2.304 30.271 2.697 30.317 ;
     RECT  11.628 29.939 11.754 30.763 ;
     RECT  11.124 30.763 11.754 30.839 ;
     RECT  11.268 30.839 11.754 30.991 ;
     RECT  12.492 29.939 41.598 30.991 ;
     RECT  2.415 30.317 2.697 31.243 ;
     RECT  11.268 30.991 41.598 31.253 ;
     RECT  2.304 31.243 2.697 31.289 ;
     RECT  2.415 31.289 2.697 32.059 ;
     RECT  4.284 25.051 4.626 32.071 ;
     RECT  4.284 32.071 5.022 32.225 ;
     RECT  2.415 32.059 2.79 32.237 ;
     RECT  11.628 31.253 41.598 32.575 ;
     RECT  2.415 32.237 2.697 32.872 ;
     RECT  11.52 32.575 41.598 33.421 ;
     RECT  2.304 32.872 2.697 33.485 ;
     RECT  11.412 33.421 41.598 33.739 ;
     RECT  2.415 33.485 2.697 33.781 ;
     RECT  2.415 33.781 2.79 33.821 ;
     RECT  11.124 33.739 41.598 34.051 ;
     RECT  11.016 34.051 41.598 34.231 ;
     RECT  10.44 34.231 41.598 34.321 ;
     RECT  7.815 2.413 8.097 34.429 ;
     RECT  7.815 34.429 8.478 34.465 ;
     RECT  0.108 28.876 0.846 34.574 ;
     RECT  7.632 34.465 8.478 34.591 ;
     RECT  7.488 34.591 8.478 34.735 ;
     RECT  0.144 34.574 0.846 34.781 ;
     RECT  6.66 34.651 6.678 34.861 ;
     RECT  7.488 34.735 8.622 34.861 ;
     RECT  6.66 34.861 8.622 34.982 ;
     RECT  9.756 34.321 41.598 34.982 ;
     RECT  4.284 32.225 4.302 34.987 ;
     RECT  2.415 33.821 2.697 35.041 ;
     RECT  4.104 34.987 4.302 35.041 ;
     RECT  2.415 35.041 4.302 35.083 ;
     RECT  6.66 34.982 41.598 35.239 ;
     RECT  5.256 32.341 5.274 35.473 ;
     RECT  2.304 35.083 4.302 35.537 ;
     RECT  5.256 35.473 5.382 35.609 ;
     RECT  0.216 34.781 0.846 35.659 ;
     RECT  2.304 35.537 4.158 35.755 ;
     RECT  6.552 35.239 41.598 35.789 ;
     RECT  0.144 35.659 0.846 35.837 ;
     RECT  5.256 35.609 5.31 35.837 ;
     RECT  6.552 35.789 6.57 35.969 ;
     RECT  7.38 35.789 41.598 35.969 ;
     RECT  5.256 35.837 5.274 36.049 ;
     RECT  1.728 35.755 4.158 36.077 ;
     RECT  5.076 36.049 5.274 36.121 ;
     RECT  0.828 35.837 0.846 36.139 ;
     RECT  1.728 36.077 2.79 36.139 ;
     RECT  3.996 36.077 4.158 36.379 ;
     RECT  4.932 36.121 5.274 36.379 ;
     RECT  7.38 35.969 10.638 36.553 ;
     RECT  3.996 36.379 5.274 36.619 ;
     RECT  6.912 36.553 10.638 36.763 ;
     RECT  3.996 36.619 5.31 36.779 ;
     RECT  6.84 36.763 10.638 36.787 ;
     RECT  11.484 35.969 41.598 36.787 ;
     RECT  6.84 36.787 41.598 36.895 ;
     RECT  0.828 36.139 2.79 36.931 ;
     RECT  3.996 36.779 5.274 36.931 ;
     RECT  0.828 36.931 5.274 37.049 ;
     RECT  0.828 37.049 2.697 37.051 ;
     RECT  3.924 37.049 5.274 37.121 ;
     RECT  0.18 37.051 2.697 37.147 ;
     RECT  3.96 37.121 5.274 37.589 ;
     RECT  6.264 36.895 41.598 37.589 ;
     RECT  4.14 37.589 5.274 37.625 ;
     RECT  7.2 37.589 41.598 37.625 ;
     RECT  7.2 37.625 10.854 37.895 ;
     RECT  0.144 37.147 2.697 37.915 ;
     RECT  7.416 37.895 10.854 38.003 ;
     RECT  10.512 38.003 10.854 38.129 ;
     RECT  0.144 37.915 2.754 38.189 ;
     RECT  7.416 38.003 9.63 38.471 ;
     RECT  4.14 37.625 4.158 38.479 ;
     RECT  0.144 38.189 2.697 38.507 ;
     RECT  3.888 38.479 4.158 38.551 ;
     RECT  6.264 37.589 6.282 38.551 ;
     RECT  0.144 38.507 1.17 38.579 ;
     RECT  3.6 38.551 4.158 38.669 ;
     RECT  6.264 38.551 6.606 38.669 ;
     RECT  3.744 38.669 4.158 38.705 ;
     RECT  6.516 38.669 6.606 38.713 ;
     RECT  7.416 38.471 9.378 38.713 ;
     RECT  6.516 38.713 9.378 38.741 ;
     RECT  11.592 37.625 41.598 38.749 ;
     RECT  3.96 38.705 4.158 38.813 ;
     RECT  11.52 38.749 41.598 38.911 ;
     RECT  7.308 38.741 9.378 39.011 ;
     RECT  0.144 38.579 0.846 39.091 ;
     RECT  0.108 39.091 0.846 39.149 ;
     RECT  2.415 38.507 2.697 39.361 ;
     RECT  10.512 38.129 10.53 39.403 ;
     RECT  11.412 38.911 41.598 39.403 ;
     RECT  2.304 39.361 2.697 39.437 ;
     RECT  7.308 39.011 9.27 39.479 ;
     RECT  10.512 39.403 41.598 39.479 ;
     RECT  10.512 39.479 10.89 39.533 ;
     RECT  7.308 39.479 8.838 39.785 ;
     RECT  2.415 39.437 2.697 39.883 ;
     RECT  10.512 39.533 10.854 39.893 ;
     RECT  2.415 39.883 2.862 40.061 ;
     RECT  4.14 38.813 4.158 40.171 ;
     RECT  0.144 39.149 0.846 40.199 ;
     RECT  11.844 39.479 41.598 40.219 ;
     RECT  8.82 39.785 8.838 40.261 ;
     RECT  11.664 40.219 41.598 40.261 ;
     RECT  3.708 40.171 4.158 40.289 ;
     RECT  6.516 38.741 6.534 40.369 ;
     RECT  7.308 39.785 8.097 40.369 ;
     RECT  5.256 37.625 5.274 40.405 ;
     RECT  2.415 40.061 2.79 40.441 ;
     RECT  6.516 40.369 8.097 40.441 ;
     RECT  2.304 40.441 2.79 40.493 ;
     RECT  5.148 40.405 5.274 40.559 ;
     RECT  8.82 40.261 9.162 40.559 ;
     RECT  10.512 39.893 10.53 40.675 ;
     RECT  6.228 40.441 8.097 40.703 ;
     RECT  6.516 40.703 8.097 40.747 ;
     RECT  8.82 40.559 8.838 40.747 ;
     RECT  10.188 40.675 10.53 40.747 ;
     RECT  11.484 40.261 41.598 40.747 ;
     RECT  0.144 40.199 0.342 40.843 ;
     RECT  6.516 40.747 8.838 40.865 ;
     RECT  10.188 40.747 41.598 40.937 ;
     RECT  6.516 40.865 8.19 41.099 ;
     RECT  0.108 40.843 0.342 41.251 ;
     RECT  6.876 41.099 8.19 41.369 ;
     RECT  0.108 41.251 0.522 41.413 ;
     RECT  2.415 40.493 2.79 41.413 ;
     RECT  2.415 41.413 2.862 41.512 ;
     RECT  2.304 41.512 2.862 41.513 ;
     RECT  10.26 40.937 41.598 41.521 ;
     RECT  2.304 41.513 2.697 41.549 ;
     RECT  10.26 41.521 41.67 41.755 ;
     RECT  10.08 41.755 41.67 41.791 ;
     RECT  42.48 41.755 42.498 41.791 ;
     RECT  0.108 41.413 0.558 41.837 ;
     RECT  10.08 41.791 43.002 41.837 ;
     RECT  6.876 41.369 8.097 41.909 ;
     RECT  4.14 40.289 4.158 42.061 ;
     RECT  3.852 42.061 4.158 42.151 ;
     RECT  7.272 41.909 8.097 42.179 ;
     RECT  7.416 42.179 8.097 42.235 ;
     RECT  0.144 41.837 0.558 42.283 ;
     RECT  7.416 42.235 8.19 42.365 ;
     RECT  6.516 41.947 6.534 42.449 ;
     RECT  0.144 42.283 0.63 42.509 ;
     RECT  10.368 41.837 43.002 42.565 ;
     RECT  10.368 42.565 43.254 42.601 ;
     RECT  10.26 42.601 43.434 42.727 ;
     RECT  10.224 42.727 43.434 42.907 ;
     RECT  0.144 42.509 0.378 42.989 ;
     RECT  7.416 42.365 8.097 42.989 ;
     RECT  9.648 42.907 43.434 43.025 ;
     RECT  10.224 43.025 43.434 43.061 ;
     RECT  0.144 42.989 0.234 43.18 ;
     RECT  0.108 43.18 0.234 43.277 ;
     RECT  5.256 40.559 5.274 43.565 ;
     RECT  0.108 43.277 0.198 44.107 ;
     RECT  2.415 41.549 2.697 44.203 ;
     RECT  2.304 44.203 2.697 44.249 ;
     RECT  10.584 43.061 43.434 44.519 ;
     RECT  2.415 44.249 2.697 44.581 ;
     RECT  0.108 44.107 0.27 44.779 ;
     RECT  10.836 44.519 43.434 44.851 ;
     RECT  0.108 44.779 0.342 44.875 ;
     RECT  7.815 42.989 8.097 45.067 ;
     RECT  2.415 44.581 2.79 45.197 ;
     RECT  6.84 44.761 6.858 45.197 ;
     RECT  7.815 45.067 8.19 45.197 ;
     RECT  10.836 44.851 43.578 45.197 ;
     RECT  2.415 45.197 2.697 45.616 ;
     RECT  11.268 45.197 43.578 45.769 ;
     RECT  1.728 45.616 2.697 46.267 ;
     RECT  7.815 45.197 8.097 46.267 ;
     RECT  11.268 45.769 43.65 46.267 ;
     RECT  6.84 46.267 6.858 46.411 ;
     RECT  6.84 46.411 7.038 46.541 ;
     RECT  7.815 46.267 8.118 46.541 ;
     RECT  10.836 46.267 43.65 46.541 ;
     RECT  0.108 44.875 0.594 46.607 ;
     RECT  0.144 46.607 0.594 46.637 ;
     RECT  11.484 46.541 43.65 46.643 ;
     RECT  0.252 46.637 0.594 46.733 ;
     RECT  12.996 46.643 43.65 46.741 ;
     RECT  3.6 42.151 4.158 46.769 ;
     RECT  12.996 46.741 43.722 46.805 ;
     RECT  11.484 46.643 11.502 46.829 ;
     RECT  12.996 46.805 13.497 46.829 ;
     RECT  14.256 46.805 43.722 46.841 ;
     RECT  1.728 46.267 2.826 46.885 ;
     RECT  14.292 46.841 43.722 46.913 ;
     RECT  14.364 46.913 43.722 46.921 ;
     RECT  0.324 46.733 0.594 47.417 ;
     RECT  1.728 46.885 3.294 47.651 ;
     RECT  0.576 47.417 0.594 47.759 ;
     RECT  14.364 46.921 43.758 47.857 ;
     RECT  13.215 46.829 13.497 47.992 ;
     RECT  0.144 48.379 0.198 48.433 ;
     RECT  2.304 47.651 3.294 48.569 ;
     RECT  13.104 47.992 13.497 48.569 ;
     RECT  0.108 48.433 0.198 49.045 ;
     RECT  0.108 49.045 0.27 49.085 ;
     RECT  0.108 49.085 0.126 49.133 ;
     RECT  1.116 49.003 1.134 49.181 ;
     RECT  5.112 49.003 5.13 49.277 ;
     RECT  4.14 46.769 4.158 49.621 ;
     RECT  2.415 48.569 3.294 49.675 ;
     RECT  13.215 48.569 13.497 49.723 ;
     RECT  4.14 49.621 4.302 49.739 ;
     RECT  2.304 49.675 3.294 49.783 ;
     RECT  4.14 49.739 4.158 49.783 ;
     RECT  2.304 49.783 4.158 49.811 ;
     RECT  6.804 49.711 6.822 49.847 ;
     RECT  2.304 49.811 4.014 50.009 ;
     RECT  2.304 50.009 3.906 50.093 ;
     RECT  2.304 50.093 3.798 50.288 ;
     RECT  13.104 49.723 13.497 50.288 ;
     RECT  0.144 49.963 0.162 50.443 ;
     RECT  0.144 50.443 0.27 50.476 ;
     RECT  0.108 50.476 0.27 50.573 ;
     RECT  14.364 47.857 44.046 50.701 ;
     RECT  2.376 50.288 3.798 50.863 ;
     RECT  4.86 50.827 4.878 50.863 ;
     RECT  2.376 50.863 3.906 50.935 ;
     RECT  0.144 50.573 0.27 51.133 ;
     RECT  0.144 51.133 0.558 51.197 ;
     RECT  2.376 50.935 4.05 51.307 ;
     RECT  0.54 51.197 0.558 51.437 ;
     RECT  4.86 50.863 5.166 51.673 ;
     RECT  2.304 51.307 4.05 51.691 ;
     RECT  4.86 51.673 5.346 51.691 ;
     RECT  2.304 51.691 5.346 51.709 ;
     RECT  2.304 51.709 5.418 51.871 ;
     RECT  2.304 51.871 6.066 51.943 ;
     RECT  2.304 51.943 6.246 52.141 ;
     RECT  2.304 52.141 6.498 52.171 ;
     RECT  2.304 52.171 6.57 52.205 ;
     RECT  5.94 52.205 6.57 52.211 ;
     RECT  5.94 52.211 6.498 52.241 ;
     RECT  5.94 52.241 6.102 52.253 ;
     RECT  5.94 52.253 6.066 52.349 ;
     RECT  1.296 52.027 1.314 52.397 ;
     RECT  2.304 52.205 4.734 52.493 ;
     RECT  0.432 52.015 0.45 52.507 ;
     RECT  2.415 52.493 4.734 52.709 ;
     RECT  5.976 52.349 6.066 52.709 ;
     RECT  0.144 52.507 0.45 52.717 ;
     RECT  5.976 52.709 5.994 52.745 ;
     RECT  2.415 52.709 4.158 52.781 ;
     RECT  3.528 52.781 4.158 52.853 ;
     RECT  3.96 52.853 4.158 52.979 ;
     RECT  3.96 52.979 3.978 53.015 ;
     RECT  0.144 52.717 0.558 53.069 ;
     RECT  0.144 53.069 0.522 53.165 ;
     RECT  0.144 53.165 0.486 53.261 ;
     RECT  13.215 50.288 13.497 53.401 ;
     RECT  14.292 50.701 44.046 53.401 ;
     RECT  0.108 53.401 0.126 53.453 ;
     RECT  11.376 53.527 11.394 53.563 ;
     RECT  10.836 53.563 11.394 53.645 ;
     RECT  2.415 52.781 2.697 53.659 ;
     RECT  2.415 53.659 2.79 53.699 ;
     RECT  10.836 53.645 10.962 53.837 ;
     RECT  2.415 53.699 2.697 53.995 ;
     RECT  13.215 53.401 44.046 54.031 ;
     RECT  0.144 54.283 0.162 54.461 ;
     RECT  13.104 54.031 44.046 54.608 ;
     RECT  10.836 53.837 10.854 55.037 ;
     RECT  2.304 53.995 2.697 55.085 ;
     RECT  0.108 54.763 0.126 55.255 ;
     RECT  2.415 55.085 2.697 55.381 ;
     RECT  2.415 55.381 2.79 55.421 ;
     RECT  0.108 55.255 0.234 55.709 ;
     RECT  11.412 55.531 11.538 55.853 ;
     RECT  2.415 55.421 2.697 56.191 ;
     RECT  13.215 54.608 44.046 56.191 ;
     RECT  0.108 55.709 0.198 56.429 ;
     RECT  0.144 56.429 0.198 56.827 ;
     RECT  0.144 56.827 0.27 57.005 ;
     RECT  13.104 56.191 44.046 57.197 ;
     RECT  2.304 56.191 2.697 57.209 ;
     RECT  11.412 55.853 11.43 57.209 ;
     RECT  0.144 57.005 0.198 57.739 ;
     RECT  0.144 57.739 0.27 57.766 ;
     RECT  0.108 57.766 0.27 57.869 ;
     RECT  0.144 57.869 0.198 57.917 ;
     RECT  2.415 57.209 2.697 57.979 ;
     RECT  2.415 57.979 2.79 58.019 ;
     RECT  9.972 56.497 9.99 58.117 ;
     RECT  12.24 56.371 12.258 58.495 ;
     RECT  13.215 57.197 44.046 58.495 ;
     RECT  0.144 57.917 0.162 58.747 ;
     RECT  2.415 58.019 2.697 58.792 ;
     RECT  2.304 58.792 2.697 58.829 ;
     RECT  0.144 58.747 0.198 59.371 ;
     RECT  0.144 59.371 0.342 59.467 ;
     RECT  2.415 58.829 2.697 59.467 ;
     RECT  2.415 59.467 2.898 59.563 ;
     RECT  0.108 59.467 0.522 59.597 ;
     RECT  0.108 59.597 0.342 59.789 ;
     RECT  2.415 59.563 3.006 59.789 ;
     RECT  12.24 58.495 44.046 59.999 ;
     RECT  2.415 59.789 2.697 60.115 ;
     RECT  11.376 60.115 11.394 60.523 ;
     RECT  0.108 59.789 0.234 60.605 ;
     RECT  9.936 58.117 9.99 60.941 ;
     RECT  11.376 60.523 11.97 61.051 ;
     RECT  12.816 59.999 44.046 61.133 ;
     RECT  10.836 61.051 11.97 61.181 ;
     RECT  13.068 61.133 44.046 61.181 ;
     RECT  2.304 60.115 2.697 61.529 ;
     RECT  13.068 61.181 13.554 61.655 ;
     RECT  13.068 61.655 13.497 61.709 ;
     RECT  6.948 61.867 6.966 61.963 ;
     RECT  6.84 61.963 6.966 61.997 ;
     RECT  9.936 60.941 9.954 61.997 ;
     RECT  11.376 61.181 11.97 61.997 ;
     RECT  11.412 61.997 11.97 62.033 ;
     RECT  7.815 46.541 8.097 62.041 ;
     RECT  0.108 60.605 0.198 62.045 ;
     RECT  11.412 62.033 11.934 62.045 ;
     RECT  0.108 62.045 0.162 62.093 ;
     RECT  6.84 61.997 6.858 62.093 ;
     RECT  7.704 62.041 8.097 62.093 ;
     RECT  2.415 61.529 2.697 62.299 ;
     RECT  2.415 62.299 2.79 62.339 ;
     RECT  13.14 61.709 13.497 62.491 ;
     RECT  14.292 61.181 44.046 62.491 ;
     RECT  0.144 62.093 0.162 62.941 ;
     RECT  0.144 62.941 0.234 63.004 ;
     RECT  0.108 63.004 0.234 63.005 ;
     RECT  0.108 63.005 0.198 63.053 ;
     RECT  2.415 62.339 2.697 63.112 ;
     RECT  13.14 62.491 44.046 63.211 ;
     RECT  13.104 63.211 44.046 63.545 ;
     RECT  13.104 63.545 13.497 63.689 ;
     RECT  2.304 63.112 2.697 63.725 ;
     RECT  0.18 63.053 0.198 63.835 ;
     RECT  0.18 63.835 0.27 64.013 ;
     RECT  14.364 63.545 44.046 64.049 ;
     RECT  11.412 62.045 11.682 64.229 ;
     RECT  36.972 64.049 44.046 64.319 ;
     RECT  11.412 64.229 11.43 64.499 ;
     RECT  37.008 64.319 44.046 64.625 ;
     RECT  2.415 63.725 2.697 64.831 ;
     RECT  13.215 63.689 13.497 64.831 ;
     RECT  2.304 64.831 2.697 64.877 ;
     RECT  0.144 64.123 0.162 64.987 ;
     RECT  13.104 64.831 13.497 65.245 ;
     RECT  14.364 64.049 35.982 65.245 ;
     RECT  13.104 65.245 35.982 65.309 ;
     RECT  0.144 64.987 0.234 65.515 ;
     RECT  11.376 65.515 11.394 65.551 ;
     RECT  10.836 65.551 11.394 65.741 ;
     RECT  2.415 64.877 2.697 65.785 ;
     RECT  0.144 65.515 0.558 65.789 ;
     RECT  6.804 65.551 6.822 65.939 ;
     RECT  2.304 65.785 2.697 65.995 ;
     RECT  2.304 65.995 3.222 66.245 ;
     RECT  4.212 66.181 4.23 66.28 ;
     RECT  4.068 66.28 4.23 66.317 ;
     RECT  6.768 66.289 6.786 66.389 ;
     RECT  0.54 65.789 0.558 66.413 ;
     RECT  2.304 66.245 2.697 66.515 ;
     RECT  13.215 65.309 35.982 66.551 ;
     RECT  4.284 66.325 4.302 66.587 ;
     RECT  10.836 65.741 10.854 66.659 ;
     RECT  14.364 66.551 35.982 67.243 ;
     RECT  0.324 67.243 0.342 67.291 ;
     RECT  0.252 67.291 0.342 67.333 ;
     RECT  2.415 66.515 2.697 67.339 ;
     RECT  0.18 67.333 0.342 67.421 ;
     RECT  2.376 67.339 2.697 67.432 ;
     RECT  13.215 66.551 13.497 67.432 ;
     RECT  0.18 67.421 0.198 67.441 ;
     RECT  14.364 67.243 36.054 67.441 ;
     RECT  0.108 67.441 0.198 67.565 ;
     RECT  13.104 67.432 13.497 68.009 ;
     RECT  2.304 67.432 2.697 68.045 ;
     RECT  0.144 67.565 0.198 68.332 ;
     RECT  14.364 67.441 36.27 68.791 ;
     RECT  37.152 64.625 44.046 68.791 ;
     RECT  0.108 68.332 0.198 69.101 ;
     RECT  2.415 68.045 2.697 69.151 ;
     RECT  13.215 68.009 13.497 69.151 ;
     RECT  0.144 69.101 0.198 69.307 ;
     RECT  0.144 69.307 0.234 70.06 ;
     RECT  2.304 69.151 2.697 70.169 ;
     RECT  13.104 69.151 13.497 70.169 ;
     RECT  0.108 70.06 0.234 70.253 ;
     RECT  0.144 70.253 0.234 71.185 ;
     RECT  0.108 71.185 0.234 71.275 ;
     RECT  1.404 69.871 1.422 71.275 ;
     RECT  14.364 68.791 44.046 71.375 ;
     RECT  2.415 70.169 2.697 71.752 ;
     RECT  13.215 70.169 13.497 71.752 ;
     RECT  15.156 71.375 44.046 71.837 ;
     RECT  13.104 71.752 13.497 72.329 ;
     RECT  2.304 71.752 2.697 72.365 ;
     RECT  0.108 71.275 1.422 72.845 ;
     RECT  0.108 72.845 1.17 74.453 ;
     RECT  0.108 74.453 0.918 74.759 ;
     RECT  0.108 74.759 0.846 75.497 ;
     RECT  0.828 75.497 0.846 75.839 ;
     RECT  15.48 71.837 44.046 78.665 ;
     RECT  15.876 78.665 44.046 82.061 ;
     RECT  2.415 72.365 2.697 83.987 ;
     RECT  7.815 62.093 8.097 83.987 ;
     RECT  13.215 72.329 13.497 83.987 ;
     RECT  45.615 2.413 45.897 83.987 ;
     RECT  51.015 2.413 51.297 83.987 ;
     RECT  2.415 83.987 2.505 84.257 ;
     RECT  7.815 83.987 7.905 84.257 ;
     RECT  13.215 83.987 13.305 84.257 ;
     RECT  45.615 83.987 45.705 84.257 ;
     RECT  51.015 83.987 51.105 84.257 ;
     RECT  15.912 82.061 44.046 84.365 ;
     RECT  14.364 71.375 14.382 85.217 ;
     RECT  16.776 84.365 44.046 85.565 ;
     RECT  40.86 85.565 44.046 85.661 ;
     RECT  40.86 85.661 42.03 85.709 ;
     RECT  16.776 85.565 40.086 86.285 ;
     RECT  40.86 85.709 41.166 86.285 ;
     RECT  42.012 85.709 42.03 86.285 ;
     RECT  42.876 85.661 44.046 86.285 ;
     RECT  17.748 86.285 19.998 86.381 ;
     RECT  22.428 86.285 39.006 86.381 ;
    LAYER M4 ;
     RECT  0.06 18.864 0.209 73.32 ;
     RECT  0.209 18.864 0.569 73.128 ;
     RECT  0.569 18.864 2.408 66.312 ;
     RECT  0.569 67.296 2.408 73.128 ;
     RECT  2.408 2.148 2.512 84.252 ;
     RECT  2.512 2.418 2.704 83.982 ;
     RECT  2.704 18.96 4.097 66.312 ;
     RECT  4.097 18.96 4.205 65.784 ;
     RECT  4.205 18.96 4.493 52.056 ;
     RECT  4.493 18.96 5.321 52.008 ;
     RECT  5.321 36.768 5.681 52.008 ;
     RECT  5.929 52.176 6.146 52.248 ;
     RECT  6.146 52.176 6.581 52.2 ;
     RECT  5.321 18.96 6.757 35.256 ;
     RECT  6.757 18.96 7.808 35.784 ;
     RECT  5.681 36.768 7.808 51.192 ;
     RECT  4.205 53.328 7.808 65.784 ;
     RECT  2.704 67.296 7.808 73.128 ;
     RECT  7.808 2.148 7.912 84.252 ;
     RECT  7.912 2.418 8.104 83.982 ;
     RECT  8.104 18.96 9.971 51.192 ;
     RECT  9.971 18.96 11.461 35.352 ;
     RECT  9.971 36.864 11.461 51.192 ;
     RECT  11.461 18.96 13.208 51.192 ;
     RECT  8.104 53.328 13.208 65.784 ;
     RECT  8.104 67.296 13.208 73.128 ;
     RECT  13.208 2.148 13.312 84.252 ;
     RECT  13.312 2.418 13.504 83.982 ;
     RECT  13.504 53.328 13.565 61.416 ;
     RECT  13.565 53.328 13.961 61.176 ;
     RECT  13.504 62.448 14.713 66.168 ;
     RECT  13.504 67.296 14.713 73.128 ;
     RECT  13.961 53.328 14.861 61.032 ;
     RECT  14.861 53.52 15.073 61.032 ;
     RECT  14.713 62.016 15.073 73.128 ;
     RECT  14.965 0.528 15.173 0.552 ;
     RECT  15.173 0.48 15.26 0.552 ;
     RECT  15.073 53.52 15.401 73.128 ;
     RECT  15.685 82.032 15.905 82.056 ;
     RECT  15.857 78.624 15.941 78.648 ;
     RECT  13.504 18.96 16.009 35.256 ;
     RECT  13.504 36.432 16.009 51.192 ;
     RECT  15.401 53.568 16.013 73.128 ;
     RECT  15.781 84.336 16.165 84.36 ;
     RECT  15.973 83.184 16.193 83.208 ;
     RECT  16.165 84.288 16.261 84.36 ;
     RECT  16.013 53.568 16.445 65.784 ;
     RECT  16.261 84.24 16.481 84.36 ;
     RECT  16.445 61.968 16.517 65.784 ;
     RECT  16.009 18.96 16.525 51.192 ;
     RECT  16.357 78.096 16.553 78.12 ;
     RECT  16.525 36.72 16.661 51.192 ;
     RECT  15.253 76.08 16.693 76.104 ;
     RECT  16.549 80.928 16.697 80.952 ;
     RECT  16.525 18.96 16.741 35.736 ;
     RECT  16.693 75.84 16.741 76.104 ;
     RECT  16.741 18.864 16.769 35.736 ;
     RECT  16.645 86.256 16.804 86.28 ;
     RECT  16.517 62.304 16.841 65.784 ;
     RECT  16.769 18.864 16.883 35.256 ;
     RECT  16.013 67.296 16.885 73.128 ;
     RECT  16.597 84.912 16.885 85.224 ;
     RECT  16.804 86.208 16.885 86.28 ;
     RECT  16.741 82.608 16.949 82.632 ;
     RECT  16.661 36.912 17.053 51.192 ;
     RECT  15.26 0.048 17.057 0.552 ;
     RECT  16.883 18.96 17.129 35.256 ;
     RECT  17.125 81.456 17.237 81.48 ;
     RECT  17.057 0.048 17.267 0.456 ;
     RECT  17.161 14.832 17.273 14.856 ;
     RECT  17.317 82.032 17.453 82.056 ;
     RECT  16.885 67.296 17.509 74.088 ;
     RECT  16.885 84.912 17.509 86.28 ;
     RECT  17.509 84.336 17.597 86.28 ;
     RECT  16.841 62.64 17.629 65.784 ;
     RECT  17.629 62.64 17.881 66.12 ;
     RECT  17.509 67.296 17.881 74.136 ;
     RECT  17.597 85.2 17.884 86.28 ;
     RECT  17.881 62.592 17.893 74.136 ;
     RECT  17.053 36.912 17.917 51.96 ;
     RECT  17.917 36.912 17.989 52.008 ;
     RECT  16.741 75.84 18.017 76.488 ;
     RECT  17.893 62.208 18.037 74.136 ;
     RECT  17.884 85.2 18.209 86.328 ;
     RECT  17.557 77.568 18.229 78.12 ;
     RECT  17.989 36.912 18.277 52.056 ;
     RECT  18.241 81.6 18.277 81.624 ;
     RECT  17.267 0.096 18.325 0.456 ;
     RECT  18.229 77.568 18.325 78.216 ;
     RECT  18.277 81.504 18.332 81.624 ;
     RECT  18.277 83.616 18.373 83.784 ;
     RECT  18.277 36.912 18.421 52.296 ;
     RECT  18.325 77.568 18.421 78.504 ;
     RECT  18.325 79.536 18.421 79.56 ;
     RECT  18.421 36.912 18.469 52.488 ;
     RECT  16.445 53.568 18.469 60.984 ;
     RECT  17.665 17.088 18.608 17.112 ;
     RECT  17.129 19.056 18.608 35.256 ;
     RECT  18.469 36.912 18.608 60.984 ;
     RECT  18.037 62.16 18.608 74.136 ;
     RECT  18.017 75.216 18.608 76.488 ;
     RECT  18.421 77.568 18.608 79.56 ;
     RECT  18.332 80.928 18.608 81.624 ;
     RECT  18.373 83.568 18.608 83.784 ;
     RECT  18.209 85.2 18.608 86.28 ;
     RECT  18.608 2.148 18.712 86.28 ;
     RECT  18.325 0.096 18.889 0.552 ;
     RECT  18.712 2.418 18.904 86.28 ;
     RECT  18.904 19.056 18.965 27.48 ;
     RECT  18.904 28.512 18.965 35.352 ;
     RECT  18.904 76.368 19.001 78.648 ;
     RECT  18.904 79.728 19.037 81.624 ;
     RECT  18.904 82.608 19.117 86.28 ;
     RECT  18.904 53.568 19.139 74.136 ;
     RECT  19.117 83.184 19.139 86.28 ;
     RECT  19.139 67.296 19.145 74.136 ;
     RECT  19.139 53.568 19.181 65.832 ;
     RECT  19.037 80.832 19.181 81.624 ;
     RECT  19.139 83.328 19.217 86.28 ;
     RECT  19.217 83.328 19.289 83.736 ;
     RECT  19.181 54.672 19.397 65.832 ;
     RECT  19.001 76.368 19.397 77.496 ;
     RECT  19.397 76.368 19.433 76.392 ;
     RECT  19.001 78.624 19.505 78.648 ;
     RECT  19.181 80.832 19.577 80.856 ;
     RECT  19.397 77.472 19.613 77.496 ;
     RECT  19.289 83.328 19.649 83.64 ;
     RECT  18.889 0.048 19.763 0.552 ;
     RECT  19.397 62.688 19.763 65.832 ;
     RECT  19.037 79.728 19.829 79.848 ;
     RECT  18.965 31.152 19.973 35.352 ;
     RECT  19.397 54.672 20.117 61.56 ;
     RECT  18.965 28.512 20.245 30.168 ;
     RECT  20.101 82.608 20.261 83.208 ;
     RECT  20.261 83.136 20.369 83.208 ;
     RECT  19.763 0.096 20.389 0.552 ;
     RECT  20.369 83.184 20.441 83.208 ;
     RECT  19.181 53.568 20.449 53.592 ;
     RECT  20.389 75.552 20.485 75.576 ;
     RECT  20.485 75.264 20.513 75.576 ;
     RECT  20.245 28.464 20.585 30.168 ;
     RECT  20.117 55.2 20.585 61.56 ;
     RECT  18.965 25.008 20.588 27.48 ;
     RECT  20.585 28.464 20.588 29.4 ;
     RECT  20.585 55.872 20.723 61.56 ;
     RECT  20.513 75.264 20.729 75.288 ;
     RECT  20.245 80.4 20.773 80.424 ;
     RECT  18.904 36.912 20.797 52.488 ;
     RECT  20.389 0.096 20.869 0.648 ;
     RECT  19.217 85.2 20.869 86.28 ;
     RECT  20.869 84.912 20.917 86.28 ;
     RECT  20.797 36.912 21.017 53.112 ;
     RECT  19.763 63.264 21.02 65.832 ;
     RECT  19.973 31.152 21.049 35.256 ;
     RECT  19.145 67.296 21.061 74.04 ;
     RECT  20.773 80.4 21.089 80.952 ;
     RECT  21.017 36.912 21.157 51.24 ;
     RECT  21.061 67.296 21.161 74.088 ;
     RECT  18.965 19.056 21.265 23.88 ;
     RECT  20.588 25.008 21.265 29.4 ;
     RECT  21.017 52.464 21.269 53.112 ;
     RECT  21.269 52.656 21.481 53.112 ;
     RECT  21.049 30.432 21.553 35.256 ;
     RECT  20.869 0.048 21.581 0.648 ;
     RECT  21.481 52.656 21.587 53.4 ;
     RECT  21.157 36.624 21.593 51.24 ;
     RECT  21.581 0.048 21.665 0.792 ;
     RECT  20.723 55.968 21.733 61.56 ;
     RECT  21.733 55.968 21.781 62.184 ;
     RECT  21.265 19.056 21.805 29.4 ;
     RECT  21.553 30.384 21.805 35.256 ;
     RECT  21.593 36.624 21.841 51.192 ;
     RECT  21.841 36.48 21.881 51.192 ;
     RECT  21.781 55.872 21.98 62.184 ;
     RECT  21.02 63.168 21.98 65.832 ;
     RECT  21.517 54.432 22.025 54.456 ;
     RECT  21.98 55.872 22.025 65.832 ;
     RECT  22.025 55.872 22.057 60.984 ;
     RECT  22.025 62.16 22.067 65.832 ;
     RECT  21.089 80.4 22.117 80.424 ;
     RECT  21.587 52.656 22.163 53.16 ;
     RECT  22.163 52.944 22.205 53.16 ;
     RECT  21.805 19.056 22.213 35.256 ;
     RECT  21.829 83.184 22.213 83.208 ;
     RECT  22.213 19.056 22.241 35.352 ;
     RECT  21.881 37.584 22.241 51.192 ;
     RECT  22.117 79.776 22.313 80.424 ;
     RECT  22.381 17.088 22.445 17.112 ;
     RECT  22.213 82.608 22.457 83.208 ;
     RECT  21.161 67.296 22.489 74.04 ;
     RECT  22.457 83.136 22.501 83.208 ;
     RECT  20.917 84.624 22.501 86.28 ;
     RECT  21.841 8.496 22.529 8.52 ;
     RECT  22.445 17.088 22.529 17.208 ;
     RECT  22.241 19.248 22.565 35.352 ;
     RECT  22.489 67.296 22.637 74.664 ;
     RECT  22.501 83.136 22.673 86.28 ;
     RECT  21.665 0.048 22.739 0.696 ;
     RECT  22.529 17.136 22.745 17.16 ;
     RECT  22.673 83.76 22.781 86.28 ;
     RECT  22.067 63.264 22.813 65.832 ;
     RECT  22.637 67.296 22.813 74.04 ;
     RECT  22.565 19.248 22.817 34.968 ;
     RECT  22.813 63.264 22.853 74.04 ;
     RECT  22.853 63.264 22.889 73.896 ;
     RECT  22.313 80.4 22.889 80.424 ;
     RECT  21.881 36.48 22.921 36.6 ;
     RECT  22.241 37.584 22.921 50.952 ;
     RECT  22.921 36.48 22.961 50.952 ;
     RECT  22.205 52.944 22.961 52.968 ;
     RECT  22.837 2.256 23.029 2.28 ;
     RECT  22.057 54.96 23.029 60.984 ;
     RECT  22.739 0.048 23.033 0.648 ;
     RECT  23.077 3.984 23.165 4.008 ;
     RECT  22.781 84.432 23.176 86.28 ;
     RECT  23.033 0.192 23.249 0.648 ;
     RECT  22.981 8.544 23.269 8.568 ;
     RECT  23.176 84.432 23.357 86.328 ;
     RECT  22.817 19.248 23.372 31.8 ;
     RECT  23.345 7.44 23.428 7.464 ;
     RECT  23.029 2.256 23.821 2.856 ;
     RECT  23.165 3.984 23.821 4.056 ;
     RECT  23.249 0.384 23.825 0.648 ;
     RECT  23.357 84.432 23.845 86.232 ;
     RECT  23.372 18.768 23.857 31.8 ;
     RECT  22.817 33.216 23.857 34.968 ;
     RECT  22.961 37.056 23.929 50.952 ;
     RECT  22.067 62.16 23.929 62.184 ;
     RECT  22.889 63.504 23.929 73.896 ;
     RECT  23.821 2.256 24.008 4.056 ;
     RECT  23.428 7.44 24.008 7.512 ;
     RECT  23.269 8.544 24.008 9.144 ;
     RECT  23.569 14.832 24.008 14.856 ;
     RECT  23.569 17.088 24.008 17.112 ;
     RECT  23.857 18.768 24.008 34.968 ;
     RECT  23.893 36.048 24.008 36.072 ;
     RECT  23.929 37.056 24.008 51.24 ;
     RECT  23.929 53.088 24.008 53.112 ;
     RECT  23.029 54.96 24.008 61.032 ;
     RECT  23.929 62.16 24.008 73.896 ;
     RECT  23.845 84.384 24.008 86.232 ;
     RECT  23.825 0.384 24.229 0.552 ;
     RECT  24.229 0.336 24.277 0.552 ;
     RECT  24.008 2.148 24.277 86.232 ;
     RECT  24.277 1.92 24.304 86.232 ;
     RECT  24.304 55.104 24.329 66.072 ;
     RECT  24.304 19.248 24.419 51.24 ;
     RECT  24.304 17.568 24.46 18.216 ;
     RECT  24.304 67.248 24.46 74.856 ;
     RECT  24.277 0.144 24.467 0.552 ;
     RECT  24.304 84.336 24.467 86.232 ;
     RECT  24.304 1.92 24.545 2.04 ;
     RECT  24.545 1.92 24.611 1.944 ;
     RECT  24.304 10.8 24.611 10.92 ;
     RECT  24.467 0.144 24.613 0.456 ;
     RECT  24.467 85.392 24.613 86.232 ;
     RECT  24.611 10.896 24.689 10.92 ;
     RECT  24.613 85.392 24.697 86.28 ;
     RECT  24.613 0.048 24.833 0.456 ;
     RECT  24.419 19.248 24.833 50.904 ;
     RECT  24.833 19.248 24.905 47.208 ;
     RECT  24.304 80.928 24.947 80.952 ;
     RECT  24.329 55.104 24.995 65.784 ;
     RECT  24.995 55.104 25.043 61.416 ;
     RECT  24.833 48.336 25.085 50.904 ;
     RECT  24.304 78.096 25.091 78.12 ;
     RECT  24.304 14.832 25.193 14.856 ;
     RECT  24.905 22.656 25.201 47.208 ;
     RECT  25.201 22.656 25.235 36.648 ;
     RECT  24.46 67.344 25.285 74.856 ;
     RECT  24.467 84.336 25.285 84.36 ;
     RECT  24.905 19.248 25.301 21.24 ;
     RECT  25.085 49.2 25.373 50.904 ;
     RECT  24.304 53.04 25.409 53.976 ;
     RECT  24.833 0.096 25.441 0.456 ;
     RECT  25.409 53.952 25.475 53.976 ;
     RECT  25.043 55.104 25.516 60.744 ;
     RECT  25.381 81.456 25.549 81.48 ;
     RECT  25.235 28.992 25.553 36.648 ;
     RECT  25.516 56.016 25.553 60.744 ;
     RECT  25.549 81.456 25.553 81.72 ;
     RECT  25.553 56.016 25.571 60.456 ;
     RECT  24.46 18.192 25.585 18.216 ;
     RECT  25.301 19.248 25.585 21 ;
     RECT  25.571 56.016 25.589 60.408 ;
     RECT  25.235 22.656 25.597 27.96 ;
     RECT  25.597 24.144 25.625 27.96 ;
     RECT  24.995 62.688 25.657 65.784 ;
     RECT  25.373 49.2 25.661 49.848 ;
     RECT  24.697 85.392 25.661 86.232 ;
     RECT  25.553 28.992 25.667 36.408 ;
     RECT  25.585 18.192 25.669 21 ;
     RECT  25.285 67.344 25.693 75.288 ;
     RECT  25.625 24.144 25.697 27.768 ;
     RECT  25.669 17.616 25.715 21 ;
     RECT  25.441 0.096 25.765 0.552 ;
     RECT  25.285 84.288 25.765 84.36 ;
     RECT  25.765 0.096 25.769 0.648 ;
     RECT  25.667 30.72 25.769 36.408 ;
     RECT  25.657 62.688 25.769 66.168 ;
     RECT  25.715 17.616 25.837 17.64 ;
     RECT  25.765 84.288 25.861 84.648 ;
     RECT  25.837 17.088 25.909 17.64 ;
     RECT  25.333 78.24 25.909 78.648 ;
     RECT  25.697 24.144 25.913 27.384 ;
     RECT  25.553 81.504 25.945 81.72 ;
     RECT  25.769 0.144 25.957 0.648 ;
     RECT  25.861 83.76 25.957 84.648 ;
     RECT  25.693 67.344 25.985 75.48 ;
     RECT  25.861 6.72 26.005 6.744 ;
     RECT  25.945 81.504 26.012 82.68 ;
     RECT  25.985 74.112 26.021 75.48 ;
     RECT  26.005 6.72 26.051 6.84 ;
     RECT  25.769 64.752 26.051 66.168 ;
     RECT  25.957 0.144 26.053 0.696 ;
     RECT  26.012 81.504 26.053 82.728 ;
     RECT  25.957 83.712 26.053 84.648 ;
     RECT  25.661 85.968 26.053 86.232 ;
     RECT  25.597 22.656 26.06 22.824 ;
     RECT  26.051 64.848 26.093 66.168 ;
     RECT  25.909 78.24 26.093 79.224 ;
     RECT  25.373 50.832 26.125 50.904 ;
     RECT  25.909 16.224 26.129 17.64 ;
     RECT  26.093 64.848 26.129 65.016 ;
     RECT  26.093 66.096 26.129 66.168 ;
     RECT  26.129 66.144 26.147 66.168 ;
     RECT  25.769 30.72 26.195 36.264 ;
     RECT  26.053 0.144 26.197 0.792 ;
     RECT  26.195 30.72 26.201 33.24 ;
     RECT  26.195 34.224 26.201 36.264 ;
     RECT  25.769 62.688 26.201 63.288 ;
     RECT  26.201 30.72 26.236 33.144 ;
     RECT  26.021 74.112 26.237 74.856 ;
     RECT  26.051 6.816 26.243 6.84 ;
     RECT  26.197 0.144 26.273 1.704 ;
     RECT  25.589 56.4 26.273 60.408 ;
     RECT  26.273 1.68 26.291 1.704 ;
     RECT  26.236 30.72 26.309 33.096 ;
     RECT  26.125 50.832 26.345 51 ;
     RECT  25.985 67.344 26.345 73.128 ;
     RECT  26.345 50.976 26.417 51 ;
     RECT  26.201 34.224 26.497 34.44 ;
     RECT  26.093 79.2 26.531 79.224 ;
     RECT  26.485 11.952 26.549 11.976 ;
     RECT  26.273 56.4 26.561 60.12 ;
     RECT  26.309 30.72 26.579 32.232 ;
     RECT  26.053 81.504 26.629 84.648 ;
     RECT  26.549 11.424 26.633 11.976 ;
     RECT  26.389 54.72 26.665 54.744 ;
     RECT  26.129 64.992 26.669 65.016 ;
     RECT  26.053 85.968 26.669 86.28 ;
     RECT  26.06 22.32 26.677 22.824 ;
     RECT  25.913 24.144 26.677 27.144 ;
     RECT  25.661 49.488 26.701 49.512 ;
     RECT  25.667 28.992 26.705 29.688 ;
     RECT  26.629 81.504 26.723 84.696 ;
     RECT  26.633 11.952 26.741 11.976 ;
     RECT  26.345 67.872 26.741 73.128 ;
     RECT  26.273 0.144 26.773 0.648 ;
     RECT  25.201 37.728 26.773 47.208 ;
     RECT  26.701 48.96 26.773 49.512 ;
     RECT  26.701 51.792 26.773 51.816 ;
     RECT  26.693 79.248 26.777 80.184 ;
     RECT  26.723 81.504 26.777 82.872 ;
     RECT  26.677 22.32 26.809 27.144 ;
     RECT  26.705 28.992 26.813 29.016 ;
     RECT  26.773 51.792 26.819 52.488 ;
     RECT  26.773 37.632 26.845 47.448 ;
     RECT  26.819 52.464 26.857 52.488 ;
     RECT  26.881 14.832 26.993 14.856 ;
     RECT  26.665 54.72 26.993 55.272 ;
     RECT  25.715 19.2 27.013 21 ;
     RECT  26.809 22.032 27.013 27.144 ;
     RECT  26.773 0.048 27.052 0.648 ;
     RECT  27.013 19.2 27.155 27.144 ;
     RECT  27.155 19.92 27.157 27.144 ;
     RECT  26.845 37.632 27.169 47.928 ;
     RECT  26.773 48.96 27.169 49.608 ;
     RECT  26.723 84.24 27.173 84.696 ;
     RECT  26.777 81.504 27.181 82.68 ;
     RECT  27.181 81.504 27.209 81.528 ;
     RECT  27.173 84.336 27.253 84.696 ;
     RECT  26.579 31.344 27.313 32.232 ;
     RECT  26.777 79.248 27.347 79.272 ;
     RECT  27.253 84.336 27.349 84.936 ;
     RECT  26.669 85.968 27.349 86.232 ;
     RECT  26.129 16.224 27.353 17.448 ;
     RECT  27.353 17.232 27.388 17.448 ;
     RECT  27.205 80.352 27.389 80.376 ;
     RECT  26.561 56.496 27.529 60.12 ;
     RECT  27.313 31.344 27.565 33 ;
     RECT  27.565 31.344 27.589 33.096 ;
     RECT  26.497 34.416 27.644 34.44 ;
     RECT  26.201 35.472 27.644 36.264 ;
     RECT  27.349 84.336 27.685 86.232 ;
     RECT  27.589 31.344 27.731 33.144 ;
     RECT  27.685 84.336 27.779 86.28 ;
     RECT  26.993 55.248 27.781 55.272 ;
     RECT  27.529 56.448 27.781 60.12 ;
     RECT  27.157 19.92 27.821 27.336 ;
     RECT  27.052 0.048 27.827 0.6 ;
     RECT  27.709 29.376 27.875 29.64 ;
     RECT  27.731 31.344 27.875 33.096 ;
     RECT  27.875 29.616 27.877 29.64 ;
     RECT  27.685 17.664 27.893 18.216 ;
     RECT  27.877 29.616 27.923 30.312 ;
     RECT  27.781 55.248 27.923 60.12 ;
     RECT  27.845 79.776 27.929 79.8 ;
     RECT  27.779 84.624 27.929 86.28 ;
     RECT  27.169 37.632 27.997 49.608 ;
     RECT  27.973 50.736 27.997 50.76 ;
     RECT  27.923 56.448 27.997 60.12 ;
     RECT  27.821 19.92 28.037 27.144 ;
     RECT  28.037 25.056 28.067 27.144 ;
     RECT  26.237 74.832 28.069 74.856 ;
     RECT  27.997 37.632 28.109 50.76 ;
     RECT  28.037 19.92 28.145 24.072 ;
     RECT  28.069 10.848 28.181 10.872 ;
     RECT  27.353 16.224 28.181 16.248 ;
     RECT  28.069 52.992 28.181 53.016 ;
     RECT  27.997 56.448 28.249 60.168 ;
     RECT  28.069 74.64 28.289 74.856 ;
     RECT  27.181 82.656 28.289 82.68 ;
     RECT  28.145 20.064 28.307 24.072 ;
     RECT  27.644 34.416 28.501 36.264 ;
     RECT  28.249 56.448 28.537 60.984 ;
     RECT  27.923 55.248 28.573 55.272 ;
     RECT  28.501 66.864 28.573 66.888 ;
     RECT  26.741 68.4 28.573 73.128 ;
     RECT  28.537 53.136 28.609 53.16 ;
     RECT  28.109 48.48 28.753 50.76 ;
     RECT  27.875 32.208 28.789 33.096 ;
     RECT  28.501 34.416 28.789 36.36 ;
     RECT  28.753 48.48 28.789 51.192 ;
     RECT  27.929 85.968 28.801 86.28 ;
     RECT  28.789 48.48 28.825 51.336 ;
     RECT  28.537 56.448 28.885 61.032 ;
     RECT  27.929 84.624 28.897 84.936 ;
     RECT  28.801 85.968 28.897 86.232 ;
     RECT  28.885 56.448 28.933 61.896 ;
     RECT  27.893 17.664 28.969 17.688 ;
     RECT  28.573 66.864 28.969 73.128 ;
     RECT  27.827 0.048 29.029 0.552 ;
     RECT  29.005 1.68 29.041 1.704 ;
     RECT  28.969 17.664 29.077 18.216 ;
     RECT  28.573 54.672 29.077 55.272 ;
     RECT  28.861 65.184 29.077 65.208 ;
     RECT  28.969 66.816 29.077 73.128 ;
     RECT  29.077 65.184 29.113 65.544 ;
     RECT  29.077 17.664 29.125 18.792 ;
     RECT  28.825 48.48 29.125 51.96 ;
     RECT  28.609 53.136 29.125 53.256 ;
     RECT  29.077 54.432 29.125 55.272 ;
     RECT  28.933 56.448 29.125 62.712 ;
     RECT  28.897 84.624 29.125 86.232 ;
     RECT  29.125 17.664 29.149 19.032 ;
     RECT  28.307 20.064 29.149 20.184 ;
     RECT  29.125 48.384 29.185 51.96 ;
     RECT  29.125 53.136 29.185 55.272 ;
     RECT  29.041 1.68 29.267 2.28 ;
     RECT  29.113 65.04 29.329 65.544 ;
     RECT  29.077 66.576 29.329 73.128 ;
     RECT  28.789 32.208 29.365 36.36 ;
     RECT  28.109 37.632 29.365 47.208 ;
     RECT  29.267 1.776 29.408 2.28 ;
     RECT  28.933 3.408 29.408 3.432 ;
     RECT  29.149 17.664 29.408 20.184 ;
     RECT  28.307 21.264 29.408 24.072 ;
     RECT  28.067 25.152 29.408 27.144 ;
     RECT  27.923 30.288 29.408 30.312 ;
     RECT  29.365 32.208 29.408 47.208 ;
     RECT  29.185 48.384 29.408 55.272 ;
     RECT  29.125 56.448 29.408 62.808 ;
     RECT  29.329 65.04 29.408 73.128 ;
     RECT  28.289 74.832 29.408 74.856 ;
     RECT  29.125 84.576 29.408 86.232 ;
     RECT  29.408 1.776 29.555 86.232 ;
     RECT  29.555 2.418 29.704 86.232 ;
     RECT  29.704 84.624 29.747 86.232 ;
     RECT  29.704 25.152 29.765 27.144 ;
     RECT  29.704 39.744 29.801 49.272 ;
     RECT  29.029 0.048 29.837 0.6 ;
     RECT  29.704 65.472 29.837 75.384 ;
     RECT  29.704 56.688 29.881 59.928 ;
     RECT  29.704 33.6 30.017 35.352 ;
     RECT  29.704 36.816 30.125 38.76 ;
     RECT  29.704 61.584 30.125 62.664 ;
     RECT  29.747 85.488 30.131 86.232 ;
     RECT  30.131 85.776 30.178 86.232 ;
     RECT  30.125 36.816 30.179 38.52 ;
     RECT  30.125 62.64 30.197 62.664 ;
     RECT  29.704 76.8 30.197 76.92 ;
     RECT  29.704 51.936 30.233 51.96 ;
     RECT  29.837 65.52 30.412 75.384 ;
     RECT  30.125 61.584 30.457 61.608 ;
     RECT  29.704 78.624 30.467 78.648 ;
     RECT  29.765 25.152 30.521 26.808 ;
     RECT  30.412 65.52 30.521 74.952 ;
     RECT  30.017 34.416 30.629 35.352 ;
     RECT  30.521 67.248 30.659 74.952 ;
     RECT  30.659 67.392 30.707 74.952 ;
     RECT  30.197 76.896 30.737 76.92 ;
     RECT  30.521 25.152 30.773 26.664 ;
     RECT  30.179 37.056 30.809 38.52 ;
     RECT  30.707 67.392 30.809 74.856 ;
     RECT  29.704 54.432 30.841 54.696 ;
     RECT  30.521 65.52 30.853 65.544 ;
     RECT  30.769 82.656 30.853 82.68 ;
     RECT  29.704 21.072 30.913 21.096 ;
     RECT  30.853 82.656 30.989 82.728 ;
     RECT  30.853 64.992 30.995 65.544 ;
     RECT  30.989 82.704 30.997 82.728 ;
     RECT  30.809 67.392 31.061 74.088 ;
     RECT  30.841 53.568 31.093 54.696 ;
     RECT  30.178 85.776 31.141 86.28 ;
     RECT  30.995 65.52 31.169 65.544 ;
     RECT  30.913 21.072 31.187 21.672 ;
     RECT  31.093 53.568 31.201 55.608 ;
     RECT  29.881 56.688 31.201 59.736 ;
     RECT  31.129 31.872 31.213 31.896 ;
     RECT  30.997 82.704 31.235 82.824 ;
     RECT  31.061 67.392 31.241 73.608 ;
     RECT  30.809 37.056 31.277 38.472 ;
     RECT  31.241 67.392 31.283 68.712 ;
     RECT  31.141 85.68 31.283 86.28 ;
     RECT  30.629 34.416 31.309 34.872 ;
     RECT  31.241 69.84 31.313 73.608 ;
     RECT  29.801 39.792 31.331 49.272 ;
     RECT  31.201 23.952 31.345 23.976 ;
     RECT  30.773 25.152 31.345 26.616 ;
     RECT  31.331 39.792 31.349 47.064 ;
     RECT  31.201 53.568 31.379 59.736 ;
     RECT  31.379 54.432 31.381 59.736 ;
     RECT  31.381 54.432 31.385 60.456 ;
     RECT  31.313 69.984 31.385 73.608 ;
     RECT  31.285 63.936 31.477 63.96 ;
     RECT  31.381 14.928 31.529 14.952 ;
     RECT  31.165 52.464 31.571 52.488 ;
     RECT  31.187 21.072 31.601 21.624 ;
     RECT  31.477 63.264 31.669 63.96 ;
     RECT  31.385 54.672 31.673 60.456 ;
     RECT  30.709 19.92 31.709 19.944 ;
     RECT  31.381 50.352 31.709 50.376 ;
     RECT  31.724 18.816 31.765 18.84 ;
     RECT  31.669 27.744 31.781 27.912 ;
     RECT  31.277 37.056 31.817 37.944 ;
     RECT  31.385 70.128 31.817 73.608 ;
     RECT  31.669 63.264 31.841 64.056 ;
     RECT  31.781 27.888 31.859 27.912 ;
     RECT  31.283 85.92 31.889 86.28 ;
     RECT  31.765 2.88 31.907 2.904 ;
     RECT  31.349 39.84 31.955 47.064 ;
     RECT  31.765 18.816 31.957 18.936 ;
     RECT  31.673 54.672 31.961 60.072 ;
     RECT  31.841 62.736 31.993 64.056 ;
     RECT  29.837 0.048 32.053 0.552 ;
     RECT  31.961 54.672 32.195 57.096 ;
     RECT  31.345 23.952 32.209 26.616 ;
     RECT  32.204 76.896 32.245 76.92 ;
     RECT  31.331 48.384 32.281 49.272 ;
     RECT  31.961 58.416 32.285 58.536 ;
     RECT  30.841 35.856 32.291 35.88 ;
     RECT  32.245 76.8 32.291 76.92 ;
     RECT  31.601 21.552 32.387 21.624 ;
     RECT  31.889 85.92 32.387 86.232 ;
     RECT  32.195 55.584 32.429 57.096 ;
     RECT  32.291 76.8 32.429 76.824 ;
     RECT  30.733 30.48 32.435 30.504 ;
     RECT  32.053 0.048 32.461 0.6 ;
     RECT  31.957 18.816 32.461 19.512 ;
     RECT  31.955 39.84 32.465 46.776 ;
     RECT  31.283 68.688 32.497 68.712 ;
     RECT  32.209 23.328 32.533 26.616 ;
     RECT  32.465 39.84 32.537 46.296 ;
     RECT  32.461 18.192 32.545 19.512 ;
     RECT  31.817 70.512 32.569 73.608 ;
     RECT  32.497 68.688 32.588 68.856 ;
     RECT  32.461 0.048 32.609 0.744 ;
     RECT  32.533 23.328 32.645 26.76 ;
     RECT  32.281 48.384 32.677 50.184 ;
     RECT  32.545 19.344 32.723 19.512 ;
     RECT  31.961 59.568 32.725 60.072 ;
     RECT  32.645 23.328 32.749 26.616 ;
     RECT  32.245 82.656 32.773 82.68 ;
     RECT  32.497 85.488 32.78 85.56 ;
     RECT  32.387 21.6 32.785 21.624 ;
     RECT  32.429 55.584 32.789 57.048 ;
     RECT  32.588 68.688 32.857 68.952 ;
     RECT  32.78 85.392 32.867 85.56 ;
     RECT  32.545 18.192 32.869 18.216 ;
     RECT  32.773 82.656 32.897 82.824 ;
     RECT  32.857 53.568 32.941 54.168 ;
     RECT  32.941 53.568 32.963 53.592 ;
     RECT  32.749 23.28 32.969 26.616 ;
     RECT  31.993 62.112 32.972 64.44 ;
     RECT  32.723 19.488 33.011 19.512 ;
     RECT  31.283 67.392 33.037 67.416 ;
     RECT  32.857 68.688 33.037 69.528 ;
     RECT  32.821 30.768 33.041 30.792 ;
     RECT  33.037 67.392 33.073 69.528 ;
     RECT  32.569 70.512 33.073 73.656 ;
     RECT  33.073 67.392 33.145 73.656 ;
     RECT  32.725 59.568 33.157 60.984 ;
     RECT  32.725 75.84 33.181 75.864 ;
     RECT  31.309 34.368 33.203 34.872 ;
     RECT  33.157 58.848 33.253 60.984 ;
     RECT  33.253 58.752 33.301 60.984 ;
     RECT  32.972 62.112 33.301 65.016 ;
     RECT  33.301 58.752 33.325 65.016 ;
     RECT  32.785 21.6 33.395 21.672 ;
     RECT  33.145 67.248 33.397 73.656 ;
     RECT  33.397 66.576 33.401 73.656 ;
     RECT  33.395 21.6 33.491 21.624 ;
     RECT  33.325 58.464 33.539 65.016 ;
     RECT  33.181 75.264 33.541 75.864 ;
     RECT  33.401 66.576 33.581 69.576 ;
     RECT  33.539 59.568 33.617 65.016 ;
     RECT  32.677 48.384 33.635 50.76 ;
     RECT  33.541 74.688 33.635 75.864 ;
     RECT  32.537 41.232 33.649 46.296 ;
     RECT  32.969 23.28 33.653 24.648 ;
     RECT  33.203 34.368 33.689 34.824 ;
     RECT  33.653 23.28 33.721 23.832 ;
     RECT  32.867 85.488 33.733 85.56 ;
     RECT  33.635 74.928 33.757 75.864 ;
     RECT  33.685 76.896 33.757 76.92 ;
     RECT  33.635 50.736 33.788 50.76 ;
     RECT  32.969 25.632 33.793 26.616 ;
     RECT  33.613 37.008 33.793 37.608 ;
     RECT  32.537 39.84 33.793 39.864 ;
     RECT  33.581 66.576 33.797 66.744 ;
     RECT  33.617 59.568 33.82 62.76 ;
     RECT  33.797 66.576 33.827 66.648 ;
     RECT  33.757 74.928 33.833 76.92 ;
     RECT  33.649 41.232 33.901 46.584 ;
     RECT  33.733 85.488 33.901 86.232 ;
     RECT  32.609 0.048 33.905 0.6 ;
     RECT  33.793 25.632 34.001 26.856 ;
     RECT  33.905 0.096 34.045 0.6 ;
     RECT  33.541 1.728 34.045 1.752 ;
     RECT  33.901 29.328 34.069 29.352 ;
     RECT  33.901 41.232 34.081 46.776 ;
     RECT  34.081 41.04 34.117 46.776 ;
     RECT  32.789 55.872 34.117 57.048 ;
     RECT  33.617 64.416 34.117 65.016 ;
     RECT  33.901 85.488 34.117 86.28 ;
     RECT  33.821 53.04 34.189 53.064 ;
     RECT  33.793 39.216 34.225 39.864 ;
     RECT  34.117 41.04 34.225 47.16 ;
     RECT  33.539 58.464 34.261 58.488 ;
     RECT  34.117 64.416 34.333 65.112 ;
     RECT  33.937 66.144 34.333 66.168 ;
     RECT  34.225 39.216 34.357 47.16 ;
     RECT  33.635 48.384 34.357 49.272 ;
     RECT  34.261 78.432 34.364 79.272 ;
     RECT  34.045 0.096 34.477 1.752 ;
     RECT  34.477 0.096 34.501 2.04 ;
     RECT  33.793 37.008 34.513 38.232 ;
     RECT  34.357 39.216 34.513 49.272 ;
     RECT  33.401 70.656 34.597 73.656 ;
     RECT  34.001 25.632 34.621 27.72 ;
     RECT  34.513 37.008 34.621 49.272 ;
     RECT  34.501 0.096 34.657 2.088 ;
     RECT  33.581 67.728 34.693 69.576 ;
     RECT  34.597 70.656 34.693 74.136 ;
     RECT  34.621 83.856 34.693 83.88 ;
     RECT  34.657 0.096 34.808 2.28 ;
     RECT  33.721 22.752 34.808 23.832 ;
     RECT  34.621 25.44 34.808 27.72 ;
     RECT  34.069 29.328 34.808 29.448 ;
     RECT  34.045 30.72 34.808 30.744 ;
     RECT  33.613 33.072 34.808 33.096 ;
     RECT  33.689 34.368 34.808 34.392 ;
     RECT  34.621 36.912 34.808 49.272 ;
     RECT  33.788 50.736 34.808 51.144 ;
     RECT  34.189 52.992 34.808 53.064 ;
     RECT  34.117 55.872 34.808 57.096 ;
     RECT  34.261 58.128 34.808 58.488 ;
     RECT  33.82 59.568 34.808 59.736 ;
     RECT  33.82 61.008 34.808 62.76 ;
     RECT  34.333 64.416 34.808 66.168 ;
     RECT  34.693 67.728 34.808 74.136 ;
     RECT  33.833 75.456 34.808 76.92 ;
     RECT  34.364 78.432 34.808 79.368 ;
     RECT  34.441 81.648 34.808 81.672 ;
     RECT  32.897 82.656 34.808 82.68 ;
     RECT  34.693 83.856 34.808 84.456 ;
     RECT  34.808 0.096 34.946 84.456 ;
     RECT  34.946 0.096 35.029 84.408 ;
     RECT  35.029 0.096 35.104 84.36 ;
     RECT  35.104 51.12 35.219 52.536 ;
     RECT  35.104 56.784 35.219 59.592 ;
     RECT  35.104 82.656 35.219 84.36 ;
     RECT  35.219 82.656 35.237 83.88 ;
     RECT  35.219 52.512 35.273 52.536 ;
     RECT  35.104 33.12 35.309 48.552 ;
     RECT  35.104 29.328 35.315 30.888 ;
     RECT  35.309 33.504 35.315 48.552 ;
     RECT  35.104 78.672 35.315 78.792 ;
     RECT  35.104 28.176 35.353 28.2 ;
     RECT  35.315 29.328 35.353 30.792 ;
     RECT  35.353 29.328 35.381 30.264 ;
     RECT  35.219 56.784 35.381 58.824 ;
     RECT  35.381 30.144 35.389 30.264 ;
     RECT  35.104 68.832 35.411 69.768 ;
     RECT  35.104 71.04 35.459 76.152 ;
     RECT  35.459 71.136 35.489 76.152 ;
     RECT  35.237 82.656 35.507 83.592 ;
     RECT  35.489 71.28 35.525 76.152 ;
     RECT  35.411 68.976 35.603 69.768 ;
     RECT  35.525 71.472 35.603 76.152 ;
     RECT  34.117 85.488 35.603 86.328 ;
     RECT  35.104 0.096 35.605 3.432 ;
     RECT  35.507 82.848 35.651 83.592 ;
     RECT  35.603 71.712 35.699 76.152 ;
     RECT  35.104 66.72 35.777 67.272 ;
     RECT  35.315 34.272 35.795 48.552 ;
     RECT  35.699 75.168 35.795 76.152 ;
     RECT  35.104 25.728 35.813 26.808 ;
     RECT  35.699 71.712 35.891 74.088 ;
     RECT  35.605 0.048 35.993 3.432 ;
     RECT  35.104 17.088 36.029 17.64 ;
     RECT  35.891 72.384 36.029 72.408 ;
     RECT  35.104 14.832 36.101 14.856 ;
     RECT  35.777 67.248 36.109 67.272 ;
     RECT  35.795 34.272 36.131 44.184 ;
     RECT  35.795 45.696 36.169 48.552 ;
     RECT  35.104 49.536 36.169 49.56 ;
     RECT  35.795 75.168 36.173 75.192 ;
     RECT  35.993 0.096 36.179 3.432 ;
     RECT  35.389 30.144 36.227 30.216 ;
     RECT  36.097 32.448 36.227 32.472 ;
     RECT  36.131 34.272 36.227 34.392 ;
     RECT  36.179 2.256 36.275 3.432 ;
     RECT  36.227 30.144 36.323 30.168 ;
     RECT  35.891 74.064 36.353 74.088 ;
     RECT  36.131 35.376 36.371 44.184 ;
     RECT  35.813 26.784 36.389 26.808 ;
     RECT  35.104 9.072 36.419 9.096 ;
     RECT  35.603 85.68 36.467 86.328 ;
     RECT  36.371 35.376 36.497 35.736 ;
     RECT  35.651 83.568 36.497 83.592 ;
     RECT  36.179 0.096 36.563 1.128 ;
     RECT  36.029 17.088 36.611 17.112 ;
     RECT  36.097 5.088 36.637 5.112 ;
     RECT  36.565 21.648 36.673 21.672 ;
     RECT  36.563 0.096 36.677 1.08 ;
     RECT  35.381 57.024 36.709 58.824 ;
     RECT  36.637 82.608 36.749 82.68 ;
     RECT  36.661 54.816 36.757 54.84 ;
     RECT  36.661 62.592 36.757 62.616 ;
     RECT  36.371 37.008 36.781 44.184 ;
     RECT  36.709 57.024 36.781 59.064 ;
     RECT  36.757 54.72 36.803 54.84 ;
     RECT  36.757 62.592 36.803 62.712 ;
     RECT  36.781 56.976 36.821 59.064 ;
     RECT  36.677 0.144 36.893 1.08 ;
     RECT  36.803 54.72 36.899 54.744 ;
     RECT  36.803 62.688 36.899 62.712 ;
     RECT  36.673 21.648 36.947 22.2 ;
     RECT  36.893 0.192 36.995 1.08 ;
     RECT  36.781 37.008 36.997 44.28 ;
     RECT  36.169 45.696 36.997 49.752 ;
     RECT  36.997 37.008 37.043 49.752 ;
     RECT  36.821 56.976 37.069 57.096 ;
     RECT  35.603 69.744 37.069 69.768 ;
     RECT  36.467 85.92 37.109 86.328 ;
     RECT  36.637 4.512 37.138 5.112 ;
     RECT  36.497 35.712 37.145 35.736 ;
     RECT  37.043 45.12 37.217 49.752 ;
     RECT  37.138 4.464 37.235 5.112 ;
     RECT  37.043 37.008 37.261 43.368 ;
     RECT  37.217 48.384 37.289 49.752 ;
     RECT  37.141 7.968 37.331 7.992 ;
     RECT  37.213 81.504 37.331 81.528 ;
     RECT  37.277 84.384 37.361 84.408 ;
     RECT  37.069 68.976 37.379 69.768 ;
     RECT  37.285 30.768 37.397 30.792 ;
     RECT  37.379 69.552 37.477 69.768 ;
     RECT  36.749 82.656 37.477 82.68 ;
     RECT  36.821 58.704 37.501 59.064 ;
     RECT  36.275 2.832 37.523 3.432 ;
     RECT  37.109 85.92 37.525 86.28 ;
     RECT  37.477 82.656 37.621 82.872 ;
     RECT  37.573 23.376 37.657 23.4 ;
     RECT  35.813 25.728 37.681 25.752 ;
     RECT  37.261 37.008 37.685 37.608 ;
     RECT  37.289 48.384 37.708 49.224 ;
     RECT  37.523 3.408 37.715 3.432 ;
     RECT  36.947 22.176 37.753 22.2 ;
     RECT  37.217 45.12 37.757 47.16 ;
     RECT  37.235 4.464 37.811 4.488 ;
     RECT  37.681 25.728 37.825 26.232 ;
     RECT  37.261 38.784 37.829 43.368 ;
     RECT  37.753 22.176 37.901 22.92 ;
     RECT  37.901 22.176 37.907 22.2 ;
     RECT  35.219 51.12 37.909 51.144 ;
     RECT  37.829 38.784 38.009 38.808 ;
     RECT  37.825 25.728 38.045 26.808 ;
     RECT  37.861 30.672 38.045 30.696 ;
     RECT  37.909 54.432 38.053 54.456 ;
     RECT  36.995 0.384 38.077 1.08 ;
     RECT  37.757 46.32 38.081 47.16 ;
     RECT  37.753 29.088 38.099 29.112 ;
     RECT  37.829 40.56 38.099 43.368 ;
     RECT  37.909 50.736 38.099 51.144 ;
     RECT  38.053 53.472 38.099 54.456 ;
     RECT  37.069 56.448 38.149 57.096 ;
     RECT  38.099 53.472 38.153 54.36 ;
     RECT  38.099 50.736 38.189 50.808 ;
     RECT  37.285 32.448 38.195 32.472 ;
     RECT  37.525 85.872 38.204 86.28 ;
     RECT  38.081 46.368 38.225 47.16 ;
     RECT  38.153 54.336 38.253 54.36 ;
     RECT  37.685 37.008 38.261 37.032 ;
     RECT  38.149 55.872 38.261 57.096 ;
     RECT  38.293 74.736 38.377 74.76 ;
     RECT  37.501 58.704 38.401 59.208 ;
     RECT  38.401 58.656 38.473 59.208 ;
     RECT  38.099 41.04 38.477 43.368 ;
     RECT  37.285 78.672 38.483 78.696 ;
     RECT  38.492 84.384 38.579 84.408 ;
     RECT  38.473 50.352 38.585 50.376 ;
     RECT  38.077 0.288 38.588 1.08 ;
     RECT  37.621 82.656 38.609 83.016 ;
     RECT  38.581 68.592 38.617 68.616 ;
     RECT  38.477 41.136 38.621 43.368 ;
     RECT  38.588 0.048 38.675 1.08 ;
     RECT  38.473 58.56 38.693 59.208 ;
     RECT  38.617 67.824 38.693 68.616 ;
     RECT  38.609 82.656 38.693 83.208 ;
     RECT  38.693 67.824 38.701 67.848 ;
     RECT  38.617 72.96 38.723 73.08 ;
     RECT  38.045 25.728 38.725 26.232 ;
     RECT  38.723 73.056 38.771 73.08 ;
     RECT  38.204 85.488 38.771 86.28 ;
     RECT  38.693 58.704 38.773 59.208 ;
     RECT  38.773 58.704 38.819 59.88 ;
     RECT  38.621 41.136 38.867 41.256 ;
     RECT  38.867 41.232 38.945 41.256 ;
     RECT  38.819 58.704 38.945 58.824 ;
     RECT  38.225 46.512 38.977 47.16 ;
     RECT  38.693 82.656 38.981 82.68 ;
     RECT  38.675 0.384 39.017 1.08 ;
     RECT  38.621 42.72 39.017 43.368 ;
     RECT  38.653 23.712 39.049 23.736 ;
     RECT  38.819 59.856 39.197 59.88 ;
     RECT  39.049 23.328 39.203 24.504 ;
     RECT  38.725 25.632 39.229 26.232 ;
     RECT  39.203 24.48 39.301 24.504 ;
     RECT  39.229 25.632 39.301 26.76 ;
     RECT  38.977 46.512 39.349 47.208 ;
     RECT  37.708 48.384 39.349 48.408 ;
     RECT  38.261 55.872 39.349 55.896 ;
     RECT  38.261 57.072 39.349 57.096 ;
     RECT  39.301 24.48 39.445 26.76 ;
     RECT  39.017 42.72 39.769 42.744 ;
     RECT  38.761 44.448 39.841 44.472 ;
     RECT  39.877 84.864 39.949 84.888 ;
     RECT  38.771 86.064 39.949 86.28 ;
     RECT  39.769 42.48 40.057 42.744 ;
     RECT  39.841 43.872 40.129 44.472 ;
     RECT  39.203 23.328 40.208 23.352 ;
     RECT  39.445 24.48 40.208 26.856 ;
     RECT  40.057 42.288 40.208 42.744 ;
     RECT  40.129 43.872 40.208 44.952 ;
     RECT  39.349 46.512 40.208 48.504 ;
     RECT  39.349 55.248 40.208 57.096 ;
     RECT  38.945 58.704 40.208 58.728 ;
     RECT  37.477 69.744 40.208 69.768 ;
     RECT  39.949 84.864 40.208 86.28 ;
     RECT  40.208 2.148 40.312 86.28 ;
     RECT  40.312 2.418 40.504 86.28 ;
     RECT  40.504 48.48 40.601 48.504 ;
     RECT  40.504 57.072 40.643 57.096 ;
     RECT  40.504 44.64 40.78 45.576 ;
     RECT  40.504 41.04 40.781 41.112 ;
     RECT  40.781 41.04 40.853 41.064 ;
     RECT  40.504 38.832 41.033 38.856 ;
     RECT  40.78 44.64 41.033 44.664 ;
     RECT  39.017 0.816 41.075 1.08 ;
     RECT  40.504 69.744 41.075 69.768 ;
     RECT  41.075 0.816 41.171 1.032 ;
     RECT  40.504 58.704 41.171 58.728 ;
     RECT  40.504 25.728 41.219 26.664 ;
     RECT  40.504 84.336 41.219 86.28 ;
     RECT  41.171 0.816 41.321 0.936 ;
     RECT  40.504 61.536 41.393 61.56 ;
     RECT  41.219 84.336 41.465 84.408 ;
     RECT  41.321 0.816 41.501 0.888 ;
     RECT  41.219 25.728 41.507 25.752 ;
     RECT  40.504 42.192 41.537 42.216 ;
     RECT  40.504 46.704 41.605 46.968 ;
     RECT  41.501 0.864 41.609 0.888 ;
     RECT  41.509 72.336 41.609 72.36 ;
     RECT  40.504 74.112 41.609 74.136 ;
     RECT  41.465 84.384 41.651 84.408 ;
     RECT  41.701 82.032 41.825 82.056 ;
     RECT  41.605 46.704 41.852 47.928 ;
     RECT  41.852 46.656 41.897 47.928 ;
     RECT  41.897 46.656 41.939 46.968 ;
     RECT  41.219 85.488 43.955 86.28 ;
     RECT  43.955 86.256 44.057 86.28 ;
     RECT  45.608 2.148 45.712 84.252 ;
     RECT  45.712 2.418 45.904 83.982 ;
     RECT  51.008 2.148 51.112 84.252 ;
     RECT  51.112 2.418 51.304 83.982 ;
    LAYER M5 ;
     RECT  19.92 0.016 38.28 0.037 ;
     RECT  15.312 0.037 17.256 0.229 ;
     RECT  19.392 0.037 38.664 0.421 ;
     RECT  15.312 0.229 18.168 0.469 ;
     RECT  19.296 0.421 38.76 0.469 ;
     RECT  15.216 0.469 38.76 0.517 ;
     RECT  40.608 0.949 40.632 0.997 ;
     RECT  40.608 0.997 41.16 2.137 ;
     RECT  2.4 2.137 2.52 2.151 ;
     RECT  7.8 2.137 7.92 2.151 ;
     RECT  13.2 2.137 13.32 2.151 ;
     RECT  45.6 2.137 45.72 2.151 ;
     RECT  51 2.137 51.12 2.151 ;
     RECT  14.976 0.517 38.76 21.733 ;
     RECT  14.928 21.733 38.76 21.971 ;
     RECT  14.976 21.971 38.76 23.317 ;
     RECT  40.2 2.137 41.16 23.317 ;
     RECT  14.976 23.317 41.16 23.461 ;
     RECT  14.832 23.461 41.16 23.699 ;
     RECT  14.976 23.699 41.16 25.717 ;
     RECT  14.976 25.717 41.496 28.933 ;
     RECT  14.88 28.933 41.496 30.035 ;
     RECT  13.2 2.151 13.512 31.525 ;
     RECT  13.104 31.525 13.512 32.723 ;
     RECT  13.2 32.723 13.512 33.109 ;
     RECT  13.2 33.109 13.608 33.443 ;
     RECT  11.424 29.461 11.448 33.779 ;
     RECT  7.8 2.151 8.112 34.645 ;
     RECT  6.816 34.645 8.112 35.125 ;
     RECT  9.936 35.077 9.96 35.125 ;
     RECT  6.816 35.125 9.96 35.317 ;
     RECT  11.472 35.269 11.496 35.317 ;
     RECT  6.816 35.317 11.496 35.699 ;
     RECT  0.144 35.461 0.168 35.747 ;
     RECT  14.976 30.035 41.496 36.853 ;
     RECT  7.8 35.699 11.496 36.899 ;
     RECT  7.8 36.899 10.344 36.995 ;
     RECT  7.8 36.995 9.96 37.043 ;
     RECT  11.472 36.899 11.496 37.043 ;
     RECT  14.928 36.853 41.496 37.139 ;
     RECT  7.8 37.043 9.672 37.811 ;
     RECT  2.4 2.151 2.712 37.861 ;
     RECT  2.4 37.861 2.808 38.147 ;
     RECT  7.8 37.811 8.112 38.389 ;
     RECT  7.68 38.389 8.112 38.629 ;
     RECT  7.632 38.629 8.112 39.157 ;
     RECT  11.664 37.477 11.688 39.493 ;
     RECT  9.648 37.811 9.672 39.539 ;
     RECT  13.2 33.443 13.512 39.685 ;
     RECT  11.664 39.493 11.976 40.259 ;
     RECT  2.4 38.147 2.712 40.741 ;
     RECT  2.4 40.741 2.808 40.883 ;
     RECT  13.056 39.685 13.512 41.123 ;
     RECT  7.632 39.157 8.232 41.987 ;
     RECT  7.632 41.987 8.112 42.467 ;
     RECT  13.2 41.123 13.512 42.661 ;
     RECT  9.648 41.797 9.672 42.947 ;
     RECT  11.952 40.259 11.976 43.475 ;
     RECT  2.4 40.883 2.712 45.013 ;
     RECT  13.2 42.661 13.608 45.397 ;
     RECT  14.976 37.139 41.496 45.397 ;
     RECT  13.2 45.397 41.496 46.499 ;
     RECT  2.4 45.013 2.808 46.595 ;
     RECT  14.928 46.499 41.496 46.643 ;
     RECT  14.976 46.643 41.496 46.645 ;
     RECT  2.4 46.595 2.712 46.837 ;
     RECT  14.976 46.645 41.928 46.979 ;
     RECT  2.304 46.837 2.712 47.027 ;
     RECT  14.976 46.979 41.64 47.939 ;
     RECT  0.144 48.997 0.168 49.187 ;
     RECT  1.152 48.997 1.176 49.283 ;
     RECT  3.792 49.957 3.816 50.147 ;
     RECT  14.976 47.939 41.496 54.901 ;
     RECT  14.928 54.901 41.496 55.187 ;
     RECT  2.4 47.027 2.712 56.101 ;
     RECT  2.304 56.101 2.712 56.291 ;
     RECT  14.976 55.187 41.496 62.005 ;
     RECT  10.032 61.957 10.056 62.099 ;
     RECT  13.2 46.499 13.512 64.693 ;
     RECT  14.832 62.005 41.496 64.693 ;
     RECT  13.2 64.693 41.496 65.411 ;
     RECT  15.216 65.411 41.496 65.603 ;
     RECT  15.792 65.603 41.496 67.907 ;
     RECT  16.608 67.907 41.496 72.325 ;
     RECT  16.608 72.325 41.544 72.949 ;
     RECT  15.264 71.797 15.288 76.115 ;
     RECT  16.464 72.949 41.544 78.085 ;
     RECT  16.368 78.085 41.544 78.613 ;
     RECT  15.888 78.613 41.544 82.021 ;
     RECT  2.4 56.291 2.712 84.249 ;
     RECT  7.8 42.467 8.112 84.249 ;
     RECT  13.2 65.411 13.512 84.249 ;
     RECT  45.6 2.151 45.912 84.249 ;
     RECT  51 2.151 51.312 84.249 ;
     RECT  2.4 84.249 2.52 84.263 ;
     RECT  7.8 84.249 7.92 84.263 ;
     RECT  13.2 84.249 13.32 84.263 ;
     RECT  45.6 84.249 45.72 84.263 ;
     RECT  51 84.249 51.12 84.263 ;
     RECT  15.696 82.021 41.736 85.477 ;
     RECT  15.696 85.477 43.944 86.245 ;
     RECT  15.696 86.245 44.04 86.352 ;
  END
END ot_qfd_emb_tap
END LIBRARY
